VERSION 5.8 ;
BUSBITCHARS "[]" ;
DIVIDERCHAR "/" ;
UNITS
    DATABASE MICRONS 1000 ;
END UNITS

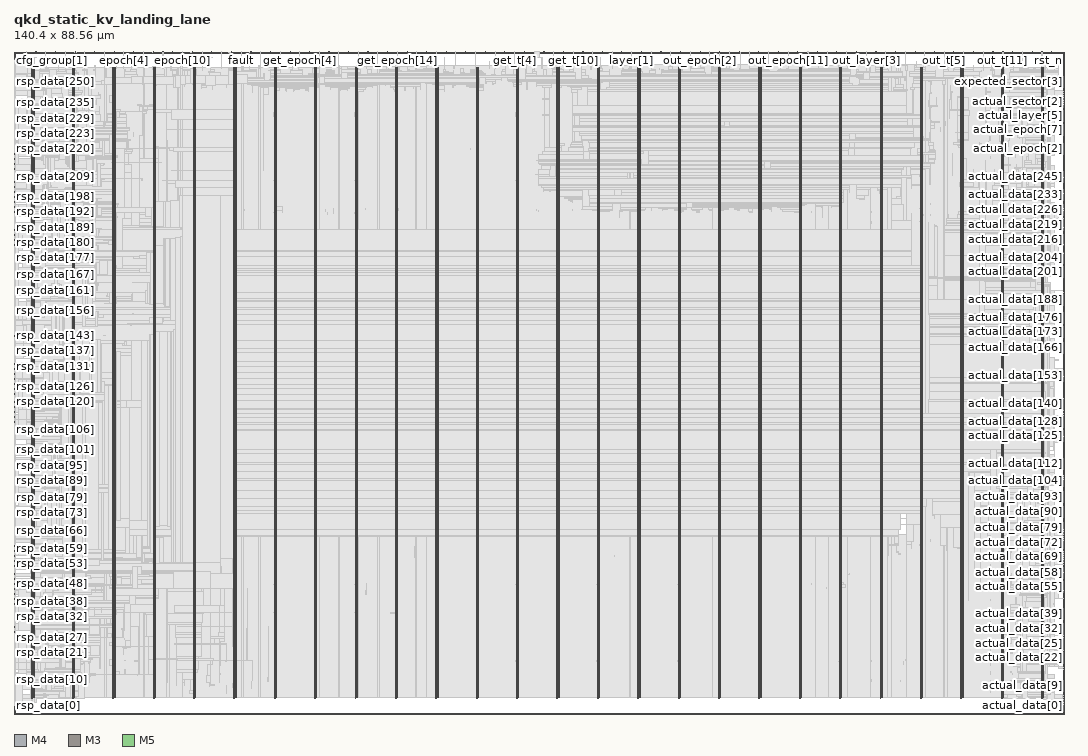
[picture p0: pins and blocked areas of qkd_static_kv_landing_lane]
MACRO qkd_static_kv_landing_lane
  FOREIGN qkd_static_kv_landing_lane 0 0 ;
  CLASS BLOCK ;
  SIZE 140.4 BY 88.56 ;
  PIN actual_data[0]
    DIRECTION INPUT ;
    USE SIGNAL ;
    PORT
      LAYER M4 ;
        RECT  140.316 1.152 140.4 1.176 ;
    END
  END actual_data[0]
  PIN actual_data[100]
    DIRECTION INPUT ;
    USE SIGNAL ;
    PORT
      LAYER M4 ;
        RECT  140.316 30 140.4 30.024 ;
    END
  END actual_data[100]
  PIN actual_data[101]
    DIRECTION INPUT ;
    USE SIGNAL ;
    PORT
      LAYER M4 ;
        RECT  140.316 30.288 140.4 30.312 ;
    END
  END actual_data[101]
  PIN actual_data[102]
    DIRECTION INPUT ;
    USE SIGNAL ;
    PORT
      LAYER M4 ;
        RECT  140.316 30.576 140.4 30.6 ;
    END
  END actual_data[102]
  PIN actual_data[103]
    DIRECTION INPUT ;
    USE SIGNAL ;
    PORT
      LAYER M4 ;
        RECT  140.316 30.864 140.4 30.888 ;
    END
  END actual_data[103]
  PIN actual_data[104]
    DIRECTION INPUT ;
    USE SIGNAL ;
    PORT
      LAYER M4 ;
        RECT  140.316 31.152 140.4 31.176 ;
    END
  END actual_data[104]
  PIN actual_data[105]
    DIRECTION INPUT ;
    USE SIGNAL ;
    PORT
      LAYER M4 ;
        RECT  140.316 31.44 140.4 31.464 ;
    END
  END actual_data[105]
  PIN actual_data[106]
    DIRECTION INPUT ;
    USE SIGNAL ;
    PORT
      LAYER M4 ;
        RECT  140.316 31.728 140.4 31.752 ;
    END
  END actual_data[106]
  PIN actual_data[107]
    DIRECTION INPUT ;
    USE SIGNAL ;
    PORT
      LAYER M4 ;
        RECT  140.316 32.016 140.4 32.04 ;
    END
  END actual_data[107]
  PIN actual_data[108]
    DIRECTION INPUT ;
    USE SIGNAL ;
    PORT
      LAYER M4 ;
        RECT  140.316 32.304 140.4 32.328 ;
    END
  END actual_data[108]
  PIN actual_data[109]
    DIRECTION INPUT ;
    USE SIGNAL ;
    PORT
      LAYER M4 ;
        RECT  140.316 32.592 140.4 32.616 ;
    END
  END actual_data[109]
  PIN actual_data[10]
    DIRECTION INPUT ;
    USE SIGNAL ;
    PORT
      LAYER M4 ;
        RECT  140.316 4.032 140.4 4.056 ;
    END
  END actual_data[10]
  PIN actual_data[110]
    DIRECTION INPUT ;
    USE SIGNAL ;
    PORT
      LAYER M4 ;
        RECT  140.316 32.88 140.4 32.904 ;
    END
  END actual_data[110]
  PIN actual_data[111]
    DIRECTION INPUT ;
    USE SIGNAL ;
    PORT
      LAYER M4 ;
        RECT  140.316 33.168 140.4 33.192 ;
    END
  END actual_data[111]
  PIN actual_data[112]
    DIRECTION INPUT ;
    USE SIGNAL ;
    PORT
      LAYER M4 ;
        RECT  140.316 33.456 140.4 33.48 ;
    END
  END actual_data[112]
  PIN actual_data[113]
    DIRECTION INPUT ;
    USE SIGNAL ;
    PORT
      LAYER M4 ;
        RECT  140.316 33.744 140.4 33.768 ;
    END
  END actual_data[113]
  PIN actual_data[114]
    DIRECTION INPUT ;
    USE SIGNAL ;
    PORT
      LAYER M4 ;
        RECT  140.316 34.032 140.4 34.056 ;
    END
  END actual_data[114]
  PIN actual_data[115]
    DIRECTION INPUT ;
    USE SIGNAL ;
    PORT
      LAYER M4 ;
        RECT  140.316 34.32 140.4 34.344 ;
    END
  END actual_data[115]
  PIN actual_data[116]
    DIRECTION INPUT ;
    USE SIGNAL ;
    PORT
      LAYER M4 ;
        RECT  140.316 34.608 140.4 34.632 ;
    END
  END actual_data[116]
  PIN actual_data[117]
    DIRECTION INPUT ;
    USE SIGNAL ;
    PORT
      LAYER M4 ;
        RECT  140.316 34.896 140.4 34.92 ;
    END
  END actual_data[117]
  PIN actual_data[118]
    DIRECTION INPUT ;
    USE SIGNAL ;
    PORT
      LAYER M4 ;
        RECT  140.316 35.184 140.4 35.208 ;
    END
  END actual_data[118]
  PIN actual_data[119]
    DIRECTION INPUT ;
    USE SIGNAL ;
    PORT
      LAYER M4 ;
        RECT  140.316 35.472 140.4 35.496 ;
    END
  END actual_data[119]
  PIN actual_data[11]
    DIRECTION INPUT ;
    USE SIGNAL ;
    PORT
      LAYER M4 ;
        RECT  140.316 4.32 140.4 4.344 ;
    END
  END actual_data[11]
  PIN actual_data[120]
    DIRECTION INPUT ;
    USE SIGNAL ;
    PORT
      LAYER M4 ;
        RECT  140.316 35.76 140.4 35.784 ;
    END
  END actual_data[120]
  PIN actual_data[121]
    DIRECTION INPUT ;
    USE SIGNAL ;
    PORT
      LAYER M4 ;
        RECT  140.316 36.048 140.4 36.072 ;
    END
  END actual_data[121]
  PIN actual_data[122]
    DIRECTION INPUT ;
    USE SIGNAL ;
    PORT
      LAYER M4 ;
        RECT  140.316 36.336 140.4 36.36 ;
    END
  END actual_data[122]
  PIN actual_data[123]
    DIRECTION INPUT ;
    USE SIGNAL ;
    PORT
      LAYER M4 ;
        RECT  140.316 36.624 140.4 36.648 ;
    END
  END actual_data[123]
  PIN actual_data[124]
    DIRECTION INPUT ;
    USE SIGNAL ;
    PORT
      LAYER M4 ;
        RECT  140.316 36.912 140.4 36.936 ;
    END
  END actual_data[124]
  PIN actual_data[125]
    DIRECTION INPUT ;
    USE SIGNAL ;
    PORT
      LAYER M4 ;
        RECT  140.316 37.2 140.4 37.224 ;
    END
  END actual_data[125]
  PIN actual_data[126]
    DIRECTION INPUT ;
    USE SIGNAL ;
    PORT
      LAYER M4 ;
        RECT  140.316 37.488 140.4 37.512 ;
    END
  END actual_data[126]
  PIN actual_data[127]
    DIRECTION INPUT ;
    USE SIGNAL ;
    PORT
      LAYER M4 ;
        RECT  140.316 37.776 140.4 37.8 ;
    END
  END actual_data[127]
  PIN actual_data[128]
    DIRECTION INPUT ;
    USE SIGNAL ;
    PORT
      LAYER M4 ;
        RECT  140.316 38.064 140.4 38.088 ;
    END
  END actual_data[128]
  PIN actual_data[129]
    DIRECTION INPUT ;
    USE SIGNAL ;
    PORT
      LAYER M4 ;
        RECT  140.316 38.352 140.4 38.376 ;
    END
  END actual_data[129]
  PIN actual_data[12]
    DIRECTION INPUT ;
    USE SIGNAL ;
    PORT
      LAYER M4 ;
        RECT  140.316 4.608 140.4 4.632 ;
    END
  END actual_data[12]
  PIN actual_data[130]
    DIRECTION INPUT ;
    USE SIGNAL ;
    PORT
      LAYER M4 ;
        RECT  140.316 38.64 140.4 38.664 ;
    END
  END actual_data[130]
  PIN actual_data[131]
    DIRECTION INPUT ;
    USE SIGNAL ;
    PORT
      LAYER M4 ;
        RECT  140.316 38.928 140.4 38.952 ;
    END
  END actual_data[131]
  PIN actual_data[132]
    DIRECTION INPUT ;
    USE SIGNAL ;
    PORT
      LAYER M4 ;
        RECT  140.316 39.216 140.4 39.24 ;
    END
  END actual_data[132]
  PIN actual_data[133]
    DIRECTION INPUT ;
    USE SIGNAL ;
    PORT
      LAYER M4 ;
        RECT  140.316 39.504 140.4 39.528 ;
    END
  END actual_data[133]
  PIN actual_data[134]
    DIRECTION INPUT ;
    USE SIGNAL ;
    PORT
      LAYER M4 ;
        RECT  140.316 39.792 140.4 39.816 ;
    END
  END actual_data[134]
  PIN actual_data[135]
    DIRECTION INPUT ;
    USE SIGNAL ;
    PORT
      LAYER M4 ;
        RECT  140.316 40.08 140.4 40.104 ;
    END
  END actual_data[135]
  PIN actual_data[136]
    DIRECTION INPUT ;
    USE SIGNAL ;
    PORT
      LAYER M4 ;
        RECT  140.316 40.368 140.4 40.392 ;
    END
  END actual_data[136]
  PIN actual_data[137]
    DIRECTION INPUT ;
    USE SIGNAL ;
    PORT
      LAYER M4 ;
        RECT  140.316 40.656 140.4 40.68 ;
    END
  END actual_data[137]
  PIN actual_data[138]
    DIRECTION INPUT ;
    USE SIGNAL ;
    PORT
      LAYER M4 ;
        RECT  140.316 40.944 140.4 40.968 ;
    END
  END actual_data[138]
  PIN actual_data[139]
    DIRECTION INPUT ;
    USE SIGNAL ;
    PORT
      LAYER M4 ;
        RECT  140.316 41.232 140.4 41.256 ;
    END
  END actual_data[139]
  PIN actual_data[13]
    DIRECTION INPUT ;
    USE SIGNAL ;
    PORT
      LAYER M4 ;
        RECT  140.316 4.896 140.4 4.92 ;
    END
  END actual_data[13]
  PIN actual_data[140]
    DIRECTION INPUT ;
    USE SIGNAL ;
    PORT
      LAYER M4 ;
        RECT  140.316 41.52 140.4 41.544 ;
    END
  END actual_data[140]
  PIN actual_data[141]
    DIRECTION INPUT ;
    USE SIGNAL ;
    PORT
      LAYER M4 ;
        RECT  140.316 41.808 140.4 41.832 ;
    END
  END actual_data[141]
  PIN actual_data[142]
    DIRECTION INPUT ;
    USE SIGNAL ;
    PORT
      LAYER M4 ;
        RECT  140.316 42.096 140.4 42.12 ;
    END
  END actual_data[142]
  PIN actual_data[143]
    DIRECTION INPUT ;
    USE SIGNAL ;
    PORT
      LAYER M4 ;
        RECT  140.316 42.384 140.4 42.408 ;
    END
  END actual_data[143]
  PIN actual_data[144]
    DIRECTION INPUT ;
    USE SIGNAL ;
    PORT
      LAYER M4 ;
        RECT  140.316 42.672 140.4 42.696 ;
    END
  END actual_data[144]
  PIN actual_data[145]
    DIRECTION INPUT ;
    USE SIGNAL ;
    PORT
      LAYER M4 ;
        RECT  140.316 42.96 140.4 42.984 ;
    END
  END actual_data[145]
  PIN actual_data[146]
    DIRECTION INPUT ;
    USE SIGNAL ;
    PORT
      LAYER M4 ;
        RECT  140.316 43.248 140.4 43.272 ;
    END
  END actual_data[146]
  PIN actual_data[147]
    DIRECTION INPUT ;
    USE SIGNAL ;
    PORT
      LAYER M4 ;
        RECT  140.316 43.536 140.4 43.56 ;
    END
  END actual_data[147]
  PIN actual_data[148]
    DIRECTION INPUT ;
    USE SIGNAL ;
    PORT
      LAYER M4 ;
        RECT  140.316 43.824 140.4 43.848 ;
    END
  END actual_data[148]
  PIN actual_data[149]
    DIRECTION INPUT ;
    USE SIGNAL ;
    PORT
      LAYER M4 ;
        RECT  140.316 44.112 140.4 44.136 ;
    END
  END actual_data[149]
  PIN actual_data[14]
    DIRECTION INPUT ;
    USE SIGNAL ;
    PORT
      LAYER M4 ;
        RECT  140.316 5.184 140.4 5.208 ;
    END
  END actual_data[14]
  PIN actual_data[150]
    DIRECTION INPUT ;
    USE SIGNAL ;
    PORT
      LAYER M4 ;
        RECT  140.316 44.4 140.4 44.424 ;
    END
  END actual_data[150]
  PIN actual_data[151]
    DIRECTION INPUT ;
    USE SIGNAL ;
    PORT
      LAYER M4 ;
        RECT  140.316 44.688 140.4 44.712 ;
    END
  END actual_data[151]
  PIN actual_data[152]
    DIRECTION INPUT ;
    USE SIGNAL ;
    PORT
      LAYER M4 ;
        RECT  140.316 44.976 140.4 45 ;
    END
  END actual_data[152]
  PIN actual_data[153]
    DIRECTION INPUT ;
    USE SIGNAL ;
    PORT
      LAYER M4 ;
        RECT  140.316 45.264 140.4 45.288 ;
    END
  END actual_data[153]
  PIN actual_data[154]
    DIRECTION INPUT ;
    USE SIGNAL ;
    PORT
      LAYER M4 ;
        RECT  140.316 45.552 140.4 45.576 ;
    END
  END actual_data[154]
  PIN actual_data[155]
    DIRECTION INPUT ;
    USE SIGNAL ;
    PORT
      LAYER M4 ;
        RECT  140.316 45.84 140.4 45.864 ;
    END
  END actual_data[155]
  PIN actual_data[156]
    DIRECTION INPUT ;
    USE SIGNAL ;
    PORT
      LAYER M4 ;
        RECT  140.316 46.128 140.4 46.152 ;
    END
  END actual_data[156]
  PIN actual_data[157]
    DIRECTION INPUT ;
    USE SIGNAL ;
    PORT
      LAYER M4 ;
        RECT  140.316 46.416 140.4 46.44 ;
    END
  END actual_data[157]
  PIN actual_data[158]
    DIRECTION INPUT ;
    USE SIGNAL ;
    PORT
      LAYER M4 ;
        RECT  140.316 46.704 140.4 46.728 ;
    END
  END actual_data[158]
  PIN actual_data[159]
    DIRECTION INPUT ;
    USE SIGNAL ;
    PORT
      LAYER M4 ;
        RECT  140.316 46.992 140.4 47.016 ;
    END
  END actual_data[159]
  PIN actual_data[15]
    DIRECTION INPUT ;
    USE SIGNAL ;
    PORT
      LAYER M4 ;
        RECT  140.316 5.472 140.4 5.496 ;
    END
  END actual_data[15]
  PIN actual_data[160]
    DIRECTION INPUT ;
    USE SIGNAL ;
    PORT
      LAYER M4 ;
        RECT  140.316 47.28 140.4 47.304 ;
    END
  END actual_data[160]
  PIN actual_data[161]
    DIRECTION INPUT ;
    USE SIGNAL ;
    PORT
      LAYER M4 ;
        RECT  140.316 47.568 140.4 47.592 ;
    END
  END actual_data[161]
  PIN actual_data[162]
    DIRECTION INPUT ;
    USE SIGNAL ;
    PORT
      LAYER M4 ;
        RECT  140.316 47.856 140.4 47.88 ;
    END
  END actual_data[162]
  PIN actual_data[163]
    DIRECTION INPUT ;
    USE SIGNAL ;
    PORT
      LAYER M4 ;
        RECT  140.316 48.144 140.4 48.168 ;
    END
  END actual_data[163]
  PIN actual_data[164]
    DIRECTION INPUT ;
    USE SIGNAL ;
    PORT
      LAYER M4 ;
        RECT  140.316 48.432 140.4 48.456 ;
    END
  END actual_data[164]
  PIN actual_data[165]
    DIRECTION INPUT ;
    USE SIGNAL ;
    PORT
      LAYER M4 ;
        RECT  140.316 48.72 140.4 48.744 ;
    END
  END actual_data[165]
  PIN actual_data[166]
    DIRECTION INPUT ;
    USE SIGNAL ;
    PORT
      LAYER M4 ;
        RECT  140.316 49.008 140.4 49.032 ;
    END
  END actual_data[166]
  PIN actual_data[167]
    DIRECTION INPUT ;
    USE SIGNAL ;
    PORT
      LAYER M4 ;
        RECT  140.316 49.296 140.4 49.32 ;
    END
  END actual_data[167]
  PIN actual_data[168]
    DIRECTION INPUT ;
    USE SIGNAL ;
    PORT
      LAYER M4 ;
        RECT  140.316 49.584 140.4 49.608 ;
    END
  END actual_data[168]
  PIN actual_data[169]
    DIRECTION INPUT ;
    USE SIGNAL ;
    PORT
      LAYER M4 ;
        RECT  140.316 49.872 140.4 49.896 ;
    END
  END actual_data[169]
  PIN actual_data[16]
    DIRECTION INPUT ;
    USE SIGNAL ;
    PORT
      LAYER M4 ;
        RECT  140.316 5.76 140.4 5.784 ;
    END
  END actual_data[16]
  PIN actual_data[170]
    DIRECTION INPUT ;
    USE SIGNAL ;
    PORT
      LAYER M4 ;
        RECT  140.316 50.16 140.4 50.184 ;
    END
  END actual_data[170]
  PIN actual_data[171]
    DIRECTION INPUT ;
    USE SIGNAL ;
    PORT
      LAYER M4 ;
        RECT  140.316 50.448 140.4 50.472 ;
    END
  END actual_data[171]
  PIN actual_data[172]
    DIRECTION INPUT ;
    USE SIGNAL ;
    PORT
      LAYER M4 ;
        RECT  140.316 50.784 140.4 50.808 ;
    END
  END actual_data[172]
  PIN actual_data[173]
    DIRECTION INPUT ;
    USE SIGNAL ;
    PORT
      LAYER M4 ;
        RECT  140.316 51.072 140.4 51.096 ;
    END
  END actual_data[173]
  PIN actual_data[174]
    DIRECTION INPUT ;
    USE SIGNAL ;
    PORT
      LAYER M4 ;
        RECT  140.316 51.36 140.4 51.384 ;
    END
  END actual_data[174]
  PIN actual_data[175]
    DIRECTION INPUT ;
    USE SIGNAL ;
    PORT
      LAYER M4 ;
        RECT  140.316 51.648 140.4 51.672 ;
    END
  END actual_data[175]
  PIN actual_data[176]
    DIRECTION INPUT ;
    USE SIGNAL ;
    PORT
      LAYER M4 ;
        RECT  140.316 51.936 140.4 51.96 ;
    END
  END actual_data[176]
  PIN actual_data[177]
    DIRECTION INPUT ;
    USE SIGNAL ;
    PORT
      LAYER M4 ;
        RECT  140.316 52.224 140.4 52.248 ;
    END
  END actual_data[177]
  PIN actual_data[178]
    DIRECTION INPUT ;
    USE SIGNAL ;
    PORT
      LAYER M4 ;
        RECT  140.316 52.512 140.4 52.536 ;
    END
  END actual_data[178]
  PIN actual_data[179]
    DIRECTION INPUT ;
    USE SIGNAL ;
    PORT
      LAYER M4 ;
        RECT  140.316 52.8 140.4 52.824 ;
    END
  END actual_data[179]
  PIN actual_data[17]
    DIRECTION INPUT ;
    USE SIGNAL ;
    PORT
      LAYER M4 ;
        RECT  140.316 6.048 140.4 6.072 ;
    END
  END actual_data[17]
  PIN actual_data[180]
    DIRECTION INPUT ;
    USE SIGNAL ;
    PORT
      LAYER M4 ;
        RECT  140.316 53.088 140.4 53.112 ;
    END
  END actual_data[180]
  PIN actual_data[181]
    DIRECTION INPUT ;
    USE SIGNAL ;
    PORT
      LAYER M4 ;
        RECT  140.316 53.376 140.4 53.4 ;
    END
  END actual_data[181]
  PIN actual_data[182]
    DIRECTION INPUT ;
    USE SIGNAL ;
    PORT
      LAYER M4 ;
        RECT  140.316 53.664 140.4 53.688 ;
    END
  END actual_data[182]
  PIN actual_data[183]
    DIRECTION INPUT ;
    USE SIGNAL ;
    PORT
      LAYER M4 ;
        RECT  140.316 53.952 140.4 53.976 ;
    END
  END actual_data[183]
  PIN actual_data[184]
    DIRECTION INPUT ;
    USE SIGNAL ;
    PORT
      LAYER M4 ;
        RECT  140.316 54.24 140.4 54.264 ;
    END
  END actual_data[184]
  PIN actual_data[185]
    DIRECTION INPUT ;
    USE SIGNAL ;
    PORT
      LAYER M4 ;
        RECT  140.316 54.528 140.4 54.552 ;
    END
  END actual_data[185]
  PIN actual_data[186]
    DIRECTION INPUT ;
    USE SIGNAL ;
    PORT
      LAYER M4 ;
        RECT  140.316 54.816 140.4 54.84 ;
    END
  END actual_data[186]
  PIN actual_data[187]
    DIRECTION INPUT ;
    USE SIGNAL ;
    PORT
      LAYER M4 ;
        RECT  140.316 55.104 140.4 55.128 ;
    END
  END actual_data[187]
  PIN actual_data[188]
    DIRECTION INPUT ;
    USE SIGNAL ;
    PORT
      LAYER M4 ;
        RECT  140.316 55.392 140.4 55.416 ;
    END
  END actual_data[188]
  PIN actual_data[189]
    DIRECTION INPUT ;
    USE SIGNAL ;
    PORT
      LAYER M4 ;
        RECT  140.316 55.68 140.4 55.704 ;
    END
  END actual_data[189]
  PIN actual_data[18]
    DIRECTION INPUT ;
    USE SIGNAL ;
    PORT
      LAYER M4 ;
        RECT  140.316 6.336 140.4 6.36 ;
    END
  END actual_data[18]
  PIN actual_data[190]
    DIRECTION INPUT ;
    USE SIGNAL ;
    PORT
      LAYER M4 ;
        RECT  140.316 55.968 140.4 55.992 ;
    END
  END actual_data[190]
  PIN actual_data[191]
    DIRECTION INPUT ;
    USE SIGNAL ;
    PORT
      LAYER M4 ;
        RECT  140.316 56.256 140.4 56.28 ;
    END
  END actual_data[191]
  PIN actual_data[192]
    DIRECTION INPUT ;
    USE SIGNAL ;
    PORT
      LAYER M4 ;
        RECT  140.316 56.544 140.4 56.568 ;
    END
  END actual_data[192]
  PIN actual_data[193]
    DIRECTION INPUT ;
    USE SIGNAL ;
    PORT
      LAYER M4 ;
        RECT  140.316 56.832 140.4 56.856 ;
    END
  END actual_data[193]
  PIN actual_data[194]
    DIRECTION INPUT ;
    USE SIGNAL ;
    PORT
      LAYER M4 ;
        RECT  140.316 57.12 140.4 57.144 ;
    END
  END actual_data[194]
  PIN actual_data[195]
    DIRECTION INPUT ;
    USE SIGNAL ;
    PORT
      LAYER M4 ;
        RECT  140.316 57.408 140.4 57.432 ;
    END
  END actual_data[195]
  PIN actual_data[196]
    DIRECTION INPUT ;
    USE SIGNAL ;
    PORT
      LAYER M4 ;
        RECT  140.316 57.696 140.4 57.72 ;
    END
  END actual_data[196]
  PIN actual_data[197]
    DIRECTION INPUT ;
    USE SIGNAL ;
    PORT
      LAYER M4 ;
        RECT  140.316 57.984 140.4 58.008 ;
    END
  END actual_data[197]
  PIN actual_data[198]
    DIRECTION INPUT ;
    USE SIGNAL ;
    PORT
      LAYER M4 ;
        RECT  140.316 58.272 140.4 58.296 ;
    END
  END actual_data[198]
  PIN actual_data[199]
    DIRECTION INPUT ;
    USE SIGNAL ;
    PORT
      LAYER M4 ;
        RECT  140.316 58.56 140.4 58.584 ;
    END
  END actual_data[199]
  PIN actual_data[19]
    DIRECTION INPUT ;
    USE SIGNAL ;
    PORT
      LAYER M4 ;
        RECT  140.316 6.624 140.4 6.648 ;
    END
  END actual_data[19]
  PIN actual_data[1]
    DIRECTION INPUT ;
    USE SIGNAL ;
    PORT
      LAYER M4 ;
        RECT  140.316 1.44 140.4 1.464 ;
    END
  END actual_data[1]
  PIN actual_data[200]
    DIRECTION INPUT ;
    USE SIGNAL ;
    PORT
      LAYER M4 ;
        RECT  140.316 58.848 140.4 58.872 ;
    END
  END actual_data[200]
  PIN actual_data[201]
    DIRECTION INPUT ;
    USE SIGNAL ;
    PORT
      LAYER M4 ;
        RECT  140.316 59.136 140.4 59.16 ;
    END
  END actual_data[201]
  PIN actual_data[202]
    DIRECTION INPUT ;
    USE SIGNAL ;
    PORT
      LAYER M4 ;
        RECT  140.316 59.424 140.4 59.448 ;
    END
  END actual_data[202]
  PIN actual_data[203]
    DIRECTION INPUT ;
    USE SIGNAL ;
    PORT
      LAYER M4 ;
        RECT  140.316 59.712 140.4 59.736 ;
    END
  END actual_data[203]
  PIN actual_data[204]
    DIRECTION INPUT ;
    USE SIGNAL ;
    PORT
      LAYER M4 ;
        RECT  140.316 60 140.4 60.024 ;
    END
  END actual_data[204]
  PIN actual_data[205]
    DIRECTION INPUT ;
    USE SIGNAL ;
    PORT
      LAYER M4 ;
        RECT  140.316 60.288 140.4 60.312 ;
    END
  END actual_data[205]
  PIN actual_data[206]
    DIRECTION INPUT ;
    USE SIGNAL ;
    PORT
      LAYER M4 ;
        RECT  140.316 60.576 140.4 60.6 ;
    END
  END actual_data[206]
  PIN actual_data[207]
    DIRECTION INPUT ;
    USE SIGNAL ;
    PORT
      LAYER M4 ;
        RECT  140.316 60.864 140.4 60.888 ;
    END
  END actual_data[207]
  PIN actual_data[208]
    DIRECTION INPUT ;
    USE SIGNAL ;
    PORT
      LAYER M4 ;
        RECT  140.316 61.152 140.4 61.176 ;
    END
  END actual_data[208]
  PIN actual_data[209]
    DIRECTION INPUT ;
    USE SIGNAL ;
    PORT
      LAYER M4 ;
        RECT  140.316 61.44 140.4 61.464 ;
    END
  END actual_data[209]
  PIN actual_data[20]
    DIRECTION INPUT ;
    USE SIGNAL ;
    PORT
      LAYER M4 ;
        RECT  140.316 6.912 140.4 6.936 ;
    END
  END actual_data[20]
  PIN actual_data[210]
    DIRECTION INPUT ;
    USE SIGNAL ;
    PORT
      LAYER M4 ;
        RECT  140.316 61.728 140.4 61.752 ;
    END
  END actual_data[210]
  PIN actual_data[211]
    DIRECTION INPUT ;
    USE SIGNAL ;
    PORT
      LAYER M4 ;
        RECT  140.316 62.016 140.4 62.04 ;
    END
  END actual_data[211]
  PIN actual_data[212]
    DIRECTION INPUT ;
    USE SIGNAL ;
    PORT
      LAYER M4 ;
        RECT  140.316 62.304 140.4 62.328 ;
    END
  END actual_data[212]
  PIN actual_data[213]
    DIRECTION INPUT ;
    USE SIGNAL ;
    PORT
      LAYER M4 ;
        RECT  140.316 62.592 140.4 62.616 ;
    END
  END actual_data[213]
  PIN actual_data[214]
    DIRECTION INPUT ;
    USE SIGNAL ;
    PORT
      LAYER M4 ;
        RECT  140.316 62.88 140.4 62.904 ;
    END
  END actual_data[214]
  PIN actual_data[215]
    DIRECTION INPUT ;
    USE SIGNAL ;
    PORT
      LAYER M4 ;
        RECT  140.316 63.168 140.4 63.192 ;
    END
  END actual_data[215]
  PIN actual_data[216]
    DIRECTION INPUT ;
    USE SIGNAL ;
    PORT
      LAYER M4 ;
        RECT  140.316 63.456 140.4 63.48 ;
    END
  END actual_data[216]
  PIN actual_data[217]
    DIRECTION INPUT ;
    USE SIGNAL ;
    PORT
      LAYER M4 ;
        RECT  140.316 63.744 140.4 63.768 ;
    END
  END actual_data[217]
  PIN actual_data[218]
    DIRECTION INPUT ;
    USE SIGNAL ;
    PORT
      LAYER M4 ;
        RECT  140.316 64.032 140.4 64.056 ;
    END
  END actual_data[218]
  PIN actual_data[219]
    DIRECTION INPUT ;
    USE SIGNAL ;
    PORT
      LAYER M4 ;
        RECT  140.316 64.32 140.4 64.344 ;
    END
  END actual_data[219]
  PIN actual_data[21]
    DIRECTION INPUT ;
    USE SIGNAL ;
    PORT
      LAYER M4 ;
        RECT  140.316 7.2 140.4 7.224 ;
    END
  END actual_data[21]
  PIN actual_data[220]
    DIRECTION INPUT ;
    USE SIGNAL ;
    PORT
      LAYER M4 ;
        RECT  140.316 64.608 140.4 64.632 ;
    END
  END actual_data[220]
  PIN actual_data[221]
    DIRECTION INPUT ;
    USE SIGNAL ;
    PORT
      LAYER M4 ;
        RECT  140.316 64.896 140.4 64.92 ;
    END
  END actual_data[221]
  PIN actual_data[222]
    DIRECTION INPUT ;
    USE SIGNAL ;
    PORT
      LAYER M4 ;
        RECT  140.316 65.184 140.4 65.208 ;
    END
  END actual_data[222]
  PIN actual_data[223]
    DIRECTION INPUT ;
    USE SIGNAL ;
    PORT
      LAYER M4 ;
        RECT  140.316 65.472 140.4 65.496 ;
    END
  END actual_data[223]
  PIN actual_data[224]
    DIRECTION INPUT ;
    USE SIGNAL ;
    PORT
      LAYER M4 ;
        RECT  140.316 65.76 140.4 65.784 ;
    END
  END actual_data[224]
  PIN actual_data[225]
    DIRECTION INPUT ;
    USE SIGNAL ;
    PORT
      LAYER M4 ;
        RECT  140.316 66.048 140.4 66.072 ;
    END
  END actual_data[225]
  PIN actual_data[226]
    DIRECTION INPUT ;
    USE SIGNAL ;
    PORT
      LAYER M4 ;
        RECT  140.316 66.336 140.4 66.36 ;
    END
  END actual_data[226]
  PIN actual_data[227]
    DIRECTION INPUT ;
    USE SIGNAL ;
    PORT
      LAYER M4 ;
        RECT  140.316 66.624 140.4 66.648 ;
    END
  END actual_data[227]
  PIN actual_data[228]
    DIRECTION INPUT ;
    USE SIGNAL ;
    PORT
      LAYER M4 ;
        RECT  140.316 66.912 140.4 66.936 ;
    END
  END actual_data[228]
  PIN actual_data[229]
    DIRECTION INPUT ;
    USE SIGNAL ;
    PORT
      LAYER M4 ;
        RECT  140.316 67.2 140.4 67.224 ;
    END
  END actual_data[229]
  PIN actual_data[22]
    DIRECTION INPUT ;
    USE SIGNAL ;
    PORT
      LAYER M4 ;
        RECT  140.316 7.488 140.4 7.512 ;
    END
  END actual_data[22]
  PIN actual_data[230]
    DIRECTION INPUT ;
    USE SIGNAL ;
    PORT
      LAYER M4 ;
        RECT  140.316 67.488 140.4 67.512 ;
    END
  END actual_data[230]
  PIN actual_data[231]
    DIRECTION INPUT ;
    USE SIGNAL ;
    PORT
      LAYER M4 ;
        RECT  140.316 67.776 140.4 67.8 ;
    END
  END actual_data[231]
  PIN actual_data[232]
    DIRECTION INPUT ;
    USE SIGNAL ;
    PORT
      LAYER M4 ;
        RECT  140.316 68.064 140.4 68.088 ;
    END
  END actual_data[232]
  PIN actual_data[233]
    DIRECTION INPUT ;
    USE SIGNAL ;
    PORT
      LAYER M4 ;
        RECT  140.316 68.352 140.4 68.376 ;
    END
  END actual_data[233]
  PIN actual_data[234]
    DIRECTION INPUT ;
    USE SIGNAL ;
    PORT
      LAYER M4 ;
        RECT  140.316 68.64 140.4 68.664 ;
    END
  END actual_data[234]
  PIN actual_data[235]
    DIRECTION INPUT ;
    USE SIGNAL ;
    PORT
      LAYER M4 ;
        RECT  140.316 68.928 140.4 68.952 ;
    END
  END actual_data[235]
  PIN actual_data[236]
    DIRECTION INPUT ;
    USE SIGNAL ;
    PORT
      LAYER M4 ;
        RECT  140.316 69.216 140.4 69.24 ;
    END
  END actual_data[236]
  PIN actual_data[237]
    DIRECTION INPUT ;
    USE SIGNAL ;
    PORT
      LAYER M4 ;
        RECT  140.316 69.504 140.4 69.528 ;
    END
  END actual_data[237]
  PIN actual_data[238]
    DIRECTION INPUT ;
    USE SIGNAL ;
    PORT
      LAYER M4 ;
        RECT  140.316 69.792 140.4 69.816 ;
    END
  END actual_data[238]
  PIN actual_data[239]
    DIRECTION INPUT ;
    USE SIGNAL ;
    PORT
      LAYER M4 ;
        RECT  140.316 70.08 140.4 70.104 ;
    END
  END actual_data[239]
  PIN actual_data[23]
    DIRECTION INPUT ;
    USE SIGNAL ;
    PORT
      LAYER M4 ;
        RECT  140.316 7.776 140.4 7.8 ;
    END
  END actual_data[23]
  PIN actual_data[240]
    DIRECTION INPUT ;
    USE SIGNAL ;
    PORT
      LAYER M4 ;
        RECT  140.316 70.368 140.4 70.392 ;
    END
  END actual_data[240]
  PIN actual_data[241]
    DIRECTION INPUT ;
    USE SIGNAL ;
    PORT
      LAYER M4 ;
        RECT  140.316 70.656 140.4 70.68 ;
    END
  END actual_data[241]
  PIN actual_data[242]
    DIRECTION INPUT ;
    USE SIGNAL ;
    PORT
      LAYER M4 ;
        RECT  140.316 70.944 140.4 70.968 ;
    END
  END actual_data[242]
  PIN actual_data[243]
    DIRECTION INPUT ;
    USE SIGNAL ;
    PORT
      LAYER M4 ;
        RECT  140.316 71.232 140.4 71.256 ;
    END
  END actual_data[243]
  PIN actual_data[244]
    DIRECTION INPUT ;
    USE SIGNAL ;
    PORT
      LAYER M4 ;
        RECT  140.316 71.52 140.4 71.544 ;
    END
  END actual_data[244]
  PIN actual_data[245]
    DIRECTION INPUT ;
    USE SIGNAL ;
    PORT
      LAYER M4 ;
        RECT  140.316 71.808 140.4 71.832 ;
    END
  END actual_data[245]
  PIN actual_data[246]
    DIRECTION INPUT ;
    USE SIGNAL ;
    PORT
      LAYER M4 ;
        RECT  140.316 72.096 140.4 72.12 ;
    END
  END actual_data[246]
  PIN actual_data[247]
    DIRECTION INPUT ;
    USE SIGNAL ;
    PORT
      LAYER M4 ;
        RECT  140.316 72.384 140.4 72.408 ;
    END
  END actual_data[247]
  PIN actual_data[248]
    DIRECTION INPUT ;
    USE SIGNAL ;
    PORT
      LAYER M4 ;
        RECT  140.316 72.672 140.4 72.696 ;
    END
  END actual_data[248]
  PIN actual_data[249]
    DIRECTION INPUT ;
    USE SIGNAL ;
    PORT
      LAYER M4 ;
        RECT  140.316 72.96 140.4 72.984 ;
    END
  END actual_data[249]
  PIN actual_data[24]
    DIRECTION INPUT ;
    USE SIGNAL ;
    PORT
      LAYER M4 ;
        RECT  140.316 8.064 140.4 8.088 ;
    END
  END actual_data[24]
  PIN actual_data[250]
    DIRECTION INPUT ;
    USE SIGNAL ;
    PORT
      LAYER M4 ;
        RECT  140.316 73.248 140.4 73.272 ;
    END
  END actual_data[250]
  PIN actual_data[251]
    DIRECTION INPUT ;
    USE SIGNAL ;
    PORT
      LAYER M4 ;
        RECT  140.316 73.536 140.4 73.56 ;
    END
  END actual_data[251]
  PIN actual_data[252]
    DIRECTION INPUT ;
    USE SIGNAL ;
    PORT
      LAYER M4 ;
        RECT  140.316 73.824 140.4 73.848 ;
    END
  END actual_data[252]
  PIN actual_data[253]
    DIRECTION INPUT ;
    USE SIGNAL ;
    PORT
      LAYER M4 ;
        RECT  140.316 74.112 140.4 74.136 ;
    END
  END actual_data[253]
  PIN actual_data[254]
    DIRECTION INPUT ;
    USE SIGNAL ;
    PORT
      LAYER M4 ;
        RECT  140.316 74.4 140.4 74.424 ;
    END
  END actual_data[254]
  PIN actual_data[255]
    DIRECTION INPUT ;
    USE SIGNAL ;
    PORT
      LAYER M4 ;
        RECT  140.316 74.688 140.4 74.712 ;
    END
  END actual_data[255]
  PIN actual_data[25]
    DIRECTION INPUT ;
    USE SIGNAL ;
    PORT
      LAYER M4 ;
        RECT  140.316 8.352 140.4 8.376 ;
    END
  END actual_data[25]
  PIN actual_data[26]
    DIRECTION INPUT ;
    USE SIGNAL ;
    PORT
      LAYER M4 ;
        RECT  140.316 8.64 140.4 8.664 ;
    END
  END actual_data[26]
  PIN actual_data[27]
    DIRECTION INPUT ;
    USE SIGNAL ;
    PORT
      LAYER M4 ;
        RECT  140.316 8.928 140.4 8.952 ;
    END
  END actual_data[27]
  PIN actual_data[28]
    DIRECTION INPUT ;
    USE SIGNAL ;
    PORT
      LAYER M4 ;
        RECT  140.316 9.216 140.4 9.24 ;
    END
  END actual_data[28]
  PIN actual_data[29]
    DIRECTION INPUT ;
    USE SIGNAL ;
    PORT
      LAYER M4 ;
        RECT  140.316 9.504 140.4 9.528 ;
    END
  END actual_data[29]
  PIN actual_data[2]
    DIRECTION INPUT ;
    USE SIGNAL ;
    PORT
      LAYER M4 ;
        RECT  140.316 1.728 140.4 1.752 ;
    END
  END actual_data[2]
  PIN actual_data[30]
    DIRECTION INPUT ;
    USE SIGNAL ;
    PORT
      LAYER M4 ;
        RECT  140.316 9.792 140.4 9.816 ;
    END
  END actual_data[30]
  PIN actual_data[31]
    DIRECTION INPUT ;
    USE SIGNAL ;
    PORT
      LAYER M4 ;
        RECT  140.316 10.08 140.4 10.104 ;
    END
  END actual_data[31]
  PIN actual_data[32]
    DIRECTION INPUT ;
    USE SIGNAL ;
    PORT
      LAYER M4 ;
        RECT  140.316 10.368 140.4 10.392 ;
    END
  END actual_data[32]
  PIN actual_data[33]
    DIRECTION INPUT ;
    USE SIGNAL ;
    PORT
      LAYER M4 ;
        RECT  140.316 10.656 140.4 10.68 ;
    END
  END actual_data[33]
  PIN actual_data[34]
    DIRECTION INPUT ;
    USE SIGNAL ;
    PORT
      LAYER M4 ;
        RECT  140.316 10.944 140.4 10.968 ;
    END
  END actual_data[34]
  PIN actual_data[35]
    DIRECTION INPUT ;
    USE SIGNAL ;
    PORT
      LAYER M4 ;
        RECT  140.316 11.232 140.4 11.256 ;
    END
  END actual_data[35]
  PIN actual_data[36]
    DIRECTION INPUT ;
    USE SIGNAL ;
    PORT
      LAYER M4 ;
        RECT  140.316 11.52 140.4 11.544 ;
    END
  END actual_data[36]
  PIN actual_data[37]
    DIRECTION INPUT ;
    USE SIGNAL ;
    PORT
      LAYER M4 ;
        RECT  140.316 11.808 140.4 11.832 ;
    END
  END actual_data[37]
  PIN actual_data[38]
    DIRECTION INPUT ;
    USE SIGNAL ;
    PORT
      LAYER M4 ;
        RECT  140.316 12.096 140.4 12.12 ;
    END
  END actual_data[38]
  PIN actual_data[39]
    DIRECTION INPUT ;
    USE SIGNAL ;
    PORT
      LAYER M4 ;
        RECT  140.316 12.384 140.4 12.408 ;
    END
  END actual_data[39]
  PIN actual_data[3]
    DIRECTION INPUT ;
    USE SIGNAL ;
    PORT
      LAYER M4 ;
        RECT  140.316 2.016 140.4 2.04 ;
    END
  END actual_data[3]
  PIN actual_data[40]
    DIRECTION INPUT ;
    USE SIGNAL ;
    PORT
      LAYER M4 ;
        RECT  140.316 12.672 140.4 12.696 ;
    END
  END actual_data[40]
  PIN actual_data[41]
    DIRECTION INPUT ;
    USE SIGNAL ;
    PORT
      LAYER M4 ;
        RECT  140.316 12.96 140.4 12.984 ;
    END
  END actual_data[41]
  PIN actual_data[42]
    DIRECTION INPUT ;
    USE SIGNAL ;
    PORT
      LAYER M4 ;
        RECT  140.316 13.248 140.4 13.272 ;
    END
  END actual_data[42]
  PIN actual_data[43]
    DIRECTION INPUT ;
    USE SIGNAL ;
    PORT
      LAYER M4 ;
        RECT  140.316 13.536 140.4 13.56 ;
    END
  END actual_data[43]
  PIN actual_data[44]
    DIRECTION INPUT ;
    USE SIGNAL ;
    PORT
      LAYER M4 ;
        RECT  140.316 13.824 140.4 13.848 ;
    END
  END actual_data[44]
  PIN actual_data[45]
    DIRECTION INPUT ;
    USE SIGNAL ;
    PORT
      LAYER M4 ;
        RECT  140.316 14.112 140.4 14.136 ;
    END
  END actual_data[45]
  PIN actual_data[46]
    DIRECTION INPUT ;
    USE SIGNAL ;
    PORT
      LAYER M4 ;
        RECT  140.316 14.4 140.4 14.424 ;
    END
  END actual_data[46]
  PIN actual_data[47]
    DIRECTION INPUT ;
    USE SIGNAL ;
    PORT
      LAYER M4 ;
        RECT  140.316 14.688 140.4 14.712 ;
    END
  END actual_data[47]
  PIN actual_data[48]
    DIRECTION INPUT ;
    USE SIGNAL ;
    PORT
      LAYER M4 ;
        RECT  140.316 14.976 140.4 15 ;
    END
  END actual_data[48]
  PIN actual_data[49]
    DIRECTION INPUT ;
    USE SIGNAL ;
    PORT
      LAYER M4 ;
        RECT  140.316 15.264 140.4 15.288 ;
    END
  END actual_data[49]
  PIN actual_data[4]
    DIRECTION INPUT ;
    USE SIGNAL ;
    PORT
      LAYER M4 ;
        RECT  140.316 2.304 140.4 2.328 ;
    END
  END actual_data[4]
  PIN actual_data[50]
    DIRECTION INPUT ;
    USE SIGNAL ;
    PORT
      LAYER M4 ;
        RECT  140.316 15.552 140.4 15.576 ;
    END
  END actual_data[50]
  PIN actual_data[51]
    DIRECTION INPUT ;
    USE SIGNAL ;
    PORT
      LAYER M4 ;
        RECT  140.316 15.84 140.4 15.864 ;
    END
  END actual_data[51]
  PIN actual_data[52]
    DIRECTION INPUT ;
    USE SIGNAL ;
    PORT
      LAYER M4 ;
        RECT  140.316 16.128 140.4 16.152 ;
    END
  END actual_data[52]
  PIN actual_data[53]
    DIRECTION INPUT ;
    USE SIGNAL ;
    PORT
      LAYER M4 ;
        RECT  140.316 16.416 140.4 16.44 ;
    END
  END actual_data[53]
  PIN actual_data[54]
    DIRECTION INPUT ;
    USE SIGNAL ;
    PORT
      LAYER M4 ;
        RECT  140.316 16.704 140.4 16.728 ;
    END
  END actual_data[54]
  PIN actual_data[55]
    DIRECTION INPUT ;
    USE SIGNAL ;
    PORT
      LAYER M4 ;
        RECT  140.316 16.992 140.4 17.016 ;
    END
  END actual_data[55]
  PIN actual_data[56]
    DIRECTION INPUT ;
    USE SIGNAL ;
    PORT
      LAYER M4 ;
        RECT  140.316 17.28 140.4 17.304 ;
    END
  END actual_data[56]
  PIN actual_data[57]
    DIRECTION INPUT ;
    USE SIGNAL ;
    PORT
      LAYER M4 ;
        RECT  140.316 17.568 140.4 17.592 ;
    END
  END actual_data[57]
  PIN actual_data[58]
    DIRECTION INPUT ;
    USE SIGNAL ;
    PORT
      LAYER M4 ;
        RECT  140.316 17.856 140.4 17.88 ;
    END
  END actual_data[58]
  PIN actual_data[59]
    DIRECTION INPUT ;
    USE SIGNAL ;
    PORT
      LAYER M4 ;
        RECT  140.316 18.144 140.4 18.168 ;
    END
  END actual_data[59]
  PIN actual_data[5]
    DIRECTION INPUT ;
    USE SIGNAL ;
    PORT
      LAYER M4 ;
        RECT  140.316 2.592 140.4 2.616 ;
    END
  END actual_data[5]
  PIN actual_data[60]
    DIRECTION INPUT ;
    USE SIGNAL ;
    PORT
      LAYER M4 ;
        RECT  140.316 18.432 140.4 18.456 ;
    END
  END actual_data[60]
  PIN actual_data[61]
    DIRECTION INPUT ;
    USE SIGNAL ;
    PORT
      LAYER M4 ;
        RECT  140.316 18.72 140.4 18.744 ;
    END
  END actual_data[61]
  PIN actual_data[62]
    DIRECTION INPUT ;
    USE SIGNAL ;
    PORT
      LAYER M4 ;
        RECT  140.316 19.008 140.4 19.032 ;
    END
  END actual_data[62]
  PIN actual_data[63]
    DIRECTION INPUT ;
    USE SIGNAL ;
    PORT
      LAYER M4 ;
        RECT  140.316 19.296 140.4 19.32 ;
    END
  END actual_data[63]
  PIN actual_data[64]
    DIRECTION INPUT ;
    USE SIGNAL ;
    PORT
      LAYER M4 ;
        RECT  140.316 19.584 140.4 19.608 ;
    END
  END actual_data[64]
  PIN actual_data[65]
    DIRECTION INPUT ;
    USE SIGNAL ;
    PORT
      LAYER M4 ;
        RECT  140.316 19.872 140.4 19.896 ;
    END
  END actual_data[65]
  PIN actual_data[66]
    DIRECTION INPUT ;
    USE SIGNAL ;
    PORT
      LAYER M4 ;
        RECT  140.316 20.16 140.4 20.184 ;
    END
  END actual_data[66]
  PIN actual_data[67]
    DIRECTION INPUT ;
    USE SIGNAL ;
    PORT
      LAYER M4 ;
        RECT  140.316 20.448 140.4 20.472 ;
    END
  END actual_data[67]
  PIN actual_data[68]
    DIRECTION INPUT ;
    USE SIGNAL ;
    PORT
      LAYER M4 ;
        RECT  140.316 20.736 140.4 20.76 ;
    END
  END actual_data[68]
  PIN actual_data[69]
    DIRECTION INPUT ;
    USE SIGNAL ;
    PORT
      LAYER M4 ;
        RECT  140.316 21.024 140.4 21.048 ;
    END
  END actual_data[69]
  PIN actual_data[6]
    DIRECTION INPUT ;
    USE SIGNAL ;
    PORT
      LAYER M4 ;
        RECT  140.316 2.88 140.4 2.904 ;
    END
  END actual_data[6]
  PIN actual_data[70]
    DIRECTION INPUT ;
    USE SIGNAL ;
    PORT
      LAYER M4 ;
        RECT  140.316 21.312 140.4 21.336 ;
    END
  END actual_data[70]
  PIN actual_data[71]
    DIRECTION INPUT ;
    USE SIGNAL ;
    PORT
      LAYER M4 ;
        RECT  140.316 21.6 140.4 21.624 ;
    END
  END actual_data[71]
  PIN actual_data[72]
    DIRECTION INPUT ;
    USE SIGNAL ;
    PORT
      LAYER M4 ;
        RECT  140.316 21.888 140.4 21.912 ;
    END
  END actual_data[72]
  PIN actual_data[73]
    DIRECTION INPUT ;
    USE SIGNAL ;
    PORT
      LAYER M4 ;
        RECT  140.316 22.176 140.4 22.2 ;
    END
  END actual_data[73]
  PIN actual_data[74]
    DIRECTION INPUT ;
    USE SIGNAL ;
    PORT
      LAYER M4 ;
        RECT  140.316 22.464 140.4 22.488 ;
    END
  END actual_data[74]
  PIN actual_data[75]
    DIRECTION INPUT ;
    USE SIGNAL ;
    PORT
      LAYER M4 ;
        RECT  140.316 22.752 140.4 22.776 ;
    END
  END actual_data[75]
  PIN actual_data[76]
    DIRECTION INPUT ;
    USE SIGNAL ;
    PORT
      LAYER M4 ;
        RECT  140.316 23.04 140.4 23.064 ;
    END
  END actual_data[76]
  PIN actual_data[77]
    DIRECTION INPUT ;
    USE SIGNAL ;
    PORT
      LAYER M4 ;
        RECT  140.316 23.328 140.4 23.352 ;
    END
  END actual_data[77]
  PIN actual_data[78]
    DIRECTION INPUT ;
    USE SIGNAL ;
    PORT
      LAYER M4 ;
        RECT  140.316 23.616 140.4 23.64 ;
    END
  END actual_data[78]
  PIN actual_data[79]
    DIRECTION INPUT ;
    USE SIGNAL ;
    PORT
      LAYER M4 ;
        RECT  140.316 23.904 140.4 23.928 ;
    END
  END actual_data[79]
  PIN actual_data[7]
    DIRECTION INPUT ;
    USE SIGNAL ;
    PORT
      LAYER M4 ;
        RECT  140.316 3.168 140.4 3.192 ;
    END
  END actual_data[7]
  PIN actual_data[80]
    DIRECTION INPUT ;
    USE SIGNAL ;
    PORT
      LAYER M4 ;
        RECT  140.316 24.192 140.4 24.216 ;
    END
  END actual_data[80]
  PIN actual_data[81]
    DIRECTION INPUT ;
    USE SIGNAL ;
    PORT
      LAYER M4 ;
        RECT  140.316 24.48 140.4 24.504 ;
    END
  END actual_data[81]
  PIN actual_data[82]
    DIRECTION INPUT ;
    USE SIGNAL ;
    PORT
      LAYER M4 ;
        RECT  140.316 24.816 140.4 24.84 ;
    END
  END actual_data[82]
  PIN actual_data[83]
    DIRECTION INPUT ;
    USE SIGNAL ;
    PORT
      LAYER M4 ;
        RECT  140.316 25.104 140.4 25.128 ;
    END
  END actual_data[83]
  PIN actual_data[84]
    DIRECTION INPUT ;
    USE SIGNAL ;
    PORT
      LAYER M4 ;
        RECT  140.316 25.392 140.4 25.416 ;
    END
  END actual_data[84]
  PIN actual_data[85]
    DIRECTION INPUT ;
    USE SIGNAL ;
    PORT
      LAYER M4 ;
        RECT  140.316 25.68 140.4 25.704 ;
    END
  END actual_data[85]
  PIN actual_data[86]
    DIRECTION INPUT ;
    USE SIGNAL ;
    PORT
      LAYER M4 ;
        RECT  140.316 25.968 140.4 25.992 ;
    END
  END actual_data[86]
  PIN actual_data[87]
    DIRECTION INPUT ;
    USE SIGNAL ;
    PORT
      LAYER M4 ;
        RECT  140.316 26.256 140.4 26.28 ;
    END
  END actual_data[87]
  PIN actual_data[88]
    DIRECTION INPUT ;
    USE SIGNAL ;
    PORT
      LAYER M4 ;
        RECT  140.316 26.544 140.4 26.568 ;
    END
  END actual_data[88]
  PIN actual_data[89]
    DIRECTION INPUT ;
    USE SIGNAL ;
    PORT
      LAYER M4 ;
        RECT  140.316 26.832 140.4 26.856 ;
    END
  END actual_data[89]
  PIN actual_data[8]
    DIRECTION INPUT ;
    USE SIGNAL ;
    PORT
      LAYER M4 ;
        RECT  140.316 3.456 140.4 3.48 ;
    END
  END actual_data[8]
  PIN actual_data[90]
    DIRECTION INPUT ;
    USE SIGNAL ;
    PORT
      LAYER M4 ;
        RECT  140.316 27.12 140.4 27.144 ;
    END
  END actual_data[90]
  PIN actual_data[91]
    DIRECTION INPUT ;
    USE SIGNAL ;
    PORT
      LAYER M4 ;
        RECT  140.316 27.408 140.4 27.432 ;
    END
  END actual_data[91]
  PIN actual_data[92]
    DIRECTION INPUT ;
    USE SIGNAL ;
    PORT
      LAYER M4 ;
        RECT  140.316 27.696 140.4 27.72 ;
    END
  END actual_data[92]
  PIN actual_data[93]
    DIRECTION INPUT ;
    USE SIGNAL ;
    PORT
      LAYER M4 ;
        RECT  140.316 27.984 140.4 28.008 ;
    END
  END actual_data[93]
  PIN actual_data[94]
    DIRECTION INPUT ;
    USE SIGNAL ;
    PORT
      LAYER M4 ;
        RECT  140.316 28.272 140.4 28.296 ;
    END
  END actual_data[94]
  PIN actual_data[95]
    DIRECTION INPUT ;
    USE SIGNAL ;
    PORT
      LAYER M4 ;
        RECT  140.316 28.56 140.4 28.584 ;
    END
  END actual_data[95]
  PIN actual_data[96]
    DIRECTION INPUT ;
    USE SIGNAL ;
    PORT
      LAYER M4 ;
        RECT  140.316 28.848 140.4 28.872 ;
    END
  END actual_data[96]
  PIN actual_data[97]
    DIRECTION INPUT ;
    USE SIGNAL ;
    PORT
      LAYER M4 ;
        RECT  140.316 29.136 140.4 29.16 ;
    END
  END actual_data[97]
  PIN actual_data[98]
    DIRECTION INPUT ;
    USE SIGNAL ;
    PORT
      LAYER M4 ;
        RECT  140.316 29.424 140.4 29.448 ;
    END
  END actual_data[98]
  PIN actual_data[99]
    DIRECTION INPUT ;
    USE SIGNAL ;
    PORT
      LAYER M4 ;
        RECT  140.316 29.712 140.4 29.736 ;
    END
  END actual_data[99]
  PIN actual_data[9]
    DIRECTION INPUT ;
    USE SIGNAL ;
    PORT
      LAYER M4 ;
        RECT  140.316 3.744 140.4 3.768 ;
    END
  END actual_data[9]
  PIN actual_epoch[0]
    DIRECTION INPUT ;
    USE SIGNAL ;
    PORT
      LAYER M4 ;
        RECT  140.316 74.976 140.4 75 ;
    END
  END actual_epoch[0]
  PIN actual_epoch[10]
    DIRECTION INPUT ;
    USE SIGNAL ;
    PORT
      LAYER M4 ;
        RECT  140.316 77.904 140.4 77.928 ;
    END
  END actual_epoch[10]
  PIN actual_epoch[11]
    DIRECTION INPUT ;
    USE SIGNAL ;
    PORT
      LAYER M4 ;
        RECT  140.316 78.192 140.4 78.216 ;
    END
  END actual_epoch[11]
  PIN actual_epoch[12]
    DIRECTION INPUT ;
    USE SIGNAL ;
    PORT
      LAYER M4 ;
        RECT  140.316 78.48 140.4 78.504 ;
    END
  END actual_epoch[12]
  PIN actual_epoch[13]
    DIRECTION INPUT ;
    USE SIGNAL ;
    PORT
      LAYER M4 ;
        RECT  140.316 78.768 140.4 78.792 ;
    END
  END actual_epoch[13]
  PIN actual_epoch[14]
    DIRECTION INPUT ;
    USE SIGNAL ;
    PORT
      LAYER M4 ;
        RECT  140.316 79.056 140.4 79.08 ;
    END
  END actual_epoch[14]
  PIN actual_epoch[15]
    DIRECTION INPUT ;
    USE SIGNAL ;
    PORT
      LAYER M4 ;
        RECT  140.316 79.344 140.4 79.368 ;
    END
  END actual_epoch[15]
  PIN actual_epoch[1]
    DIRECTION INPUT ;
    USE SIGNAL ;
    PORT
      LAYER M4 ;
        RECT  140.316 75.264 140.4 75.288 ;
    END
  END actual_epoch[1]
  PIN actual_epoch[2]
    DIRECTION INPUT ;
    USE SIGNAL ;
    PORT
      LAYER M4 ;
        RECT  140.316 75.552 140.4 75.576 ;
    END
  END actual_epoch[2]
  PIN actual_epoch[3]
    DIRECTION INPUT ;
    USE SIGNAL ;
    PORT
      LAYER M4 ;
        RECT  140.316 75.84 140.4 75.864 ;
    END
  END actual_epoch[3]
  PIN actual_epoch[4]
    DIRECTION INPUT ;
    USE SIGNAL ;
    PORT
      LAYER M4 ;
        RECT  140.316 76.128 140.4 76.152 ;
    END
  END actual_epoch[4]
  PIN actual_epoch[5]
    DIRECTION INPUT ;
    USE SIGNAL ;
    PORT
      LAYER M4 ;
        RECT  140.316 76.416 140.4 76.44 ;
    END
  END actual_epoch[5]
  PIN actual_epoch[6]
    DIRECTION INPUT ;
    USE SIGNAL ;
    PORT
      LAYER M4 ;
        RECT  140.316 76.752 140.4 76.776 ;
    END
  END actual_epoch[6]
  PIN actual_epoch[7]
    DIRECTION INPUT ;
    USE SIGNAL ;
    PORT
      LAYER M4 ;
        RECT  140.316 77.04 140.4 77.064 ;
    END
  END actual_epoch[7]
  PIN actual_epoch[8]
    DIRECTION INPUT ;
    USE SIGNAL ;
    PORT
      LAYER M4 ;
        RECT  140.316 77.328 140.4 77.352 ;
    END
  END actual_epoch[8]
  PIN actual_epoch[9]
    DIRECTION INPUT ;
    USE SIGNAL ;
    PORT
      LAYER M4 ;
        RECT  140.316 77.616 140.4 77.64 ;
    END
  END actual_epoch[9]
  PIN actual_layer[0]
    DIRECTION INPUT ;
    USE SIGNAL ;
    PORT
      LAYER M4 ;
        RECT  140.316 79.632 140.4 79.656 ;
    END
  END actual_layer[0]
  PIN actual_layer[1]
    DIRECTION INPUT ;
    USE SIGNAL ;
    PORT
      LAYER M4 ;
        RECT  140.316 79.92 140.4 79.944 ;
    END
  END actual_layer[1]
  PIN actual_layer[2]
    DIRECTION INPUT ;
    USE SIGNAL ;
    PORT
      LAYER M4 ;
        RECT  140.316 80.208 140.4 80.232 ;
    END
  END actual_layer[2]
  PIN actual_layer[3]
    DIRECTION INPUT ;
    USE SIGNAL ;
    PORT
      LAYER M4 ;
        RECT  140.316 80.496 140.4 80.52 ;
    END
  END actual_layer[3]
  PIN actual_layer[4]
    DIRECTION INPUT ;
    USE SIGNAL ;
    PORT
      LAYER M4 ;
        RECT  140.316 80.784 140.4 80.808 ;
    END
  END actual_layer[4]
  PIN actual_layer[5]
    DIRECTION INPUT ;
    USE SIGNAL ;
    PORT
      LAYER M4 ;
        RECT  140.316 81.072 140.4 81.096 ;
    END
  END actual_layer[5]
  PIN actual_sector[0]
    DIRECTION INPUT ;
    USE SIGNAL ;
    PORT
      LAYER M4 ;
        RECT  140.316 81.36 140.4 81.384 ;
    END
  END actual_sector[0]
  PIN actual_sector[1]
    DIRECTION INPUT ;
    USE SIGNAL ;
    PORT
      LAYER M4 ;
        RECT  140.316 81.648 140.4 81.672 ;
    END
  END actual_sector[1]
  PIN actual_sector[2]
    DIRECTION INPUT ;
    USE SIGNAL ;
    PORT
      LAYER M4 ;
        RECT  140.316 81.936 140.4 81.96 ;
    END
  END actual_sector[2]
  PIN actual_sector[3]
    DIRECTION INPUT ;
    USE SIGNAL ;
    PORT
      LAYER M4 ;
        RECT  140.316 82.224 140.4 82.248 ;
    END
  END actual_sector[3]
  PIN actual_sector[4]
    DIRECTION INPUT ;
    USE SIGNAL ;
    PORT
      LAYER M4 ;
        RECT  140.316 82.512 140.4 82.536 ;
    END
  END actual_sector[4]
  PIN actual_sector[5]
    DIRECTION INPUT ;
    USE SIGNAL ;
    PORT
      LAYER M4 ;
        RECT  140.316 82.8 140.4 82.824 ;
    END
  END actual_sector[5]
  PIN actual_sector[6]
    DIRECTION INPUT ;
    USE SIGNAL ;
    PORT
      LAYER M4 ;
        RECT  140.316 83.088 140.4 83.112 ;
    END
  END actual_sector[6]
  PIN actual_sector[7]
    DIRECTION INPUT ;
    USE SIGNAL ;
    PORT
      LAYER M4 ;
        RECT  140.316 83.376 140.4 83.4 ;
    END
  END actual_sector[7]
  PIN actual_sector[8]
    DIRECTION INPUT ;
    USE SIGNAL ;
    PORT
      LAYER M4 ;
        RECT  140.316 83.664 140.4 83.688 ;
    END
  END actual_sector[8]
  PIN actual_sector[9]
    DIRECTION INPUT ;
    USE SIGNAL ;
    PORT
      LAYER M4 ;
        RECT  140.316 83.952 140.4 83.976 ;
    END
  END actual_sector[9]
  PIN actual_valid
    DIRECTION INPUT ;
    USE SIGNAL ;
    PORT
      LAYER M4 ;
        RECT  140.316 84.24 140.4 84.264 ;
    END
  END actual_valid
  PIN arm
    DIRECTION INPUT ;
    USE SIGNAL ;
    PORT
      LAYER M3 ;
        RECT  1.656 88.522 1.674 88.56 ;
    END
  END arm
  PIN cfg_group[0]
    DIRECTION INPUT ;
    USE SIGNAL ;
    PORT
      LAYER M5 ;
        RECT  2.928 88.476 2.952 88.56 ;
    END
  END cfg_group[0]
  PIN cfg_group[1]
    DIRECTION INPUT ;
    USE SIGNAL ;
    PORT
      LAYER M3 ;
        RECT  4.248 88.522 4.266 88.56 ;
    END
  END cfg_group[1]
  PIN cfg_group[2]
    DIRECTION INPUT ;
    USE SIGNAL ;
    PORT
      LAYER M5 ;
        RECT  5.568 88.476 5.592 88.56 ;
    END
  END cfg_group[2]
  PIN cfg_stack[0]
    DIRECTION INPUT ;
    USE SIGNAL ;
    PORT
      LAYER M3 ;
        RECT  6.876 88.522 6.894 88.56 ;
    END
  END cfg_stack[0]
  PIN cfg_stack[1]
    DIRECTION INPUT ;
    USE SIGNAL ;
    PORT
      LAYER M5 ;
        RECT  8.16 88.476 8.184 88.56 ;
    END
  END cfg_stack[1]
  PIN ck
    DIRECTION INPUT ;
    USE SIGNAL ;
    PORT
      LAYER M3 ;
        RECT  70.2 88.522 70.218 88.56 ;
    END
  END ck
  PIN epoch[0]
    DIRECTION INPUT ;
    USE SIGNAL ;
    PORT
      LAYER M3 ;
        RECT  9.468 88.522 9.486 88.56 ;
    END
  END epoch[0]
  PIN epoch[10]
    DIRECTION INPUT ;
    USE SIGNAL ;
    PORT
      LAYER M3 ;
        RECT  22.536 88.522 22.554 88.56 ;
    END
  END epoch[10]
  PIN epoch[11]
    DIRECTION INPUT ;
    USE SIGNAL ;
    PORT
      LAYER M5 ;
        RECT  23.856 88.476 23.88 88.56 ;
    END
  END epoch[11]
  PIN epoch[12]
    DIRECTION INPUT ;
    USE SIGNAL ;
    PORT
      LAYER M3 ;
        RECT  25.164 88.522 25.182 88.56 ;
    END
  END epoch[12]
  PIN epoch[13]
    DIRECTION INPUT ;
    USE SIGNAL ;
    PORT
      LAYER M5 ;
        RECT  26.448 88.476 26.472 88.56 ;
    END
  END epoch[13]
  PIN epoch[14]
    DIRECTION INPUT ;
    USE SIGNAL ;
    PORT
      LAYER M3 ;
        RECT  27.756 88.522 27.774 88.56 ;
    END
  END epoch[14]
  PIN epoch[15]
    DIRECTION INPUT ;
    USE SIGNAL ;
    PORT
      LAYER M5 ;
        RECT  29.04 88.476 29.064 88.56 ;
    END
  END epoch[15]
  PIN epoch[1]
    DIRECTION INPUT ;
    USE SIGNAL ;
    PORT
      LAYER M5 ;
        RECT  10.8 88.476 10.824 88.56 ;
    END
  END epoch[1]
  PIN epoch[2]
    DIRECTION INPUT ;
    USE SIGNAL ;
    PORT
      LAYER M3 ;
        RECT  12.096 88.522 12.114 88.56 ;
    END
  END epoch[2]
  PIN epoch[3]
    DIRECTION INPUT ;
    USE SIGNAL ;
    PORT
      LAYER M5 ;
        RECT  13.392 88.476 13.416 88.56 ;
    END
  END epoch[3]
  PIN epoch[4]
    DIRECTION INPUT ;
    USE SIGNAL ;
    PORT
      LAYER M3 ;
        RECT  14.688 88.522 14.706 88.56 ;
    END
  END epoch[4]
  PIN epoch[5]
    DIRECTION INPUT ;
    USE SIGNAL ;
    PORT
      LAYER M5 ;
        RECT  15.984 88.476 16.008 88.56 ;
    END
  END epoch[5]
  PIN epoch[6]
    DIRECTION INPUT ;
    USE SIGNAL ;
    PORT
      LAYER M3 ;
        RECT  17.316 88.522 17.334 88.56 ;
    END
  END epoch[6]
  PIN epoch[7]
    DIRECTION INPUT ;
    USE SIGNAL ;
    PORT
      LAYER M5 ;
        RECT  18.624 88.476 18.648 88.56 ;
    END
  END epoch[7]
  PIN epoch[8]
    DIRECTION INPUT ;
    USE SIGNAL ;
    PORT
      LAYER M3 ;
        RECT  19.908 88.522 19.926 88.56 ;
    END
  END epoch[8]
  PIN epoch[9]
    DIRECTION INPUT ;
    USE SIGNAL ;
    PORT
      LAYER M5 ;
        RECT  21.216 88.476 21.24 88.56 ;
    END
  END epoch[9]
  PIN expected_put
    DIRECTION INPUT ;
    USE SIGNAL ;
    PORT
      LAYER M4 ;
        RECT  140.316 84.528 140.4 84.552 ;
    END
  END expected_put
  PIN expected_sector[0]
    DIRECTION INPUT ;
    USE SIGNAL ;
    PORT
      LAYER M4 ;
        RECT  140.316 84.816 140.4 84.84 ;
    END
  END expected_sector[0]
  PIN expected_sector[1]
    DIRECTION INPUT ;
    USE SIGNAL ;
    PORT
      LAYER M4 ;
        RECT  140.316 85.104 140.4 85.128 ;
    END
  END expected_sector[1]
  PIN expected_sector[2]
    DIRECTION INPUT ;
    USE SIGNAL ;
    PORT
      LAYER M4 ;
        RECT  140.316 85.392 140.4 85.416 ;
    END
  END expected_sector[2]
  PIN expected_sector[3]
    DIRECTION INPUT ;
    USE SIGNAL ;
    PORT
      LAYER M4 ;
        RECT  140.316 85.68 140.4 85.704 ;
    END
  END expected_sector[3]
  PIN expected_sector[4]
    DIRECTION INPUT ;
    USE SIGNAL ;
    PORT
      LAYER M4 ;
        RECT  140.316 85.968 140.4 85.992 ;
    END
  END expected_sector[4]
  PIN expected_sector[5]
    DIRECTION INPUT ;
    USE SIGNAL ;
    PORT
      LAYER M4 ;
        RECT  140.316 86.256 140.4 86.28 ;
    END
  END expected_sector[5]
  PIN expected_sector[6]
    DIRECTION INPUT ;
    USE SIGNAL ;
    PORT
      LAYER M4 ;
        RECT  140.316 86.544 140.4 86.568 ;
    END
  END expected_sector[6]
  PIN expected_sector[7]
    DIRECTION INPUT ;
    USE SIGNAL ;
    PORT
      LAYER M4 ;
        RECT  140.316 86.832 140.4 86.856 ;
    END
  END expected_sector[7]
  PIN expected_sector[8]
    DIRECTION INPUT ;
    USE SIGNAL ;
    PORT
      LAYER M4 ;
        RECT  140.316 87.12 140.4 87.144 ;
    END
  END expected_sector[8]
  PIN expected_sector[9]
    DIRECTION INPUT ;
    USE SIGNAL ;
    PORT
      LAYER M4 ;
        RECT  140.316 87.408 140.4 87.432 ;
    END
  END expected_sector[9]
  PIN fault
    DIRECTION OUTPUT ;
    USE SIGNAL ;
    PORT
      LAYER M3 ;
        RECT  30.384 88.522 30.402 88.56 ;
    END
  END fault
  PIN get
    DIRECTION INPUT ;
    USE SIGNAL ;
    PORT
      LAYER M5 ;
        RECT  31.68 88.476 31.704 88.56 ;
    END
  END get
  PIN get_epoch[0]
    DIRECTION INPUT ;
    USE SIGNAL ;
    PORT
      LAYER M3 ;
        RECT  32.976 88.522 32.994 88.56 ;
    END
  END get_epoch[0]
  PIN get_epoch[10]
    DIRECTION INPUT ;
    USE SIGNAL ;
    PORT
      LAYER M3 ;
        RECT  46.044 88.522 46.062 88.56 ;
    END
  END get_epoch[10]
  PIN get_epoch[11]
    DIRECTION INPUT ;
    USE SIGNAL ;
    PORT
      LAYER M5 ;
        RECT  47.328 88.476 47.352 88.56 ;
    END
  END get_epoch[11]
  PIN get_epoch[12]
    DIRECTION INPUT ;
    USE SIGNAL ;
    PORT
      LAYER M3 ;
        RECT  48.636 88.522 48.654 88.56 ;
    END
  END get_epoch[12]
  PIN get_epoch[13]
    DIRECTION INPUT ;
    USE SIGNAL ;
    PORT
      LAYER M5 ;
        RECT  49.968 88.476 49.992 88.56 ;
    END
  END get_epoch[13]
  PIN get_epoch[14]
    DIRECTION INPUT ;
    USE SIGNAL ;
    PORT
      LAYER M3 ;
        RECT  51.264 88.522 51.282 88.56 ;
    END
  END get_epoch[14]
  PIN get_epoch[15]
    DIRECTION INPUT ;
    USE SIGNAL ;
    PORT
      LAYER M5 ;
        RECT  52.56 88.476 52.584 88.56 ;
    END
  END get_epoch[15]
  PIN get_epoch[1]
    DIRECTION INPUT ;
    USE SIGNAL ;
    PORT
      LAYER M5 ;
        RECT  34.272 88.476 34.296 88.56 ;
    END
  END get_epoch[1]
  PIN get_epoch[2]
    DIRECTION INPUT ;
    USE SIGNAL ;
    PORT
      LAYER M3 ;
        RECT  35.604 88.522 35.622 88.56 ;
    END
  END get_epoch[2]
  PIN get_epoch[3]
    DIRECTION INPUT ;
    USE SIGNAL ;
    PORT
      LAYER M5 ;
        RECT  36.912 88.476 36.936 88.56 ;
    END
  END get_epoch[3]
  PIN get_epoch[4]
    DIRECTION INPUT ;
    USE SIGNAL ;
    PORT
      LAYER M3 ;
        RECT  38.196 88.522 38.214 88.56 ;
    END
  END get_epoch[4]
  PIN get_epoch[5]
    DIRECTION INPUT ;
    USE SIGNAL ;
    PORT
      LAYER M5 ;
        RECT  39.504 88.476 39.528 88.56 ;
    END
  END get_epoch[5]
  PIN get_epoch[6]
    DIRECTION INPUT ;
    USE SIGNAL ;
    PORT
      LAYER M3 ;
        RECT  40.824 88.522 40.842 88.56 ;
    END
  END get_epoch[6]
  PIN get_epoch[7]
    DIRECTION INPUT ;
    USE SIGNAL ;
    PORT
      LAYER M5 ;
        RECT  42.096 88.476 42.12 88.56 ;
    END
  END get_epoch[7]
  PIN get_epoch[8]
    DIRECTION INPUT ;
    USE SIGNAL ;
    PORT
      LAYER M3 ;
        RECT  43.416 88.522 43.434 88.56 ;
    END
  END get_epoch[8]
  PIN get_epoch[9]
    DIRECTION INPUT ;
    USE SIGNAL ;
    PORT
      LAYER M5 ;
        RECT  44.736 88.476 44.76 88.56 ;
    END
  END get_epoch[9]
  PIN get_layer[0]
    DIRECTION INPUT ;
    USE SIGNAL ;
    PORT
      LAYER M3 ;
        RECT  53.856 88.522 53.874 88.56 ;
    END
  END get_layer[0]
  PIN get_layer[1]
    DIRECTION INPUT ;
    USE SIGNAL ;
    PORT
      LAYER M5 ;
        RECT  55.152 88.476 55.176 88.56 ;
    END
  END get_layer[1]
  PIN get_layer[2]
    DIRECTION INPUT ;
    USE SIGNAL ;
    PORT
      LAYER M3 ;
        RECT  56.484 88.522 56.502 88.56 ;
    END
  END get_layer[2]
  PIN get_layer[3]
    DIRECTION INPUT ;
    USE SIGNAL ;
    PORT
      LAYER M5 ;
        RECT  57.792 88.476 57.816 88.56 ;
    END
  END get_layer[3]
  PIN get_layer[4]
    DIRECTION INPUT ;
    USE SIGNAL ;
    PORT
      LAYER M3 ;
        RECT  59.076 88.522 59.094 88.56 ;
    END
  END get_layer[4]
  PIN get_layer[5]
    DIRECTION INPUT ;
    USE SIGNAL ;
    PORT
      LAYER M5 ;
        RECT  60.384 88.476 60.408 88.56 ;
    END
  END get_layer[5]
  PIN get_t[0]
    DIRECTION INPUT ;
    USE SIGNAL ;
    PORT
      LAYER M3 ;
        RECT  61.704 88.522 61.722 88.56 ;
    END
  END get_t[0]
  PIN get_t[10]
    DIRECTION INPUT ;
    USE SIGNAL ;
    PORT
      LAYER M3 ;
        RECT  74.772 88.522 74.79 88.56 ;
    END
  END get_t[10]
  PIN get_t[11]
    DIRECTION INPUT ;
    USE SIGNAL ;
    PORT
      LAYER M5 ;
        RECT  76.08 88.476 76.104 88.56 ;
    END
  END get_t[11]
  PIN get_t[12]
    DIRECTION INPUT ;
    USE SIGNAL ;
    PORT
      LAYER M3 ;
        RECT  77.364 88.522 77.382 88.56 ;
    END
  END get_t[12]
  PIN get_t[13]
    DIRECTION INPUT ;
    USE SIGNAL ;
    PORT
      LAYER M5 ;
        RECT  78.672 88.476 78.696 88.56 ;
    END
  END get_t[13]
  PIN get_t[1]
    DIRECTION INPUT ;
    USE SIGNAL ;
    PORT
      LAYER M5 ;
        RECT  63.024 88.476 63.048 88.56 ;
    END
  END get_t[1]
  PIN get_t[2]
    DIRECTION INPUT ;
    USE SIGNAL ;
    PORT
      LAYER M3 ;
        RECT  64.332 88.522 64.35 88.56 ;
    END
  END get_t[2]
  PIN get_t[3]
    DIRECTION INPUT ;
    USE SIGNAL ;
    PORT
      LAYER M5 ;
        RECT  65.616 88.476 65.64 88.56 ;
    END
  END get_t[3]
  PIN get_t[4]
    DIRECTION INPUT ;
    USE SIGNAL ;
    PORT
      LAYER M3 ;
        RECT  66.924 88.522 66.942 88.56 ;
    END
  END get_t[4]
  PIN get_t[5]
    DIRECTION INPUT ;
    USE SIGNAL ;
    PORT
      LAYER M5 ;
        RECT  68.208 88.476 68.232 88.56 ;
    END
  END get_t[5]
  PIN get_t[6]
    DIRECTION INPUT ;
    USE SIGNAL ;
    PORT
      LAYER M3 ;
        RECT  69.552 88.522 69.57 88.56 ;
    END
  END get_t[6]
  PIN get_t[7]
    DIRECTION INPUT ;
    USE SIGNAL ;
    PORT
      LAYER M5 ;
        RECT  70.848 88.476 70.872 88.56 ;
    END
  END get_t[7]
  PIN get_t[8]
    DIRECTION INPUT ;
    USE SIGNAL ;
    PORT
      LAYER M3 ;
        RECT  72.144 88.522 72.162 88.56 ;
    END
  END get_t[8]
  PIN get_t[9]
    DIRECTION INPUT ;
    USE SIGNAL ;
    PORT
      LAYER M5 ;
        RECT  73.44 88.476 73.464 88.56 ;
    END
  END get_t[9]
  PIN get_v
    DIRECTION INPUT ;
    USE SIGNAL ;
    PORT
      LAYER M3 ;
        RECT  79.992 88.522 80.01 88.56 ;
    END
  END get_v
  PIN layer[0]
    DIRECTION INPUT ;
    USE SIGNAL ;
    PORT
      LAYER M5 ;
        RECT  81.264 88.476 81.288 88.56 ;
    END
  END layer[0]
  PIN layer[1]
    DIRECTION INPUT ;
    USE SIGNAL ;
    PORT
      LAYER M3 ;
        RECT  82.584 88.522 82.602 88.56 ;
    END
  END layer[1]
  PIN layer[2]
    DIRECTION INPUT ;
    USE SIGNAL ;
    PORT
      LAYER M5 ;
        RECT  83.904 88.476 83.928 88.56 ;
    END
  END layer[2]
  PIN layer[3]
    DIRECTION INPUT ;
    USE SIGNAL ;
    PORT
      LAYER M3 ;
        RECT  85.212 88.522 85.23 88.56 ;
    END
  END layer[3]
  PIN layer[4]
    DIRECTION INPUT ;
    USE SIGNAL ;
    PORT
      LAYER M5 ;
        RECT  86.496 88.476 86.52 88.56 ;
    END
  END layer[4]
  PIN layer[5]
    DIRECTION INPUT ;
    USE SIGNAL ;
    PORT
      LAYER M3 ;
        RECT  87.804 88.522 87.822 88.56 ;
    END
  END layer[5]
  PIN out_epoch[0]
    DIRECTION OUTPUT ;
    USE SIGNAL ;
    PORT
      LAYER M5 ;
        RECT  89.136 88.476 89.16 88.56 ;
    END
  END out_epoch[0]
  PIN out_epoch[10]
    DIRECTION OUTPUT ;
    USE SIGNAL ;
    PORT
      LAYER M5 ;
        RECT  102.192 88.476 102.216 88.56 ;
    END
  END out_epoch[10]
  PIN out_epoch[11]
    DIRECTION OUTPUT ;
    USE SIGNAL ;
    PORT
      LAYER M3 ;
        RECT  103.5 88.522 103.518 88.56 ;
    END
  END out_epoch[11]
  PIN out_epoch[12]
    DIRECTION OUTPUT ;
    USE SIGNAL ;
    PORT
      LAYER M5 ;
        RECT  104.784 88.476 104.808 88.56 ;
    END
  END out_epoch[12]
  PIN out_epoch[13]
    DIRECTION OUTPUT ;
    USE SIGNAL ;
    PORT
      LAYER M3 ;
        RECT  106.092 88.522 106.11 88.56 ;
    END
  END out_epoch[13]
  PIN out_epoch[14]
    DIRECTION OUTPUT ;
    USE SIGNAL ;
    PORT
      LAYER M5 ;
        RECT  107.376 88.476 107.4 88.56 ;
    END
  END out_epoch[14]
  PIN out_epoch[15]
    DIRECTION OUTPUT ;
    USE SIGNAL ;
    PORT
      LAYER M3 ;
        RECT  108.72 88.522 108.738 88.56 ;
    END
  END out_epoch[15]
  PIN out_epoch[1]
    DIRECTION OUTPUT ;
    USE SIGNAL ;
    PORT
      LAYER M3 ;
        RECT  90.432 88.522 90.45 88.56 ;
    END
  END out_epoch[1]
  PIN out_epoch[2]
    DIRECTION OUTPUT ;
    USE SIGNAL ;
    PORT
      LAYER M5 ;
        RECT  91.728 88.476 91.752 88.56 ;
    END
  END out_epoch[2]
  PIN out_epoch[3]
    DIRECTION OUTPUT ;
    USE SIGNAL ;
    PORT
      LAYER M3 ;
        RECT  93.024 88.522 93.042 88.56 ;
    END
  END out_epoch[3]
  PIN out_epoch[4]
    DIRECTION OUTPUT ;
    USE SIGNAL ;
    PORT
      LAYER M5 ;
        RECT  94.32 88.476 94.344 88.56 ;
    END
  END out_epoch[4]
  PIN out_epoch[5]
    DIRECTION OUTPUT ;
    USE SIGNAL ;
    PORT
      LAYER M3 ;
        RECT  95.652 88.522 95.67 88.56 ;
    END
  END out_epoch[5]
  PIN out_epoch[6]
    DIRECTION OUTPUT ;
    USE SIGNAL ;
    PORT
      LAYER M5 ;
        RECT  96.96 88.476 96.984 88.56 ;
    END
  END out_epoch[6]
  PIN out_epoch[7]
    DIRECTION OUTPUT ;
    USE SIGNAL ;
    PORT
      LAYER M3 ;
        RECT  98.28 88.522 98.298 88.56 ;
    END
  END out_epoch[7]
  PIN out_epoch[8]
    DIRECTION OUTPUT ;
    USE SIGNAL ;
    PORT
      LAYER M5 ;
        RECT  99.552 88.476 99.576 88.56 ;
    END
  END out_epoch[8]
  PIN out_epoch[9]
    DIRECTION OUTPUT ;
    USE SIGNAL ;
    PORT
      LAYER M3 ;
        RECT  100.872 88.522 100.89 88.56 ;
    END
  END out_epoch[9]
  PIN out_layer[0]
    DIRECTION OUTPUT ;
    USE SIGNAL ;
    PORT
      LAYER M5 ;
        RECT  110.016 88.476 110.04 88.56 ;
    END
  END out_layer[0]
  PIN out_layer[1]
    DIRECTION OUTPUT ;
    USE SIGNAL ;
    PORT
      LAYER M3 ;
        RECT  111.312 88.522 111.33 88.56 ;
    END
  END out_layer[1]
  PIN out_layer[2]
    DIRECTION OUTPUT ;
    USE SIGNAL ;
    PORT
      LAYER M5 ;
        RECT  112.608 88.476 112.632 88.56 ;
    END
  END out_layer[2]
  PIN out_layer[3]
    DIRECTION OUTPUT ;
    USE SIGNAL ;
    PORT
      LAYER M3 ;
        RECT  113.94 88.522 113.958 88.56 ;
    END
  END out_layer[3]
  PIN out_layer[4]
    DIRECTION OUTPUT ;
    USE SIGNAL ;
    PORT
      LAYER M5 ;
        RECT  115.248 88.476 115.272 88.56 ;
    END
  END out_layer[4]
  PIN out_layer[5]
    DIRECTION OUTPUT ;
    USE SIGNAL ;
    PORT
      LAYER M3 ;
        RECT  116.532 88.522 116.55 88.56 ;
    END
  END out_layer[5]
  PIN out_t[0]
    DIRECTION OUTPUT ;
    USE SIGNAL ;
    PORT
      LAYER M5 ;
        RECT  117.84 88.476 117.864 88.56 ;
    END
  END out_t[0]
  PIN out_t[10]
    DIRECTION OUTPUT ;
    USE SIGNAL ;
    PORT
      LAYER M5 ;
        RECT  130.896 88.476 130.92 88.56 ;
    END
  END out_t[10]
  PIN out_t[11]
    DIRECTION OUTPUT ;
    USE SIGNAL ;
    PORT
      LAYER M3 ;
        RECT  132.228 88.522 132.246 88.56 ;
    END
  END out_t[11]
  PIN out_t[12]
    DIRECTION OUTPUT ;
    USE SIGNAL ;
    PORT
      LAYER M5 ;
        RECT  133.536 88.476 133.56 88.56 ;
    END
  END out_t[12]
  PIN out_t[13]
    DIRECTION OUTPUT ;
    USE SIGNAL ;
    PORT
      LAYER M3 ;
        RECT  134.82 88.522 134.838 88.56 ;
    END
  END out_t[13]
  PIN out_t[1]
    DIRECTION OUTPUT ;
    USE SIGNAL ;
    PORT
      LAYER M3 ;
        RECT  119.16 88.522 119.178 88.56 ;
    END
  END out_t[1]
  PIN out_t[2]
    DIRECTION OUTPUT ;
    USE SIGNAL ;
    PORT
      LAYER M5 ;
        RECT  120.48 88.476 120.504 88.56 ;
    END
  END out_t[2]
  PIN out_t[3]
    DIRECTION OUTPUT ;
    USE SIGNAL ;
    PORT
      LAYER M3 ;
        RECT  121.752 88.522 121.77 88.56 ;
    END
  END out_t[3]
  PIN out_t[4]
    DIRECTION OUTPUT ;
    USE SIGNAL ;
    PORT
      LAYER M5 ;
        RECT  123.072 88.476 123.096 88.56 ;
    END
  END out_t[4]
  PIN out_t[5]
    DIRECTION OUTPUT ;
    USE SIGNAL ;
    PORT
      LAYER M3 ;
        RECT  124.38 88.522 124.398 88.56 ;
    END
  END out_t[5]
  PIN out_t[6]
    DIRECTION OUTPUT ;
    USE SIGNAL ;
    PORT
      LAYER M5 ;
        RECT  125.664 88.476 125.688 88.56 ;
    END
  END out_t[6]
  PIN out_t[7]
    DIRECTION OUTPUT ;
    USE SIGNAL ;
    PORT
      LAYER M3 ;
        RECT  126.972 88.522 126.99 88.56 ;
    END
  END out_t[7]
  PIN out_t[8]
    DIRECTION OUTPUT ;
    USE SIGNAL ;
    PORT
      LAYER M5 ;
        RECT  128.304 88.476 128.328 88.56 ;
    END
  END out_t[8]
  PIN out_t[9]
    DIRECTION OUTPUT ;
    USE SIGNAL ;
    PORT
      LAYER M3 ;
        RECT  129.6 88.522 129.618 88.56 ;
    END
  END out_t[9]
  PIN out_v
    DIRECTION OUTPUT ;
    USE SIGNAL ;
    PORT
      LAYER M5 ;
        RECT  136.128 88.476 136.152 88.56 ;
    END
  END out_v
  PIN out_valid
    DIRECTION OUTPUT ;
    USE SIGNAL ;
    PORT
      LAYER M3 ;
        RECT  137.448 88.522 137.466 88.56 ;
    END
  END out_valid
  PIN rsp_data[0]
    DIRECTION OUTPUT ;
    USE SIGNAL ;
    PORT
      LAYER M4 ;
        RECT  0 1.152 0.084 1.176 ;
    END
  END rsp_data[0]
  PIN rsp_data[100]
    DIRECTION OUTPUT ;
    USE SIGNAL ;
    PORT
      LAYER M4 ;
        RECT  0 34.992 0.084 35.016 ;
    END
  END rsp_data[100]
  PIN rsp_data[101]
    DIRECTION OUTPUT ;
    USE SIGNAL ;
    PORT
      LAYER M4 ;
        RECT  0 35.328 0.084 35.352 ;
    END
  END rsp_data[101]
  PIN rsp_data[102]
    DIRECTION OUTPUT ;
    USE SIGNAL ;
    PORT
      LAYER M4 ;
        RECT  0 35.664 0.084 35.688 ;
    END
  END rsp_data[102]
  PIN rsp_data[103]
    DIRECTION OUTPUT ;
    USE SIGNAL ;
    PORT
      LAYER M4 ;
        RECT  0 36 0.084 36.024 ;
    END
  END rsp_data[103]
  PIN rsp_data[104]
    DIRECTION OUTPUT ;
    USE SIGNAL ;
    PORT
      LAYER M4 ;
        RECT  0 36.336 0.084 36.36 ;
    END
  END rsp_data[104]
  PIN rsp_data[105]
    DIRECTION OUTPUT ;
    USE SIGNAL ;
    PORT
      LAYER M4 ;
        RECT  0 36.672 0.084 36.696 ;
    END
  END rsp_data[105]
  PIN rsp_data[106]
    DIRECTION OUTPUT ;
    USE SIGNAL ;
    PORT
      LAYER M4 ;
        RECT  0 37.008 0.084 37.032 ;
    END
  END rsp_data[106]
  PIN rsp_data[107]
    DIRECTION OUTPUT ;
    USE SIGNAL ;
    PORT
      LAYER M4 ;
        RECT  0 37.344 0.084 37.368 ;
    END
  END rsp_data[107]
  PIN rsp_data[108]
    DIRECTION OUTPUT ;
    USE SIGNAL ;
    PORT
      LAYER M4 ;
        RECT  0 37.68 0.084 37.704 ;
    END
  END rsp_data[108]
  PIN rsp_data[109]
    DIRECTION OUTPUT ;
    USE SIGNAL ;
    PORT
      LAYER M4 ;
        RECT  0 38.016 0.084 38.04 ;
    END
  END rsp_data[109]
  PIN rsp_data[10]
    DIRECTION OUTPUT ;
    USE SIGNAL ;
    PORT
      LAYER M4 ;
        RECT  0 4.56 0.084 4.584 ;
    END
  END rsp_data[10]
  PIN rsp_data[110]
    DIRECTION OUTPUT ;
    USE SIGNAL ;
    PORT
      LAYER M4 ;
        RECT  0 38.352 0.084 38.376 ;
    END
  END rsp_data[110]
  PIN rsp_data[111]
    DIRECTION OUTPUT ;
    USE SIGNAL ;
    PORT
      LAYER M4 ;
        RECT  0 38.688 0.084 38.712 ;
    END
  END rsp_data[111]
  PIN rsp_data[112]
    DIRECTION OUTPUT ;
    USE SIGNAL ;
    PORT
      LAYER M4 ;
        RECT  0 39.024 0.084 39.048 ;
    END
  END rsp_data[112]
  PIN rsp_data[113]
    DIRECTION OUTPUT ;
    USE SIGNAL ;
    PORT
      LAYER M4 ;
        RECT  0 39.36 0.084 39.384 ;
    END
  END rsp_data[113]
  PIN rsp_data[114]
    DIRECTION OUTPUT ;
    USE SIGNAL ;
    PORT
      LAYER M4 ;
        RECT  0 39.696 0.084 39.72 ;
    END
  END rsp_data[114]
  PIN rsp_data[115]
    DIRECTION OUTPUT ;
    USE SIGNAL ;
    PORT
      LAYER M4 ;
        RECT  0 40.032 0.084 40.056 ;
    END
  END rsp_data[115]
  PIN rsp_data[116]
    DIRECTION OUTPUT ;
    USE SIGNAL ;
    PORT
      LAYER M4 ;
        RECT  0 40.368 0.084 40.392 ;
    END
  END rsp_data[116]
  PIN rsp_data[117]
    DIRECTION OUTPUT ;
    USE SIGNAL ;
    PORT
      LAYER M4 ;
        RECT  0 40.704 0.084 40.728 ;
    END
  END rsp_data[117]
  PIN rsp_data[118]
    DIRECTION OUTPUT ;
    USE SIGNAL ;
    PORT
      LAYER M4 ;
        RECT  0 41.04 0.084 41.064 ;
    END
  END rsp_data[118]
  PIN rsp_data[119]
    DIRECTION OUTPUT ;
    USE SIGNAL ;
    PORT
      LAYER M4 ;
        RECT  0 41.376 0.084 41.4 ;
    END
  END rsp_data[119]
  PIN rsp_data[11]
    DIRECTION OUTPUT ;
    USE SIGNAL ;
    PORT
      LAYER M4 ;
        RECT  0 4.896 0.084 4.92 ;
    END
  END rsp_data[11]
  PIN rsp_data[120]
    DIRECTION OUTPUT ;
    USE SIGNAL ;
    PORT
      LAYER M4 ;
        RECT  0 41.712 0.084 41.736 ;
    END
  END rsp_data[120]
  PIN rsp_data[121]
    DIRECTION OUTPUT ;
    USE SIGNAL ;
    PORT
      LAYER M4 ;
        RECT  0 42.048 0.084 42.072 ;
    END
  END rsp_data[121]
  PIN rsp_data[122]
    DIRECTION OUTPUT ;
    USE SIGNAL ;
    PORT
      LAYER M4 ;
        RECT  0 42.432 0.084 42.456 ;
    END
  END rsp_data[122]
  PIN rsp_data[123]
    DIRECTION OUTPUT ;
    USE SIGNAL ;
    PORT
      LAYER M4 ;
        RECT  0 42.768 0.084 42.792 ;
    END
  END rsp_data[123]
  PIN rsp_data[124]
    DIRECTION OUTPUT ;
    USE SIGNAL ;
    PORT
      LAYER M4 ;
        RECT  0 43.104 0.084 43.128 ;
    END
  END rsp_data[124]
  PIN rsp_data[125]
    DIRECTION OUTPUT ;
    USE SIGNAL ;
    PORT
      LAYER M4 ;
        RECT  0 43.44 0.084 43.464 ;
    END
  END rsp_data[125]
  PIN rsp_data[126]
    DIRECTION OUTPUT ;
    USE SIGNAL ;
    PORT
      LAYER M4 ;
        RECT  0 43.776 0.084 43.8 ;
    END
  END rsp_data[126]
  PIN rsp_data[127]
    DIRECTION OUTPUT ;
    USE SIGNAL ;
    PORT
      LAYER M4 ;
        RECT  0 44.112 0.084 44.136 ;
    END
  END rsp_data[127]
  PIN rsp_data[128]
    DIRECTION OUTPUT ;
    USE SIGNAL ;
    PORT
      LAYER M4 ;
        RECT  0 44.448 0.084 44.472 ;
    END
  END rsp_data[128]
  PIN rsp_data[129]
    DIRECTION OUTPUT ;
    USE SIGNAL ;
    PORT
      LAYER M4 ;
        RECT  0 44.784 0.084 44.808 ;
    END
  END rsp_data[129]
  PIN rsp_data[12]
    DIRECTION OUTPUT ;
    USE SIGNAL ;
    PORT
      LAYER M4 ;
        RECT  0 5.232 0.084 5.256 ;
    END
  END rsp_data[12]
  PIN rsp_data[130]
    DIRECTION OUTPUT ;
    USE SIGNAL ;
    PORT
      LAYER M4 ;
        RECT  0 45.12 0.084 45.144 ;
    END
  END rsp_data[130]
  PIN rsp_data[131]
    DIRECTION OUTPUT ;
    USE SIGNAL ;
    PORT
      LAYER M4 ;
        RECT  0 45.456 0.084 45.48 ;
    END
  END rsp_data[131]
  PIN rsp_data[132]
    DIRECTION OUTPUT ;
    USE SIGNAL ;
    PORT
      LAYER M4 ;
        RECT  0 45.792 0.084 45.816 ;
    END
  END rsp_data[132]
  PIN rsp_data[133]
    DIRECTION OUTPUT ;
    USE SIGNAL ;
    PORT
      LAYER M4 ;
        RECT  0 46.128 0.084 46.152 ;
    END
  END rsp_data[133]
  PIN rsp_data[134]
    DIRECTION OUTPUT ;
    USE SIGNAL ;
    PORT
      LAYER M4 ;
        RECT  0 46.464 0.084 46.488 ;
    END
  END rsp_data[134]
  PIN rsp_data[135]
    DIRECTION OUTPUT ;
    USE SIGNAL ;
    PORT
      LAYER M4 ;
        RECT  0 46.8 0.084 46.824 ;
    END
  END rsp_data[135]
  PIN rsp_data[136]
    DIRECTION OUTPUT ;
    USE SIGNAL ;
    PORT
      LAYER M4 ;
        RECT  0 47.136 0.084 47.16 ;
    END
  END rsp_data[136]
  PIN rsp_data[137]
    DIRECTION OUTPUT ;
    USE SIGNAL ;
    PORT
      LAYER M4 ;
        RECT  0 47.472 0.084 47.496 ;
    END
  END rsp_data[137]
  PIN rsp_data[138]
    DIRECTION OUTPUT ;
    USE SIGNAL ;
    PORT
      LAYER M4 ;
        RECT  0 47.808 0.084 47.832 ;
    END
  END rsp_data[138]
  PIN rsp_data[139]
    DIRECTION OUTPUT ;
    USE SIGNAL ;
    PORT
      LAYER M4 ;
        RECT  0 48.144 0.084 48.168 ;
    END
  END rsp_data[139]
  PIN rsp_data[13]
    DIRECTION OUTPUT ;
    USE SIGNAL ;
    PORT
      LAYER M4 ;
        RECT  0 5.568 0.084 5.592 ;
    END
  END rsp_data[13]
  PIN rsp_data[140]
    DIRECTION OUTPUT ;
    USE SIGNAL ;
    PORT
      LAYER M4 ;
        RECT  0 48.48 0.084 48.504 ;
    END
  END rsp_data[140]
  PIN rsp_data[141]
    DIRECTION OUTPUT ;
    USE SIGNAL ;
    PORT
      LAYER M4 ;
        RECT  0 48.816 0.084 48.84 ;
    END
  END rsp_data[141]
  PIN rsp_data[142]
    DIRECTION OUTPUT ;
    USE SIGNAL ;
    PORT
      LAYER M4 ;
        RECT  0 49.152 0.084 49.176 ;
    END
  END rsp_data[142]
  PIN rsp_data[143]
    DIRECTION OUTPUT ;
    USE SIGNAL ;
    PORT
      LAYER M4 ;
        RECT  0 49.488 0.084 49.512 ;
    END
  END rsp_data[143]
  PIN rsp_data[144]
    DIRECTION OUTPUT ;
    USE SIGNAL ;
    PORT
      LAYER M4 ;
        RECT  0 49.824 0.084 49.848 ;
    END
  END rsp_data[144]
  PIN rsp_data[145]
    DIRECTION OUTPUT ;
    USE SIGNAL ;
    PORT
      LAYER M4 ;
        RECT  0 50.208 0.084 50.232 ;
    END
  END rsp_data[145]
  PIN rsp_data[146]
    DIRECTION OUTPUT ;
    USE SIGNAL ;
    PORT
      LAYER M4 ;
        RECT  0 50.544 0.084 50.568 ;
    END
  END rsp_data[146]
  PIN rsp_data[147]
    DIRECTION OUTPUT ;
    USE SIGNAL ;
    PORT
      LAYER M4 ;
        RECT  0 50.88 0.084 50.904 ;
    END
  END rsp_data[147]
  PIN rsp_data[148]
    DIRECTION OUTPUT ;
    USE SIGNAL ;
    PORT
      LAYER M4 ;
        RECT  0 51.216 0.084 51.24 ;
    END
  END rsp_data[148]
  PIN rsp_data[149]
    DIRECTION OUTPUT ;
    USE SIGNAL ;
    PORT
      LAYER M4 ;
        RECT  0 51.552 0.084 51.576 ;
    END
  END rsp_data[149]
  PIN rsp_data[14]
    DIRECTION OUTPUT ;
    USE SIGNAL ;
    PORT
      LAYER M4 ;
        RECT  0 5.904 0.084 5.928 ;
    END
  END rsp_data[14]
  PIN rsp_data[150]
    DIRECTION OUTPUT ;
    USE SIGNAL ;
    PORT
      LAYER M4 ;
        RECT  0 51.888 0.084 51.912 ;
    END
  END rsp_data[150]
  PIN rsp_data[151]
    DIRECTION OUTPUT ;
    USE SIGNAL ;
    PORT
      LAYER M4 ;
        RECT  0 52.224 0.084 52.248 ;
    END
  END rsp_data[151]
  PIN rsp_data[152]
    DIRECTION OUTPUT ;
    USE SIGNAL ;
    PORT
      LAYER M4 ;
        RECT  0 52.56 0.084 52.584 ;
    END
  END rsp_data[152]
  PIN rsp_data[153]
    DIRECTION OUTPUT ;
    USE SIGNAL ;
    PORT
      LAYER M4 ;
        RECT  0 52.896 0.084 52.92 ;
    END
  END rsp_data[153]
  PIN rsp_data[154]
    DIRECTION OUTPUT ;
    USE SIGNAL ;
    PORT
      LAYER M4 ;
        RECT  0 53.232 0.084 53.256 ;
    END
  END rsp_data[154]
  PIN rsp_data[155]
    DIRECTION OUTPUT ;
    USE SIGNAL ;
    PORT
      LAYER M4 ;
        RECT  0 53.568 0.084 53.592 ;
    END
  END rsp_data[155]
  PIN rsp_data[156]
    DIRECTION OUTPUT ;
    USE SIGNAL ;
    PORT
      LAYER M4 ;
        RECT  0 53.904 0.084 53.928 ;
    END
  END rsp_data[156]
  PIN rsp_data[157]
    DIRECTION OUTPUT ;
    USE SIGNAL ;
    PORT
      LAYER M4 ;
        RECT  0 54.24 0.084 54.264 ;
    END
  END rsp_data[157]
  PIN rsp_data[158]
    DIRECTION OUTPUT ;
    USE SIGNAL ;
    PORT
      LAYER M4 ;
        RECT  0 54.576 0.084 54.6 ;
    END
  END rsp_data[158]
  PIN rsp_data[159]
    DIRECTION OUTPUT ;
    USE SIGNAL ;
    PORT
      LAYER M4 ;
        RECT  0 54.912 0.084 54.936 ;
    END
  END rsp_data[159]
  PIN rsp_data[15]
    DIRECTION OUTPUT ;
    USE SIGNAL ;
    PORT
      LAYER M4 ;
        RECT  0 6.24 0.084 6.264 ;
    END
  END rsp_data[15]
  PIN rsp_data[160]
    DIRECTION OUTPUT ;
    USE SIGNAL ;
    PORT
      LAYER M4 ;
        RECT  0 55.248 0.084 55.272 ;
    END
  END rsp_data[160]
  PIN rsp_data[161]
    DIRECTION OUTPUT ;
    USE SIGNAL ;
    PORT
      LAYER M4 ;
        RECT  0 55.584 0.084 55.608 ;
    END
  END rsp_data[161]
  PIN rsp_data[162]
    DIRECTION OUTPUT ;
    USE SIGNAL ;
    PORT
      LAYER M4 ;
        RECT  0 55.92 0.084 55.944 ;
    END
  END rsp_data[162]
  PIN rsp_data[163]
    DIRECTION OUTPUT ;
    USE SIGNAL ;
    PORT
      LAYER M4 ;
        RECT  0 56.256 0.084 56.28 ;
    END
  END rsp_data[163]
  PIN rsp_data[164]
    DIRECTION OUTPUT ;
    USE SIGNAL ;
    PORT
      LAYER M4 ;
        RECT  0 56.592 0.084 56.616 ;
    END
  END rsp_data[164]
  PIN rsp_data[165]
    DIRECTION OUTPUT ;
    USE SIGNAL ;
    PORT
      LAYER M4 ;
        RECT  0 56.928 0.084 56.952 ;
    END
  END rsp_data[165]
  PIN rsp_data[166]
    DIRECTION OUTPUT ;
    USE SIGNAL ;
    PORT
      LAYER M4 ;
        RECT  0 57.264 0.084 57.288 ;
    END
  END rsp_data[166]
  PIN rsp_data[167]
    DIRECTION OUTPUT ;
    USE SIGNAL ;
    PORT
      LAYER M4 ;
        RECT  0 57.648 0.084 57.672 ;
    END
  END rsp_data[167]
  PIN rsp_data[168]
    DIRECTION OUTPUT ;
    USE SIGNAL ;
    PORT
      LAYER M4 ;
        RECT  0 57.984 0.084 58.008 ;
    END
  END rsp_data[168]
  PIN rsp_data[169]
    DIRECTION OUTPUT ;
    USE SIGNAL ;
    PORT
      LAYER M4 ;
        RECT  0 58.32 0.084 58.344 ;
    END
  END rsp_data[169]
  PIN rsp_data[16]
    DIRECTION OUTPUT ;
    USE SIGNAL ;
    PORT
      LAYER M4 ;
        RECT  0 6.576 0.084 6.6 ;
    END
  END rsp_data[16]
  PIN rsp_data[170]
    DIRECTION OUTPUT ;
    USE SIGNAL ;
    PORT
      LAYER M4 ;
        RECT  0 58.656 0.084 58.68 ;
    END
  END rsp_data[170]
  PIN rsp_data[171]
    DIRECTION OUTPUT ;
    USE SIGNAL ;
    PORT
      LAYER M4 ;
        RECT  0 58.992 0.084 59.016 ;
    END
  END rsp_data[171]
  PIN rsp_data[172]
    DIRECTION OUTPUT ;
    USE SIGNAL ;
    PORT
      LAYER M4 ;
        RECT  0 59.328 0.084 59.352 ;
    END
  END rsp_data[172]
  PIN rsp_data[173]
    DIRECTION OUTPUT ;
    USE SIGNAL ;
    PORT
      LAYER M4 ;
        RECT  0 59.664 0.084 59.688 ;
    END
  END rsp_data[173]
  PIN rsp_data[174]
    DIRECTION OUTPUT ;
    USE SIGNAL ;
    PORT
      LAYER M4 ;
        RECT  0 60 0.084 60.024 ;
    END
  END rsp_data[174]
  PIN rsp_data[175]
    DIRECTION OUTPUT ;
    USE SIGNAL ;
    PORT
      LAYER M4 ;
        RECT  0 60.336 0.084 60.36 ;
    END
  END rsp_data[175]
  PIN rsp_data[176]
    DIRECTION OUTPUT ;
    USE SIGNAL ;
    PORT
      LAYER M4 ;
        RECT  0 60.672 0.084 60.696 ;
    END
  END rsp_data[176]
  PIN rsp_data[177]
    DIRECTION OUTPUT ;
    USE SIGNAL ;
    PORT
      LAYER M4 ;
        RECT  0 61.008 0.084 61.032 ;
    END
  END rsp_data[177]
  PIN rsp_data[178]
    DIRECTION OUTPUT ;
    USE SIGNAL ;
    PORT
      LAYER M4 ;
        RECT  0 61.344 0.084 61.368 ;
    END
  END rsp_data[178]
  PIN rsp_data[179]
    DIRECTION OUTPUT ;
    USE SIGNAL ;
    PORT
      LAYER M4 ;
        RECT  0 61.68 0.084 61.704 ;
    END
  END rsp_data[179]
  PIN rsp_data[17]
    DIRECTION OUTPUT ;
    USE SIGNAL ;
    PORT
      LAYER M4 ;
        RECT  0 6.912 0.084 6.936 ;
    END
  END rsp_data[17]
  PIN rsp_data[180]
    DIRECTION OUTPUT ;
    USE SIGNAL ;
    PORT
      LAYER M4 ;
        RECT  0 62.016 0.084 62.04 ;
    END
  END rsp_data[180]
  PIN rsp_data[181]
    DIRECTION OUTPUT ;
    USE SIGNAL ;
    PORT
      LAYER M4 ;
        RECT  0 62.352 0.084 62.376 ;
    END
  END rsp_data[181]
  PIN rsp_data[182]
    DIRECTION OUTPUT ;
    USE SIGNAL ;
    PORT
      LAYER M4 ;
        RECT  0 62.688 0.084 62.712 ;
    END
  END rsp_data[182]
  PIN rsp_data[183]
    DIRECTION OUTPUT ;
    USE SIGNAL ;
    PORT
      LAYER M4 ;
        RECT  0 63.024 0.084 63.048 ;
    END
  END rsp_data[183]
  PIN rsp_data[184]
    DIRECTION OUTPUT ;
    USE SIGNAL ;
    PORT
      LAYER M4 ;
        RECT  0 63.36 0.084 63.384 ;
    END
  END rsp_data[184]
  PIN rsp_data[185]
    DIRECTION OUTPUT ;
    USE SIGNAL ;
    PORT
      LAYER M4 ;
        RECT  0 63.696 0.084 63.72 ;
    END
  END rsp_data[185]
  PIN rsp_data[186]
    DIRECTION OUTPUT ;
    USE SIGNAL ;
    PORT
      LAYER M4 ;
        RECT  0 64.032 0.084 64.056 ;
    END
  END rsp_data[186]
  PIN rsp_data[187]
    DIRECTION OUTPUT ;
    USE SIGNAL ;
    PORT
      LAYER M4 ;
        RECT  0 64.368 0.084 64.392 ;
    END
  END rsp_data[187]
  PIN rsp_data[188]
    DIRECTION OUTPUT ;
    USE SIGNAL ;
    PORT
      LAYER M4 ;
        RECT  0 64.704 0.084 64.728 ;
    END
  END rsp_data[188]
  PIN rsp_data[189]
    DIRECTION OUTPUT ;
    USE SIGNAL ;
    PORT
      LAYER M4 ;
        RECT  0 65.04 0.084 65.064 ;
    END
  END rsp_data[189]
  PIN rsp_data[18]
    DIRECTION OUTPUT ;
    USE SIGNAL ;
    PORT
      LAYER M4 ;
        RECT  0 7.248 0.084 7.272 ;
    END
  END rsp_data[18]
  PIN rsp_data[190]
    DIRECTION OUTPUT ;
    USE SIGNAL ;
    PORT
      LAYER M4 ;
        RECT  0 65.424 0.084 65.448 ;
    END
  END rsp_data[190]
  PIN rsp_data[191]
    DIRECTION OUTPUT ;
    USE SIGNAL ;
    PORT
      LAYER M4 ;
        RECT  0 65.76 0.084 65.784 ;
    END
  END rsp_data[191]
  PIN rsp_data[192]
    DIRECTION OUTPUT ;
    USE SIGNAL ;
    PORT
      LAYER M4 ;
        RECT  0 66.096 0.084 66.12 ;
    END
  END rsp_data[192]
  PIN rsp_data[193]
    DIRECTION OUTPUT ;
    USE SIGNAL ;
    PORT
      LAYER M4 ;
        RECT  0 66.432 0.084 66.456 ;
    END
  END rsp_data[193]
  PIN rsp_data[194]
    DIRECTION OUTPUT ;
    USE SIGNAL ;
    PORT
      LAYER M4 ;
        RECT  0 66.768 0.084 66.792 ;
    END
  END rsp_data[194]
  PIN rsp_data[195]
    DIRECTION OUTPUT ;
    USE SIGNAL ;
    PORT
      LAYER M4 ;
        RECT  0 67.104 0.084 67.128 ;
    END
  END rsp_data[195]
  PIN rsp_data[196]
    DIRECTION OUTPUT ;
    USE SIGNAL ;
    PORT
      LAYER M4 ;
        RECT  0 67.44 0.084 67.464 ;
    END
  END rsp_data[196]
  PIN rsp_data[197]
    DIRECTION OUTPUT ;
    USE SIGNAL ;
    PORT
      LAYER M4 ;
        RECT  0 67.776 0.084 67.8 ;
    END
  END rsp_data[197]
  PIN rsp_data[198]
    DIRECTION OUTPUT ;
    USE SIGNAL ;
    PORT
      LAYER M4 ;
        RECT  0 68.112 0.084 68.136 ;
    END
  END rsp_data[198]
  PIN rsp_data[199]
    DIRECTION OUTPUT ;
    USE SIGNAL ;
    PORT
      LAYER M4 ;
        RECT  0 68.448 0.084 68.472 ;
    END
  END rsp_data[199]
  PIN rsp_data[19]
    DIRECTION OUTPUT ;
    USE SIGNAL ;
    PORT
      LAYER M4 ;
        RECT  0 7.584 0.084 7.608 ;
    END
  END rsp_data[19]
  PIN rsp_data[1]
    DIRECTION OUTPUT ;
    USE SIGNAL ;
    PORT
      LAYER M4 ;
        RECT  0 1.488 0.084 1.512 ;
    END
  END rsp_data[1]
  PIN rsp_data[200]
    DIRECTION OUTPUT ;
    USE SIGNAL ;
    PORT
      LAYER M4 ;
        RECT  0 68.784 0.084 68.808 ;
    END
  END rsp_data[200]
  PIN rsp_data[201]
    DIRECTION OUTPUT ;
    USE SIGNAL ;
    PORT
      LAYER M4 ;
        RECT  0 69.12 0.084 69.144 ;
    END
  END rsp_data[201]
  PIN rsp_data[202]
    DIRECTION OUTPUT ;
    USE SIGNAL ;
    PORT
      LAYER M4 ;
        RECT  0 69.456 0.084 69.48 ;
    END
  END rsp_data[202]
  PIN rsp_data[203]
    DIRECTION OUTPUT ;
    USE SIGNAL ;
    PORT
      LAYER M4 ;
        RECT  0 69.792 0.084 69.816 ;
    END
  END rsp_data[203]
  PIN rsp_data[204]
    DIRECTION OUTPUT ;
    USE SIGNAL ;
    PORT
      LAYER M4 ;
        RECT  0 70.128 0.084 70.152 ;
    END
  END rsp_data[204]
  PIN rsp_data[205]
    DIRECTION OUTPUT ;
    USE SIGNAL ;
    PORT
      LAYER M4 ;
        RECT  0 70.464 0.084 70.488 ;
    END
  END rsp_data[205]
  PIN rsp_data[206]
    DIRECTION OUTPUT ;
    USE SIGNAL ;
    PORT
      LAYER M4 ;
        RECT  0 70.8 0.084 70.824 ;
    END
  END rsp_data[206]
  PIN rsp_data[207]
    DIRECTION OUTPUT ;
    USE SIGNAL ;
    PORT
      LAYER M4 ;
        RECT  0 71.136 0.084 71.16 ;
    END
  END rsp_data[207]
  PIN rsp_data[208]
    DIRECTION OUTPUT ;
    USE SIGNAL ;
    PORT
      LAYER M4 ;
        RECT  0 71.472 0.084 71.496 ;
    END
  END rsp_data[208]
  PIN rsp_data[209]
    DIRECTION OUTPUT ;
    USE SIGNAL ;
    PORT
      LAYER M4 ;
        RECT  0 71.808 0.084 71.832 ;
    END
  END rsp_data[209]
  PIN rsp_data[20]
    DIRECTION OUTPUT ;
    USE SIGNAL ;
    PORT
      LAYER M4 ;
        RECT  0 7.92 0.084 7.944 ;
    END
  END rsp_data[20]
  PIN rsp_data[210]
    DIRECTION OUTPUT ;
    USE SIGNAL ;
    PORT
      LAYER M4 ;
        RECT  0 72.144 0.084 72.168 ;
    END
  END rsp_data[210]
  PIN rsp_data[211]
    DIRECTION OUTPUT ;
    USE SIGNAL ;
    PORT
      LAYER M4 ;
        RECT  0 72.48 0.084 72.504 ;
    END
  END rsp_data[211]
  PIN rsp_data[212]
    DIRECTION OUTPUT ;
    USE SIGNAL ;
    PORT
      LAYER M4 ;
        RECT  0 72.864 0.084 72.888 ;
    END
  END rsp_data[212]
  PIN rsp_data[213]
    DIRECTION OUTPUT ;
    USE SIGNAL ;
    PORT
      LAYER M4 ;
        RECT  0 73.2 0.084 73.224 ;
    END
  END rsp_data[213]
  PIN rsp_data[214]
    DIRECTION OUTPUT ;
    USE SIGNAL ;
    PORT
      LAYER M4 ;
        RECT  0 73.536 0.084 73.56 ;
    END
  END rsp_data[214]
  PIN rsp_data[215]
    DIRECTION OUTPUT ;
    USE SIGNAL ;
    PORT
      LAYER M4 ;
        RECT  0 73.872 0.084 73.896 ;
    END
  END rsp_data[215]
  PIN rsp_data[216]
    DIRECTION OUTPUT ;
    USE SIGNAL ;
    PORT
      LAYER M4 ;
        RECT  0 74.208 0.084 74.232 ;
    END
  END rsp_data[216]
  PIN rsp_data[217]
    DIRECTION OUTPUT ;
    USE SIGNAL ;
    PORT
      LAYER M4 ;
        RECT  0 74.544 0.084 74.568 ;
    END
  END rsp_data[217]
  PIN rsp_data[218]
    DIRECTION OUTPUT ;
    USE SIGNAL ;
    PORT
      LAYER M4 ;
        RECT  0 74.88 0.084 74.904 ;
    END
  END rsp_data[218]
  PIN rsp_data[219]
    DIRECTION OUTPUT ;
    USE SIGNAL ;
    PORT
      LAYER M4 ;
        RECT  0 75.216 0.084 75.24 ;
    END
  END rsp_data[219]
  PIN rsp_data[21]
    DIRECTION OUTPUT ;
    USE SIGNAL ;
    PORT
      LAYER M4 ;
        RECT  0 8.256 0.084 8.28 ;
    END
  END rsp_data[21]
  PIN rsp_data[220]
    DIRECTION OUTPUT ;
    USE SIGNAL ;
    PORT
      LAYER M4 ;
        RECT  0 75.552 0.084 75.576 ;
    END
  END rsp_data[220]
  PIN rsp_data[221]
    DIRECTION OUTPUT ;
    USE SIGNAL ;
    PORT
      LAYER M4 ;
        RECT  0 75.888 0.084 75.912 ;
    END
  END rsp_data[221]
  PIN rsp_data[222]
    DIRECTION OUTPUT ;
    USE SIGNAL ;
    PORT
      LAYER M4 ;
        RECT  0 76.224 0.084 76.248 ;
    END
  END rsp_data[222]
  PIN rsp_data[223]
    DIRECTION OUTPUT ;
    USE SIGNAL ;
    PORT
      LAYER M4 ;
        RECT  0 76.56 0.084 76.584 ;
    END
  END rsp_data[223]
  PIN rsp_data[224]
    DIRECTION OUTPUT ;
    USE SIGNAL ;
    PORT
      LAYER M4 ;
        RECT  0 76.896 0.084 76.92 ;
    END
  END rsp_data[224]
  PIN rsp_data[225]
    DIRECTION OUTPUT ;
    USE SIGNAL ;
    PORT
      LAYER M4 ;
        RECT  0 77.232 0.084 77.256 ;
    END
  END rsp_data[225]
  PIN rsp_data[226]
    DIRECTION OUTPUT ;
    USE SIGNAL ;
    PORT
      LAYER M4 ;
        RECT  0 77.568 0.084 77.592 ;
    END
  END rsp_data[226]
  PIN rsp_data[227]
    DIRECTION OUTPUT ;
    USE SIGNAL ;
    PORT
      LAYER M4 ;
        RECT  0 77.904 0.084 77.928 ;
    END
  END rsp_data[227]
  PIN rsp_data[228]
    DIRECTION OUTPUT ;
    USE SIGNAL ;
    PORT
      LAYER M4 ;
        RECT  0 78.24 0.084 78.264 ;
    END
  END rsp_data[228]
  PIN rsp_data[229]
    DIRECTION OUTPUT ;
    USE SIGNAL ;
    PORT
      LAYER M4 ;
        RECT  0 78.576 0.084 78.6 ;
    END
  END rsp_data[229]
  PIN rsp_data[22]
    DIRECTION OUTPUT ;
    USE SIGNAL ;
    PORT
      LAYER M4 ;
        RECT  0 8.592 0.084 8.616 ;
    END
  END rsp_data[22]
  PIN rsp_data[230]
    DIRECTION OUTPUT ;
    USE SIGNAL ;
    PORT
      LAYER M4 ;
        RECT  0 78.912 0.084 78.936 ;
    END
  END rsp_data[230]
  PIN rsp_data[231]
    DIRECTION OUTPUT ;
    USE SIGNAL ;
    PORT
      LAYER M4 ;
        RECT  0 79.248 0.084 79.272 ;
    END
  END rsp_data[231]
  PIN rsp_data[232]
    DIRECTION OUTPUT ;
    USE SIGNAL ;
    PORT
      LAYER M4 ;
        RECT  0 79.584 0.084 79.608 ;
    END
  END rsp_data[232]
  PIN rsp_data[233]
    DIRECTION OUTPUT ;
    USE SIGNAL ;
    PORT
      LAYER M4 ;
        RECT  0 79.92 0.084 79.944 ;
    END
  END rsp_data[233]
  PIN rsp_data[234]
    DIRECTION OUTPUT ;
    USE SIGNAL ;
    PORT
      LAYER M4 ;
        RECT  0 80.256 0.084 80.28 ;
    END
  END rsp_data[234]
  PIN rsp_data[235]
    DIRECTION OUTPUT ;
    USE SIGNAL ;
    PORT
      LAYER M4 ;
        RECT  0 80.64 0.084 80.664 ;
    END
  END rsp_data[235]
  PIN rsp_data[236]
    DIRECTION OUTPUT ;
    USE SIGNAL ;
    PORT
      LAYER M4 ;
        RECT  0 80.976 0.084 81 ;
    END
  END rsp_data[236]
  PIN rsp_data[237]
    DIRECTION OUTPUT ;
    USE SIGNAL ;
    PORT
      LAYER M4 ;
        RECT  0 81.312 0.084 81.336 ;
    END
  END rsp_data[237]
  PIN rsp_data[238]
    DIRECTION OUTPUT ;
    USE SIGNAL ;
    PORT
      LAYER M4 ;
        RECT  0 81.648 0.084 81.672 ;
    END
  END rsp_data[238]
  PIN rsp_data[239]
    DIRECTION OUTPUT ;
    USE SIGNAL ;
    PORT
      LAYER M4 ;
        RECT  0 81.984 0.084 82.008 ;
    END
  END rsp_data[239]
  PIN rsp_data[23]
    DIRECTION OUTPUT ;
    USE SIGNAL ;
    PORT
      LAYER M4 ;
        RECT  0 8.928 0.084 8.952 ;
    END
  END rsp_data[23]
  PIN rsp_data[240]
    DIRECTION OUTPUT ;
    USE SIGNAL ;
    PORT
      LAYER M4 ;
        RECT  0 82.32 0.084 82.344 ;
    END
  END rsp_data[240]
  PIN rsp_data[241]
    DIRECTION OUTPUT ;
    USE SIGNAL ;
    PORT
      LAYER M4 ;
        RECT  0 82.656 0.084 82.68 ;
    END
  END rsp_data[241]
  PIN rsp_data[242]
    DIRECTION OUTPUT ;
    USE SIGNAL ;
    PORT
      LAYER M4 ;
        RECT  0 82.992 0.084 83.016 ;
    END
  END rsp_data[242]
  PIN rsp_data[243]
    DIRECTION OUTPUT ;
    USE SIGNAL ;
    PORT
      LAYER M4 ;
        RECT  0 83.328 0.084 83.352 ;
    END
  END rsp_data[243]
  PIN rsp_data[244]
    DIRECTION OUTPUT ;
    USE SIGNAL ;
    PORT
      LAYER M4 ;
        RECT  0 83.664 0.084 83.688 ;
    END
  END rsp_data[244]
  PIN rsp_data[245]
    DIRECTION OUTPUT ;
    USE SIGNAL ;
    PORT
      LAYER M4 ;
        RECT  0 84 0.084 84.024 ;
    END
  END rsp_data[245]
  PIN rsp_data[246]
    DIRECTION OUTPUT ;
    USE SIGNAL ;
    PORT
      LAYER M4 ;
        RECT  0 84.336 0.084 84.36 ;
    END
  END rsp_data[246]
  PIN rsp_data[247]
    DIRECTION OUTPUT ;
    USE SIGNAL ;
    PORT
      LAYER M4 ;
        RECT  0 84.672 0.084 84.696 ;
    END
  END rsp_data[247]
  PIN rsp_data[248]
    DIRECTION OUTPUT ;
    USE SIGNAL ;
    PORT
      LAYER M4 ;
        RECT  0 85.008 0.084 85.032 ;
    END
  END rsp_data[248]
  PIN rsp_data[249]
    DIRECTION OUTPUT ;
    USE SIGNAL ;
    PORT
      LAYER M4 ;
        RECT  0 85.344 0.084 85.368 ;
    END
  END rsp_data[249]
  PIN rsp_data[24]
    DIRECTION OUTPUT ;
    USE SIGNAL ;
    PORT
      LAYER M4 ;
        RECT  0 9.264 0.084 9.288 ;
    END
  END rsp_data[24]
  PIN rsp_data[250]
    DIRECTION OUTPUT ;
    USE SIGNAL ;
    PORT
      LAYER M4 ;
        RECT  0 85.68 0.084 85.704 ;
    END
  END rsp_data[250]
  PIN rsp_data[251]
    DIRECTION OUTPUT ;
    USE SIGNAL ;
    PORT
      LAYER M4 ;
        RECT  0 86.016 0.084 86.04 ;
    END
  END rsp_data[251]
  PIN rsp_data[252]
    DIRECTION OUTPUT ;
    USE SIGNAL ;
    PORT
      LAYER M4 ;
        RECT  0 86.352 0.084 86.376 ;
    END
  END rsp_data[252]
  PIN rsp_data[253]
    DIRECTION OUTPUT ;
    USE SIGNAL ;
    PORT
      LAYER M4 ;
        RECT  0 86.688 0.084 86.712 ;
    END
  END rsp_data[253]
  PIN rsp_data[254]
    DIRECTION OUTPUT ;
    USE SIGNAL ;
    PORT
      LAYER M4 ;
        RECT  0 87.024 0.084 87.048 ;
    END
  END rsp_data[254]
  PIN rsp_data[255]
    DIRECTION OUTPUT ;
    USE SIGNAL ;
    PORT
      LAYER M4 ;
        RECT  0 87.36 0.084 87.384 ;
    END
  END rsp_data[255]
  PIN rsp_data[25]
    DIRECTION OUTPUT ;
    USE SIGNAL ;
    PORT
      LAYER M4 ;
        RECT  0 9.6 0.084 9.624 ;
    END
  END rsp_data[25]
  PIN rsp_data[26]
    DIRECTION OUTPUT ;
    USE SIGNAL ;
    PORT
      LAYER M4 ;
        RECT  0 9.936 0.084 9.96 ;
    END
  END rsp_data[26]
  PIN rsp_data[27]
    DIRECTION OUTPUT ;
    USE SIGNAL ;
    PORT
      LAYER M4 ;
        RECT  0 10.272 0.084 10.296 ;
    END
  END rsp_data[27]
  PIN rsp_data[28]
    DIRECTION OUTPUT ;
    USE SIGNAL ;
    PORT
      LAYER M4 ;
        RECT  0 10.608 0.084 10.632 ;
    END
  END rsp_data[28]
  PIN rsp_data[29]
    DIRECTION OUTPUT ;
    USE SIGNAL ;
    PORT
      LAYER M4 ;
        RECT  0 10.944 0.084 10.968 ;
    END
  END rsp_data[29]
  PIN rsp_data[2]
    DIRECTION OUTPUT ;
    USE SIGNAL ;
    PORT
      LAYER M4 ;
        RECT  0 1.824 0.084 1.848 ;
    END
  END rsp_data[2]
  PIN rsp_data[30]
    DIRECTION OUTPUT ;
    USE SIGNAL ;
    PORT
      LAYER M4 ;
        RECT  0 11.28 0.084 11.304 ;
    END
  END rsp_data[30]
  PIN rsp_data[31]
    DIRECTION OUTPUT ;
    USE SIGNAL ;
    PORT
      LAYER M4 ;
        RECT  0 11.616 0.084 11.64 ;
    END
  END rsp_data[31]
  PIN rsp_data[32]
    DIRECTION OUTPUT ;
    USE SIGNAL ;
    PORT
      LAYER M4 ;
        RECT  0 12 0.084 12.024 ;
    END
  END rsp_data[32]
  PIN rsp_data[33]
    DIRECTION OUTPUT ;
    USE SIGNAL ;
    PORT
      LAYER M4 ;
        RECT  0 12.336 0.084 12.36 ;
    END
  END rsp_data[33]
  PIN rsp_data[34]
    DIRECTION OUTPUT ;
    USE SIGNAL ;
    PORT
      LAYER M4 ;
        RECT  0 12.672 0.084 12.696 ;
    END
  END rsp_data[34]
  PIN rsp_data[35]
    DIRECTION OUTPUT ;
    USE SIGNAL ;
    PORT
      LAYER M4 ;
        RECT  0 13.008 0.084 13.032 ;
    END
  END rsp_data[35]
  PIN rsp_data[36]
    DIRECTION OUTPUT ;
    USE SIGNAL ;
    PORT
      LAYER M4 ;
        RECT  0 13.344 0.084 13.368 ;
    END
  END rsp_data[36]
  PIN rsp_data[37]
    DIRECTION OUTPUT ;
    USE SIGNAL ;
    PORT
      LAYER M4 ;
        RECT  0 13.68 0.084 13.704 ;
    END
  END rsp_data[37]
  PIN rsp_data[38]
    DIRECTION OUTPUT ;
    USE SIGNAL ;
    PORT
      LAYER M4 ;
        RECT  0 14.016 0.084 14.04 ;
    END
  END rsp_data[38]
  PIN rsp_data[39]
    DIRECTION OUTPUT ;
    USE SIGNAL ;
    PORT
      LAYER M4 ;
        RECT  0 14.352 0.084 14.376 ;
    END
  END rsp_data[39]
  PIN rsp_data[3]
    DIRECTION OUTPUT ;
    USE SIGNAL ;
    PORT
      LAYER M4 ;
        RECT  0 2.16 0.084 2.184 ;
    END
  END rsp_data[3]
  PIN rsp_data[40]
    DIRECTION OUTPUT ;
    USE SIGNAL ;
    PORT
      LAYER M4 ;
        RECT  0 14.688 0.084 14.712 ;
    END
  END rsp_data[40]
  PIN rsp_data[41]
    DIRECTION OUTPUT ;
    USE SIGNAL ;
    PORT
      LAYER M4 ;
        RECT  0 15.024 0.084 15.048 ;
    END
  END rsp_data[41]
  PIN rsp_data[42]
    DIRECTION OUTPUT ;
    USE SIGNAL ;
    PORT
      LAYER M4 ;
        RECT  0 15.36 0.084 15.384 ;
    END
  END rsp_data[42]
  PIN rsp_data[43]
    DIRECTION OUTPUT ;
    USE SIGNAL ;
    PORT
      LAYER M4 ;
        RECT  0 15.696 0.084 15.72 ;
    END
  END rsp_data[43]
  PIN rsp_data[44]
    DIRECTION OUTPUT ;
    USE SIGNAL ;
    PORT
      LAYER M4 ;
        RECT  0 16.032 0.084 16.056 ;
    END
  END rsp_data[44]
  PIN rsp_data[45]
    DIRECTION OUTPUT ;
    USE SIGNAL ;
    PORT
      LAYER M4 ;
        RECT  0 16.368 0.084 16.392 ;
    END
  END rsp_data[45]
  PIN rsp_data[46]
    DIRECTION OUTPUT ;
    USE SIGNAL ;
    PORT
      LAYER M4 ;
        RECT  0 16.704 0.084 16.728 ;
    END
  END rsp_data[46]
  PIN rsp_data[47]
    DIRECTION OUTPUT ;
    USE SIGNAL ;
    PORT
      LAYER M4 ;
        RECT  0 17.04 0.084 17.064 ;
    END
  END rsp_data[47]
  PIN rsp_data[48]
    DIRECTION OUTPUT ;
    USE SIGNAL ;
    PORT
      LAYER M4 ;
        RECT  0 17.376 0.084 17.4 ;
    END
  END rsp_data[48]
  PIN rsp_data[49]
    DIRECTION OUTPUT ;
    USE SIGNAL ;
    PORT
      LAYER M4 ;
        RECT  0 17.712 0.084 17.736 ;
    END
  END rsp_data[49]
  PIN rsp_data[4]
    DIRECTION OUTPUT ;
    USE SIGNAL ;
    PORT
      LAYER M4 ;
        RECT  0 2.496 0.084 2.52 ;
    END
  END rsp_data[4]
  PIN rsp_data[50]
    DIRECTION OUTPUT ;
    USE SIGNAL ;
    PORT
      LAYER M4 ;
        RECT  0 18.048 0.084 18.072 ;
    END
  END rsp_data[50]
  PIN rsp_data[51]
    DIRECTION OUTPUT ;
    USE SIGNAL ;
    PORT
      LAYER M4 ;
        RECT  0 18.384 0.084 18.408 ;
    END
  END rsp_data[51]
  PIN rsp_data[52]
    DIRECTION OUTPUT ;
    USE SIGNAL ;
    PORT
      LAYER M4 ;
        RECT  0 18.72 0.084 18.744 ;
    END
  END rsp_data[52]
  PIN rsp_data[53]
    DIRECTION OUTPUT ;
    USE SIGNAL ;
    PORT
      LAYER M4 ;
        RECT  0 19.056 0.084 19.08 ;
    END
  END rsp_data[53]
  PIN rsp_data[54]
    DIRECTION OUTPUT ;
    USE SIGNAL ;
    PORT
      LAYER M4 ;
        RECT  0 19.44 0.084 19.464 ;
    END
  END rsp_data[54]
  PIN rsp_data[55]
    DIRECTION OUTPUT ;
    USE SIGNAL ;
    PORT
      LAYER M4 ;
        RECT  0 19.776 0.084 19.8 ;
    END
  END rsp_data[55]
  PIN rsp_data[56]
    DIRECTION OUTPUT ;
    USE SIGNAL ;
    PORT
      LAYER M4 ;
        RECT  0 20.112 0.084 20.136 ;
    END
  END rsp_data[56]
  PIN rsp_data[57]
    DIRECTION OUTPUT ;
    USE SIGNAL ;
    PORT
      LAYER M4 ;
        RECT  0 20.448 0.084 20.472 ;
    END
  END rsp_data[57]
  PIN rsp_data[58]
    DIRECTION OUTPUT ;
    USE SIGNAL ;
    PORT
      LAYER M4 ;
        RECT  0 20.784 0.084 20.808 ;
    END
  END rsp_data[58]
  PIN rsp_data[59]
    DIRECTION OUTPUT ;
    USE SIGNAL ;
    PORT
      LAYER M4 ;
        RECT  0 21.12 0.084 21.144 ;
    END
  END rsp_data[59]
  PIN rsp_data[5]
    DIRECTION OUTPUT ;
    USE SIGNAL ;
    PORT
      LAYER M4 ;
        RECT  0 2.832 0.084 2.856 ;
    END
  END rsp_data[5]
  PIN rsp_data[60]
    DIRECTION OUTPUT ;
    USE SIGNAL ;
    PORT
      LAYER M4 ;
        RECT  0 21.456 0.084 21.48 ;
    END
  END rsp_data[60]
  PIN rsp_data[61]
    DIRECTION OUTPUT ;
    USE SIGNAL ;
    PORT
      LAYER M4 ;
        RECT  0 21.792 0.084 21.816 ;
    END
  END rsp_data[61]
  PIN rsp_data[62]
    DIRECTION OUTPUT ;
    USE SIGNAL ;
    PORT
      LAYER M4 ;
        RECT  0 22.128 0.084 22.152 ;
    END
  END rsp_data[62]
  PIN rsp_data[63]
    DIRECTION OUTPUT ;
    USE SIGNAL ;
    PORT
      LAYER M4 ;
        RECT  0 22.464 0.084 22.488 ;
    END
  END rsp_data[63]
  PIN rsp_data[64]
    DIRECTION OUTPUT ;
    USE SIGNAL ;
    PORT
      LAYER M4 ;
        RECT  0 22.8 0.084 22.824 ;
    END
  END rsp_data[64]
  PIN rsp_data[65]
    DIRECTION OUTPUT ;
    USE SIGNAL ;
    PORT
      LAYER M4 ;
        RECT  0 23.136 0.084 23.16 ;
    END
  END rsp_data[65]
  PIN rsp_data[66]
    DIRECTION OUTPUT ;
    USE SIGNAL ;
    PORT
      LAYER M4 ;
        RECT  0 23.472 0.084 23.496 ;
    END
  END rsp_data[66]
  PIN rsp_data[67]
    DIRECTION OUTPUT ;
    USE SIGNAL ;
    PORT
      LAYER M4 ;
        RECT  0 23.808 0.084 23.832 ;
    END
  END rsp_data[67]
  PIN rsp_data[68]
    DIRECTION OUTPUT ;
    USE SIGNAL ;
    PORT
      LAYER M4 ;
        RECT  0 24.144 0.084 24.168 ;
    END
  END rsp_data[68]
  PIN rsp_data[69]
    DIRECTION OUTPUT ;
    USE SIGNAL ;
    PORT
      LAYER M4 ;
        RECT  0 24.48 0.084 24.504 ;
    END
  END rsp_data[69]
  PIN rsp_data[6]
    DIRECTION OUTPUT ;
    USE SIGNAL ;
    PORT
      LAYER M4 ;
        RECT  0 3.168 0.084 3.192 ;
    END
  END rsp_data[6]
  PIN rsp_data[70]
    DIRECTION OUTPUT ;
    USE SIGNAL ;
    PORT
      LAYER M4 ;
        RECT  0 24.816 0.084 24.84 ;
    END
  END rsp_data[70]
  PIN rsp_data[71]
    DIRECTION OUTPUT ;
    USE SIGNAL ;
    PORT
      LAYER M4 ;
        RECT  0 25.152 0.084 25.176 ;
    END
  END rsp_data[71]
  PIN rsp_data[72]
    DIRECTION OUTPUT ;
    USE SIGNAL ;
    PORT
      LAYER M4 ;
        RECT  0 25.488 0.084 25.512 ;
    END
  END rsp_data[72]
  PIN rsp_data[73]
    DIRECTION OUTPUT ;
    USE SIGNAL ;
    PORT
      LAYER M4 ;
        RECT  0 25.824 0.084 25.848 ;
    END
  END rsp_data[73]
  PIN rsp_data[74]
    DIRECTION OUTPUT ;
    USE SIGNAL ;
    PORT
      LAYER M4 ;
        RECT  0 26.16 0.084 26.184 ;
    END
  END rsp_data[74]
  PIN rsp_data[75]
    DIRECTION OUTPUT ;
    USE SIGNAL ;
    PORT
      LAYER M4 ;
        RECT  0 26.496 0.084 26.52 ;
    END
  END rsp_data[75]
  PIN rsp_data[76]
    DIRECTION OUTPUT ;
    USE SIGNAL ;
    PORT
      LAYER M4 ;
        RECT  0 26.832 0.084 26.856 ;
    END
  END rsp_data[76]
  PIN rsp_data[77]
    DIRECTION OUTPUT ;
    USE SIGNAL ;
    PORT
      LAYER M4 ;
        RECT  0 27.216 0.084 27.24 ;
    END
  END rsp_data[77]
  PIN rsp_data[78]
    DIRECTION OUTPUT ;
    USE SIGNAL ;
    PORT
      LAYER M4 ;
        RECT  0 27.552 0.084 27.576 ;
    END
  END rsp_data[78]
  PIN rsp_data[79]
    DIRECTION OUTPUT ;
    USE SIGNAL ;
    PORT
      LAYER M4 ;
        RECT  0 27.888 0.084 27.912 ;
    END
  END rsp_data[79]
  PIN rsp_data[7]
    DIRECTION OUTPUT ;
    USE SIGNAL ;
    PORT
      LAYER M4 ;
        RECT  0 3.504 0.084 3.528 ;
    END
  END rsp_data[7]
  PIN rsp_data[80]
    DIRECTION OUTPUT ;
    USE SIGNAL ;
    PORT
      LAYER M4 ;
        RECT  0 28.224 0.084 28.248 ;
    END
  END rsp_data[80]
  PIN rsp_data[81]
    DIRECTION OUTPUT ;
    USE SIGNAL ;
    PORT
      LAYER M4 ;
        RECT  0 28.56 0.084 28.584 ;
    END
  END rsp_data[81]
  PIN rsp_data[82]
    DIRECTION OUTPUT ;
    USE SIGNAL ;
    PORT
      LAYER M4 ;
        RECT  0 28.896 0.084 28.92 ;
    END
  END rsp_data[82]
  PIN rsp_data[83]
    DIRECTION OUTPUT ;
    USE SIGNAL ;
    PORT
      LAYER M4 ;
        RECT  0 29.232 0.084 29.256 ;
    END
  END rsp_data[83]
  PIN rsp_data[84]
    DIRECTION OUTPUT ;
    USE SIGNAL ;
    PORT
      LAYER M4 ;
        RECT  0 29.568 0.084 29.592 ;
    END
  END rsp_data[84]
  PIN rsp_data[85]
    DIRECTION OUTPUT ;
    USE SIGNAL ;
    PORT
      LAYER M4 ;
        RECT  0 29.904 0.084 29.928 ;
    END
  END rsp_data[85]
  PIN rsp_data[86]
    DIRECTION OUTPUT ;
    USE SIGNAL ;
    PORT
      LAYER M4 ;
        RECT  0 30.24 0.084 30.264 ;
    END
  END rsp_data[86]
  PIN rsp_data[87]
    DIRECTION OUTPUT ;
    USE SIGNAL ;
    PORT
      LAYER M4 ;
        RECT  0 30.576 0.084 30.6 ;
    END
  END rsp_data[87]
  PIN rsp_data[88]
    DIRECTION OUTPUT ;
    USE SIGNAL ;
    PORT
      LAYER M4 ;
        RECT  0 30.912 0.084 30.936 ;
    END
  END rsp_data[88]
  PIN rsp_data[89]
    DIRECTION OUTPUT ;
    USE SIGNAL ;
    PORT
      LAYER M4 ;
        RECT  0 31.248 0.084 31.272 ;
    END
  END rsp_data[89]
  PIN rsp_data[8]
    DIRECTION OUTPUT ;
    USE SIGNAL ;
    PORT
      LAYER M4 ;
        RECT  0 3.84 0.084 3.864 ;
    END
  END rsp_data[8]
  PIN rsp_data[90]
    DIRECTION OUTPUT ;
    USE SIGNAL ;
    PORT
      LAYER M4 ;
        RECT  0 31.584 0.084 31.608 ;
    END
  END rsp_data[90]
  PIN rsp_data[91]
    DIRECTION OUTPUT ;
    USE SIGNAL ;
    PORT
      LAYER M4 ;
        RECT  0 31.92 0.084 31.944 ;
    END
  END rsp_data[91]
  PIN rsp_data[92]
    DIRECTION OUTPUT ;
    USE SIGNAL ;
    PORT
      LAYER M4 ;
        RECT  0 32.256 0.084 32.28 ;
    END
  END rsp_data[92]
  PIN rsp_data[93]
    DIRECTION OUTPUT ;
    USE SIGNAL ;
    PORT
      LAYER M4 ;
        RECT  0 32.592 0.084 32.616 ;
    END
  END rsp_data[93]
  PIN rsp_data[94]
    DIRECTION OUTPUT ;
    USE SIGNAL ;
    PORT
      LAYER M4 ;
        RECT  0 32.928 0.084 32.952 ;
    END
  END rsp_data[94]
  PIN rsp_data[95]
    DIRECTION OUTPUT ;
    USE SIGNAL ;
    PORT
      LAYER M4 ;
        RECT  0 33.264 0.084 33.288 ;
    END
  END rsp_data[95]
  PIN rsp_data[96]
    DIRECTION OUTPUT ;
    USE SIGNAL ;
    PORT
      LAYER M4 ;
        RECT  0 33.6 0.084 33.624 ;
    END
  END rsp_data[96]
  PIN rsp_data[97]
    DIRECTION OUTPUT ;
    USE SIGNAL ;
    PORT
      LAYER M4 ;
        RECT  0 33.936 0.084 33.96 ;
    END
  END rsp_data[97]
  PIN rsp_data[98]
    DIRECTION OUTPUT ;
    USE SIGNAL ;
    PORT
      LAYER M4 ;
        RECT  0 34.272 0.084 34.296 ;
    END
  END rsp_data[98]
  PIN rsp_data[99]
    DIRECTION OUTPUT ;
    USE SIGNAL ;
    PORT
      LAYER M4 ;
        RECT  0 34.608 0.084 34.632 ;
    END
  END rsp_data[99]
  PIN rsp_data[9]
    DIRECTION OUTPUT ;
    USE SIGNAL ;
    PORT
      LAYER M4 ;
        RECT  0 4.224 0.084 4.248 ;
    END
  END rsp_data[9]
  PIN rst_n
    DIRECTION INPUT ;
    USE SIGNAL ;
    PORT
      LAYER M5 ;
        RECT  138.72 88.476 138.744 88.56 ;
    END
  END rst_n
  PIN VDD
    DIRECTION INOUT ;
    USE POWER ;
    PORT
      LAYER M5 ;
        RECT  137.592 2.151 137.712 86.409 ;
        RECT  132.192 2.151 132.312 86.409 ;
        RECT  126.792 2.151 126.912 86.409 ;
        RECT  121.392 2.151 121.512 86.409 ;
        RECT  115.992 2.151 116.112 86.409 ;
        RECT  110.592 2.151 110.712 86.409 ;
        RECT  105.192 2.151 105.312 86.409 ;
        RECT  99.792 2.151 99.912 86.409 ;
        RECT  94.392 2.151 94.512 86.409 ;
        RECT  88.992 2.151 89.112 86.409 ;
        RECT  83.592 2.151 83.712 86.409 ;
        RECT  78.192 2.151 78.312 86.409 ;
        RECT  72.792 2.151 72.912 86.409 ;
        RECT  67.392 2.151 67.512 86.409 ;
        RECT  61.992 2.151 62.112 86.409 ;
        RECT  56.592 2.151 56.712 86.409 ;
        RECT  51.192 2.151 51.312 86.409 ;
        RECT  45.792 2.151 45.912 86.409 ;
        RECT  40.392 2.151 40.512 86.409 ;
        RECT  34.992 2.151 35.112 86.409 ;
        RECT  29.592 2.151 29.712 86.409 ;
        RECT  24.192 2.151 24.312 86.409 ;
        RECT  18.792 2.151 18.912 86.409 ;
        RECT  13.392 2.151 13.512 86.409 ;
        RECT  7.992 2.151 8.112 86.409 ;
        RECT  2.592 2.151 2.712 86.409 ;
    END
  END VDD
  PIN VSS
    DIRECTION INOUT ;
    USE GROUND ;
    PORT
      LAYER M5 ;
        RECT  137.4 2.137 137.52 86.423 ;
        RECT  132 2.137 132.12 86.423 ;
        RECT  126.6 2.137 126.72 86.423 ;
        RECT  121.2 2.137 121.32 86.423 ;
        RECT  115.8 2.137 115.92 86.423 ;
        RECT  110.4 2.137 110.52 86.423 ;
        RECT  105 2.137 105.12 86.423 ;
        RECT  99.6 2.137 99.72 86.423 ;
        RECT  94.2 2.137 94.32 86.423 ;
        RECT  88.8 2.137 88.92 86.423 ;
        RECT  83.4 2.137 83.52 86.423 ;
        RECT  78 2.137 78.12 86.423 ;
        RECT  72.6 2.137 72.72 86.423 ;
        RECT  67.2 2.137 67.32 86.423 ;
        RECT  61.8 2.137 61.92 86.423 ;
        RECT  56.4 2.137 56.52 86.423 ;
        RECT  51 2.137 51.12 86.423 ;
        RECT  45.6 2.137 45.72 86.423 ;
        RECT  40.2 2.137 40.32 86.423 ;
        RECT  34.8 2.137 34.92 86.423 ;
        RECT  29.4 2.137 29.52 86.423 ;
        RECT  24 2.137 24.12 86.423 ;
        RECT  18.6 2.137 18.72 86.423 ;
        RECT  13.2 2.137 13.32 86.423 ;
        RECT  7.8 2.137 7.92 86.423 ;
        RECT  2.4 2.137 2.52 86.423 ;
    END
  END VSS
  OBS
    LAYER RVTN ;
     RECT  2.16 2.16 138.24 2.295 ;
     RECT  2.16 2.565 138.24 2.835 ;
     RECT  2.16 3.105 138.24 3.375 ;
     RECT  2.16 3.645 138.24 3.915 ;
     RECT  2.16 4.185 138.24 4.455 ;
     RECT  2.16 4.725 138.24 4.995 ;
     RECT  2.16 5.265 138.24 5.535 ;
     RECT  2.16 5.805 138.24 6.075 ;
     RECT  2.16 6.345 138.24 6.615 ;
     RECT  2.16 6.885 138.24 7.155 ;
     RECT  2.16 7.425 138.24 7.695 ;
     RECT  2.16 7.965 138.24 8.235 ;
     RECT  2.16 8.505 138.24 8.775 ;
     RECT  2.16 9.045 138.24 9.315 ;
     RECT  2.16 9.585 138.24 9.855 ;
     RECT  2.16 10.125 138.24 10.395 ;
     RECT  2.16 10.665 138.24 10.935 ;
     RECT  2.16 11.205 138.24 11.475 ;
     RECT  2.16 11.745 138.24 12.015 ;
     RECT  2.16 12.285 138.24 12.555 ;
     RECT  2.16 12.825 138.24 13.095 ;
     RECT  2.16 13.365 138.24 13.635 ;
     RECT  2.16 13.905 138.24 14.175 ;
     RECT  2.16 14.445 138.24 14.715 ;
     RECT  2.16 14.985 138.24 15.255 ;
     RECT  2.16 15.525 138.24 15.795 ;
     RECT  2.16 16.065 138.24 16.335 ;
     RECT  2.16 16.605 138.24 16.875 ;
     RECT  2.16 17.145 138.24 17.415 ;
     RECT  2.16 17.685 138.24 17.955 ;
     RECT  2.16 18.225 138.24 18.495 ;
     RECT  2.16 18.765 138.24 19.035 ;
     RECT  2.16 19.305 138.24 19.575 ;
     RECT  2.16 19.845 138.24 20.115 ;
     RECT  2.16 20.385 138.24 20.655 ;
     RECT  2.16 20.925 138.24 21.195 ;
     RECT  2.16 21.465 138.24 21.6 ;
     RECT  2.16 21.6 20.412 21.735 ;
     RECT  119.34 21.6 138.24 21.735 ;
     RECT  2.16 22.005 20.412 22.275 ;
     RECT  119.34 22.005 138.24 22.275 ;
     RECT  2.16 22.545 20.412 22.815 ;
     RECT  119.34 22.545 138.24 22.815 ;
     RECT  2.16 23.085 20.412 23.355 ;
     RECT  119.34 23.085 138.24 23.355 ;
     RECT  2.16 23.625 20.412 23.895 ;
     RECT  119.34 23.625 138.24 23.895 ;
     RECT  2.16 24.165 20.412 24.435 ;
     RECT  119.34 24.165 138.24 24.435 ;
     RECT  2.16 24.705 20.412 24.975 ;
     RECT  119.34 24.705 138.24 24.975 ;
     RECT  2.16 25.245 20.412 25.515 ;
     RECT  119.34 25.245 138.24 25.515 ;
     RECT  2.16 25.785 20.412 26.055 ;
     RECT  119.34 25.785 138.24 26.055 ;
     RECT  2.16 26.325 20.412 26.595 ;
     RECT  119.34 26.325 138.24 26.595 ;
     RECT  2.16 26.865 20.412 27.135 ;
     RECT  119.34 26.865 138.24 27.135 ;
     RECT  2.16 27.405 20.412 27.675 ;
     RECT  119.34 27.405 138.24 27.675 ;
     RECT  2.16 27.945 20.412 28.215 ;
     RECT  119.34 27.945 138.24 28.215 ;
     RECT  2.16 28.485 20.412 28.755 ;
     RECT  119.34 28.485 138.24 28.755 ;
     RECT  2.16 29.025 20.412 29.295 ;
     RECT  119.34 29.025 138.24 29.295 ;
     RECT  2.16 29.565 20.412 29.835 ;
     RECT  119.34 29.565 138.24 29.835 ;
     RECT  2.16 30.105 20.412 30.375 ;
     RECT  119.34 30.105 138.24 30.375 ;
     RECT  2.16 30.645 20.412 30.915 ;
     RECT  119.34 30.645 138.24 30.915 ;
     RECT  2.16 31.185 20.412 31.455 ;
     RECT  119.34 31.185 138.24 31.455 ;
     RECT  2.16 31.725 20.412 31.995 ;
     RECT  119.34 31.725 138.24 31.995 ;
     RECT  2.16 32.265 20.412 32.535 ;
     RECT  119.34 32.265 138.24 32.535 ;
     RECT  2.16 32.805 20.412 33.075 ;
     RECT  119.34 32.805 138.24 33.075 ;
     RECT  2.16 33.345 20.412 33.615 ;
     RECT  119.34 33.345 138.24 33.615 ;
     RECT  2.16 33.885 20.412 34.155 ;
     RECT  119.34 33.885 138.24 34.155 ;
     RECT  2.16 34.425 20.412 34.695 ;
     RECT  119.34 34.425 138.24 34.695 ;
     RECT  2.16 34.965 20.412 35.235 ;
     RECT  119.34 34.965 138.24 35.235 ;
     RECT  2.16 35.505 20.412 35.775 ;
     RECT  119.34 35.505 138.24 35.775 ;
     RECT  2.16 36.045 20.412 36.315 ;
     RECT  119.34 36.045 138.24 36.315 ;
     RECT  2.16 36.585 20.412 36.855 ;
     RECT  119.34 36.585 138.24 36.855 ;
     RECT  2.16 37.125 20.412 37.395 ;
     RECT  119.34 37.125 138.24 37.395 ;
     RECT  2.16 37.665 20.412 37.935 ;
     RECT  119.34 37.665 138.24 37.935 ;
     RECT  2.16 38.205 20.412 38.475 ;
     RECT  119.34 38.205 138.24 38.475 ;
     RECT  2.16 38.745 20.412 39.015 ;
     RECT  119.34 38.745 138.24 39.015 ;
     RECT  2.16 39.285 20.412 39.555 ;
     RECT  119.34 39.285 138.24 39.555 ;
     RECT  2.16 39.825 20.412 40.095 ;
     RECT  119.34 39.825 138.24 40.095 ;
     RECT  2.16 40.365 20.412 40.635 ;
     RECT  119.34 40.365 138.24 40.635 ;
     RECT  2.16 40.905 20.412 41.175 ;
     RECT  119.34 40.905 138.24 41.175 ;
     RECT  2.16 41.445 20.412 41.715 ;
     RECT  119.34 41.445 138.24 41.715 ;
     RECT  2.16 41.985 20.412 42.255 ;
     RECT  119.34 41.985 138.24 42.255 ;
     RECT  2.16 42.525 20.412 42.795 ;
     RECT  119.34 42.525 138.24 42.795 ;
     RECT  2.16 43.065 20.412 43.335 ;
     RECT  119.34 43.065 138.24 43.335 ;
     RECT  2.16 43.605 20.412 43.875 ;
     RECT  119.34 43.605 138.24 43.875 ;
     RECT  2.16 44.145 20.412 44.415 ;
     RECT  119.34 44.145 138.24 44.415 ;
     RECT  2.16 44.685 20.412 44.955 ;
     RECT  119.34 44.685 138.24 44.955 ;
     RECT  2.16 45.225 20.412 45.495 ;
     RECT  119.34 45.225 138.24 45.495 ;
     RECT  2.16 45.765 20.412 46.035 ;
     RECT  119.34 45.765 138.24 46.035 ;
     RECT  2.16 46.305 20.412 46.575 ;
     RECT  119.34 46.305 138.24 46.575 ;
     RECT  2.16 46.845 20.412 47.115 ;
     RECT  119.34 46.845 138.24 47.115 ;
     RECT  2.16 47.385 20.412 47.655 ;
     RECT  119.34 47.385 138.24 47.655 ;
     RECT  2.16 47.925 20.412 48.195 ;
     RECT  119.34 47.925 138.24 48.195 ;
     RECT  2.16 48.465 20.412 48.735 ;
     RECT  119.34 48.465 138.24 48.735 ;
     RECT  2.16 49.005 20.412 49.275 ;
     RECT  119.34 49.005 138.24 49.275 ;
     RECT  2.16 49.545 20.412 49.815 ;
     RECT  119.34 49.545 138.24 49.815 ;
     RECT  2.16 50.085 20.412 50.355 ;
     RECT  119.34 50.085 138.24 50.355 ;
     RECT  2.16 50.625 20.412 50.895 ;
     RECT  119.34 50.625 138.24 50.895 ;
     RECT  2.16 51.165 20.412 51.435 ;
     RECT  119.34 51.165 138.24 51.435 ;
     RECT  2.16 51.705 20.412 51.975 ;
     RECT  119.34 51.705 138.24 51.975 ;
     RECT  2.16 52.245 20.412 52.515 ;
     RECT  119.34 52.245 138.24 52.515 ;
     RECT  2.16 52.785 20.412 53.055 ;
     RECT  119.34 52.785 138.24 53.055 ;
     RECT  2.16 53.325 20.412 53.595 ;
     RECT  119.34 53.325 138.24 53.595 ;
     RECT  2.16 53.865 20.412 54.135 ;
     RECT  119.34 53.865 138.24 54.135 ;
     RECT  2.16 54.405 20.412 54.675 ;
     RECT  119.34 54.405 138.24 54.675 ;
     RECT  2.16 54.945 20.412 55.215 ;
     RECT  119.34 54.945 138.24 55.215 ;
     RECT  2.16 55.485 20.412 55.755 ;
     RECT  119.34 55.485 138.24 55.755 ;
     RECT  2.16 56.025 20.412 56.295 ;
     RECT  119.34 56.025 138.24 56.295 ;
     RECT  2.16 56.565 20.412 56.835 ;
     RECT  119.34 56.565 138.24 56.835 ;
     RECT  2.16 57.105 20.412 57.375 ;
     RECT  119.34 57.105 138.24 57.375 ;
     RECT  2.16 57.645 20.412 57.915 ;
     RECT  119.34 57.645 138.24 57.915 ;
     RECT  2.16 58.185 20.412 58.455 ;
     RECT  119.34 58.185 138.24 58.455 ;
     RECT  2.16 58.725 20.412 58.995 ;
     RECT  119.34 58.725 138.24 58.995 ;
     RECT  2.16 59.265 20.412 59.535 ;
     RECT  119.34 59.265 138.24 59.535 ;
     RECT  2.16 59.805 20.412 60.075 ;
     RECT  119.34 59.805 138.24 60.075 ;
     RECT  2.16 60.345 20.412 60.615 ;
     RECT  119.34 60.345 138.24 60.615 ;
     RECT  2.16 60.885 20.412 61.155 ;
     RECT  119.34 60.885 138.24 61.155 ;
     RECT  2.16 61.425 20.412 61.695 ;
     RECT  119.34 61.425 138.24 61.695 ;
     RECT  2.16 61.965 20.412 62.235 ;
     RECT  119.34 61.965 138.24 62.235 ;
     RECT  2.16 62.505 20.412 62.775 ;
     RECT  119.34 62.505 138.24 62.775 ;
     RECT  2.16 63.045 20.412 63.315 ;
     RECT  119.34 63.045 138.24 63.315 ;
     RECT  2.16 63.585 20.412 63.855 ;
     RECT  119.34 63.585 138.24 63.855 ;
     RECT  2.16 64.125 20.412 64.395 ;
     RECT  119.34 64.125 138.24 64.395 ;
     RECT  2.16 64.665 20.412 64.935 ;
     RECT  119.34 64.665 138.24 64.935 ;
     RECT  2.16 65.205 20.412 65.475 ;
     RECT  119.34 65.205 138.24 65.475 ;
     RECT  2.16 65.745 20.412 66.015 ;
     RECT  119.34 65.745 138.24 66.015 ;
     RECT  2.16 66.285 20.412 66.555 ;
     RECT  119.34 66.285 138.24 66.555 ;
     RECT  2.16 66.825 20.412 66.96 ;
     RECT  119.34 66.825 138.24 66.96 ;
     RECT  2.16 66.96 138.24 67.095 ;
     RECT  2.16 67.365 138.24 67.635 ;
     RECT  2.16 67.905 138.24 68.175 ;
     RECT  2.16 68.445 138.24 68.715 ;
     RECT  2.16 68.985 138.24 69.255 ;
     RECT  2.16 69.525 138.24 69.795 ;
     RECT  2.16 70.065 138.24 70.335 ;
     RECT  2.16 70.605 138.24 70.875 ;
     RECT  2.16 71.145 138.24 71.415 ;
     RECT  2.16 71.685 138.24 71.955 ;
     RECT  2.16 72.225 138.24 72.495 ;
     RECT  2.16 72.765 138.24 73.035 ;
     RECT  2.16 73.305 138.24 73.575 ;
     RECT  2.16 73.845 138.24 74.115 ;
     RECT  2.16 74.385 138.24 74.655 ;
     RECT  2.16 74.925 138.24 75.195 ;
     RECT  2.16 75.465 138.24 75.735 ;
     RECT  2.16 76.005 138.24 76.275 ;
     RECT  2.16 76.545 138.24 76.815 ;
     RECT  2.16 77.085 138.24 77.355 ;
     RECT  2.16 77.625 138.24 77.895 ;
     RECT  2.16 78.165 138.24 78.435 ;
     RECT  2.16 78.705 138.24 78.975 ;
     RECT  2.16 79.245 138.24 79.515 ;
     RECT  2.16 79.785 138.24 80.055 ;
     RECT  2.16 80.325 138.24 80.595 ;
     RECT  2.16 80.865 138.24 81.135 ;
     RECT  2.16 81.405 138.24 81.675 ;
     RECT  2.16 81.945 138.24 82.215 ;
     RECT  2.16 82.485 138.24 82.755 ;
     RECT  2.16 83.025 138.24 83.295 ;
     RECT  2.16 83.565 138.24 83.835 ;
     RECT  2.16 84.105 138.24 84.375 ;
     RECT  2.16 84.645 138.24 84.915 ;
     RECT  2.16 85.185 138.24 85.455 ;
     RECT  2.16 85.725 138.24 85.995 ;
     RECT  2.16 86.265 138.24 86.4 ;
    LAYER RVTP ;
     RECT  2.16 2.295 138.24 2.565 ;
     RECT  2.16 2.835 138.24 3.105 ;
     RECT  2.16 3.375 138.24 3.645 ;
     RECT  2.16 3.915 138.24 4.185 ;
     RECT  2.16 4.455 138.24 4.725 ;
     RECT  2.16 4.995 138.24 5.265 ;
     RECT  2.16 5.535 138.24 5.805 ;
     RECT  2.16 6.075 138.24 6.345 ;
     RECT  2.16 6.615 138.24 6.885 ;
     RECT  2.16 7.155 138.24 7.425 ;
     RECT  2.16 7.695 138.24 7.965 ;
     RECT  2.16 8.235 138.24 8.505 ;
     RECT  2.16 8.775 138.24 9.045 ;
     RECT  2.16 9.315 138.24 9.585 ;
     RECT  2.16 9.855 138.24 10.125 ;
     RECT  2.16 10.395 138.24 10.665 ;
     RECT  2.16 10.935 138.24 11.205 ;
     RECT  2.16 11.475 138.24 11.745 ;
     RECT  2.16 12.015 138.24 12.285 ;
     RECT  2.16 12.555 138.24 12.825 ;
     RECT  2.16 13.095 138.24 13.365 ;
     RECT  2.16 13.635 138.24 13.905 ;
     RECT  2.16 14.175 138.24 14.445 ;
     RECT  2.16 14.715 138.24 14.985 ;
     RECT  2.16 15.255 138.24 15.525 ;
     RECT  2.16 15.795 138.24 16.065 ;
     RECT  2.16 16.335 138.24 16.605 ;
     RECT  2.16 16.875 138.24 17.145 ;
     RECT  2.16 17.415 138.24 17.685 ;
     RECT  2.16 17.955 138.24 18.225 ;
     RECT  2.16 18.495 138.24 18.765 ;
     RECT  2.16 19.035 138.24 19.305 ;
     RECT  2.16 19.575 138.24 19.845 ;
     RECT  2.16 20.115 138.24 20.385 ;
     RECT  2.16 20.655 138.24 20.925 ;
     RECT  2.16 21.195 138.24 21.465 ;
     RECT  2.16 21.735 20.412 22.005 ;
     RECT  119.34 21.735 138.24 22.005 ;
     RECT  2.16 22.275 20.412 22.545 ;
     RECT  119.34 22.275 138.24 22.545 ;
     RECT  2.16 22.815 20.412 23.085 ;
     RECT  119.34 22.815 138.24 23.085 ;
     RECT  2.16 23.355 20.412 23.625 ;
     RECT  119.34 23.355 138.24 23.625 ;
     RECT  2.16 23.895 20.412 24.165 ;
     RECT  119.34 23.895 138.24 24.165 ;
     RECT  2.16 24.435 20.412 24.705 ;
     RECT  119.34 24.435 138.24 24.705 ;
     RECT  2.16 24.975 20.412 25.245 ;
     RECT  119.34 24.975 138.24 25.245 ;
     RECT  2.16 25.515 20.412 25.785 ;
     RECT  119.34 25.515 138.24 25.785 ;
     RECT  2.16 26.055 20.412 26.325 ;
     RECT  119.34 26.055 138.24 26.325 ;
     RECT  2.16 26.595 20.412 26.865 ;
     RECT  119.34 26.595 138.24 26.865 ;
     RECT  2.16 27.135 20.412 27.405 ;
     RECT  119.34 27.135 138.24 27.405 ;
     RECT  2.16 27.675 20.412 27.945 ;
     RECT  119.34 27.675 138.24 27.945 ;
     RECT  2.16 28.215 20.412 28.485 ;
     RECT  119.34 28.215 138.24 28.485 ;
     RECT  2.16 28.755 20.412 29.025 ;
     RECT  119.34 28.755 138.24 29.025 ;
     RECT  2.16 29.295 20.412 29.565 ;
     RECT  119.34 29.295 138.24 29.565 ;
     RECT  2.16 29.835 20.412 30.105 ;
     RECT  119.34 29.835 138.24 30.105 ;
     RECT  2.16 30.375 20.412 30.645 ;
     RECT  119.34 30.375 138.24 30.645 ;
     RECT  2.16 30.915 20.412 31.185 ;
     RECT  119.34 30.915 138.24 31.185 ;
     RECT  2.16 31.455 20.412 31.725 ;
     RECT  119.34 31.455 138.24 31.725 ;
     RECT  2.16 31.995 20.412 32.265 ;
     RECT  119.34 31.995 138.24 32.265 ;
     RECT  2.16 32.535 20.412 32.805 ;
     RECT  119.34 32.535 138.24 32.805 ;
     RECT  2.16 33.075 20.412 33.345 ;
     RECT  119.34 33.075 138.24 33.345 ;
     RECT  2.16 33.615 20.412 33.885 ;
     RECT  119.34 33.615 138.24 33.885 ;
     RECT  2.16 34.155 20.412 34.425 ;
     RECT  119.34 34.155 138.24 34.425 ;
     RECT  2.16 34.695 20.412 34.965 ;
     RECT  119.34 34.695 138.24 34.965 ;
     RECT  2.16 35.235 20.412 35.505 ;
     RECT  119.34 35.235 138.24 35.505 ;
     RECT  2.16 35.775 20.412 36.045 ;
     RECT  119.34 35.775 138.24 36.045 ;
     RECT  2.16 36.315 20.412 36.585 ;
     RECT  119.34 36.315 138.24 36.585 ;
     RECT  2.16 36.855 20.412 37.125 ;
     RECT  119.34 36.855 138.24 37.125 ;
     RECT  2.16 37.395 20.412 37.665 ;
     RECT  119.34 37.395 138.24 37.665 ;
     RECT  2.16 37.935 20.412 38.205 ;
     RECT  119.34 37.935 138.24 38.205 ;
     RECT  2.16 38.475 20.412 38.745 ;
     RECT  119.34 38.475 138.24 38.745 ;
     RECT  2.16 39.015 20.412 39.285 ;
     RECT  119.34 39.015 138.24 39.285 ;
     RECT  2.16 39.555 20.412 39.825 ;
     RECT  119.34 39.555 138.24 39.825 ;
     RECT  2.16 40.095 20.412 40.365 ;
     RECT  119.34 40.095 138.24 40.365 ;
     RECT  2.16 40.635 20.412 40.905 ;
     RECT  119.34 40.635 138.24 40.905 ;
     RECT  2.16 41.175 20.412 41.445 ;
     RECT  119.34 41.175 138.24 41.445 ;
     RECT  2.16 41.715 20.412 41.985 ;
     RECT  119.34 41.715 138.24 41.985 ;
     RECT  2.16 42.255 20.412 42.525 ;
     RECT  119.34 42.255 138.24 42.525 ;
     RECT  2.16 42.795 20.412 43.065 ;
     RECT  119.34 42.795 138.24 43.065 ;
     RECT  2.16 43.335 20.412 43.605 ;
     RECT  119.34 43.335 138.24 43.605 ;
     RECT  2.16 43.875 20.412 44.145 ;
     RECT  119.34 43.875 138.24 44.145 ;
     RECT  2.16 44.415 20.412 44.685 ;
     RECT  119.34 44.415 138.24 44.685 ;
     RECT  2.16 44.955 20.412 45.225 ;
     RECT  119.34 44.955 138.24 45.225 ;
     RECT  2.16 45.495 20.412 45.765 ;
     RECT  119.34 45.495 138.24 45.765 ;
     RECT  2.16 46.035 20.412 46.305 ;
     RECT  119.34 46.035 138.24 46.305 ;
     RECT  2.16 46.575 20.412 46.845 ;
     RECT  119.34 46.575 138.24 46.845 ;
     RECT  2.16 47.115 20.412 47.385 ;
     RECT  119.34 47.115 138.24 47.385 ;
     RECT  2.16 47.655 20.412 47.925 ;
     RECT  119.34 47.655 138.24 47.925 ;
     RECT  2.16 48.195 20.412 48.465 ;
     RECT  119.34 48.195 138.24 48.465 ;
     RECT  2.16 48.735 20.412 49.005 ;
     RECT  119.34 48.735 138.24 49.005 ;
     RECT  2.16 49.275 20.412 49.545 ;
     RECT  119.34 49.275 138.24 49.545 ;
     RECT  2.16 49.815 20.412 50.085 ;
     RECT  119.34 49.815 138.24 50.085 ;
     RECT  2.16 50.355 20.412 50.625 ;
     RECT  119.34 50.355 138.24 50.625 ;
     RECT  2.16 50.895 20.412 51.165 ;
     RECT  119.34 50.895 138.24 51.165 ;
     RECT  2.16 51.435 20.412 51.705 ;
     RECT  119.34 51.435 138.24 51.705 ;
     RECT  2.16 51.975 20.412 52.245 ;
     RECT  119.34 51.975 138.24 52.245 ;
     RECT  2.16 52.515 20.412 52.785 ;
     RECT  119.34 52.515 138.24 52.785 ;
     RECT  2.16 53.055 20.412 53.325 ;
     RECT  119.34 53.055 138.24 53.325 ;
     RECT  2.16 53.595 20.412 53.865 ;
     RECT  119.34 53.595 138.24 53.865 ;
     RECT  2.16 54.135 20.412 54.405 ;
     RECT  119.34 54.135 138.24 54.405 ;
     RECT  2.16 54.675 20.412 54.945 ;
     RECT  119.34 54.675 138.24 54.945 ;
     RECT  2.16 55.215 20.412 55.485 ;
     RECT  119.34 55.215 138.24 55.485 ;
     RECT  2.16 55.755 20.412 56.025 ;
     RECT  119.34 55.755 138.24 56.025 ;
     RECT  2.16 56.295 20.412 56.565 ;
     RECT  119.34 56.295 138.24 56.565 ;
     RECT  2.16 56.835 20.412 57.105 ;
     RECT  119.34 56.835 138.24 57.105 ;
     RECT  2.16 57.375 20.412 57.645 ;
     RECT  119.34 57.375 138.24 57.645 ;
     RECT  2.16 57.915 20.412 58.185 ;
     RECT  119.34 57.915 138.24 58.185 ;
     RECT  2.16 58.455 20.412 58.725 ;
     RECT  119.34 58.455 138.24 58.725 ;
     RECT  2.16 58.995 20.412 59.265 ;
     RECT  119.34 58.995 138.24 59.265 ;
     RECT  2.16 59.535 20.412 59.805 ;
     RECT  119.34 59.535 138.24 59.805 ;
     RECT  2.16 60.075 20.412 60.345 ;
     RECT  119.34 60.075 138.24 60.345 ;
     RECT  2.16 60.615 20.412 60.885 ;
     RECT  119.34 60.615 138.24 60.885 ;
     RECT  2.16 61.155 20.412 61.425 ;
     RECT  119.34 61.155 138.24 61.425 ;
     RECT  2.16 61.695 20.412 61.965 ;
     RECT  119.34 61.695 138.24 61.965 ;
     RECT  2.16 62.235 20.412 62.505 ;
     RECT  119.34 62.235 138.24 62.505 ;
     RECT  2.16 62.775 20.412 63.045 ;
     RECT  119.34 62.775 138.24 63.045 ;
     RECT  2.16 63.315 20.412 63.585 ;
     RECT  119.34 63.315 138.24 63.585 ;
     RECT  2.16 63.855 20.412 64.125 ;
     RECT  119.34 63.855 138.24 64.125 ;
     RECT  2.16 64.395 20.412 64.665 ;
     RECT  119.34 64.395 138.24 64.665 ;
     RECT  2.16 64.935 20.412 65.205 ;
     RECT  119.34 64.935 138.24 65.205 ;
     RECT  2.16 65.475 20.412 65.745 ;
     RECT  119.34 65.475 138.24 65.745 ;
     RECT  2.16 66.015 20.412 66.285 ;
     RECT  119.34 66.015 138.24 66.285 ;
     RECT  2.16 66.555 20.412 66.825 ;
     RECT  119.34 66.555 138.24 66.825 ;
     RECT  2.16 67.095 138.24 67.365 ;
     RECT  2.16 67.635 138.24 67.905 ;
     RECT  2.16 68.175 138.24 68.445 ;
     RECT  2.16 68.715 138.24 68.985 ;
     RECT  2.16 69.255 138.24 69.525 ;
     RECT  2.16 69.795 138.24 70.065 ;
     RECT  2.16 70.335 138.24 70.605 ;
     RECT  2.16 70.875 138.24 71.145 ;
     RECT  2.16 71.415 138.24 71.685 ;
     RECT  2.16 71.955 138.24 72.225 ;
     RECT  2.16 72.495 138.24 72.765 ;
     RECT  2.16 73.035 138.24 73.305 ;
     RECT  2.16 73.575 138.24 73.845 ;
     RECT  2.16 74.115 138.24 74.385 ;
     RECT  2.16 74.655 138.24 74.925 ;
     RECT  2.16 75.195 138.24 75.465 ;
     RECT  2.16 75.735 138.24 76.005 ;
     RECT  2.16 76.275 138.24 76.545 ;
     RECT  2.16 76.815 138.24 77.085 ;
     RECT  2.16 77.355 138.24 77.625 ;
     RECT  2.16 77.895 138.24 78.165 ;
     RECT  2.16 78.435 138.24 78.705 ;
     RECT  2.16 78.975 138.24 79.245 ;
     RECT  2.16 79.515 138.24 79.785 ;
     RECT  2.16 80.055 138.24 80.325 ;
     RECT  2.16 80.595 138.24 80.865 ;
     RECT  2.16 81.135 138.24 81.405 ;
     RECT  2.16 81.675 138.24 81.945 ;
     RECT  2.16 82.215 138.24 82.485 ;
     RECT  2.16 82.755 138.24 83.025 ;
     RECT  2.16 83.295 138.24 83.565 ;
     RECT  2.16 83.835 138.24 84.105 ;
     RECT  2.16 84.375 138.24 84.645 ;
     RECT  2.16 84.915 138.24 85.185 ;
     RECT  2.16 85.455 138.24 85.725 ;
     RECT  2.16 85.995 138.24 86.265 ;
    LAYER M1 ;
     RECT  2.16 2.151 138.24 21.609 ;
     RECT  22.464 23.76 117.288 64.824 ;
     RECT  2.16 21.609 20.412 66.951 ;
     RECT  119.34 21.609 138.24 66.951 ;
     RECT  2.16 66.951 138.24 86.409 ;
    LAYER M2 ;
     RECT  0.031 83.772 0.103 83.79 ;
     RECT  0.103 5.508 0.139 5.526 ;
     RECT  0.103 21.366 0.139 21.924 ;
     RECT  0.103 27.684 0.139 27.702 ;
     RECT  0.103 35.676 0.139 36.036 ;
     RECT  0.103 42.606 0.139 42.624 ;
     RECT  0.103 43.776 0.139 47.034 ;
     RECT  0.103 74.556 0.139 74.574 ;
     RECT  0.103 75.636 0.139 76.464 ;
     RECT  0.103 85.086 0.139 85.284 ;
     RECT  0.103 2.034 0.535 2.052 ;
     RECT  0.139 5.436 0.535 5.526 ;
     RECT  0.103 6.786 0.535 10.314 ;
     RECT  0.103 11.106 0.535 12.114 ;
     RECT  0.103 13.536 0.535 14.904 ;
     RECT  0.103 15.966 0.535 16.524 ;
     RECT  0.103 17.586 0.535 18.144 ;
     RECT  0.139 21.168 0.535 21.924 ;
     RECT  0.139 27.684 0.535 27.936 ;
     RECT  0.103 28.926 0.535 30.564 ;
     RECT  0.103 31.626 0.535 31.644 ;
     RECT  0.103 32.976 0.535 32.994 ;
     RECT  0.103 38.376 0.535 40.014 ;
     RECT  0.103 41.076 0.535 41.094 ;
     RECT  0.103 52.686 0.535 53.784 ;
     RECT  0.103 54.846 0.535 54.864 ;
     RECT  0.103 60.246 0.535 60.264 ;
     RECT  0.103 61.326 0.535 61.344 ;
     RECT  0.103 62.586 0.535 62.604 ;
     RECT  0.103 63.486 0.535 65.664 ;
     RECT  0.103 66.564 0.535 66.744 ;
     RECT  0.103 67.536 0.535 68.094 ;
     RECT  0.139 74.556 0.535 76.464 ;
     RECT  0.103 77.256 0.535 77.814 ;
     RECT  0.103 79.956 0.535 81.054 ;
     RECT  0.139 42.606 1.147 47.034 ;
     RECT  0.535 60.246 1.147 60.336 ;
     RECT  0.103 49.446 1.291 51.894 ;
     RECT  1.147 3.816 1.723 3.834 ;
     RECT  0.535 5.436 1.723 10.314 ;
     RECT  0.139 35.136 1.723 36.036 ;
     RECT  0.103 37.296 1.723 37.314 ;
     RECT  0.535 38.376 1.723 41.094 ;
     RECT  0.103 47.826 1.723 47.844 ;
     RECT  1.291 49.356 1.723 51.894 ;
     RECT  0.535 52.686 1.723 55.134 ;
     RECT  0.103 57.276 1.723 57.834 ;
     RECT  0.535 66.564 1.723 68.094 ;
     RECT  0.103 69.156 1.723 69.174 ;
     RECT  0.103 70.236 1.723 71.064 ;
     RECT  0.103 78.876 1.723 78.894 ;
     RECT  0.535 79.758 1.723 81.054 ;
     RECT  0.139 85.086 1.723 85.446 ;
     RECT  1.651 86.31 1.723 86.328 ;
     RECT  1.723 78.876 1.759 81.396 ;
     RECT  1.723 85.086 1.759 86.328 ;
     RECT  0.103 82.656 1.831 83.79 ;
     RECT  1.759 85.086 1.859 86.634 ;
     RECT  0.535 74.556 1.975 77.814 ;
     RECT  0.535 2.034 2.16 2.556 ;
     RECT  1.723 3.816 2.16 10.314 ;
     RECT  0.535 11.106 2.16 18.144 ;
     RECT  0.103 19.314 2.16 20.034 ;
     RECT  0.535 21.168 2.16 21.996 ;
     RECT  0.103 22.986 2.16 23.274 ;
     RECT  0.103 26.406 2.16 26.424 ;
     RECT  0.535 27.684 2.16 31.986 ;
     RECT  0.535 32.976 2.16 33.066 ;
     RECT  0.103 34.056 2.16 34.344 ;
     RECT  1.723 35.136 2.16 36.234 ;
     RECT  1.723 37.296 2.16 37.584 ;
     RECT  1.723 38.376 2.16 41.364 ;
     RECT  1.147 42.426 2.16 47.034 ;
     RECT  1.723 47.826 2.16 48.384 ;
     RECT  1.723 49.356 2.16 55.17 ;
     RECT  0.103 55.926 2.16 56.484 ;
     RECT  1.723 57.276 2.16 58.644 ;
     RECT  1.147 59.544 2.16 60.336 ;
     RECT  0.535 61.236 2.16 61.614 ;
     RECT  0.535 62.586 2.16 65.664 ;
     RECT  1.723 66.564 2.16 68.364 ;
     RECT  1.723 69.156 2.16 71.064 ;
     RECT  0.103 71.856 2.16 71.874 ;
     RECT  0.103 72.666 2.16 73.764 ;
     RECT  1.975 74.556 2.16 77.886 ;
     RECT  1.759 78.876 2.16 81.594 ;
     RECT  1.831 82.656 2.16 84.294 ;
     RECT  1.859 85.086 2.16 86.409 ;
     RECT  2.16 2.034 2.723 86.409 ;
     RECT  2.723 2.07 3.479 86.409 ;
     RECT  3.479 2.106 4.243 86.409 ;
     RECT  4.243 2.106 4.307 86.679 ;
     RECT  4.307 2.106 5.971 86.409 ;
     RECT  5.971 2.034 7.979 86.409 ;
     RECT  7.979 2.106 9.383 86.409 ;
     RECT  9.383 2.151 12.091 86.409 ;
     RECT  12.091 2.151 12.371 86.679 ;
     RECT  12.371 2.151 17.311 86.409 ;
     RECT  17.311 2.151 17.483 86.679 ;
     RECT  17.483 2.151 20.412 86.409 ;
     RECT  20.412 33.696 20.435 37.494 ;
     RECT  20.412 43.236 20.435 45.756 ;
     RECT  20.412 46.818 20.471 47.754 ;
     RECT  20.412 24.786 20.543 25.344 ;
     RECT  20.412 56.376 20.543 56.484 ;
     RECT  20.412 57.348 20.543 62.604 ;
     RECT  20.412 52.452 20.579 55.17 ;
     RECT  20.543 25.056 20.615 25.344 ;
     RECT  20.412 27.216 20.615 27.774 ;
     RECT  20.615 25.326 20.651 25.344 ;
     RECT  20.412 49.518 20.651 50.814 ;
     RECT  20.412 51.606 20.687 51.624 ;
     RECT  20.543 57.348 20.687 61.614 ;
     RECT  20.435 43.236 20.723 45.684 ;
     RECT  20.651 50.796 20.723 50.814 ;
     RECT  20.435 33.696 20.759 36.684 ;
     RECT  20.687 58.428 20.759 61.614 ;
     RECT  20.412 2.151 20.795 23.922 ;
     RECT  20.579 52.452 21.011 54.234 ;
     RECT  20.759 33.696 21.083 36.612 ;
     RECT  21.011 52.452 21.083 54.162 ;
     RECT  20.412 31.5 21.119 31.644 ;
     RECT  21.083 52.452 21.119 53.316 ;
     RECT  20.543 56.466 21.119 56.484 ;
     RECT  20.687 57.348 21.119 57.474 ;
     RECT  20.759 58.626 21.119 61.614 ;
     RECT  20.579 55.152 21.155 55.17 ;
     RECT  21.119 60.696 21.155 61.614 ;
     RECT  21.119 58.626 21.191 59.364 ;
     RECT  21.155 60.696 21.191 60.714 ;
     RECT  21.119 53.226 21.227 53.316 ;
     RECT  21.119 52.452 21.263 52.47 ;
     RECT  21.227 53.226 21.335 53.244 ;
     RECT  21.191 58.626 21.371 58.644 ;
     RECT  21.083 54.144 21.407 54.162 ;
     RECT  20.412 63.756 21.623 64.224 ;
     RECT  21.119 57.456 21.695 57.474 ;
     RECT  20.412 65.214 21.883 86.409 ;
     RECT  21.883 65.178 21.991 86.409 ;
     RECT  20.723 43.236 22.063 45.414 ;
     RECT  20.471 47.196 22.207 47.754 ;
     RECT  20.412 38.484 22.279 39.744 ;
     RECT  20.412 40.716 22.279 41.202 ;
     RECT  21.991 64.98 22.315 86.409 ;
     RECT  20.795 2.151 22.464 23.886 ;
     RECT  20.412 26.136 22.464 26.154 ;
     RECT  20.615 27.486 22.464 27.774 ;
     RECT  20.412 28.836 22.464 30.474 ;
     RECT  21.119 31.5 22.464 31.554 ;
     RECT  22.279 32.778 22.464 32.796 ;
     RECT  21.083 33.696 22.464 36 ;
     RECT  20.435 37.476 22.464 37.494 ;
     RECT  22.279 38.484 22.464 41.202 ;
     RECT  20.412 42.066 22.464 42.084 ;
     RECT  22.063 43.236 22.464 46.062 ;
     RECT  22.207 47.016 22.464 47.754 ;
     RECT  20.651 49.518 22.464 49.536 ;
     RECT  21.155 61.596 22.464 61.614 ;
     RECT  20.543 62.586 22.464 62.604 ;
     RECT  21.623 63.756 22.464 63.774 ;
     RECT  22.315 64.98 22.464 86.679 ;
     RECT  22.464 2.151 22.559 86.679 ;
     RECT  22.559 2.151 30.379 86.409 ;
     RECT  30.379 2.151 30.659 86.679 ;
     RECT  30.659 2.151 32.755 86.409 ;
     RECT  32.755 2.151 32.999 86.679 ;
     RECT  32.999 2.151 40.819 86.409 ;
     RECT  40.819 2.151 40.883 86.679 ;
     RECT  40.883 2.151 43.411 86.409 ;
     RECT  43.411 2.151 43.583 86.679 ;
     RECT  43.583 2.151 45.823 86.526 ;
     RECT  45.823 2.151 46.067 86.679 ;
     RECT  46.067 2.151 48.631 86.526 ;
     RECT  48.631 2.151 48.875 86.679 ;
     RECT  48.875 2.151 50.971 86.526 ;
     RECT  50.971 2.151 51.287 86.679 ;
     RECT  51.287 2.151 53.635 86.526 ;
     RECT  53.635 2.151 53.879 86.679 ;
     RECT  53.879 2.151 55.147 86.526 ;
     RECT  55.147 2.151 82.363 86.76 ;
     RECT  82.363 2.151 82.399 86.796 ;
     RECT  82.399 2.151 88.915 86.832 ;
     RECT  88.915 2.151 93.371 86.868 ;
     RECT  106.087 88.506 106.223 88.524 ;
     RECT  93.371 2.151 107.231 86.832 ;
     RECT  107.231 2.151 108.887 86.76 ;
     RECT  108.887 2.151 110.587 86.724 ;
     RECT  110.587 2.151 111.479 86.76 ;
     RECT  111.479 2.151 114.583 86.724 ;
     RECT  114.583 2.151 116.843 86.76 ;
     RECT  116.843 2.151 117.288 86.724 ;
     RECT  117.288 30.546 118.291 31.014 ;
     RECT  118.291 30.276 118.327 31.014 ;
     RECT  117.288 49.896 118.471 49.914 ;
     RECT  117.288 50.751 118.471 51.804 ;
     RECT  117.288 53.226 118.471 57.474 ;
     RECT  117.288 58.392 118.471 63.774 ;
     RECT  117.288 27.684 118.579 29.124 ;
     RECT  117.288 64.98 118.579 86.724 ;
     RECT  117.288 35.406 118.795 48.834 ;
     RECT  118.471 49.896 118.795 51.804 ;
     RECT  118.795 35.406 118.903 51.804 ;
     RECT  118.903 35.406 119.119 52.002 ;
     RECT  118.471 53.226 119.119 63.774 ;
     RECT  117.288 2.151 119.34 23.958 ;
     RECT  117.288 25.326 119.34 25.344 ;
     RECT  117.288 26.136 119.34 26.154 ;
     RECT  118.579 27.072 119.34 29.124 ;
     RECT  118.327 29.916 119.34 31.014 ;
     RECT  117.288 33.624 119.34 33.714 ;
     RECT  119.119 35.406 119.34 64.08 ;
     RECT  118.579 64.98 119.34 86.796 ;
     RECT  119.34 2.151 121.847 86.796 ;
     RECT  121.847 2.151 124.267 86.679 ;
     RECT  124.267 2.151 124.367 86.724 ;
     RECT  124.367 2.151 124.799 86.679 ;
     RECT  124.799 2.151 132.367 86.409 ;
     RECT  132.367 2.106 134.815 86.409 ;
     RECT  134.815 2.106 134.915 86.679 ;
     RECT  134.915 2.106 136.535 86.409 ;
     RECT  136.535 2.151 137.443 86.409 ;
     RECT  137.443 2.151 137.623 86.679 ;
     RECT  137.623 1.998 137.795 86.679 ;
     RECT  137.795 1.998 138.24 86.409 ;
     RECT  138.24 25.56 138.371 44.442 ;
     RECT  138.24 58.5 138.371 77.418 ;
     RECT  138.24 6.354 138.479 24.66 ;
     RECT  138.371 30.618 138.479 44.442 ;
     RECT  138.371 58.5 138.479 58.986 ;
     RECT  138.371 59.778 138.479 77.418 ;
     RECT  138.479 33.588 138.515 44.442 ;
     RECT  138.24 45.27 138.515 50.418 ;
     RECT  138.24 51.21 138.515 57.708 ;
     RECT  138.479 59.778 138.515 68.4 ;
     RECT  138.479 9.36 138.551 24.66 ;
     RECT  138.515 48.708 138.551 50.148 ;
     RECT  138.515 55.458 138.551 57.708 ;
     RECT  138.479 58.5 138.551 58.518 ;
     RECT  138.515 59.778 138.551 65.502 ;
     RECT  138.479 69.498 138.551 77.418 ;
     RECT  138.515 35.748 139.055 44.442 ;
     RECT  138.24 1.998 139.091 3.708 ;
     RECT  138.24 4.77 139.091 5.328 ;
     RECT  138.479 6.354 139.091 8.568 ;
     RECT  138.551 9.36 139.091 22.806 ;
     RECT  138.551 23.67 139.091 24.66 ;
     RECT  138.371 25.56 139.091 29.826 ;
     RECT  138.479 30.618 139.091 32.796 ;
     RECT  138.515 33.588 139.091 34.758 ;
     RECT  139.055 35.748 139.091 44.406 ;
     RECT  138.515 45.27 139.091 47.646 ;
     RECT  138.515 51.21 139.091 51.498 ;
     RECT  138.515 52.29 139.091 52.542 ;
     RECT  138.515 53.298 139.091 54.666 ;
     RECT  138.551 55.458 139.091 56.628 ;
     RECT  138.551 59.778 139.091 60.408 ;
     RECT  138.551 61.164 139.091 62.802 ;
     RECT  138.551 63.63 139.091 65.502 ;
     RECT  138.515 66.294 139.091 68.4 ;
     RECT  138.551 69.498 139.091 69.822 ;
     RECT  138.551 70.578 139.091 73.368 ;
     RECT  138.551 74.628 139.091 77.418 ;
     RECT  138.24 78.48 139.091 80.856 ;
     RECT  138.24 81.756 139.091 86.292 ;
     RECT  139.091 45.27 139.127 47.376 ;
     RECT  138.551 49.554 139.127 50.148 ;
     RECT  139.091 53.406 139.127 53.424 ;
     RECT  139.091 63.828 139.127 64.224 ;
     RECT  139.091 70.92 139.127 71.478 ;
     RECT  139.091 6.39 139.631 6.714 ;
     RECT  139.091 15.462 139.631 16.668 ;
     RECT  139.091 36.63 139.631 37.188 ;
     RECT  139.091 41.688 139.631 42.21 ;
     RECT  139.127 45.27 139.631 46.26 ;
     RECT  139.127 47.358 139.631 47.376 ;
     RECT  138.551 48.708 139.631 48.726 ;
     RECT  139.091 61.632 139.631 62.802 ;
     RECT  139.091 66.294 139.631 67.896 ;
     RECT  139.127 71.46 139.631 71.478 ;
     RECT  139.091 84.618 139.667 84.636 ;
     RECT  139.091 85.77 139.703 85.788 ;
     RECT  139.091 2.07 140.279 2.664 ;
     RECT  140.279 2.07 140.315 2.088 ;
     RECT  139.631 6.39 140.315 6.408 ;
     RECT  139.091 8.55 140.315 8.568 ;
     RECT  139.091 10.44 140.315 10.458 ;
     RECT  139.631 15.462 140.315 15.48 ;
     RECT  139.631 16.65 140.315 16.668 ;
     RECT  139.091 18.846 140.315 18.864 ;
     RECT  139.091 20.052 140.315 21.762 ;
     RECT  139.091 23.904 140.315 24.66 ;
     RECT  139.091 31.428 140.315 31.95 ;
     RECT  139.631 37.17 140.315 37.188 ;
     RECT  139.091 39.906 140.315 39.924 ;
     RECT  139.091 40.68 140.315 40.698 ;
     RECT  139.631 42.192 140.315 42.21 ;
     RECT  139.631 45.27 140.315 45.288 ;
     RECT  139.631 46.242 140.315 46.26 ;
     RECT  139.091 56.61 140.315 56.628 ;
     RECT  139.631 61.632 140.315 61.65 ;
     RECT  139.631 62.784 140.315 62.802 ;
     RECT  139.091 65.016 140.315 65.034 ;
     RECT  139.631 66.294 140.315 66.312 ;
     RECT  139.631 67.374 140.315 67.896 ;
     RECT  139.091 69.606 140.315 69.624 ;
     RECT  139.091 81.756 140.315 83.358 ;
    LAYER M3 ;
     RECT  2.376 1.147 2.394 1.483 ;
     RECT  138.024 1.435 138.042 1.993 ;
     RECT  140.292 1.147 140.31 2.011 ;
     RECT  139.068 1.723 139.086 2.021 ;
     RECT  0.108 1.819 0.126 2.056 ;
     RECT  0.108 2.056 0.162 2.057 ;
     RECT  2.376 1.483 2.97 2.065 ;
     RECT  140.256 2.011 140.31 2.093 ;
     RECT  2.376 2.065 3.474 2.101 ;
     RECT  5.976 2.029 5.994 2.101 ;
     RECT  7.956 2.029 7.974 2.143 ;
     RECT  132.372 2.101 132.39 2.143 ;
     RECT  137.628 1.993 138.042 2.143 ;
     RECT  0.144 2.057 0.162 2.189 ;
     RECT  2.304 2.101 3.87 2.191 ;
     RECT  5.976 2.101 6.786 2.191 ;
     RECT  7.815 2.143 7.974 2.191 ;
     RECT  132.015 2.143 132.39 2.191 ;
     RECT  136.512 2.101 136.53 2.191 ;
     RECT  136.44 2.191 136.53 2.203 ;
     RECT  5.976 2.191 7.974 2.219 ;
     RECT  9.36 2.101 9.378 2.219 ;
     RECT  134.352 2.101 134.838 2.219 ;
     RECT  135.72 2.203 136.53 2.227 ;
     RECT  137.415 2.143 138.042 2.227 ;
     RECT  6.984 2.219 7.974 2.251 ;
     RECT  6.984 2.251 8.406 2.371 ;
     RECT  134.352 2.219 134.694 2.371 ;
     RECT  135.684 2.227 138.042 2.371 ;
     RECT  13.215 2.143 13.305 2.413 ;
     RECT  18.615 2.143 18.705 2.413 ;
     RECT  24.015 2.143 24.105 2.413 ;
     RECT  29.415 2.143 29.505 2.413 ;
     RECT  34.815 2.143 34.905 2.413 ;
     RECT  40.215 2.143 40.305 2.413 ;
     RECT  45.615 2.143 45.705 2.413 ;
     RECT  51.015 2.143 51.105 2.413 ;
     RECT  56.415 2.143 56.505 2.413 ;
     RECT  61.815 2.143 61.905 2.413 ;
     RECT  67.215 2.143 67.305 2.413 ;
     RECT  72.615 2.143 72.705 2.413 ;
     RECT  78.015 2.143 78.105 2.413 ;
     RECT  83.415 2.143 83.505 2.413 ;
     RECT  88.815 2.143 88.905 2.413 ;
     RECT  94.215 2.143 94.305 2.413 ;
     RECT  99.615 2.143 99.705 2.413 ;
     RECT  105.015 2.143 105.105 2.413 ;
     RECT  110.415 2.143 110.505 2.413 ;
     RECT  115.815 2.143 115.905 2.413 ;
     RECT  121.215 2.143 121.305 2.413 ;
     RECT  126.615 2.143 126.705 2.413 ;
     RECT  2.304 2.191 4.05 2.461 ;
     RECT  0.54 2.491 0.558 2.561 ;
     RECT  5.976 2.219 6.03 2.569 ;
     RECT  135.468 2.371 138.042 2.569 ;
     RECT  2.304 2.461 4.662 2.605 ;
     RECT  5.58 2.569 6.03 2.605 ;
     RECT  132.015 2.191 132.786 2.605 ;
     RECT  133.992 2.371 134.694 2.605 ;
     RECT  140.256 2.093 140.274 2.669 ;
     RECT  24.015 2.413 24.297 2.803 ;
     RECT  135.468 2.569 138.546 2.875 ;
     RECT  2.304 2.605 6.03 2.971 ;
     RECT  6.984 2.371 8.586 2.971 ;
     RECT  2.304 2.971 8.586 3.137 ;
     RECT  23.508 2.803 24.297 3.173 ;
     RECT  2.304 3.137 4.194 3.299 ;
     RECT  135.468 2.875 139.086 3.299 ;
     RECT  132.015 2.605 134.694 3.335 ;
     RECT  0.108 3.163 0.126 3.341 ;
     RECT  138.492 3.299 139.086 3.371 ;
     RECT  134.64 3.335 134.694 3.403 ;
     RECT  135.468 3.299 137.697 3.403 ;
     RECT  2.304 3.299 3.798 3.407 ;
     RECT  132.015 3.335 133.47 3.437 ;
     RECT  29.415 2.413 29.697 3.541 ;
     RECT  139.068 3.371 139.086 3.713 ;
     RECT  1.152 2.827 1.17 3.839 ;
     RECT  28.44 2.731 28.458 3.839 ;
     RECT  26.1 3.721 26.118 3.847 ;
     RECT  4.968 3.137 8.586 3.883 ;
     RECT  26.1 3.847 26.802 3.947 ;
     RECT  4.932 3.883 8.586 3.955 ;
     RECT  130.536 2.911 130.554 3.991 ;
     RECT  134.64 3.403 137.697 4.027 ;
     RECT  29.196 3.541 29.697 4.109 ;
     RECT  130.536 3.991 130.626 4.153 ;
     RECT  26.1 3.947 26.226 4.189 ;
     RECT  132.015 3.437 133.038 4.225 ;
     RECT  130.536 4.153 130.698 4.253 ;
     RECT  2.304 3.407 3.654 4.261 ;
     RECT  4.752 3.955 8.586 4.261 ;
     RECT  22.824 3.847 22.842 4.261 ;
     RECT  132.015 4.225 133.326 4.261 ;
     RECT  134.64 4.027 137.97 4.261 ;
     RECT  31.716 3.343 31.734 4.379 ;
     RECT  132.015 4.261 137.97 4.379 ;
     RECT  130.536 4.253 130.554 4.415 ;
     RECT  10.044 4.261 10.062 4.423 ;
     RECT  118.584 4.351 118.602 4.451 ;
     RECT  2.304 4.261 8.586 4.495 ;
     RECT  133.308 4.379 137.97 4.523 ;
     RECT  2.304 4.495 9.09 4.531 ;
     RECT  133.308 4.523 137.697 4.541 ;
     RECT  114.588 4.387 114.606 4.559 ;
     RECT  22.5 4.261 22.842 4.621 ;
     RECT  23.58 3.173 24.297 4.621 ;
     RECT  1.728 4.531 9.09 4.649 ;
     RECT  22.5 4.621 24.297 4.649 ;
     RECT  133.992 4.541 137.697 4.793 ;
     RECT  13.215 2.413 13.497 4.801 ;
     RECT  33.948 4.387 33.966 4.919 ;
     RECT  10.044 4.423 10.134 5.071 ;
     RECT  27.504 4.225 27.522 5.161 ;
     RECT  13.104 4.801 13.497 5.189 ;
     RECT  25.776 4.189 26.226 5.189 ;
     RECT  10.044 5.071 10.17 5.197 ;
     RECT  16.56 5.197 16.578 5.261 ;
     RECT  139.068 4.603 139.086 5.333 ;
     RECT  13.215 5.189 13.497 5.341 ;
     RECT  27.468 5.161 27.522 5.341 ;
     RECT  130.536 5.233 130.554 5.341 ;
     RECT  10.044 5.197 10.854 5.369 ;
     RECT  130.536 5.341 130.626 5.369 ;
     RECT  0.108 5.227 0.126 5.431 ;
     RECT  27.468 5.341 27.594 5.459 ;
     RECT  133.524 5.341 133.542 5.459 ;
     RECT  134.316 4.793 137.697 5.467 ;
     RECT  21.744 3.847 21.762 5.503 ;
     RECT  22.572 4.649 24.297 5.503 ;
     RECT  0.108 5.431 0.162 5.531 ;
     RECT  0.144 5.531 0.162 5.597 ;
     RECT  1.728 4.649 9.054 5.603 ;
     RECT  134.316 5.467 137.97 5.603 ;
     RECT  21.744 5.503 24.297 5.611 ;
     RECT  134.316 5.603 137.934 5.611 ;
     RECT  130.608 5.369 130.626 5.639 ;
     RECT  133.308 5.575 133.326 5.645 ;
     RECT  18.615 2.413 18.897 5.707 ;
     RECT  1.728 5.603 8.874 5.729 ;
     RECT  13.215 5.341 14.094 5.729 ;
     RECT  134.244 5.611 137.934 5.729 ;
     RECT  18 5.707 18.897 5.845 ;
     RECT  14.832 5.269 14.85 5.909 ;
     RECT  1.728 5.729 3.258 5.933 ;
     RECT  21.744 5.611 24.57 5.971 ;
     RECT  2.415 5.933 3.258 5.999 ;
     RECT  4.14 5.729 8.874 5.999 ;
     RECT  140.292 5.755 140.31 6.043 ;
     RECT  4.14 5.999 8.097 6.071 ;
     RECT  134.244 5.729 134.586 6.179 ;
     RECT  0.54 6.043 0.558 6.269 ;
     RECT  27.468 5.459 27.522 6.269 ;
     RECT  139.608 6.043 140.31 6.331 ;
     RECT  134.244 6.179 134.55 6.385 ;
     RECT  139.068 6.331 140.31 6.413 ;
     RECT  27.504 6.269 27.522 6.421 ;
     RECT  13.215 5.729 13.497 6.511 ;
     RECT  25.884 5.189 26.226 6.575 ;
     RECT  8.856 5.999 8.874 6.583 ;
     RECT  26.208 6.575 26.226 6.583 ;
     RECT  135.324 5.729 137.934 6.619 ;
     RECT  139.068 6.413 139.626 6.619 ;
     RECT  133.632 6.385 134.55 6.655 ;
     RECT  133.452 6.655 134.55 6.667 ;
     RECT  10.044 5.369 10.134 6.691 ;
     RECT  135.324 6.619 139.626 6.719 ;
     RECT  8.856 6.583 9.162 6.781 ;
     RECT  133.164 6.667 134.55 6.845 ;
     RECT  10.008 6.691 10.134 6.853 ;
     RECT  2.415 5.999 3.186 6.907 ;
     RECT  4.248 6.071 8.097 6.907 ;
     RECT  8.856 6.781 9.234 6.961 ;
     RECT  10.008 6.853 10.206 6.961 ;
     RECT  16.704 5.305 16.722 6.961 ;
     RECT  17.928 5.845 18.897 6.961 ;
     RECT  130.536 6.421 130.554 6.961 ;
     RECT  110.415 2.413 110.697 7.045 ;
     RECT  56.415 2.413 56.697 7.051 ;
     RECT  67.215 2.413 67.497 7.051 ;
     RECT  78.015 2.413 78.297 7.051 ;
     RECT  88.815 2.413 89.097 7.051 ;
     RECT  99.615 2.413 99.897 7.051 ;
     RECT  17.928 6.961 18.918 7.079 ;
     RECT  28.332 6.961 28.35 7.079 ;
     RECT  118.98 6.667 118.998 7.079 ;
     RECT  130.536 6.961 130.626 7.079 ;
     RECT  110.304 7.045 110.697 7.085 ;
     RECT  56.304 7.051 56.697 7.088 ;
     RECT  67.104 7.051 67.497 7.088 ;
     RECT  77.904 7.051 78.297 7.088 ;
     RECT  88.704 7.051 89.097 7.088 ;
     RECT  99.504 7.051 99.897 7.088 ;
     RECT  16.164 6.961 16.722 7.115 ;
     RECT  31.824 4.531 31.842 7.123 ;
     RECT  31.14 7.123 31.842 7.133 ;
     RECT  130.608 7.079 130.626 7.151 ;
     RECT  114.588 7.051 114.606 7.181 ;
     RECT  14.832 7.087 14.85 7.187 ;
     RECT  133.884 6.845 134.55 7.187 ;
     RECT  8.856 6.961 10.206 7.231 ;
     RECT  12.744 6.511 13.497 7.259 ;
     RECT  119.16 7.147 119.178 7.259 ;
     RECT  26.208 6.583 26.55 7.339 ;
     RECT  26.208 7.339 26.658 7.385 ;
     RECT  2.415 6.907 8.097 7.421 ;
     RECT  135.324 6.719 139.086 7.421 ;
     RECT  4.32 7.421 8.097 7.465 ;
     RECT  8.856 7.231 10.458 7.465 ;
     RECT  4.32 7.465 10.458 7.501 ;
     RECT  11.484 6.043 11.502 7.501 ;
     RECT  2.415 7.421 3.474 7.619 ;
     RECT  21.744 5.971 24.714 7.663 ;
     RECT  134.46 7.187 134.55 7.663 ;
     RECT  135.324 7.421 137.934 7.663 ;
     RECT  132.015 4.379 132.297 7.771 ;
     RECT  4.32 7.501 11.502 7.889 ;
     RECT  134.46 7.663 137.934 7.889 ;
     RECT  134.46 7.889 137.754 7.925 ;
     RECT  134.532 7.925 137.754 7.961 ;
     RECT  139.032 7.421 139.086 7.961 ;
     RECT  132.015 7.771 132.858 8.039 ;
     RECT  4.32 7.889 10.206 8.159 ;
     RECT  132.015 8.039 133.542 8.195 ;
     RECT  2.415 7.619 3.186 8.275 ;
     RECT  139.068 7.961 139.086 8.303 ;
     RECT  132.015 8.195 132.93 8.339 ;
     RECT  140.292 8.347 140.31 8.573 ;
     RECT  135.036 7.961 137.754 8.635 ;
     RECT  2.304 8.275 3.186 8.671 ;
     RECT  135.036 8.635 137.97 8.807 ;
     RECT  2.304 8.671 3.258 8.815 ;
     RECT  14.652 7.897 14.67 8.815 ;
     RECT  130.536 8.203 130.554 8.851 ;
     RECT  2.304 8.815 3.438 8.879 ;
     RECT  130.536 8.851 130.626 8.879 ;
     RECT  14.652 8.815 15.066 8.941 ;
     RECT  135.036 8.807 137.697 8.941 ;
     RECT  14.472 8.941 15.642 9.005 ;
     RECT  138.456 8.923 138.474 9.041 ;
     RECT  4.644 8.159 10.206 9.049 ;
     RECT  29.415 4.109 29.697 9.049 ;
     RECT  130.608 8.879 130.626 9.077 ;
     RECT  134.532 8.941 137.697 9.085 ;
     RECT  4.644 9.049 10.242 9.121 ;
     RECT  11.484 7.889 11.502 9.121 ;
     RECT  13.215 7.259 13.497 9.121 ;
     RECT  28.404 7.231 28.422 9.389 ;
     RECT  2.34 8.879 3.438 9.419 ;
     RECT  133.272 9.391 133.362 9.437 ;
     RECT  26.208 7.385 26.226 9.481 ;
     RECT  3.42 9.419 3.438 9.499 ;
     RECT  4.644 9.121 11.502 9.499 ;
     RECT  12.744 9.121 13.497 9.509 ;
     RECT  2.34 9.419 2.697 9.625 ;
     RECT  134.46 9.085 137.697 9.661 ;
     RECT  27.504 6.421 27.558 9.751 ;
     RECT  3.42 9.499 11.502 9.779 ;
     RECT  14.904 9.005 15.642 9.779 ;
     RECT  139.068 9.211 139.086 9.851 ;
     RECT  134.46 9.661 137.934 9.923 ;
     RECT  134.46 9.923 134.622 9.925 ;
     RECT  133.344 9.437 133.362 9.931 ;
     RECT  134.28 9.925 134.622 9.931 ;
     RECT  14.76 9.895 14.778 10.049 ;
     RECT  26.208 9.481 26.766 10.129 ;
     RECT  27.504 9.751 28.17 10.129 ;
     RECT  130.536 9.823 130.554 10.157 ;
     RECT  13.215 9.509 13.497 10.165 ;
     RECT  13.215 10.165 14.022 10.201 ;
     RECT  21.744 7.663 25.038 10.201 ;
     RECT  132.015 8.339 132.297 10.201 ;
     RECT  133.344 9.931 134.622 10.201 ;
     RECT  13.215 10.201 14.67 10.205 ;
     RECT  2.304 9.625 2.697 10.291 ;
     RECT  17.928 7.079 18.897 10.315 ;
     RECT  17.532 10.315 18.897 10.355 ;
     RECT  135.432 9.923 137.934 10.357 ;
     RECT  2.304 10.291 3.294 10.391 ;
     RECT  26.208 10.129 28.17 10.391 ;
     RECT  135.432 10.357 138.546 10.391 ;
     RECT  140.292 10.075 140.31 10.463 ;
     RECT  4.068 9.779 11.502 10.555 ;
     RECT  21.636 10.201 25.038 10.597 ;
     RECT  132.015 10.201 134.622 10.625 ;
     RECT  138.492 10.391 138.546 10.651 ;
     RECT  3.6 10.555 11.502 10.697 ;
     RECT  13.215 10.205 13.497 10.795 ;
     RECT  27.36 10.391 28.17 10.859 ;
     RECT  133.344 10.625 134.622 10.895 ;
     RECT  133.956 10.895 134.622 10.903 ;
     RECT  135.432 10.391 137.697 10.903 ;
     RECT  21.6 10.597 25.038 10.939 ;
     RECT  14.508 10.205 14.67 11.101 ;
     RECT  2.304 10.391 2.862 11.245 ;
     RECT  3.6 10.697 10.134 11.245 ;
     RECT  138.492 10.651 139.086 11.261 ;
     RECT  14.508 11.101 14.778 11.281 ;
     RECT  133.956 10.903 137.697 11.309 ;
     RECT  2.304 11.245 10.134 11.399 ;
     RECT  31.14 7.133 31.158 11.399 ;
     RECT  132.015 10.625 132.354 11.399 ;
     RECT  133.956 11.309 134.802 11.399 ;
     RECT  14.4 11.281 14.778 11.435 ;
     RECT  11.484 10.697 11.502 11.515 ;
     RECT  12.564 10.795 13.497 11.515 ;
     RECT  14.652 11.435 14.778 11.551 ;
     RECT  135.648 11.309 137.697 11.579 ;
     RECT  15.624 9.779 15.642 11.641 ;
     RECT  16.704 7.115 16.722 11.641 ;
     RECT  34.02 5.071 34.038 11.693 ;
     RECT  2.415 11.399 10.134 11.821 ;
     RECT  11.484 11.515 13.497 11.821 ;
     RECT  14.652 11.551 14.814 11.849 ;
     RECT  2.415 11.821 13.497 11.939 ;
     RECT  20.556 4.153 20.574 11.947 ;
     RECT  21.564 10.939 25.038 11.947 ;
     RECT  11.484 11.939 11.754 11.975 ;
     RECT  12.564 11.939 13.497 12.047 ;
     RECT  139.068 11.261 139.086 12.091 ;
     RECT  0.108 6.571 0.126 12.119 ;
     RECT  20.556 11.947 25.038 12.181 ;
     RECT  138.456 12.091 139.086 12.281 ;
     RECT  133.956 11.399 134.55 12.325 ;
     RECT  135.792 11.579 137.697 12.361 ;
     RECT  133.956 12.325 134.838 12.365 ;
     RECT  130.536 12.289 130.554 12.389 ;
     RECT  2.415 11.939 10.134 12.451 ;
     RECT  133.956 12.365 134.622 12.479 ;
     RECT  133.128 11.371 133.146 12.503 ;
     RECT  133.956 12.479 134.55 12.503 ;
     RECT  1.728 12.451 10.134 12.701 ;
     RECT  2.304 12.701 10.134 12.793 ;
     RECT  11.484 11.975 11.502 12.793 ;
     RECT  2.304 12.793 11.502 12.829 ;
     RECT  12.924 12.047 13.497 12.829 ;
     RECT  132.015 11.399 132.297 12.901 ;
     RECT  133.128 12.503 134.55 12.901 ;
     RECT  2.304 12.829 13.497 13.019 ;
     RECT  132.015 12.901 134.55 13.019 ;
     RECT  0.54 12.793 0.558 13.037 ;
     RECT  2.304 13.019 9.99 13.055 ;
     RECT  135.684 12.361 137.697 13.243 ;
     RECT  135.684 13.243 137.97 13.261 ;
     RECT  17.676 10.355 18.897 13.333 ;
     RECT  10.764 13.019 13.497 13.369 ;
     RECT  51.015 2.413 51.297 13.405 ;
     RECT  130.536 13.333 130.554 13.433 ;
     RECT  135.18 13.261 137.97 13.433 ;
     RECT  20.556 12.181 25.254 13.441 ;
     RECT  132.015 13.019 134.442 13.441 ;
     RECT  34.815 2.413 35.097 13.525 ;
     RECT  45.615 2.413 45.897 13.531 ;
     RECT  50.292 13.405 51.297 13.559 ;
     RECT  34.704 13.525 35.097 13.565 ;
     RECT  15.624 11.641 16.722 13.567 ;
     RECT  17.64 13.333 18.897 13.567 ;
     RECT  45.504 13.531 45.897 13.568 ;
     RECT  50.4 13.559 51.297 13.568 ;
     RECT  131.796 13.441 134.442 13.631 ;
     RECT  131.796 13.631 132.297 13.739 ;
     RECT  0.108 13.339 0.126 13.801 ;
     RECT  2.412 13.055 9.99 13.873 ;
     RECT  133.308 13.631 134.442 13.873 ;
     RECT  135.18 13.433 137.697 13.873 ;
     RECT  2.376 13.873 9.99 13.915 ;
     RECT  2.376 13.915 10.026 13.981 ;
     RECT  10.764 13.369 13.734 13.981 ;
     RECT  14.652 11.849 14.778 13.981 ;
     RECT  2.304 13.981 10.026 14.009 ;
     RECT  0.108 13.801 0.162 14.045 ;
     RECT  2.304 14.009 3.042 14.135 ;
     RECT  133.308 13.873 137.697 14.207 ;
     RECT  3.78 14.009 10.026 14.251 ;
     RECT  10.764 13.981 14.778 14.251 ;
     RECT  27.432 10.859 28.17 14.525 ;
     RECT  15.624 13.567 18.897 14.639 ;
     RECT  133.308 14.207 134.442 14.675 ;
     RECT  139.068 12.281 139.086 14.683 ;
     RECT  2.415 14.135 3.042 14.755 ;
     RECT  3.78 14.251 14.778 14.755 ;
     RECT  139.032 14.683 139.086 14.783 ;
     RECT  2.415 14.755 15.498 14.909 ;
     RECT  135.216 14.207 137.697 14.989 ;
     RECT  2.415 14.909 3.366 15.025 ;
     RECT  0.108 14.045 0.126 15.053 ;
     RECT  135.072 14.989 137.697 15.061 ;
     RECT  135.072 15.061 137.826 15.089 ;
     RECT  4.176 14.909 15.498 15.179 ;
     RECT  130.536 15.151 130.554 15.223 ;
     RECT  130.536 15.223 130.626 15.287 ;
     RECT  130.608 15.287 130.626 15.323 ;
     RECT  16.236 14.639 18.897 15.457 ;
     RECT  140.292 15.259 140.31 15.485 ;
     RECT  16.236 15.457 19.278 15.493 ;
     RECT  16.236 15.493 19.35 15.593 ;
     RECT  133.884 14.675 134.01 15.593 ;
     RECT  135.36 15.089 137.826 15.601 ;
     RECT  2.304 15.025 3.366 15.691 ;
     RECT  4.176 15.179 11.97 15.691 ;
     RECT  2.304 15.691 11.97 15.719 ;
     RECT  0.54 15.421 0.558 15.725 ;
     RECT  139.068 14.783 139.086 15.791 ;
     RECT  13.104 15.179 15.498 15.835 ;
     RECT  16.236 15.593 19.278 15.835 ;
     RECT  134.388 15.835 134.406 15.871 ;
     RECT  135.36 15.601 138.006 15.871 ;
     RECT  134.388 15.871 138.006 15.965 ;
     RECT  139.608 15.835 139.626 16.061 ;
     RECT  134.568 15.965 138.006 16.123 ;
     RECT  134.568 16.123 138.51 16.169 ;
     RECT  2.304 15.719 2.862 16.231 ;
     RECT  3.96 15.719 11.97 16.259 ;
     RECT  138.492 16.169 138.51 16.331 ;
     RECT  20.556 13.441 25.362 16.367 ;
     RECT  132.015 13.739 132.297 16.375 ;
     RECT  133.236 16.141 133.254 16.375 ;
     RECT  132.015 16.375 133.254 16.411 ;
     RECT  47.052 15.979 47.07 16.501 ;
     RECT  0.108 15.961 0.126 16.529 ;
     RECT  47.052 16.501 47.178 16.529 ;
     RECT  132.015 16.411 133.614 16.589 ;
     RECT  140.292 16.411 140.31 16.673 ;
     RECT  1.728 16.231 2.862 16.733 ;
     RECT  108.936 16.771 108.954 16.829 ;
     RECT  31.212 11.551 31.23 16.835 ;
     RECT  13.104 15.835 19.278 16.843 ;
     RECT  133.092 16.589 133.614 16.877 ;
     RECT  2.304 16.733 2.862 16.879 ;
     RECT  108.612 16.843 108.63 16.88 ;
     RECT  110.415 7.085 110.697 16.939 ;
     RECT  12.78 16.843 19.782 16.943 ;
     RECT  134.568 16.169 137.697 16.951 ;
     RECT  138.528 16.699 139.086 17.021 ;
     RECT  4.176 16.259 10.926 17.041 ;
     RECT  11.664 16.259 11.97 17.041 ;
     RECT  0.54 16.879 0.558 17.069 ;
     RECT  25.02 16.367 25.362 17.069 ;
     RECT  134.568 16.951 137.754 17.105 ;
     RECT  4.176 17.041 12.042 17.221 ;
     RECT  12.78 16.943 16.29 17.221 ;
     RECT  27.612 14.525 28.17 17.221 ;
     RECT  133.236 16.877 133.614 17.221 ;
     RECT  134.568 17.105 137.697 17.221 ;
     RECT  4.176 17.221 16.29 17.311 ;
     RECT  34.815 13.565 35.097 17.311 ;
     RECT  45.615 13.568 45.897 17.311 ;
     RECT  56.415 7.088 56.697 17.311 ;
     RECT  67.215 7.088 67.497 17.311 ;
     RECT  78.015 7.088 78.297 17.311 ;
     RECT  88.815 7.088 89.097 17.311 ;
     RECT  99.615 7.088 99.897 17.311 ;
     RECT  2.304 16.879 3.294 17.339 ;
     RECT  110.415 16.939 111.15 17.339 ;
     RECT  34.704 17.311 35.097 17.357 ;
     RECT  45.504 17.311 45.897 17.357 ;
     RECT  56.304 17.311 56.697 17.357 ;
     RECT  67.104 17.311 67.497 17.357 ;
     RECT  77.904 17.311 78.297 17.357 ;
     RECT  88.704 17.311 89.097 17.357 ;
     RECT  99.504 17.311 99.897 17.357 ;
     RECT  4.104 17.311 16.29 17.375 ;
     RECT  133.236 17.221 137.697 17.375 ;
     RECT  17.064 16.943 19.782 17.383 ;
     RECT  20.556 16.367 24.297 17.383 ;
     RECT  47.16 16.529 47.178 17.405 ;
     RECT  25.272 17.069 25.362 17.453 ;
     RECT  106.596 17.323 106.614 17.453 ;
     RECT  2.415 17.339 3.294 17.455 ;
     RECT  4.104 17.375 12.042 17.455 ;
     RECT  110.415 17.339 110.934 17.519 ;
     RECT  130.536 16.411 130.554 17.519 ;
     RECT  134.064 17.375 137.697 17.933 ;
     RECT  134.064 17.933 134.766 17.951 ;
     RECT  27.612 17.221 28.278 17.987 ;
     RECT  12.924 17.375 16.29 17.995 ;
     RECT  17.064 17.383 24.297 17.995 ;
     RECT  135.684 17.933 137.697 18.059 ;
     RECT  135.72 18.059 137.697 18.139 ;
     RECT  139.068 17.021 139.086 18.139 ;
     RECT  0.108 17.371 0.126 18.149 ;
     RECT  2.415 17.455 12.042 18.221 ;
     RECT  135.72 18.139 139.086 18.221 ;
     RECT  2.415 18.221 2.754 18.379 ;
     RECT  12.924 17.995 24.297 18.391 ;
     RECT  132.015 16.589 132.297 18.427 ;
     RECT  133.236 17.375 133.326 18.427 ;
     RECT  134.496 17.951 134.766 18.491 ;
     RECT  133.236 18.427 133.434 18.509 ;
     RECT  132.012 18.427 132.297 18.535 ;
     RECT  25.344 17.453 25.362 18.557 ;
     RECT  132.012 18.535 132.354 18.599 ;
     RECT  134.496 18.491 134.694 18.689 ;
     RECT  111.42 18.661 111.762 18.701 ;
     RECT  111.744 18.701 111.762 18.749 ;
     RECT  3.528 18.221 12.042 18.763 ;
     RECT  12.78 18.391 24.297 18.763 ;
     RECT  133.416 18.509 133.434 18.797 ;
     RECT  140.292 18.715 140.31 18.869 ;
     RECT  135.72 18.221 137.697 18.955 ;
     RECT  134.496 18.689 134.658 18.959 ;
     RECT  2.304 18.379 2.754 18.967 ;
     RECT  3.528 18.763 24.297 18.967 ;
     RECT  2.304 18.967 24.297 18.995 ;
     RECT  134.496 18.959 134.622 19.003 ;
     RECT  26.208 10.391 26.226 19.085 ;
     RECT  135.576 18.955 137.697 19.111 ;
     RECT  134.316 19.003 134.622 19.139 ;
     RECT  2.34 18.995 24.297 19.229 ;
     RECT  134.316 19.139 134.334 19.229 ;
     RECT  135.432 19.111 137.697 19.301 ;
     RECT  132.015 18.599 132.354 19.387 ;
     RECT  132.015 19.387 132.534 19.499 ;
     RECT  0.108 19.051 0.126 19.741 ;
     RECT  27.612 17.987 27.738 19.769 ;
     RECT  0.108 19.741 0.558 19.805 ;
     RECT  133.128 19.651 133.146 19.805 ;
     RECT  135.72 19.301 137.697 19.877 ;
     RECT  139.068 18.221 139.086 19.913 ;
     RECT  130.536 19.201 130.554 19.949 ;
     RECT  0.108 19.805 0.126 20.141 ;
     RECT  2.415 19.229 24.297 20.155 ;
     RECT  136.548 19.877 137.697 20.155 ;
     RECT  27.612 19.769 27.63 20.333 ;
     RECT  136.548 20.155 138.366 20.381 ;
     RECT  134.532 20.191 134.55 20.425 ;
     RECT  135.72 19.877 135.738 20.461 ;
     RECT  134.424 20.425 134.55 20.551 ;
     RECT  2.304 20.155 24.297 20.579 ;
     RECT  4.068 20.579 24.297 20.651 ;
     RECT  134.208 20.551 134.55 20.695 ;
     RECT  132.015 19.499 132.297 20.731 ;
     RECT  134.1 20.695 134.55 20.731 ;
     RECT  135.684 20.461 135.738 20.731 ;
     RECT  134.1 20.731 135.81 20.779 ;
     RECT  136.548 20.381 138.042 20.779 ;
     RECT  4.068 20.651 23.094 20.849 ;
     RECT  132.015 20.731 133.11 20.857 ;
     RECT  132.015 20.857 133.182 20.885 ;
     RECT  132.015 20.885 132.426 20.909 ;
     RECT  134.1 20.779 138.042 20.923 ;
     RECT  130.536 20.827 130.554 20.929 ;
     RECT  130.536 20.929 130.59 20.957 ;
     RECT  133.164 20.885 133.182 20.957 ;
     RECT  2.304 20.579 3.294 21.029 ;
     RECT  130.572 20.957 130.59 21.029 ;
     RECT  133.956 20.923 138.042 21.029 ;
     RECT  29.232 9.049 29.697 21.119 ;
     RECT  0.108 21.115 0.126 21.163 ;
     RECT  82.656 21.127 82.674 21.227 ;
     RECT  80.28 21.091 80.298 21.245 ;
     RECT  23.94 20.651 24.297 21.347 ;
     RECT  29.415 21.119 29.697 21.347 ;
     RECT  34.815 17.357 35.097 21.347 ;
     RECT  40.215 2.413 40.497 21.347 ;
     RECT  45.615 17.357 45.897 21.347 ;
     RECT  51.015 13.568 51.297 21.347 ;
     RECT  56.415 17.357 56.697 21.347 ;
     RECT  61.815 2.413 62.097 21.347 ;
     RECT  67.215 17.357 67.497 21.347 ;
     RECT  72.615 2.413 72.897 21.347 ;
     RECT  78.015 17.357 78.297 21.347 ;
     RECT  83.415 2.413 83.697 21.347 ;
     RECT  88.815 17.357 89.097 21.347 ;
     RECT  94.215 2.413 94.497 21.347 ;
     RECT  99.615 17.357 99.897 21.347 ;
     RECT  105.015 2.413 105.297 21.347 ;
     RECT  110.415 17.519 110.697 21.347 ;
     RECT  115.815 2.413 116.097 21.347 ;
     RECT  134.496 21.029 138.042 21.389 ;
     RECT  118.296 21.361 118.602 21.485 ;
     RECT  23.94 21.347 24.105 21.497 ;
     RECT  2.34 21.029 3.294 21.505 ;
     RECT  4.068 20.849 23.058 21.505 ;
     RECT  118.296 21.485 118.314 21.541 ;
     RECT  24.015 21.497 24.105 21.617 ;
     RECT  29.415 21.347 29.505 21.617 ;
     RECT  34.815 21.347 34.905 21.617 ;
     RECT  40.215 21.347 40.305 21.617 ;
     RECT  45.615 21.347 45.705 21.617 ;
     RECT  51.015 21.347 51.105 21.617 ;
     RECT  56.415 21.347 56.505 21.617 ;
     RECT  61.815 21.347 61.905 21.617 ;
     RECT  67.215 21.347 67.305 21.617 ;
     RECT  72.615 21.347 72.705 21.617 ;
     RECT  78.015 21.347 78.105 21.617 ;
     RECT  83.415 21.347 83.505 21.617 ;
     RECT  88.815 21.347 88.905 21.617 ;
     RECT  94.215 21.347 94.305 21.617 ;
     RECT  99.615 21.347 99.705 21.617 ;
     RECT  105.015 21.347 105.105 21.617 ;
     RECT  110.415 21.347 110.505 21.617 ;
     RECT  115.815 21.347 115.905 21.617 ;
     RECT  133.2 21.001 133.218 21.631 ;
     RECT  132.015 20.909 132.297 21.643 ;
     RECT  2.34 21.505 23.058 21.659 ;
     RECT  117.972 21.541 118.314 21.677 ;
     RECT  131.58 21.643 132.297 21.695 ;
     RECT  134.496 21.389 137.898 21.695 ;
     RECT  140.292 19.867 140.31 21.767 ;
     RECT  132.015 21.695 132.297 21.811 ;
     RECT  134.496 21.695 134.586 21.811 ;
     RECT  0.108 21.163 0.162 21.929 ;
     RECT  132.015 21.811 132.426 21.965 ;
     RECT  133.2 21.631 133.398 22.037 ;
     RECT  2.34 21.659 22.806 22.081 ;
     RECT  0.54 21.973 0.558 22.157 ;
     RECT  126.615 2.413 126.897 22.171 ;
     RECT  2.304 22.081 22.806 22.199 ;
     RECT  135.648 21.695 137.898 22.199 ;
     RECT  126.216 22.171 126.897 22.315 ;
     RECT  53.532 20.965 53.55 22.379 ;
     RECT  134.208 21.811 134.586 22.441 ;
     RECT  135.648 22.199 137.697 22.469 ;
     RECT  116.856 21.163 116.874 22.477 ;
     RECT  117.972 21.677 117.99 22.477 ;
     RECT  116.856 22.477 117.99 22.549 ;
     RECT  124.632 21.811 124.65 22.549 ;
     RECT  119.988 22.081 120.006 22.585 ;
     RECT  121.215 2.413 121.497 22.585 ;
     RECT  130.212 22.351 130.23 22.603 ;
     RECT  121.104 22.585 121.497 22.637 ;
     RECT  116.856 22.549 118.278 22.694 ;
     RECT  119.952 22.585 120.006 22.711 ;
     RECT  133.848 22.441 134.586 22.711 ;
     RECT  2.376 22.199 22.806 22.739 ;
     RECT  130.212 22.603 130.59 22.781 ;
     RECT  130.212 22.781 130.554 22.811 ;
     RECT  139.068 20.731 139.086 22.811 ;
     RECT  117.684 22.694 118.278 22.855 ;
     RECT  135.72 22.469 137.697 22.981 ;
     RECT  119.376 22.711 120.006 23.125 ;
     RECT  132.015 21.965 132.297 23.125 ;
     RECT  132.015 23.125 132.894 23.161 ;
     RECT  133.848 22.711 134.802 23.161 ;
     RECT  122.544 23.125 122.562 23.179 ;
     RECT  132.015 23.161 134.802 23.251 ;
     RECT  135.72 22.981 137.754 23.251 ;
     RECT  0.108 22.795 0.126 23.279 ;
     RECT  122.544 23.179 122.598 23.279 ;
     RECT  122.58 23.279 122.598 23.309 ;
     RECT  138.528 23.317 138.546 23.357 ;
     RECT  2.415 22.739 22.806 23.467 ;
     RECT  130.212 22.811 130.23 23.701 ;
     RECT  2.34 23.467 22.806 23.76 ;
     RECT  116.856 22.694 116.874 23.76 ;
     RECT  117.684 22.855 118.314 23.76 ;
     RECT  2.34 23.76 118.314 23.803 ;
     RECT  130.212 23.701 130.554 23.819 ;
     RECT  132.015 23.251 137.754 23.819 ;
     RECT  140.292 23.035 140.31 23.899 ;
     RECT  140.256 23.899 140.31 24.233 ;
     RECT  139.068 23.611 139.086 24.503 ;
     RECT  132.015 23.819 137.697 24.629 ;
     RECT  140.292 24.233 140.31 24.665 ;
     RECT  129.204 17.383 129.222 24.667 ;
     RECT  130.212 23.819 130.23 24.667 ;
     RECT  129.204 24.667 130.23 24.709 ;
     RECT  2.304 23.803 118.314 24.715 ;
     RECT  136.044 24.629 137.697 24.811 ;
     RECT  123.912 22.549 124.65 25.003 ;
     RECT  125.676 22.315 126.897 25.003 ;
     RECT  136.044 24.811 137.97 25.313 ;
     RECT  119.376 23.125 120.258 25.387 ;
     RECT  121.215 22.637 121.497 25.387 ;
     RECT  135.288 24.629 135.306 25.447 ;
     RECT  136.044 25.313 137.79 25.447 ;
     RECT  135.288 25.447 137.79 25.483 ;
     RECT  132.015 24.629 134.226 25.519 ;
     RECT  135.108 25.483 137.79 25.519 ;
     RECT  129.204 24.709 130.554 25.619 ;
     RECT  132.015 25.519 137.79 25.619 ;
     RECT  135.108 25.619 137.79 25.817 ;
     RECT  135.504 25.817 137.79 26.251 ;
     RECT  135.504 26.251 137.97 26.393 ;
     RECT  132.015 25.619 134.226 26.401 ;
     RECT  0.108 26.401 0.126 26.525 ;
     RECT  123.12 26.107 123.138 26.539 ;
     RECT  122.796 26.539 123.138 26.635 ;
     RECT  123.912 25.003 126.897 26.635 ;
     RECT  2.304 24.715 118.602 26.827 ;
     RECT  119.376 25.387 121.497 26.827 ;
     RECT  135.504 26.393 137.826 26.897 ;
     RECT  132.015 26.401 134.586 27.031 ;
     RECT  135.504 26.897 136.566 27.031 ;
     RECT  132.015 27.031 136.566 27.095 ;
     RECT  132.015 27.095 134.334 27.101 ;
     RECT  139.068 25.387 139.086 27.115 ;
     RECT  137.415 26.897 137.826 27.131 ;
     RECT  2.304 26.827 121.497 27.197 ;
     RECT  135.072 27.095 136.566 27.365 ;
     RECT  2.304 27.197 16.434 27.509 ;
     RECT  17.352 27.197 121.497 27.691 ;
     RECT  0.108 27.547 0.126 27.707 ;
     RECT  129.204 25.619 130.266 27.751 ;
     RECT  137.415 27.131 137.697 27.877 ;
     RECT  2.304 27.509 2.898 27.905 ;
     RECT  129.204 27.751 130.626 27.941 ;
     RECT  139.032 27.115 139.086 27.941 ;
     RECT  137.415 27.877 137.934 28.111 ;
     RECT  136.872 28.111 137.934 28.139 ;
     RECT  0.144 27.883 0.162 28.219 ;
     RECT  136.872 28.139 137.697 28.291 ;
     RECT  135.072 27.365 135.882 28.381 ;
     RECT  136.8 28.291 137.697 28.381 ;
     RECT  2.415 27.905 2.898 28.417 ;
     RECT  3.636 27.509 16.434 28.417 ;
     RECT  122.796 26.635 126.897 28.453 ;
     RECT  0.144 28.219 0.558 28.555 ;
     RECT  132.015 27.101 134.118 28.795 ;
     RECT  135.072 28.381 137.697 28.795 ;
     RECT  17.352 27.691 122.022 28.831 ;
     RECT  122.76 28.453 126.897 28.831 ;
     RECT  132.015 28.795 137.697 28.921 ;
     RECT  0.108 28.555 0.558 28.925 ;
     RECT  131.544 28.921 137.697 28.973 ;
     RECT  2.415 28.417 16.434 29.101 ;
     RECT  131.832 28.973 137.697 29.371 ;
     RECT  128.448 19.003 128.466 29.569 ;
     RECT  129.204 27.941 130.266 29.569 ;
     RECT  131.832 29.371 137.79 29.633 ;
     RECT  139.068 27.941 139.086 29.831 ;
     RECT  17.352 28.831 126.897 29.837 ;
     RECT  128.448 29.569 130.266 29.899 ;
     RECT  136.26 29.633 137.79 29.995 ;
     RECT  2.415 29.101 16.614 30.145 ;
     RECT  131.832 29.633 135.522 30.145 ;
     RECT  2.304 30.145 16.614 30.181 ;
     RECT  1.728 30.181 16.614 30.269 ;
     RECT  136.26 29.995 137.97 30.283 ;
     RECT  2.304 30.269 16.614 30.299 ;
     RECT  136.26 30.283 138.366 30.371 ;
     RECT  131.364 30.145 135.522 30.451 ;
     RECT  136.26 30.371 137.754 30.451 ;
     RECT  0.108 28.925 0.126 30.605 ;
     RECT  131.364 30.451 137.754 30.713 ;
     RECT  128.448 29.899 130.59 30.955 ;
     RECT  0.54 30.907 0.558 31.019 ;
     RECT  128.448 30.955 130.626 31.109 ;
     RECT  2.415 30.299 16.614 31.147 ;
     RECT  2.304 31.147 16.614 31.189 ;
     RECT  17.388 29.837 126.897 31.189 ;
     RECT  127.62 15.223 127.638 31.243 ;
     RECT  134.892 30.713 137.754 31.379 ;
     RECT  2.304 31.189 126.897 31.469 ;
     RECT  139.068 30.571 139.086 31.523 ;
     RECT  0.108 31.579 0.126 31.649 ;
     RECT  131.364 30.713 134.082 31.729 ;
     RECT  134.892 31.379 137.697 31.729 ;
     RECT  2.304 31.469 16.65 31.891 ;
     RECT  1.728 31.891 16.65 31.949 ;
     RECT  2.304 31.949 16.65 31.955 ;
     RECT  140.292 31.147 140.31 31.955 ;
     RECT  138.492 31.927 138.51 32.011 ;
     RECT  127.62 31.243 127.71 32.251 ;
     RECT  128.448 31.109 130.59 32.251 ;
     RECT  138.456 32.011 138.51 32.299 ;
     RECT  17.424 31.469 126.897 32.467 ;
     RECT  127.62 32.251 130.59 32.467 ;
     RECT  0.54 31.963 0.558 32.587 ;
     RECT  0.108 32.587 0.558 32.999 ;
     RECT  0.54 32.999 0.558 33.071 ;
     RECT  138.456 32.299 139.086 33.071 ;
     RECT  131.364 31.729 137.697 33.163 ;
     RECT  2.304 31.955 16.614 33.269 ;
     RECT  2.304 33.269 16.542 33.293 ;
     RECT  131.364 33.163 137.97 33.413 ;
     RECT  17.424 32.467 130.59 33.421 ;
     RECT  17.424 33.421 130.626 33.611 ;
     RECT  2.304 33.293 16.326 33.845 ;
     RECT  0.108 33.931 0.126 34.349 ;
     RECT  2.34 33.845 16.326 34.603 ;
     RECT  17.424 33.611 130.59 34.771 ;
     RECT  131.364 33.413 137.697 34.891 ;
     RECT  131.364 34.891 137.97 35.033 ;
     RECT  2.304 34.603 16.326 35.131 ;
     RECT  139.068 33.071 139.086 35.179 ;
     RECT  138.492 35.179 139.086 35.231 ;
     RECT  2.304 35.131 16.578 35.309 ;
     RECT  2.304 35.309 16.326 35.311 ;
     RECT  1.728 35.311 16.326 35.357 ;
     RECT  17.424 34.771 130.626 35.419 ;
     RECT  131.364 35.033 137.697 35.419 ;
     RECT  0.144 35.131 0.162 35.659 ;
     RECT  139.032 35.231 139.086 35.843 ;
     RECT  0.108 35.659 0.162 36.041 ;
     RECT  2.304 35.357 16.326 36.211 ;
     RECT  139.068 35.843 139.086 36.331 ;
     RECT  0.144 36.041 0.162 36.365 ;
     RECT  139.068 36.331 139.626 36.653 ;
     RECT  1.728 36.211 16.326 36.701 ;
     RECT  2.304 36.701 16.326 37.121 ;
     RECT  140.292 36.907 140.31 37.193 ;
     RECT  0.108 37.291 0.126 37.373 ;
     RECT  139.068 36.653 139.086 37.483 ;
     RECT  2.304 37.121 3.042 37.561 ;
     RECT  138.492 37.483 139.086 37.625 ;
     RECT  3.924 37.121 16.326 37.867 ;
     RECT  3.924 37.867 16.47 37.963 ;
     RECT  17.424 35.419 137.697 37.963 ;
     RECT  1.728 37.561 3.042 38.011 ;
     RECT  3.924 37.963 137.697 38.011 ;
     RECT  1.728 38.011 137.697 38.045 ;
     RECT  139.068 37.625 139.086 38.635 ;
     RECT  138.492 38.635 139.086 38.705 ;
     RECT  2.415 38.045 137.697 38.741 ;
     RECT  2.415 38.741 13.59 38.785 ;
     RECT  2.376 38.785 13.59 38.911 ;
     RECT  14.508 38.741 137.697 38.923 ;
     RECT  1.728 38.911 13.59 39.083 ;
     RECT  139.068 38.705 139.086 39.281 ;
     RECT  1.728 39.083 4.41 39.389 ;
     RECT  14.508 38.923 137.97 39.623 ;
     RECT  5.148 39.083 13.59 39.631 ;
     RECT  2.34 39.389 4.41 39.829 ;
     RECT  5.148 39.631 13.698 39.829 ;
     RECT  0.108 38.347 0.126 40.061 ;
     RECT  2.34 39.829 13.698 40.135 ;
     RECT  14.508 39.623 137.697 40.163 ;
     RECT  0.54 40.363 0.558 40.469 ;
     RECT  2.304 40.135 13.698 40.555 ;
     RECT  2.268 40.555 13.698 40.651 ;
     RECT  14.508 40.163 121.497 40.651 ;
     RECT  140.292 39.787 140.31 40.703 ;
     RECT  2.268 40.651 121.497 40.877 ;
     RECT  139.068 40.075 139.086 40.936 ;
     RECT  138.492 40.936 139.086 40.973 ;
     RECT  0.108 41.035 0.126 41.099 ;
     RECT  2.268 40.877 14.238 41.341 ;
     RECT  1.728 41.341 14.238 41.371 ;
     RECT  139.068 40.973 139.086 41.513 ;
     RECT  139.608 41.515 139.626 41.711 ;
     RECT  1.152 41.371 14.238 41.741 ;
     RECT  122.256 40.163 137.697 41.803 ;
     RECT  2.376 41.741 14.238 41.899 ;
     RECT  15.012 40.877 121.497 41.899 ;
     RECT  122.256 41.803 137.97 42.053 ;
     RECT  140.292 42.091 140.31 42.215 ;
     RECT  1.152 41.741 1.17 42.449 ;
     RECT  0.108 41.899 0.126 42.629 ;
     RECT  2.376 41.899 121.497 42.691 ;
     RECT  1.728 42.691 121.497 42.719 ;
     RECT  1.728 42.719 3.222 42.797 ;
     RECT  122.436 42.053 137.97 43.133 ;
     RECT  0.144 43.099 0.162 43.169 ;
     RECT  2.268 42.797 3.222 43.537 ;
     RECT  3.96 42.719 121.497 43.537 ;
     RECT  139.068 42.667 139.086 43.573 ;
     RECT  138.528 43.573 139.086 43.853 ;
     RECT  2.268 43.537 121.497 44.041 ;
     RECT  0.108 43.771 0.126 44.107 ;
     RECT  0.108 44.107 0.558 44.147 ;
     RECT  122.436 43.133 137.697 44.221 ;
     RECT  122.436 44.221 138.042 44.339 ;
     RECT  139.032 43.853 139.086 44.411 ;
     RECT  139.032 44.411 139.05 44.447 ;
     RECT  1.728 44.041 121.497 44.813 ;
     RECT  2.34 44.813 121.497 44.879 ;
     RECT  122.436 44.339 137.97 45.023 ;
     RECT  140.292 44.971 140.31 45.293 ;
     RECT  139.068 45.259 139.086 45.491 ;
     RECT  0.108 44.147 0.126 45.661 ;
     RECT  2.415 44.879 121.497 45.689 ;
     RECT  139.608 45.547 139.626 45.797 ;
     RECT  2.415 45.689 2.697 45.805 ;
     RECT  138.528 45.805 138.546 45.869 ;
     RECT  0.108 45.661 0.162 46.157 ;
     RECT  2.304 45.805 2.697 46.229 ;
     RECT  140.292 46.123 140.31 46.265 ;
     RECT  2.376 46.229 2.697 46.471 ;
     RECT  3.42 45.689 121.497 46.471 ;
     RECT  139.068 46.411 139.086 46.699 ;
     RECT  2.376 46.471 121.497 47.083 ;
     RECT  139.068 46.699 139.122 47.275 ;
     RECT  139.068 47.275 139.626 47.381 ;
     RECT  139.068 47.381 139.086 47.651 ;
     RECT  0.108 46.157 0.126 47.849 ;
     RECT  138.492 47.848 138.51 48.191 ;
     RECT  1.296 48.139 1.314 48.361 ;
     RECT  2.268 47.083 121.497 48.361 ;
     RECT  139.608 48.427 139.626 48.731 ;
     RECT  1.296 48.361 121.497 48.845 ;
     RECT  138.528 48.973 138.546 49.291 ;
     RECT  122.436 45.023 137.697 49.343 ;
     RECT  138.492 49.291 138.546 49.343 ;
     RECT  1.296 48.845 1.314 49.379 ;
     RECT  122.436 49.343 135.954 49.469 ;
     RECT  136.8 49.343 137.697 49.855 ;
     RECT  136.8 49.855 137.97 49.901 ;
     RECT  2.304 48.845 121.497 50.009 ;
     RECT  139.104 49.549 139.122 50.189 ;
     RECT  138.492 50.395 138.51 50.477 ;
     RECT  122.436 49.469 135.846 50.521 ;
     RECT  136.8 49.901 137.697 50.521 ;
     RECT  122.436 50.521 137.697 50.779 ;
     RECT  122.436 50.779 137.97 50.891 ;
     RECT  136.8 50.891 137.97 50.963 ;
     RECT  139.068 51.067 139.086 51.403 ;
     RECT  122.436 50.891 135.846 51.739 ;
     RECT  136.8 50.963 137.754 51.739 ;
     RECT  122.436 51.739 137.754 51.745 ;
     RECT  138.528 51.403 139.086 51.745 ;
     RECT  122.436 51.745 139.086 51.779 ;
     RECT  122.436 51.779 135.846 52.079 ;
     RECT  1.152 51.883 1.17 52.141 ;
     RECT  2.415 50.009 121.497 52.141 ;
     RECT  136.692 51.779 139.086 52.169 ;
     RECT  1.152 52.141 121.497 52.589 ;
     RECT  136.692 52.169 137.697 52.789 ;
     RECT  122.436 52.079 129.078 52.861 ;
     RECT  129.816 52.079 135.846 52.861 ;
     RECT  136.62 52.789 137.697 52.861 ;
     RECT  138.492 52.169 139.086 52.889 ;
     RECT  122.436 52.861 137.697 53.159 ;
     RECT  1.152 52.589 1.17 53.249 ;
     RECT  2.376 52.589 121.497 53.365 ;
     RECT  122.436 53.159 135.846 53.401 ;
     RECT  139.068 52.889 139.086 53.401 ;
     RECT  122.328 53.401 135.846 53.519 ;
     RECT  136.764 53.159 137.697 53.519 ;
     RECT  139.068 53.401 139.122 53.693 ;
     RECT  0.108 49.147 0.126 53.833 ;
     RECT  2.304 53.365 121.497 54.059 ;
     RECT  129.816 53.519 135.846 54.067 ;
     RECT  2.415 54.059 121.497 54.365 ;
     RECT  137.16 53.519 137.697 54.679 ;
     RECT  129.816 54.067 136.314 54.841 ;
     RECT  137.16 54.679 137.97 54.841 ;
     RECT  129.816 54.841 137.97 54.845 ;
     RECT  0.108 53.833 0.558 54.941 ;
     RECT  2.415 54.365 3.51 54.985 ;
     RECT  139.068 53.693 139.086 55.099 ;
     RECT  4.32 54.365 121.497 55.111 ;
     RECT  2.376 54.985 3.51 55.147 ;
     RECT  138.492 55.099 139.086 55.211 ;
     RECT  0.54 54.941 0.558 55.277 ;
     RECT  1.728 55.147 3.51 55.291 ;
     RECT  4.248 55.111 121.497 55.291 ;
     RECT  122.328 53.519 129.078 55.409 ;
     RECT  1.728 55.291 121.497 55.613 ;
     RECT  139.068 55.211 139.086 56.093 ;
     RECT  129.816 54.845 137.697 56.219 ;
     RECT  2.415 55.613 121.497 56.371 ;
     RECT  138.528 56.533 138.546 56.573 ;
     RECT  129.852 56.219 137.697 56.633 ;
     RECT  140.292 56.251 140.31 56.633 ;
     RECT  129.852 56.633 136.53 57.065 ;
     RECT  137.415 56.633 137.697 57.115 ;
     RECT  138.492 56.827 138.51 57.115 ;
     RECT  122.328 55.409 123.462 57.299 ;
     RECT  137.415 57.115 138.51 57.343 ;
     RECT  137.415 57.343 138.546 57.379 ;
     RECT  136.8 57.379 138.546 57.725 ;
     RECT  136.8 57.725 137.97 57.749 ;
     RECT  129.852 57.065 135.918 57.811 ;
     RECT  129.852 57.811 136.566 57.883 ;
     RECT  124.38 55.409 129.078 57.991 ;
     RECT  129.816 57.883 136.566 57.991 ;
     RECT  0.108 55.912 0.126 58.013 ;
     RECT  124.38 57.991 136.566 58.109 ;
     RECT  122.328 57.299 123.426 58.261 ;
     RECT  124.38 58.109 136.17 58.261 ;
     RECT  122.328 58.261 136.17 58.379 ;
     RECT  124.38 58.379 136.17 58.487 ;
     RECT  137.415 57.749 137.97 58.495 ;
     RECT  137.415 58.495 138.546 58.531 ;
     RECT  122.328 58.379 123.426 58.559 ;
     RECT  137.124 58.531 138.546 58.589 ;
     RECT  1.728 56.371 121.497 58.651 ;
     RECT  137.124 58.589 138.474 58.891 ;
     RECT  129.852 58.487 136.17 58.963 ;
     RECT  1.152 58.651 121.497 59.021 ;
     RECT  129.852 58.963 136.242 59.071 ;
     RECT  137.088 58.891 138.474 59.261 ;
     RECT  2.268 59.021 121.497 59.357 ;
     RECT  129.852 59.071 136.35 59.467 ;
     RECT  137.088 59.261 137.97 59.467 ;
     RECT  2.304 59.357 121.497 59.531 ;
     RECT  1.152 59.021 1.17 59.567 ;
     RECT  129.852 59.467 137.97 59.603 ;
     RECT  2.304 59.531 13.734 59.729 ;
     RECT  14.508 59.531 121.497 59.909 ;
     RECT  4.248 59.729 13.734 60.035 ;
     RECT  0.108 59.995 0.126 60.269 ;
     RECT  129.852 59.603 137.697 60.269 ;
     RECT  4.248 60.035 13.626 60.377 ;
     RECT  139.068 59.707 139.086 60.413 ;
     RECT  137.304 60.269 137.697 60.571 ;
     RECT  2.304 59.729 3.474 60.781 ;
     RECT  4.248 60.377 13.554 60.781 ;
     RECT  137.304 60.571 137.97 60.853 ;
     RECT  137.304 60.853 138.546 60.893 ;
     RECT  137.304 60.893 137.97 60.917 ;
     RECT  2.304 60.781 13.554 61.079 ;
     RECT  129.852 60.269 136.242 61.087 ;
     RECT  2.304 61.079 3.618 61.115 ;
     RECT  4.356 61.079 13.554 61.231 ;
     RECT  14.508 59.909 120.042 61.231 ;
     RECT  124.38 58.487 129.078 61.259 ;
     RECT  0.54 60.313 0.558 61.321 ;
     RECT  0.108 61.321 0.558 61.373 ;
     RECT  129.852 61.087 136.458 61.501 ;
     RECT  137.304 60.917 137.697 61.501 ;
     RECT  140.292 61.435 140.31 61.655 ;
     RECT  0.54 61.373 0.558 61.709 ;
     RECT  4.356 61.231 120.042 61.889 ;
     RECT  4.392 61.889 120.042 61.925 ;
     RECT  139.068 61.147 139.086 61.961 ;
     RECT  2.376 61.115 3.618 62.069 ;
     RECT  139.608 62.011 139.626 62.267 ;
     RECT  2.415 62.069 3.618 62.311 ;
     RECT  138.528 62.275 138.546 62.333 ;
     RECT  129.852 61.501 137.697 62.579 ;
     RECT  140.292 62.587 140.31 62.807 ;
     RECT  0.108 62.347 0.126 62.851 ;
     RECT  1.152 62.779 1.17 62.851 ;
     RECT  2.415 62.311 3.654 62.851 ;
     RECT  4.392 61.925 13.734 62.851 ;
     RECT  0.108 62.851 1.17 62.941 ;
     RECT  2.415 62.851 13.734 62.941 ;
     RECT  0.108 62.941 13.734 63.053 ;
     RECT  138.456 62.875 138.474 63.121 ;
     RECT  138.456 63.121 138.546 63.197 ;
     RECT  136.62 62.579 137.697 63.239 ;
     RECT  1.152 63.053 13.734 63.389 ;
     RECT  129.852 62.579 135.882 63.517 ;
     RECT  136.62 63.239 136.638 63.517 ;
     RECT  137.415 63.239 137.697 63.739 ;
     RECT  2.268 63.389 13.734 63.779 ;
     RECT  139.068 63.451 139.086 63.823 ;
     RECT  2.304 63.779 13.734 63.851 ;
     RECT  1.152 63.389 1.17 63.959 ;
     RECT  129.852 63.517 136.638 64.291 ;
     RECT  137.415 63.739 137.826 64.291 ;
     RECT  129.852 64.291 137.826 64.319 ;
     RECT  124.38 61.259 129.042 64.357 ;
     RECT  129.852 64.319 137.79 64.357 ;
     RECT  139.068 63.823 139.122 64.391 ;
     RECT  124.38 64.357 137.79 64.397 ;
     RECT  124.38 64.397 136.566 64.589 ;
     RECT  139.104 64.391 139.122 64.637 ;
     RECT  2.376 63.851 13.734 64.741 ;
     RECT  124.38 64.589 136.458 64.781 ;
     RECT  14.508 61.925 120.042 64.824 ;
     RECT  137.376 64.397 137.79 64.973 ;
     RECT  14.508 64.824 22.23 65.039 ;
     RECT  140.292 64.891 140.31 65.039 ;
     RECT  137.412 64.973 137.79 65.165 ;
     RECT  123.12 58.559 123.426 65.237 ;
     RECT  123.12 65.237 123.318 65.273 ;
     RECT  124.38 64.781 129.042 65.273 ;
     RECT  14.508 65.039 22.194 65.309 ;
     RECT  123.12 65.273 123.138 65.399 ;
     RECT  139.068 65.179 139.086 65.507 ;
     RECT  124.704 65.273 129.042 65.563 ;
     RECT  129.852 64.781 136.458 65.563 ;
     RECT  16.776 65.309 22.194 65.669 ;
     RECT  16.776 65.669 22.05 65.741 ;
     RECT  122.328 58.559 122.346 65.741 ;
     RECT  124.704 65.563 136.458 65.785 ;
     RECT  137.412 65.165 137.697 65.785 ;
     RECT  121.215 59.909 121.497 65.803 ;
     RECT  114.588 65.596 114.606 65.813 ;
     RECT  121.104 65.803 121.497 65.849 ;
     RECT  2.304 64.741 13.734 65.939 ;
     RECT  117.324 64.824 120.042 65.939 ;
     RECT  124.704 65.785 137.697 65.939 ;
     RECT  2.34 65.939 13.734 66.011 ;
     RECT  138.492 65.755 138.51 66.011 ;
     RECT  133.668 65.939 137.697 66.245 ;
     RECT  16.776 65.741 21.978 66.281 ;
     RECT  124.704 65.939 129.042 66.281 ;
     RECT  14.508 65.309 15.714 66.317 ;
     RECT  119.952 65.939 120.042 66.317 ;
     RECT  124.884 66.281 129.042 66.317 ;
     RECT  140.292 66.043 140.31 66.317 ;
     RECT  137.415 66.245 137.697 66.331 ;
     RECT  2.376 66.011 13.734 66.361 ;
     RECT  2.376 66.361 13.806 66.479 ;
     RECT  137.415 66.331 137.97 66.623 ;
     RECT  108.144 66.361 108.162 66.676 ;
     RECT  108.072 66.676 108.162 66.704 ;
     RECT  121.215 65.849 121.497 66.715 ;
     RECT  16.776 66.281 20.502 66.749 ;
     RECT  0.108 63.053 0.126 66.793 ;
     RECT  0.108 66.793 0.558 66.797 ;
     RECT  124.884 66.317 124.902 66.821 ;
     RECT  139.608 66.619 139.626 66.821 ;
     RECT  121.215 66.715 121.59 66.845 ;
     RECT  122.544 66.715 122.562 66.845 ;
     RECT  126.216 66.317 129.042 66.857 ;
     RECT  2.376 66.479 13.662 66.865 ;
     RECT  129.852 65.939 132.93 66.865 ;
     RECT  133.668 66.245 136.386 66.865 ;
     RECT  119.952 66.317 119.97 66.929 ;
     RECT  45.576 66.901 45.594 66.943 ;
     RECT  24.015 66.943 24.105 66.991 ;
     RECT  34.815 66.943 34.905 66.991 ;
     RECT  110.415 66.943 110.505 66.991 ;
     RECT  41.904 66.811 41.922 67.019 ;
     RECT  45.576 66.943 45.705 67.019 ;
     RECT  105.015 66.943 105.105 67.027 ;
     RECT  23.904 66.991 24.21 67.037 ;
     RECT  34.704 66.991 34.905 67.037 ;
     RECT  99.615 66.943 99.705 67.051 ;
     RECT  104.436 67.027 105.105 67.051 ;
     RECT  35.892 66.991 35.91 67.063 ;
     RECT  88.815 66.943 88.905 67.063 ;
     RECT  104.436 67.051 105.138 67.063 ;
     RECT  129.852 66.865 136.386 67.085 ;
     RECT  71.568 67.051 71.586 67.091 ;
     RECT  129.852 67.085 132.93 67.091 ;
     RECT  91.62 67.027 91.638 67.099 ;
     RECT  98.748 67.027 98.766 67.099 ;
     RECT  133.668 67.085 136.386 67.099 ;
     RECT  137.415 66.623 137.697 67.099 ;
     RECT  0.54 66.797 0.558 67.133 ;
     RECT  114.588 67.003 114.606 67.133 ;
     RECT  88.815 67.063 89.262 67.135 ;
     RECT  106.668 67.099 106.686 67.136 ;
     RECT  2.304 66.865 13.662 67.171 ;
     RECT  82.548 67.135 82.566 67.171 ;
     RECT  83.415 66.943 83.505 67.171 ;
     RECT  91.296 67.099 91.638 67.171 ;
     RECT  98.388 67.099 98.766 67.171 ;
     RECT  102.744 67.135 102.762 67.171 ;
     RECT  104.364 67.063 105.138 67.171 ;
     RECT  126.252 66.857 129.042 67.181 ;
     RECT  24.015 67.037 24.21 67.213 ;
     RECT  29.415 66.943 29.505 67.213 ;
     RECT  34.815 67.037 34.905 67.213 ;
     RECT  40.215 66.943 40.305 67.213 ;
     RECT  45.615 67.019 45.705 67.213 ;
     RECT  51.015 66.943 51.105 67.213 ;
     RECT  56.415 66.943 56.505 67.213 ;
     RECT  61.815 66.943 61.905 67.213 ;
     RECT  67.215 66.943 67.305 67.213 ;
     RECT  72.615 66.943 72.705 67.213 ;
     RECT  78.015 66.943 78.105 67.213 ;
     RECT  82.548 67.171 83.505 67.213 ;
     RECT  94.215 66.943 94.305 67.213 ;
     RECT  99.615 67.051 99.738 67.213 ;
     RECT  102.744 67.171 105.138 67.213 ;
     RECT  110.415 66.991 110.61 67.213 ;
     RECT  115.815 66.943 115.905 67.213 ;
     RECT  78.015 67.213 78.297 67.243 ;
     RECT  80.964 66.451 80.982 67.243 ;
     RECT  80.964 67.243 81.378 67.261 ;
     RECT  82.548 67.213 83.697 67.261 ;
     RECT  88.815 67.135 89.478 67.261 ;
     RECT  91.26 67.171 91.638 67.261 ;
     RECT  94.215 67.213 94.497 67.261 ;
     RECT  70.092 67.135 70.11 67.289 ;
     RECT  80.964 67.261 84.366 67.289 ;
     RECT  20.484 66.749 20.502 67.291 ;
     RECT  21.528 66.281 21.978 67.291 ;
     RECT  20.484 67.291 21.978 67.331 ;
     RECT  93.132 67.261 93.15 67.333 ;
     RECT  96.948 67.297 96.966 67.333 ;
     RECT  78.015 67.243 79.578 67.369 ;
     RECT  93.132 67.333 93.366 67.369 ;
     RECT  34.815 67.213 35.097 67.387 ;
     RECT  35.892 67.063 35.946 67.387 ;
     RECT  51.015 67.213 51.297 67.387 ;
     RECT  78.015 67.369 80.046 67.387 ;
     RECT  88.632 67.261 89.478 67.387 ;
     RECT  90.756 67.261 91.638 67.405 ;
     RECT  93.06 67.369 93.366 67.405 ;
     RECT  94.215 67.261 94.914 67.405 ;
     RECT  96.804 67.333 96.966 67.405 ;
     RECT  102.744 67.213 105.297 67.405 ;
     RECT  30.78 67.291 30.798 67.421 ;
     RECT  41.616 67.171 41.634 67.421 ;
     RECT  69.84 67.369 69.858 67.421 ;
     RECT  21.456 67.331 21.978 67.433 ;
     RECT  77.364 67.387 80.046 67.441 ;
     RECT  81.072 67.289 84.366 67.441 ;
     RECT  86.652 67.369 86.67 67.441 ;
     RECT  88.308 67.387 89.478 67.441 ;
     RECT  92.988 67.405 93.366 67.441 ;
     RECT  94.215 67.405 95.202 67.441 ;
     RECT  96.804 67.405 97.002 67.441 ;
     RECT  99.615 67.213 99.897 67.441 ;
     RECT  101.268 67.171 101.286 67.441 ;
     RECT  1.728 67.171 13.662 67.469 ;
     RECT  74.664 67.261 74.682 67.469 ;
     RECT  75.924 67.441 80.046 67.517 ;
     RECT  86.652 67.441 87.426 67.531 ;
     RECT  99.615 67.441 100.278 67.531 ;
     RECT  101.052 67.441 101.286 67.531 ;
     RECT  121.215 66.845 121.497 67.531 ;
     RECT  46.944 67.441 46.962 67.559 ;
     RECT  51.015 67.387 51.426 67.559 ;
     RECT  94.215 67.441 95.562 67.567 ;
     RECT  121.104 67.531 121.497 67.568 ;
     RECT  96.336 67.441 97.002 67.603 ;
     RECT  98.208 67.171 98.766 67.603 ;
     RECT  99.615 67.531 101.286 67.603 ;
     RECT  42.768 66.865 42.786 67.631 ;
     RECT  86.4 67.531 87.498 67.639 ;
     RECT  88.308 67.441 89.91 67.639 ;
     RECT  86.112 67.639 89.91 67.669 ;
     RECT  90.648 67.405 92.07 67.669 ;
     RECT  92.808 67.441 93.366 67.669 ;
     RECT  94.176 67.567 95.562 67.669 ;
     RECT  85.212 67.333 85.23 67.675 ;
     RECT  86.112 67.669 92.07 67.675 ;
     RECT  92.808 67.669 95.562 67.675 ;
     RECT  96.336 67.603 101.286 67.675 ;
     RECT  102.528 67.405 105.297 67.675 ;
     RECT  85.212 67.675 101.286 67.709 ;
     RECT  2.304 67.469 13.662 67.711 ;
     RECT  81.072 67.441 84.402 67.711 ;
     RECT  85.212 67.709 89.91 67.711 ;
     RECT  108.072 66.704 108.09 67.771 ;
     RECT  108.036 67.771 108.09 67.801 ;
     RECT  109.296 67.771 109.314 67.801 ;
     RECT  110.415 67.213 110.697 67.801 ;
     RECT  21.456 67.433 21.474 67.805 ;
     RECT  34.815 67.387 35.946 67.829 ;
     RECT  75.96 67.517 80.046 67.829 ;
     RECT  76.752 67.829 80.046 67.901 ;
     RECT  140.292 67.195 140.31 67.901 ;
     RECT  90.684 67.709 101.286 67.909 ;
     RECT  102.06 67.675 105.297 67.909 ;
     RECT  90.684 67.909 105.297 67.945 ;
     RECT  139.068 66.907 139.086 67.945 ;
     RECT  107.172 67.801 108.09 67.981 ;
     RECT  109.296 67.801 110.697 67.981 ;
     RECT  117.324 65.939 118.998 68.099 ;
     RECT  90.684 67.945 105.75 68.107 ;
     RECT  0.108 67.531 0.126 68.141 ;
     RECT  2.304 67.711 13.878 68.179 ;
     RECT  90.684 68.107 105.894 68.179 ;
     RECT  90.684 68.179 105.966 68.203 ;
     RECT  107.172 67.981 110.697 68.203 ;
     RECT  122.508 68.107 122.526 68.207 ;
     RECT  77.004 67.901 80.046 68.251 ;
     RECT  81.072 67.711 89.91 68.251 ;
     RECT  2.304 68.179 13.986 68.279 ;
     RECT  2.304 68.279 13.497 68.341 ;
     RECT  138.528 67.945 139.086 68.405 ;
     RECT  77.004 68.251 89.91 68.44 ;
     RECT  90.684 68.203 110.697 68.44 ;
     RECT  77.004 68.44 110.697 68.449 ;
     RECT  1.728 68.341 13.497 68.477 ;
     RECT  74.664 68.395 74.682 68.521 ;
     RECT  74.412 68.521 74.682 68.647 ;
     RECT  130.788 67.091 132.93 68.719 ;
     RECT  133.668 67.099 137.697 68.719 ;
     RECT  74.124 68.647 74.682 68.755 ;
     RECT  75.96 67.829 75.978 68.755 ;
     RECT  113.004 68.755 113.022 68.791 ;
     RECT  113.004 68.791 113.778 68.881 ;
     RECT  117.324 68.099 118.71 68.909 ;
     RECT  77.004 68.449 110.862 68.917 ;
     RECT  138.528 68.405 138.546 68.923 ;
     RECT  112.824 68.881 113.778 68.971 ;
     RECT  76.968 68.917 110.862 68.978 ;
     RECT  138.456 68.923 138.546 68.981 ;
     RECT  74.124 68.755 75.978 68.989 ;
     RECT  73.656 68.989 75.978 69.061 ;
     RECT  0.108 69.115 0.126 69.179 ;
     RECT  117.936 68.909 118.71 69.179 ;
     RECT  72.615 67.213 72.897 69.187 ;
     RECT  73.656 69.061 76.014 69.187 ;
     RECT  129.852 67.091 130.05 69.187 ;
     RECT  130.788 68.719 137.697 69.187 ;
     RECT  129.852 69.187 137.697 69.259 ;
     RECT  76.968 68.978 110.898 69.295 ;
     RECT  76.932 69.295 110.898 69.331 ;
     RECT  112.644 68.971 113.778 69.331 ;
     RECT  76.86 69.331 110.898 69.341 ;
     RECT  118.584 69.179 118.71 69.359 ;
     RECT  129.852 69.259 137.826 69.359 ;
     RECT  2.268 68.477 13.497 69.493 ;
     RECT  115.815 67.213 116.097 69.565 ;
     RECT  140.292 69.499 140.31 69.629 ;
     RECT  130.788 69.359 137.826 69.719 ;
     RECT  81.18 69.341 110.898 69.727 ;
     RECT  1.728 69.493 13.497 69.821 ;
     RECT  70.776 69.835 70.794 69.961 ;
     RECT  71.568 69.871 71.73 69.961 ;
     RECT  72.615 69.187 76.014 69.961 ;
     RECT  115.668 69.565 116.097 69.997 ;
     RECT  81.18 69.727 110.934 70.069 ;
     RECT  111.708 69.691 111.726 70.069 ;
     RECT  112.644 69.331 114.318 70.069 ;
     RECT  139.068 69.211 139.086 70.069 ;
     RECT  70.776 69.961 76.014 70.105 ;
     RECT  76.86 69.341 80.262 70.105 ;
     RECT  81.18 70.069 111.726 70.105 ;
     RECT  115.488 69.997 116.097 70.105 ;
     RECT  138.528 70.069 139.086 70.109 ;
     RECT  115.488 70.105 116.37 70.141 ;
     RECT  118.692 69.359 118.71 70.141 ;
     RECT  1.764 69.821 13.497 70.157 ;
     RECT  130.788 69.719 137.697 70.157 ;
     RECT  115.488 70.141 116.838 70.339 ;
     RECT  133.992 70.157 137.697 70.367 ;
     RECT  115.488 70.339 117.09 70.375 ;
     RECT  126.615 67.181 129.042 70.403 ;
     RECT  115.416 70.375 117.09 70.405 ;
     RECT  70.776 70.105 111.726 70.411 ;
     RECT  112.608 70.069 114.534 70.411 ;
     RECT  115.416 70.405 117.63 70.411 ;
     RECT  118.548 70.141 118.71 70.411 ;
     RECT  126.615 70.403 128.286 70.501 ;
     RECT  135.432 70.367 137.697 70.529 ;
     RECT  70.56 70.411 111.726 70.609 ;
     RECT  70.164 70.609 111.726 70.645 ;
     RECT  139.068 70.109 139.086 70.651 ;
     RECT  119.952 70.267 119.97 70.681 ;
     RECT  121.215 67.568 121.497 70.681 ;
     RECT  130.788 70.157 132.93 70.709 ;
     RECT  70.164 70.645 111.762 70.771 ;
     RECT  112.608 70.411 118.71 70.771 ;
     RECT  119.952 70.681 121.497 70.799 ;
     RECT  135.432 70.529 135.666 70.799 ;
     RECT  139.068 70.651 139.122 70.939 ;
     RECT  131.148 70.709 132.93 70.951 ;
     RECT  133.992 70.367 134.658 70.951 ;
     RECT  126.396 70.501 128.286 71.021 ;
     RECT  138.456 70.939 139.122 71.141 ;
     RECT  131.148 70.951 134.658 71.177 ;
     RECT  2.415 70.157 13.497 71.185 ;
     RECT  133.668 71.177 134.658 71.185 ;
     RECT  135.432 70.799 135.594 71.185 ;
     RECT  139.068 71.141 139.122 71.227 ;
     RECT  24.015 67.213 24.297 71.311 ;
     RECT  34.815 67.829 35.097 71.311 ;
     RECT  45.615 67.213 45.897 71.311 ;
     RECT  56.415 67.213 56.697 71.311 ;
     RECT  67.215 67.213 67.497 71.311 ;
     RECT  23.904 71.311 24.297 71.357 ;
     RECT  34.704 71.311 35.097 71.357 ;
     RECT  45.504 71.311 45.897 71.357 ;
     RECT  56.304 71.311 56.697 71.357 ;
     RECT  67.104 71.311 67.497 71.357 ;
     RECT  126.615 71.021 128.286 71.483 ;
     RECT  139.068 71.227 139.626 71.483 ;
     RECT  129.024 70.403 129.042 71.519 ;
     RECT  119.952 70.799 119.97 71.563 ;
     RECT  133.668 71.185 135.594 71.563 ;
     RECT  136.404 70.529 137.697 71.563 ;
     RECT  119.592 71.563 119.97 71.581 ;
     RECT  133.668 71.563 137.697 71.609 ;
     RECT  70.164 70.771 118.71 71.651 ;
     RECT  82.8 71.651 118.71 71.689 ;
     RECT  119.484 71.581 119.97 71.689 ;
     RECT  121.215 70.799 121.497 71.851 ;
     RECT  133.668 71.609 134.658 71.879 ;
     RECT  135.684 71.609 137.697 71.899 ;
     RECT  70.164 71.651 82.026 71.915 ;
     RECT  133.668 71.879 134.37 71.915 ;
     RECT  135.684 71.899 137.97 71.923 ;
     RECT  139.068 71.483 139.086 71.923 ;
     RECT  140.292 71.803 140.31 71.933 ;
     RECT  82.8 71.689 119.97 72.023 ;
     RECT  135.684 71.923 139.086 72.023 ;
     RECT  70.164 71.915 71.55 72.091 ;
     RECT  138.528 72.023 139.086 72.125 ;
     RECT  69.768 72.091 71.55 72.149 ;
     RECT  135.684 72.023 137.754 72.149 ;
     RECT  2.304 71.185 13.497 72.185 ;
     RECT  136.152 72.149 137.754 72.185 ;
     RECT  119.844 72.023 119.97 72.193 ;
     RECT  121.104 71.851 121.497 72.193 ;
     RECT  72.396 71.915 82.026 72.379 ;
     RECT  82.8 72.023 118.71 72.379 ;
     RECT  14.76 66.317 15.714 72.455 ;
     RECT  72.396 72.379 118.71 72.455 ;
     RECT  131.148 71.177 132.93 72.461 ;
     RECT  129.852 69.359 130.05 72.599 ;
     RECT  70.128 72.149 71.55 72.761 ;
     RECT  72.468 72.455 118.71 72.769 ;
     RECT  119.844 72.193 121.497 72.805 ;
     RECT  133.992 71.915 134.37 72.805 ;
     RECT  131.148 72.461 131.166 72.833 ;
     RECT  70.488 72.761 71.55 72.841 ;
     RECT  72.468 72.769 118.818 72.841 ;
     RECT  128.268 71.483 128.286 72.869 ;
     RECT  72.468 72.841 118.89 72.931 ;
     RECT  119.844 72.805 121.698 72.931 ;
     RECT  122.472 70.771 122.49 72.931 ;
     RECT  133.812 72.805 134.37 72.931 ;
     RECT  135.36 72.379 135.378 72.931 ;
     RECT  136.188 72.185 137.754 72.931 ;
     RECT  72.468 72.931 118.962 72.959 ;
     RECT  2.34 72.185 13.497 72.967 ;
     RECT  133.812 72.931 134.55 73.111 ;
     RECT  135.36 72.931 137.754 73.111 ;
     RECT  133.812 73.111 137.934 73.139 ;
     RECT  101.16 72.959 118.962 73.201 ;
     RECT  119.844 72.931 122.49 73.201 ;
     RECT  70.488 72.841 71.694 73.345 ;
     RECT  72.468 72.959 100.386 73.345 ;
     RECT  132.015 72.461 132.93 73.345 ;
     RECT  139.068 72.125 139.086 73.373 ;
     RECT  129.852 72.599 129.942 73.409 ;
     RECT  132.015 73.345 133.218 73.499 ;
     RECT  133.992 73.139 134.01 73.499 ;
     RECT  135.072 73.139 137.934 73.499 ;
     RECT  70.488 73.345 100.386 73.507 ;
     RECT  136.8 73.499 137.934 73.531 ;
     RECT  14.76 72.455 15.678 73.535 ;
     RECT  70.308 73.507 100.386 73.535 ;
     RECT  132.015 73.499 133.038 73.535 ;
     RECT  101.16 73.201 122.49 73.573 ;
     RECT  70.308 73.535 83.898 73.615 ;
     RECT  101.16 73.573 122.886 73.651 ;
     RECT  135.072 73.499 136.062 73.769 ;
     RECT  101.16 73.651 123.102 73.805 ;
     RECT  136.8 73.531 137.97 73.813 ;
     RECT  84.78 73.535 100.386 73.819 ;
     RECT  101.16 73.805 121.554 73.819 ;
     RECT  70.164 73.615 83.898 73.853 ;
     RECT  136.8 73.813 138.546 73.913 ;
     RECT  129.852 73.409 129.87 73.949 ;
     RECT  70.164 73.853 83.862 74.011 ;
     RECT  84.78 73.819 121.554 74.039 ;
     RECT  135.108 73.769 136.062 74.039 ;
     RECT  135.108 74.039 135.702 74.045 ;
     RECT  69.804 74.011 83.862 74.075 ;
     RECT  2.304 72.967 13.497 74.083 ;
     RECT  122.292 73.805 123.102 74.119 ;
     RECT  70.128 74.075 83.862 74.147 ;
     RECT  70.128 74.147 83.754 74.183 ;
     RECT  16.776 66.749 19.386 74.219 ;
     RECT  2.268 74.083 13.497 74.237 ;
     RECT  122.292 74.119 123.282 74.309 ;
     RECT  126.615 71.483 127.422 74.309 ;
     RECT  136.8 73.913 137.697 74.317 ;
     RECT  138.528 73.913 138.546 74.429 ;
     RECT  2.304 74.237 13.497 74.461 ;
     RECT  2.304 74.461 13.806 74.489 ;
     RECT  130.536 74.281 130.554 74.489 ;
     RECT  0.108 70.231 0.126 74.579 ;
     RECT  132.015 73.535 132.93 74.579 ;
     RECT  135.36 74.045 135.702 74.579 ;
     RECT  2.415 74.489 13.806 74.615 ;
     RECT  84.888 74.039 121.554 74.615 ;
     RECT  132.015 74.579 132.786 74.651 ;
     RECT  132.015 74.651 132.534 74.669 ;
     RECT  84.888 74.615 119.862 74.723 ;
     RECT  136.62 74.317 137.697 74.759 ;
     RECT  120.852 74.615 121.554 74.821 ;
     RECT  122.292 74.309 123.174 74.821 ;
     RECT  70.128 74.183 76.122 74.849 ;
     RECT  76.968 74.183 83.754 74.893 ;
     RECT  0.144 74.821 0.558 74.909 ;
     RECT  132.015 74.669 132.297 74.929 ;
     RECT  125.424 71.947 125.442 74.957 ;
     RECT  14.76 73.535 15.282 75.001 ;
     RECT  133.956 74.425 133.974 75.029 ;
     RECT  135.648 74.579 135.702 75.091 ;
     RECT  120.852 74.821 123.174 75.119 ;
     RECT  2.415 74.615 13.554 75.155 ;
     RECT  70.668 74.849 76.122 75.155 ;
     RECT  74.16 75.155 76.122 75.163 ;
     RECT  76.968 74.893 84.15 75.163 ;
     RECT  70.92 75.155 73.35 75.191 ;
     RECT  122.292 75.119 123.174 75.197 ;
     RECT  74.16 75.163 84.15 75.2 ;
     RECT  2.415 75.155 13.497 75.271 ;
     RECT  14.76 75.001 15.714 75.271 ;
     RECT  135.648 75.091 136.242 75.293 ;
     RECT  2.34 75.271 13.497 75.389 ;
     RECT  21.564 75.259 21.582 75.389 ;
     RECT  122.364 75.197 123.174 75.389 ;
     RECT  76.86 75.2 84.15 75.397 ;
     RECT  84.888 74.723 111.582 75.397 ;
     RECT  14.76 75.271 15.822 75.425 ;
     RECT  122.364 75.389 123.102 75.425 ;
     RECT  134.82 75.259 134.838 75.541 ;
     RECT  0.144 74.909 0.162 75.547 ;
     RECT  137.016 74.759 137.697 75.547 ;
     RECT  139.068 74.623 139.086 75.547 ;
     RECT  76.86 75.397 111.582 75.569 ;
     RECT  76.932 75.569 111.582 75.631 ;
     RECT  112.32 74.723 119.862 75.631 ;
     RECT  131.112 75.631 131.13 75.643 ;
     RECT  60.984 75.451 61.002 75.659 ;
     RECT  120.852 75.119 121.497 75.659 ;
     RECT  76.932 75.631 119.862 75.667 ;
     RECT  70.92 75.191 73.242 75.695 ;
     RECT  74.16 75.2 76.122 75.695 ;
     RECT  76.932 75.667 119.97 75.695 ;
     RECT  60.66 75.691 60.678 75.731 ;
     RECT  137.016 75.547 139.086 75.731 ;
     RECT  72.432 75.695 73.242 75.767 ;
     RECT  130.536 75.643 131.13 75.773 ;
     RECT  74.34 75.695 76.122 75.803 ;
     RECT  112.392 75.695 119.97 75.811 ;
     RECT  126.615 74.309 126.897 75.811 ;
     RECT  129.132 75.499 129.15 75.811 ;
     RECT  136.008 75.293 136.242 75.811 ;
     RECT  137.016 75.731 137.697 75.811 ;
     RECT  18.615 74.219 19.386 75.821 ;
     RECT  74.412 75.803 76.122 75.821 ;
     RECT  131.112 75.773 131.13 75.839 ;
     RECT  131.904 74.929 132.297 75.883 ;
     RECT  131.904 75.883 132.534 75.901 ;
     RECT  2.415 75.389 13.497 75.937 ;
     RECT  129.132 75.811 129.546 76.001 ;
     RECT  72.615 75.767 73.242 76.045 ;
     RECT  122.364 75.425 122.922 76.045 ;
     RECT  126.324 75.811 126.897 76.045 ;
     RECT  131.904 75.901 133.002 76.045 ;
     RECT  134.82 75.541 135.126 76.045 ;
     RECT  134.64 76.045 135.126 76.075 ;
     RECT  136.008 75.811 137.697 76.075 ;
     RECT  2.415 75.937 13.95 76.081 ;
     RECT  14.76 75.425 15.282 76.081 ;
     RECT  134.64 76.075 137.697 76.109 ;
     RECT  126.108 76.045 126.897 76.171 ;
     RECT  74.412 75.821 76.05 76.199 ;
     RECT  133.776 76.045 133.794 76.199 ;
     RECT  72.615 76.045 73.602 76.235 ;
     RECT  129.132 76.001 129.33 76.235 ;
     RECT  135.18 76.109 137.697 76.235 ;
     RECT  76.932 75.695 111.654 76.363 ;
     RECT  125.676 76.171 126.897 76.363 ;
     RECT  122.328 76.045 122.922 76.379 ;
     RECT  125.676 76.363 126.99 76.397 ;
     RECT  129.132 76.235 129.15 76.397 ;
     RECT  76.824 76.363 111.654 76.441 ;
     RECT  112.392 75.811 120.474 76.441 ;
     RECT  121.215 75.659 121.497 76.441 ;
     RECT  74.484 76.199 76.05 76.469 ;
     RECT  122.328 76.379 122.634 76.469 ;
     RECT  2.415 76.081 15.282 76.505 ;
     RECT  74.628 76.469 76.05 76.505 ;
     RECT  126.108 76.397 126.99 76.505 ;
     RECT  0.108 75.547 0.162 76.555 ;
     RECT  130.248 76.441 130.266 76.577 ;
     RECT  131.904 76.045 133.038 76.577 ;
     RECT  131.904 76.577 132.297 76.585 ;
     RECT  2.415 76.505 6.354 76.613 ;
     RECT  7.092 76.505 15.282 76.621 ;
     RECT  126.216 76.505 126.99 76.621 ;
     RECT  133.02 76.577 133.038 76.621 ;
     RECT  133.02 76.621 133.074 76.622 ;
     RECT  0.108 76.555 0.558 76.649 ;
     RECT  20.484 67.331 20.502 76.649 ;
     RECT  76.824 76.441 121.497 76.711 ;
     RECT  122.328 76.469 122.598 76.711 ;
     RECT  75.852 76.505 76.05 76.747 ;
     RECT  76.824 76.711 122.598 76.747 ;
     RECT  135.252 76.235 137.697 76.747 ;
     RECT  7.092 76.621 15.642 76.775 ;
     RECT  75.852 76.747 122.598 76.811 ;
     RECT  126.216 76.621 127.638 76.811 ;
     RECT  135.252 76.747 137.97 76.883 ;
     RECT  7.092 76.775 15.21 77.009 ;
     RECT  112.5 76.811 122.598 77.009 ;
     RECT  112.5 77.009 121.626 77.045 ;
     RECT  134.496 77.017 134.514 77.053 ;
     RECT  134.172 77.053 134.514 77.125 ;
     RECT  135.252 76.883 137.697 77.125 ;
     RECT  130.5 76.747 130.554 77.189 ;
     RECT  121.215 77.045 121.626 77.213 ;
     RECT  16.776 74.219 17.262 77.351 ;
     RECT  75.852 76.811 111.726 77.395 ;
     RECT  139.068 75.731 139.086 77.423 ;
     RECT  2.415 76.613 6.066 77.431 ;
     RECT  7.092 77.009 15.174 77.431 ;
     RECT  131.724 76.585 132.297 77.431 ;
     RECT  133.056 76.622 133.074 77.431 ;
     RECT  75.672 77.395 111.726 77.557 ;
     RECT  112.5 77.045 120.222 77.557 ;
     RECT  2.415 77.431 15.174 77.563 ;
     RECT  134.172 77.125 137.697 77.611 ;
     RECT  15.984 77.161 16.002 77.693 ;
     RECT  134.172 77.611 137.97 77.693 ;
     RECT  126.216 76.811 127.566 77.701 ;
     RECT  126.072 77.701 127.566 77.755 ;
     RECT  122.364 77.009 122.598 77.819 ;
     RECT  125.928 77.755 127.566 77.819 ;
     RECT  2.34 77.563 15.174 77.863 ;
     RECT  74.628 76.505 74.934 77.863 ;
     RECT  75.672 77.557 120.222 77.863 ;
     RECT  131.112 77.431 133.074 77.947 ;
     RECT  134.172 77.693 137.934 77.947 ;
     RECT  131.112 77.947 137.934 77.963 ;
     RECT  1.98 77.863 15.174 77.971 ;
     RECT  123.876 77.935 123.894 78.169 ;
     RECT  122.508 77.819 122.598 78.241 ;
     RECT  1.98 77.971 15.462 78.269 ;
     RECT  130.176 78.205 130.194 78.359 ;
     RECT  74.628 77.863 120.222 78.367 ;
     RECT  121.215 77.213 121.497 78.367 ;
     RECT  2.304 78.269 15.462 78.395 ;
     RECT  123.876 78.169 123.93 78.431 ;
     RECT  139.068 78.187 139.086 78.475 ;
     RECT  74.628 78.367 121.497 78.509 ;
     RECT  74.628 78.509 94.95 78.629 ;
     RECT  122.508 78.241 123.102 78.629 ;
     RECT  122.544 78.629 123.102 78.637 ;
     RECT  131.112 77.963 137.754 78.665 ;
     RECT  139.032 78.475 139.086 78.665 ;
     RECT  95.688 78.509 121.497 78.701 ;
     RECT  131.688 78.665 137.754 78.701 ;
     RECT  135.504 78.701 137.754 78.809 ;
     RECT  0.108 76.649 0.126 78.941 ;
     RECT  2.304 78.395 15.066 78.971 ;
     RECT  11.412 78.971 15.066 79.007 ;
     RECT  2.304 78.971 10.602 79.043 ;
     RECT  122.544 78.637 123.138 79.051 ;
     RECT  2.304 79.043 10.35 79.141 ;
     RECT  122.544 79.051 123.714 79.169 ;
     RECT  124.488 78.745 124.506 79.169 ;
     RECT  11.52 79.007 15.066 79.181 ;
     RECT  1.728 79.141 10.35 79.205 ;
     RECT  12.492 79.181 15.066 79.205 ;
     RECT  122.544 79.169 123.534 79.229 ;
     RECT  1.728 79.205 10.278 79.241 ;
     RECT  1.728 79.241 10.026 79.277 ;
     RECT  75.672 78.629 94.95 79.285 ;
     RECT  95.688 78.701 119.43 79.285 ;
     RECT  122.544 79.229 122.634 79.313 ;
     RECT  2.304 79.277 10.026 79.439 ;
     RECT  131.688 78.701 134.73 79.447 ;
     RECT  135.504 78.809 137.697 79.447 ;
     RECT  129.96 78.979 129.978 79.519 ;
     RECT  129.6 79.519 129.978 79.591 ;
     RECT  131.688 79.447 137.697 79.591 ;
     RECT  75.672 79.285 119.43 79.681 ;
     RECT  120.204 78.701 121.497 79.681 ;
     RECT  122.544 79.313 122.598 79.681 ;
     RECT  12.492 79.205 14.994 79.709 ;
     RECT  122.4 79.681 122.598 79.709 ;
     RECT  131.58 79.591 137.934 79.717 ;
     RECT  129.528 79.591 129.978 79.753 ;
     RECT  129.456 79.753 129.978 79.889 ;
     RECT  0.54 79.579 0.558 79.915 ;
     RECT  24.015 71.357 24.297 79.951 ;
     RECT  34.815 71.357 35.097 79.951 ;
     RECT  45.615 71.357 45.897 79.951 ;
     RECT  56.415 71.357 56.697 79.951 ;
     RECT  67.215 71.357 67.497 79.951 ;
     RECT  70.92 75.695 71.55 79.963 ;
     RECT  126.216 77.819 127.566 79.987 ;
     RECT  74.628 78.629 74.934 80.023 ;
     RECT  75.672 79.681 121.497 80.023 ;
     RECT  131.472 79.717 137.934 80.059 ;
     RECT  131.472 80.059 137.97 80.095 ;
     RECT  12.528 79.709 14.994 80.123 ;
     RECT  70.704 79.963 71.55 80.141 ;
     RECT  11.52 79.181 11.538 80.159 ;
     RECT  74.628 80.023 121.497 80.159 ;
     RECT  131.364 80.095 137.97 80.221 ;
     RECT  74.628 80.159 120.222 80.249 ;
     RECT  131.364 80.221 138.042 80.249 ;
     RECT  2.415 79.439 10.026 80.285 ;
     RECT  12.528 80.123 14.85 80.321 ;
     RECT  17.244 77.351 17.262 80.329 ;
     RECT  2.415 80.285 9.198 80.357 ;
     RECT  13.215 80.321 14.85 80.357 ;
     RECT  23.904 79.951 24.297 80.429 ;
     RECT  34.704 79.951 35.097 80.429 ;
     RECT  45.504 79.951 45.897 80.429 ;
     RECT  56.304 79.951 56.697 80.429 ;
     RECT  67.104 79.951 67.497 80.429 ;
     RECT  10.836 80.221 11.466 80.519 ;
     RECT  17.244 80.329 17.73 80.539 ;
     RECT  9.936 80.285 10.026 80.635 ;
     RECT  17.1 80.539 17.73 80.671 ;
     RECT  129.96 79.889 129.978 80.671 ;
     RECT  126.216 79.987 127.71 80.699 ;
     RECT  125.028 79.681 125.046 80.761 ;
     RECT  126.216 80.699 127.566 80.761 ;
     RECT  9.936 80.635 10.53 80.765 ;
     RECT  13.215 80.357 14.238 80.861 ;
     RECT  139.068 78.665 139.086 80.861 ;
     RECT  125.028 80.761 127.566 80.897 ;
     RECT  131.616 80.249 138.042 80.957 ;
     RECT  0.108 79.915 0.558 81.059 ;
     RECT  131.688 80.957 138.042 81.059 ;
     RECT  122.4 79.709 122.562 81.067 ;
     RECT  11.448 80.519 11.466 81.167 ;
     RECT  17.1 80.671 17.802 81.205 ;
     RECT  2.415 80.357 9.162 81.211 ;
     RECT  9.936 80.765 10.026 81.211 ;
     RECT  16.848 81.205 17.802 81.211 ;
     RECT  18.615 75.821 18.897 81.211 ;
     RECT  122.4 81.067 122.634 81.211 ;
     RECT  131.688 81.059 137.97 81.239 ;
     RECT  16.848 81.211 18.897 81.329 ;
     RECT  122.256 81.211 123.426 81.329 ;
     RECT  131.688 81.239 132.297 81.329 ;
     RECT  16.848 81.329 17.154 81.337 ;
     RECT  0.54 81.059 0.558 81.341 ;
     RECT  2.415 81.211 10.026 81.365 ;
     RECT  16.452 81.337 17.154 81.365 ;
     RECT  122.256 81.329 123.354 81.365 ;
     RECT  2.415 81.365 8.73 81.373 ;
     RECT  74.628 80.249 119.394 81.389 ;
     RECT  129.96 80.671 130.554 81.409 ;
     RECT  16.452 81.365 17.01 81.437 ;
     RECT  1.728 81.373 8.73 81.473 ;
     RECT  18.108 81.329 18.897 81.473 ;
     RECT  16.452 81.437 16.47 81.509 ;
     RECT  129.96 81.409 130.626 81.509 ;
     RECT  1.728 81.473 8.586 81.599 ;
     RECT  13.215 80.861 13.626 81.671 ;
     RECT  1.728 81.599 2.79 81.677 ;
     RECT  13.215 81.671 13.497 81.751 ;
     RECT  3.816 81.599 8.586 81.905 ;
     RECT  139.068 81.643 139.086 81.941 ;
     RECT  9.936 81.365 10.026 82.021 ;
     RECT  10.944 81.481 11.07 82.021 ;
     RECT  122.256 81.365 122.418 82.049 ;
     RECT  70.92 80.141 71.55 82.123 ;
     RECT  125.028 80.897 125.406 82.175 ;
     RECT  133.056 81.239 137.97 82.219 ;
     RECT  70.704 82.123 71.55 82.253 ;
     RECT  133.056 82.219 138.51 82.283 ;
     RECT  9.936 82.021 11.07 82.291 ;
     RECT  3.816 81.905 6.966 82.319 ;
     RECT  4.968 82.319 6.966 82.409 ;
     RECT  131.904 81.329 132.297 82.409 ;
     RECT  126.216 80.897 127.566 82.445 ;
     RECT  123.336 81.365 123.354 82.481 ;
     RECT  126.216 82.445 126.897 82.517 ;
     RECT  132.015 82.409 132.297 82.525 ;
     RECT  133.056 82.283 138.006 82.525 ;
     RECT  1.764 81.677 2.79 82.561 ;
     RECT  3.816 82.319 3.942 82.561 ;
     RECT  9.936 82.291 11.574 82.637 ;
     RECT  7.74 81.905 8.586 82.723 ;
     RECT  12.744 81.751 13.497 82.751 ;
     RECT  11.268 82.637 11.574 82.823 ;
     RECT  7.272 82.723 8.586 82.831 ;
     RECT  33.336 72.667 33.354 82.831 ;
     RECT  4.968 82.409 6.462 82.949 ;
     RECT  122.4 82.049 122.418 82.973 ;
     RECT  124.38 82.939 124.398 82.985 ;
     RECT  74.628 81.389 75.402 83.065 ;
     RECT  11.268 82.823 11.286 83.093 ;
     RECT  7.272 82.831 9.09 83.101 ;
     RECT  125.244 82.175 125.406 83.101 ;
     RECT  129.96 81.509 129.978 83.101 ;
     RECT  122.544 83.029 122.634 83.129 ;
     RECT  132.015 82.525 138.006 83.129 ;
     RECT  125.244 83.101 125.442 83.219 ;
     RECT  129.96 83.101 130.626 83.219 ;
     RECT  76.68 81.389 119.394 83.255 ;
     RECT  45.615 80.429 45.897 83.263 ;
     RECT  51.015 67.559 51.297 83.263 ;
     RECT  43.524 83.263 43.542 83.299 ;
     RECT  7.272 83.101 9.126 83.327 ;
     RECT  1.764 82.561 3.942 83.335 ;
     RECT  34.815 80.429 35.097 83.335 ;
     RECT  36.396 83.299 36.414 83.335 ;
     RECT  39.384 83.299 39.402 83.335 ;
     RECT  61.815 67.213 62.097 83.335 ;
     RECT  7.272 83.327 9.09 83.363 ;
     RECT  140.292 81.355 140.31 83.363 ;
     RECT  1.764 83.335 4.05 83.371 ;
     RECT  37.404 83.191 37.422 83.371 ;
     RECT  38.988 83.335 39.402 83.371 ;
     RECT  43.488 83.299 43.542 83.371 ;
     RECT  117.648 83.255 119.394 83.371 ;
     RECT  1.764 83.371 4.158 83.461 ;
     RECT  120.204 80.249 120.222 83.461 ;
     RECT  117.648 83.371 119.466 83.489 ;
     RECT  37.404 83.371 37.494 83.497 ;
     RECT  38.988 83.371 39.438 83.497 ;
     RECT  43.488 83.371 43.722 83.497 ;
     RECT  44.568 83.371 44.586 83.497 ;
     RECT  45.615 83.263 46.782 83.497 ;
     RECT  56.415 80.429 56.697 83.497 ;
     RECT  57.528 83.263 57.546 83.497 ;
     RECT  120.204 83.461 120.438 83.497 ;
     RECT  133.164 83.129 138.006 83.533 ;
     RECT  76.68 83.255 116.874 83.561 ;
     RECT  43.488 83.497 44.586 83.569 ;
     RECT  50.832 83.263 51.297 83.569 ;
     RECT  74.52 83.065 75.402 83.569 ;
     RECT  133.164 83.533 138.114 83.569 ;
     RECT  139.068 82.795 139.086 83.569 ;
     RECT  54.36 83.569 54.378 83.611 ;
     RECT  1.728 83.461 4.158 83.641 ;
     RECT  4.968 82.949 6.354 83.641 ;
     RECT  36.252 83.335 36.414 83.641 ;
     RECT  37.404 83.497 38.178 83.641 ;
     RECT  38.916 83.497 39.438 83.641 ;
     RECT  43.488 83.569 44.622 83.641 ;
     RECT  54.288 83.611 54.378 83.669 ;
     RECT  133.164 83.569 139.086 83.693 ;
     RECT  25.02 83.641 25.038 83.731 ;
     RECT  74.52 83.569 75.906 83.731 ;
     RECT  119.916 83.497 120.438 83.731 ;
     RECT  121.215 80.159 121.497 83.731 ;
     RECT  42.264 83.533 42.282 83.755 ;
     RECT  133.164 83.693 138.114 83.759 ;
     RECT  0.108 82.651 0.126 83.767 ;
     RECT  33.336 82.831 34.038 83.767 ;
     RECT  40.215 67.213 40.497 83.767 ;
     RECT  50.796 83.569 51.297 83.767 ;
     RECT  60.948 83.755 60.966 83.767 ;
     RECT  61.815 83.335 62.73 83.767 ;
     RECT  70.92 82.253 71.55 83.767 ;
     RECT  119.916 83.731 121.497 83.789 ;
     RECT  79.2 83.561 116.874 83.795 ;
     RECT  117.648 83.489 118.926 83.795 ;
     RECT  33.012 83.767 34.038 83.803 ;
     RECT  34.815 83.335 35.478 83.803 ;
     RECT  36.252 83.641 39.438 83.803 ;
     RECT  42.264 83.755 42.426 83.803 ;
     RECT  43.452 83.641 44.874 83.803 ;
     RECT  45.615 83.497 46.998 83.803 ;
     RECT  58.644 83.767 58.662 83.803 ;
     RECT  72.615 76.235 72.897 83.803 ;
     RECT  29.415 67.213 29.697 83.839 ;
     RECT  34.815 83.803 39.438 83.839 ;
     RECT  40.215 83.767 40.842 83.839 ;
     RECT  42.264 83.803 44.874 83.839 ;
     RECT  45.615 83.803 47.106 83.839 ;
     RECT  47.88 83.803 47.898 83.839 ;
     RECT  50.4 83.767 51.297 83.839 ;
     RECT  52.272 83.323 52.29 83.839 ;
     RECT  53.424 83.641 53.442 83.839 ;
     RECT  54.288 83.669 54.306 83.839 ;
     RECT  58.644 83.803 58.806 83.839 ;
     RECT  60.948 83.767 62.73 83.839 ;
     RECT  26.532 83.461 26.55 83.875 ;
     RECT  32.94 83.803 34.038 83.875 ;
     RECT  34.815 83.839 40.842 83.875 ;
     RECT  41.688 83.839 47.106 83.875 ;
     RECT  47.88 83.839 47.934 83.875 ;
     RECT  50.4 83.839 52.29 83.875 ;
     RECT  53.424 83.839 54.306 83.875 ;
     RECT  74.448 83.731 75.906 83.875 ;
     RECT  76.68 83.561 78.462 83.875 ;
     RECT  1.728 83.641 6.354 83.911 ;
     RECT  7.272 83.363 8.622 83.911 ;
     RECT  21.996 83.707 22.014 83.911 ;
     RECT  32.94 83.875 40.842 83.911 ;
     RECT  67.215 80.429 67.497 83.911 ;
     RECT  68.58 83.569 68.598 83.911 ;
     RECT  18.615 81.473 18.897 84.001 ;
     RECT  26.532 83.875 26.586 84.001 ;
     RECT  58.572 83.839 58.806 84.001 ;
     RECT  72.615 83.803 73.17 84.001 ;
     RECT  73.944 83.875 78.462 84.001 ;
     RECT  1.728 83.911 8.622 84.029 ;
     RECT  25.02 83.731 25.758 84.029 ;
     RECT  125.244 83.219 125.262 84.029 ;
     RECT  31.932 83.101 31.95 84.037 ;
     RECT  32.724 83.911 40.842 84.037 ;
     RECT  26.532 84.001 26.802 84.043 ;
     RECT  69.84 83.875 69.858 84.043 ;
     RECT  70.668 83.767 71.838 84.043 ;
     RECT  56.415 83.497 57.546 84.073 ;
     RECT  60.516 83.839 62.73 84.073 ;
     RECT  79.596 83.795 116.874 84.073 ;
     RECT  41.688 83.875 47.934 84.091 ;
     RECT  79.596 84.073 116.946 84.101 ;
     RECT  9.936 82.637 10.314 84.139 ;
     RECT  31.788 84.037 40.842 84.139 ;
     RECT  56.34 84.073 57.546 84.139 ;
     RECT  24.015 80.429 24.297 84.145 ;
     RECT  25.092 84.029 25.758 84.145 ;
     RECT  26.532 84.043 26.946 84.145 ;
     RECT  28.368 83.803 28.386 84.145 ;
     RECT  31.284 84.139 40.842 84.145 ;
     RECT  60.516 84.073 62.766 84.145 ;
     RECT  66.744 83.911 67.497 84.145 ;
     RECT  112.932 84.101 116.946 84.173 ;
     RECT  21.996 83.911 22.05 84.181 ;
     RECT  28.044 84.145 28.386 84.181 ;
     RECT  29.415 83.839 29.79 84.181 ;
     RECT  31.284 84.145 40.914 84.181 ;
     RECT  41.688 84.091 48.474 84.181 ;
     RECT  49.644 84.001 49.662 84.181 ;
     RECT  50.4 83.875 54.306 84.181 ;
     RECT  56.016 84.139 57.546 84.181 ;
     RECT  58.572 84.001 59.094 84.181 ;
     RECT  60.372 84.145 62.766 84.181 ;
     RECT  122.544 83.129 122.562 84.181 ;
     RECT  56.016 84.181 62.766 84.209 ;
     RECT  117.828 83.795 118.926 84.209 ;
     RECT  18.615 84.001 18.99 84.235 ;
     RECT  22.788 83.875 22.806 84.235 ;
     RECT  69.84 84.043 71.838 84.271 ;
     RECT  72.615 84.001 78.462 84.271 ;
     RECT  129.96 83.219 129.978 84.271 ;
     RECT  120.168 83.789 121.497 84.299 ;
     RECT  64.044 84.181 64.062 84.307 ;
     RECT  11.664 84.271 11.682 84.317 ;
     RECT  113.076 84.173 116.91 84.317 ;
     RECT  28.044 84.181 29.79 84.331 ;
     RECT  56.016 84.209 62.262 84.331 ;
     RECT  79.596 84.101 112.158 84.335 ;
     RECT  9.936 84.139 10.854 84.343 ;
     RECT  17.28 84.235 17.298 84.343 ;
     RECT  31.284 84.181 54.306 84.343 ;
     RECT  64.044 84.307 64.314 84.343 ;
     RECT  31.14 84.343 54.306 84.365 ;
     RECT  1.764 84.029 8.622 84.379 ;
     RECT  18.615 84.235 19.206 84.379 ;
     RECT  31.14 84.365 40.59 84.379 ;
     RECT  125.568 84.307 125.586 84.379 ;
     RECT  126.615 82.517 126.897 84.379 ;
     RECT  16.308 84.271 16.326 84.415 ;
     RECT  66.744 84.145 67.806 84.415 ;
     RECT  69.84 84.271 78.462 84.415 ;
     RECT  17.064 84.343 17.298 84.451 ;
     RECT  21.6 84.181 22.05 84.451 ;
     RECT  22.788 84.235 22.986 84.451 ;
     RECT  25.092 84.145 26.946 84.451 ;
     RECT  41.508 84.365 54.306 84.451 ;
     RECT  55.044 84.331 62.262 84.451 ;
     RECT  132.015 83.129 132.297 84.451 ;
     RECT  133.164 83.759 138.042 84.451 ;
     RECT  9.936 84.343 10.962 84.541 ;
     RECT  13.215 82.751 13.497 84.541 ;
     RECT  66.708 84.415 67.806 84.541 ;
     RECT  69.84 84.415 78.75 84.541 ;
     RECT  125.568 84.379 126.897 84.541 ;
     RECT  17.064 84.451 17.406 84.569 ;
     RECT  25.092 84.451 27.09 84.569 ;
     RECT  63 84.307 63.126 84.577 ;
     RECT  64.044 84.343 64.422 84.577 ;
     RECT  68.58 83.911 68.634 84.577 ;
     RECT  69.408 84.541 78.75 84.577 ;
     RECT  1.764 84.379 8.658 84.613 ;
     RECT  18.615 84.379 19.638 84.613 ;
     RECT  66.06 84.541 67.806 84.613 ;
     RECT  68.58 84.577 78.75 84.613 ;
     RECT  79.596 84.335 111.726 84.613 ;
     RECT  139.068 83.693 139.086 84.613 ;
     RECT  122.544 84.181 122.634 84.619 ;
     RECT  12.132 84.554 12.15 84.649 ;
     RECT  25.884 84.569 27.09 84.649 ;
     RECT  28.008 84.331 29.79 84.649 ;
     RECT  122.292 84.619 122.634 84.649 ;
     RECT  21.204 84.451 22.986 84.653 ;
     RECT  120.24 84.299 121.497 84.685 ;
     RECT  122.292 84.649 123.102 84.685 ;
     RECT  1.764 84.613 8.838 84.701 ;
     RECT  13.068 84.541 13.497 84.701 ;
     RECT  25.884 84.649 29.79 84.721 ;
     RECT  30.636 84.379 40.59 84.721 ;
     RECT  66.06 84.613 111.726 84.721 ;
     RECT  120.24 84.685 123.102 84.721 ;
     RECT  124.2 84.145 124.614 84.721 ;
     RECT  25.884 84.721 40.59 84.755 ;
     RECT  9.648 84.541 10.962 84.811 ;
     RECT  15.948 84.415 16.326 84.811 ;
     RECT  22.824 84.653 22.986 84.811 ;
     RECT  23.832 84.145 24.297 84.811 ;
     RECT  63 84.577 64.422 84.811 ;
     RECT  65.196 84.685 65.214 84.811 ;
     RECT  128.448 84.307 128.466 84.811 ;
     RECT  129.384 84.271 129.978 84.811 ;
     RECT  1.836 84.701 8.838 84.839 ;
     RECT  17.064 84.569 17.118 84.839 ;
     RECT  66.024 84.721 111.726 84.839 ;
     RECT  113.076 84.317 116.874 84.839 ;
     RECT  132.015 84.451 138.042 84.839 ;
     RECT  66.024 84.839 67.497 84.847 ;
     RECT  34.2 84.755 40.59 84.875 ;
     RECT  68.328 84.839 111.726 84.875 ;
     RECT  15.804 84.811 16.326 84.883 ;
     RECT  128.448 84.811 129.978 84.883 ;
     RECT  130.752 84.451 130.77 84.883 ;
     RECT  21.204 84.653 21.87 84.907 ;
     RECT  125.568 84.541 127.134 84.907 ;
     RECT  75.816 84.875 77.202 84.911 ;
     RECT  113.076 84.839 113.634 84.911 ;
     RECT  15.624 84.883 16.326 84.919 ;
     RECT  113.076 84.911 113.526 84.919 ;
     RECT  117.828 84.209 118.206 84.919 ;
     RECT  119.124 84.649 119.178 84.919 ;
     RECT  25.884 84.755 33.462 84.941 ;
     RECT  41.508 84.451 62.262 84.941 ;
     RECT  128.448 84.883 130.77 84.941 ;
     RECT  14.832 84.907 14.85 84.955 ;
     RECT  125.568 84.907 127.278 84.955 ;
     RECT  128.448 84.941 129.978 84.989 ;
     RECT  14.22 84.955 14.85 84.991 ;
     RECT  15.624 84.919 16.866 84.991 ;
     RECT  22.824 84.811 24.354 84.991 ;
     RECT  25.092 84.569 25.11 84.991 ;
     RECT  120.24 84.721 124.614 84.991 ;
     RECT  125.568 84.955 127.35 84.991 ;
     RECT  128.448 84.989 129.402 84.991 ;
     RECT  9.612 84.811 10.962 85.019 ;
     RECT  44.64 84.941 62.262 85.051 ;
     RECT  63 84.811 65.214 85.051 ;
     RECT  44.64 85.051 65.214 85.081 ;
     RECT  65.952 84.847 67.497 85.081 ;
     RECT  112.932 84.919 113.526 85.081 ;
     RECT  114.372 84.839 116.874 85.081 ;
     RECT  117.72 84.919 118.206 85.081 ;
     RECT  119.124 84.919 119.214 85.081 ;
     RECT  130.824 84.991 130.842 85.081 ;
     RECT  132.015 84.839 132.39 85.081 ;
     RECT  10.548 85.019 10.962 85.109 ;
     RECT  14.22 84.991 16.866 85.109 ;
     RECT  22.824 84.991 25.11 85.109 ;
     RECT  26.172 84.941 33.462 85.109 ;
     RECT  130.824 85.081 130.914 85.109 ;
     RECT  34.308 84.875 40.59 85.117 ;
     RECT  9.612 85.019 9.774 85.133 ;
     RECT  12.132 84.649 12.294 85.133 ;
     RECT  14.832 85.109 16.722 85.145 ;
     RECT  28.692 85.109 33.462 85.145 ;
     RECT  120.24 84.991 127.494 85.145 ;
     RECT  128.268 84.991 129.402 85.145 ;
     RECT  68.328 84.875 75.078 85.181 ;
     RECT  78.015 84.875 111.726 85.189 ;
     RECT  21.06 84.907 21.87 85.195 ;
     RECT  22.824 85.109 25.074 85.217 ;
     RECT  78.015 85.189 111.87 85.225 ;
     RECT  112.644 85.081 113.526 85.225 ;
     RECT  133.164 84.839 138.042 85.225 ;
     RECT  139.068 84.613 139.662 85.225 ;
     RECT  20.88 85.195 21.87 85.253 ;
     RECT  114.372 85.081 119.214 85.253 ;
     RECT  13.215 84.701 13.497 85.261 ;
     RECT  18.615 84.613 19.854 85.261 ;
     RECT  34.308 85.117 40.734 85.261 ;
     RECT  41.508 84.941 43.83 85.261 ;
     RECT  120.24 85.145 123.282 85.261 ;
     RECT  130.896 85.109 130.914 85.261 ;
     RECT  131.904 85.081 132.39 85.261 ;
     RECT  1.836 84.839 8.658 85.289 ;
     RECT  119.7 85.261 123.282 85.289 ;
     RECT  124.344 85.145 127.494 85.351 ;
     RECT  128.268 85.145 129.15 85.351 ;
     RECT  10.836 85.109 10.962 85.379 ;
     RECT  26.172 85.109 27.702 85.379 ;
     RECT  44.64 85.081 67.497 85.379 ;
     RECT  75.816 84.911 76.878 85.379 ;
     RECT  78.015 85.225 113.526 85.379 ;
     RECT  130.896 85.261 132.39 85.379 ;
     RECT  21.132 85.253 21.87 85.387 ;
     RECT  10.836 85.379 10.926 85.415 ;
     RECT  34.308 85.261 43.83 85.415 ;
     RECT  68.436 85.181 75.078 85.415 ;
     RECT  78.015 85.379 79.722 85.415 ;
     RECT  0.036 83.767 0.126 85.423 ;
     RECT  63.864 85.379 64.386 85.451 ;
     RECT  81.288 85.379 111.798 85.451 ;
     RECT  39.348 85.415 43.83 85.469 ;
     RECT  14.832 85.145 16.47 85.487 ;
     RECT  21.132 85.387 21.942 85.487 ;
     RECT  39.348 85.469 42.822 85.487 ;
     RECT  44.64 85.379 63.054 85.487 ;
     RECT  63.864 85.451 64.314 85.487 ;
     RECT  65.232 85.379 67.497 85.487 ;
     RECT  86.58 85.451 111.798 85.487 ;
     RECT  112.572 85.379 113.526 85.487 ;
     RECT  47.16 85.487 58.806 85.517 ;
     RECT  65.232 85.487 65.97 85.517 ;
     RECT  130.896 85.379 131.166 85.517 ;
     RECT  18.615 85.261 20.142 85.523 ;
     RECT  33.336 85.145 33.462 85.531 ;
     RECT  34.308 85.415 38.61 85.649 ;
     RECT  41.616 85.487 42.822 85.649 ;
     RECT  44.64 85.487 46.386 85.649 ;
     RECT  47.304 85.517 58.806 85.649 ;
     RECT  59.688 85.487 63.054 85.649 ;
     RECT  68.436 85.415 69.93 85.649 ;
     RECT  81.288 85.451 85.77 85.649 ;
     RECT  131.904 85.379 132.39 85.649 ;
     RECT  1.836 85.289 8.622 85.685 ;
     RECT  33.336 85.531 33.534 85.685 ;
     RECT  39.384 85.487 40.842 85.685 ;
     RECT  59.688 85.649 62.766 85.685 ;
     RECT  119.7 85.289 123.21 85.685 ;
     RECT  7.815 85.685 8.622 85.721 ;
     RECT  133.164 85.225 139.662 85.729 ;
     RECT  59.688 85.685 60.174 85.757 ;
     RECT  61.092 85.685 62.73 85.757 ;
     RECT  75.816 85.379 76.374 85.757 ;
     RECT  9.756 85.133 9.774 85.765 ;
     RECT  43.74 85.469 43.83 85.765 ;
     RECT  44.64 85.649 46.278 85.765 ;
     RECT  133.128 85.729 139.662 85.765 ;
     RECT  26.172 85.379 27.63 85.793 ;
     RECT  41.652 85.649 42.822 85.793 ;
     RECT  86.58 85.487 92.502 85.793 ;
     RECT  26.172 85.793 26.838 85.801 ;
     RECT  112.608 85.487 113.526 85.801 ;
     RECT  114.372 85.253 118.818 85.801 ;
     RECT  112.608 85.801 118.818 85.805 ;
     RECT  57.42 85.649 58.806 85.829 ;
     RECT  72 85.415 75.078 85.829 ;
     RECT  133.128 85.765 139.698 85.829 ;
     RECT  124.344 85.351 129.15 85.891 ;
     RECT  1.836 85.685 7.038 85.919 ;
     RECT  14.832 85.487 16.362 85.919 ;
     RECT  18.615 85.523 18.954 85.919 ;
     RECT  25.956 85.801 26.838 85.919 ;
     RECT  28.692 85.145 32.49 85.919 ;
     RECT  48.852 85.649 56.697 85.919 ;
     RECT  57.42 85.829 58.05 85.919 ;
     RECT  65.232 85.517 65.718 85.919 ;
     RECT  69.264 85.649 69.822 85.919 ;
     RECT  72 85.829 74.79 85.919 ;
     RECT  78.015 85.415 79.65 85.919 ;
     RECT  81.288 85.649 84.078 85.919 ;
     RECT  93.24 85.487 111.798 85.919 ;
     RECT  112.608 85.805 114.39 85.919 ;
     RECT  115.2 85.805 118.818 85.919 ;
     RECT  119.7 85.685 123.174 85.919 ;
     RECT  124.344 85.891 129.366 85.919 ;
     RECT  131.976 85.649 132.39 85.919 ;
     RECT  41.724 85.793 42.822 85.955 ;
     RECT  61.092 85.757 62.658 85.955 ;
     RECT  86.58 85.793 92.358 85.955 ;
     RECT  133.236 85.829 139.698 85.955 ;
     RECT  7.815 85.721 8.37 85.991 ;
     RECT  30.492 85.919 32.49 85.991 ;
     RECT  48.852 85.919 51.75 85.991 ;
     RECT  58.788 85.829 58.806 85.991 ;
     RECT  61.092 85.955 62.55 85.991 ;
     RECT  93.24 85.919 100.998 85.991 ;
     RECT  129.348 85.919 129.366 85.991 ;
     RECT  134.388 85.955 139.698 85.997 ;
     RECT  34.308 85.649 35.622 85.999 ;
     RECT  78.015 85.919 78.75 86.027 ;
     RECT  84.924 85.649 85.77 86.027 ;
     RECT  1.836 85.919 5.922 86.035 ;
     RECT  9.756 85.765 9.846 86.035 ;
     RECT  10.836 85.415 10.854 86.035 ;
     RECT  21.132 85.487 21.762 86.035 ;
     RECT  130.896 85.517 131.13 86.035 ;
     RECT  1.728 86.035 5.922 86.045 ;
     RECT  28.692 85.919 29.697 86.045 ;
     RECT  33.984 85.999 35.622 86.045 ;
     RECT  36.972 85.649 38.61 86.063 ;
     RECT  41.832 85.955 42.822 86.063 ;
     RECT  81.288 85.919 83.862 86.063 ;
     RECT  86.58 85.955 89.406 86.063 ;
     RECT  93.24 85.991 100.926 86.063 ;
     RECT  123.156 85.919 123.174 86.063 ;
     RECT  22.824 85.217 23.166 86.071 ;
     RECT  24.015 85.217 24.354 86.071 ;
     RECT  132.012 85.919 132.39 86.071 ;
     RECT  52.632 85.919 56.697 86.099 ;
     RECT  102.096 85.919 111.798 86.099 ;
     RECT  1.728 86.045 2.697 86.147 ;
     RECT  18.615 85.919 18.897 86.147 ;
     RECT  28.728 86.045 29.697 86.147 ;
     RECT  53.64 86.099 56.697 86.147 ;
     RECT  66.744 85.487 67.497 86.147 ;
     RECT  12.204 85.133 12.294 86.161 ;
     RECT  18.615 86.147 18.846 86.161 ;
     RECT  3.42 86.045 5.922 86.189 ;
     RECT  6.84 85.919 7.038 86.189 ;
     RECT  9.108 86.035 9.846 86.189 ;
     RECT  10.656 86.035 10.854 86.189 ;
     RECT  14.832 85.919 14.85 86.189 ;
     RECT  15.624 85.919 16.362 86.189 ;
     RECT  20.124 85.523 20.142 86.189 ;
     RECT  20.916 86.035 21.762 86.189 ;
     RECT  22.536 86.071 24.354 86.189 ;
     RECT  26.208 85.919 26.802 86.189 ;
     RECT  31.464 85.991 32.49 86.189 ;
     RECT  34.272 86.045 35.622 86.189 ;
     RECT  36.972 86.063 37.242 86.189 ;
     RECT  37.98 86.063 38.61 86.189 ;
     RECT  41.832 86.063 42.498 86.189 ;
     RECT  43.74 85.765 46.278 86.189 ;
     RECT  47.304 85.649 47.754 86.189 ;
     RECT  52.632 86.099 52.83 86.189 ;
     RECT  57.42 85.919 57.762 86.189 ;
     RECT  61.092 85.991 62.154 86.189 ;
     RECT  64.296 85.487 64.314 86.189 ;
     RECT  65.304 85.919 65.718 86.189 ;
     RECT  66.744 86.147 67.305 86.189 ;
     RECT  68.436 85.649 68.526 86.189 ;
     RECT  69.264 85.919 69.57 86.189 ;
     RECT  70.812 85.415 71.19 86.189 ;
     RECT  72 85.919 73.422 86.189 ;
     RECT  74.232 85.919 74.79 86.189 ;
     RECT  75.852 85.757 76.374 86.189 ;
     RECT  79.56 85.919 79.65 86.189 ;
     RECT  81.36 86.063 83.862 86.189 ;
     RECT  85.212 86.027 85.77 86.189 ;
     RECT  86.58 86.063 86.814 86.189 ;
     RECT  87.552 86.063 89.406 86.189 ;
     RECT  93.24 86.063 96.174 86.189 ;
     RECT  96.984 86.063 100.926 86.189 ;
     RECT  102.168 86.099 111.798 86.189 ;
     RECT  112.608 85.919 112.914 86.189 ;
     RECT  130.536 86.035 131.13 86.189 ;
     RECT  9.468 86.189 9.702 86.225 ;
     RECT  15.732 86.189 16.254 86.225 ;
     RECT  22.536 86.189 24.138 86.225 ;
     RECT  31.464 86.189 31.95 86.225 ;
     RECT  34.74 86.189 35.622 86.225 ;
     RECT  37.98 86.189 38.502 86.225 ;
     RECT  44.532 86.189 46.17 86.225 ;
     RECT  47.304 86.189 47.61 86.225 ;
     RECT  48.852 85.991 51.606 86.225 ;
     RECT  53.64 86.147 56.646 86.225 ;
     RECT  70.812 86.189 71.046 86.225 ;
     RECT  75.852 86.189 76.302 86.225 ;
     RECT  93.24 86.189 95.85 86.225 ;
     RECT  96.984 86.189 99.774 86.225 ;
     RECT  104.58 86.189 105.462 86.225 ;
     RECT  115.2 85.919 116.946 86.225 ;
     RECT  120.384 85.919 121.914 86.225 ;
     RECT  124.344 85.919 124.902 86.225 ;
     RECT  125.676 85.919 128.286 86.225 ;
     RECT  132.012 86.071 132.462 86.225 ;
     RECT  133.236 85.955 133.65 86.225 ;
     RECT  134.388 85.997 137.898 86.225 ;
     RECT  12.06 86.161 12.294 86.261 ;
     RECT  18.54 86.161 18.846 86.261 ;
     RECT  28.728 86.147 29.505 86.261 ;
     RECT  37.98 86.225 37.998 86.261 ;
     RECT  54.72 86.225 56.646 86.261 ;
     RECT  59.688 85.757 60.138 86.261 ;
     RECT  90.432 85.955 92.358 86.261 ;
     RECT  93.24 86.225 95.67 86.261 ;
     RECT  96.984 86.225 97.146 86.261 ;
     RECT  106.2 86.189 111.798 86.261 ;
     RECT  130.752 86.189 131.13 86.261 ;
     RECT  136.368 86.225 136.53 86.261 ;
     RECT  72 86.189 73.206 86.269 ;
     RECT  86.256 86.233 86.274 86.285 ;
     RECT  137.304 86.225 137.898 86.297 ;
     RECT  139.068 85.997 139.698 86.297 ;
     RECT  1.728 86.147 2.682 86.305 ;
     RECT  12.096 86.261 12.294 86.305 ;
     RECT  13.215 85.261 13.554 86.305 ;
     RECT  22.536 86.225 22.554 86.305 ;
     RECT  39.888 85.685 40.842 86.305 ;
     RECT  43.74 86.189 43.758 86.305 ;
     RECT  54.72 86.261 55.17 86.333 ;
     RECT  60.12 86.261 60.138 86.333 ;
     RECT  71.892 86.269 73.206 86.333 ;
     RECT  74.556 86.189 74.79 86.333 ;
     RECT  82.188 86.189 82.602 86.333 ;
     RECT  98.28 86.225 99.774 86.333 ;
     RECT  108.72 86.261 111.798 86.333 ;
     RECT  134.388 86.225 135.63 86.333 ;
     RECT  4.248 86.189 4.662 86.369 ;
     RECT  44.532 86.225 46.062 86.369 ;
     RECT  50.976 86.225 51.57 86.369 ;
     RECT  78.015 86.027 78.678 86.369 ;
     RECT  81.36 86.189 81.45 86.369 ;
     RECT  83.415 86.189 83.754 86.369 ;
     RECT  98.28 86.333 99.705 86.369 ;
     RECT  103.284 86.189 103.518 86.369 ;
     RECT  108.72 86.333 109.458 86.369 ;
     RECT  110.196 86.333 111.798 86.369 ;
     RECT  132.015 86.225 132.354 86.369 ;
     RECT  134.82 86.333 135.63 86.369 ;
     RECT  136.368 86.261 136.386 86.369 ;
     RECT  23.616 86.225 24.105 86.381 ;
     RECT  39.888 86.305 40.878 86.381 ;
     RECT  49.752 86.225 50.094 86.381 ;
     RECT  1.656 86.305 2.682 86.417 ;
     RECT  7.815 85.991 8.262 86.417 ;
     RECT  13.215 86.305 13.698 86.417 ;
     RECT  18.615 86.261 18.846 86.417 ;
     RECT  24.015 86.381 24.105 86.417 ;
     RECT  29.415 86.261 29.505 86.417 ;
     RECT  34.815 86.225 35.622 86.417 ;
     RECT  40.215 86.381 40.878 86.417 ;
     RECT  45.615 86.369 46.062 86.417 ;
     RECT  56.415 86.261 56.646 86.417 ;
     RECT  61.704 86.189 61.905 86.417 ;
     RECT  66.924 86.189 67.305 86.417 ;
     RECT  71.892 86.333 72.954 86.417 ;
     RECT  78.015 86.369 78.498 86.417 ;
     RECT  83.415 86.369 83.682 86.417 ;
     RECT  88.815 86.189 89.37 86.417 ;
     RECT  93.24 86.261 94.59 86.417 ;
     RECT  99.576 86.369 99.705 86.417 ;
     RECT  105.015 86.225 105.462 86.417 ;
     RECT  115.2 86.225 116.838 86.417 ;
     RECT  120.384 86.225 121.842 86.417 ;
     RECT  126.615 86.225 126.99 86.417 ;
     RECT  132.015 86.369 132.246 86.417 ;
     RECT  137.415 86.297 137.898 86.417 ;
     RECT  50.076 86.381 50.094 86.459 ;
     RECT  91.728 86.261 92.358 86.459 ;
     RECT  94.356 86.417 94.59 86.459 ;
     RECT  50.976 86.369 51.534 86.495 ;
     RECT  93.24 86.417 93.582 86.495 ;
     RECT  18.828 86.417 18.846 86.525 ;
     RECT  105.444 86.417 105.462 86.525 ;
     RECT  43.56 86.305 43.758 86.531 ;
     RECT  93.24 86.495 93.51 86.531 ;
     RECT  74.664 86.333 74.79 86.567 ;
     RECT  87.552 86.189 88.038 86.567 ;
     RECT  88.92 86.417 89.37 86.567 ;
     RECT  8.244 86.417 8.262 86.621 ;
     RECT  31.464 86.225 31.482 86.621 ;
     RECT  44.532 86.369 44.55 86.621 ;
     RECT  52.632 86.189 52.65 86.621 ;
     RECT  65.7 86.189 65.718 86.621 ;
     RECT  75.852 86.225 75.87 86.621 ;
     RECT  81.36 86.369 81.378 86.621 ;
     RECT  1.656 86.417 1.854 86.639 ;
     RECT  90.432 86.261 90.558 86.639 ;
     RECT  17.46 86.305 17.478 86.656 ;
     RECT  30.492 85.991 30.654 86.656 ;
     RECT  32.76 86.305 32.778 86.656 ;
     RECT  43.56 86.531 43.578 86.656 ;
     RECT  48.852 86.225 48.87 86.656 ;
     RECT  58.824 86.269 58.842 86.656 ;
     RECT  77.148 86.197 77.166 86.656 ;
     RECT  93.24 86.531 93.366 86.656 ;
     RECT  113.94 85.919 114.39 86.656 ;
     RECT  115.2 86.417 115.218 86.656 ;
     RECT  118.044 85.919 118.314 86.656 ;
     RECT  119.16 86.035 119.502 86.656 ;
     RECT  124.344 86.225 124.794 86.656 ;
     RECT  10.836 86.189 10.854 86.669 ;
     RECT  113.94 86.656 115.218 86.669 ;
     RECT  128.268 86.225 128.286 86.669 ;
     RECT  130.752 86.261 130.77 86.669 ;
     RECT  4.248 86.369 4.302 86.684 ;
     RECT  12.096 86.305 12.366 86.684 ;
     RECT  17.316 86.656 17.478 86.684 ;
     RECT  22.32 86.305 22.554 86.684 ;
     RECT  30.384 86.656 30.654 86.684 ;
     RECT  32.76 86.656 32.994 86.684 ;
     RECT  40.824 86.417 40.878 86.684 ;
     RECT  43.416 86.656 43.578 86.684 ;
     RECT  45.828 86.417 46.062 86.684 ;
     RECT  48.636 86.656 48.87 86.684 ;
     RECT  50.976 86.495 51.282 86.684 ;
     RECT  53.64 86.225 53.874 86.684 ;
     RECT  56.484 86.417 56.646 86.684 ;
     RECT  58.824 86.656 59.094 86.684 ;
     RECT  71.892 86.417 72.162 86.684 ;
     RECT  72.936 86.417 72.954 86.684 ;
     RECT  77.148 86.656 77.454 86.684 ;
     RECT  118.044 86.656 119.502 86.684 ;
     RECT  121.644 86.417 121.842 86.684 ;
     RECT  124.272 86.656 124.794 86.684 ;
     RECT  134.82 86.369 134.91 86.684 ;
     RECT  0.036 85.423 0.162 86.717 ;
     RECT  74.7 86.567 74.79 86.729 ;
     RECT  77.364 86.684 77.454 86.729 ;
     RECT  78.444 86.417 78.498 86.729 ;
     RECT  120.384 86.417 120.726 86.729 ;
     RECT  124.272 86.684 124.398 86.729 ;
     RECT  55.152 86.333 55.17 86.765 ;
     RECT  95.328 86.261 95.67 86.765 ;
     RECT  100.836 86.189 100.926 86.765 ;
     RECT  108.72 86.369 108.882 86.765 ;
     RECT  110.196 86.369 111.474 86.765 ;
     RECT  113.94 86.669 114.606 86.765 ;
     RECT  116.532 86.417 116.838 86.765 ;
     RECT  82.368 86.333 82.602 86.801 ;
     RECT  106.2 86.261 107.586 86.801 ;
     RECT  118.044 86.684 119.178 86.801 ;
     RECT  121.752 86.684 121.842 86.801 ;
     RECT  82.404 86.801 82.602 86.837 ;
     RECT  87.804 86.567 88.038 86.837 ;
     RECT  107.208 86.801 107.586 86.837 ;
     RECT  139.644 86.297 139.698 86.861 ;
     RECT  88.92 86.567 88.974 86.873 ;
     RECT  93.024 86.656 93.366 86.873 ;
     RECT  1.656 86.639 1.782 87.053 ;
     RECT  88.956 86.873 88.974 87.101 ;
     RECT  137.448 86.417 137.898 87.149 ;
     RECT  5.904 86.189 5.922 87.197 ;
     RECT  13.68 86.417 13.698 87.197 ;
     RECT  37.224 86.189 37.242 87.197 ;
     RECT  63.576 86.269 63.594 87.197 ;
     RECT  68.508 86.189 68.526 87.197 ;
     RECT  91.728 86.459 91.746 87.197 ;
     RECT  99.576 86.417 99.594 87.197 ;
     RECT  102.456 86.189 102.474 87.197 ;
     RECT  110.196 86.765 110.214 87.197 ;
     RECT  112.644 86.189 112.662 87.197 ;
     RECT  118.044 86.801 118.062 87.197 ;
     RECT  120.708 86.729 120.726 87.197 ;
     RECT  125.676 86.225 125.694 87.197 ;
     RECT  0.036 86.717 0.126 87.245 ;
     RECT  0.108 87.245 0.126 87.389 ;
     RECT  139.68 86.861 139.698 87.437 ;
     RECT  107.568 86.837 107.586 87.773 ;
     RECT  133.632 86.225 133.65 87.773 ;
     RECT  69.552 86.189 69.57 87.787 ;
     RECT  70.596 86.269 70.614 87.787 ;
     RECT  2.664 86.417 2.682 87.821 ;
     RECT  15.732 86.225 15.75 87.821 ;
     RECT  20.988 86.189 21.006 87.821 ;
     RECT  26.208 86.189 26.226 87.821 ;
     RECT  47.124 86.305 47.142 87.821 ;
     RECT  57.528 86.189 57.546 87.821 ;
     RECT  69.552 87.787 70.614 87.821 ;
     RECT  78.444 86.729 78.462 87.821 ;
     RECT  83.664 86.417 83.682 87.821 ;
     RECT  94.356 86.459 94.374 88.445 ;
     RECT  97.128 86.261 97.146 88.445 ;
     RECT  106.2 86.801 106.218 88.501 ;
     RECT  106.092 88.501 106.218 88.529 ;
     RECT  1.656 87.053 1.674 88.541 ;
     RECT  4.248 86.684 4.266 88.541 ;
     RECT  6.876 86.189 6.894 88.541 ;
     RECT  9.468 86.225 9.486 88.541 ;
     RECT  12.096 86.684 12.114 88.541 ;
     RECT  14.688 86.305 14.706 88.541 ;
     RECT  17.316 86.684 17.334 88.541 ;
     RECT  19.908 86.305 19.926 88.541 ;
     RECT  22.536 86.684 22.554 88.541 ;
     RECT  25.164 86.035 25.182 88.541 ;
     RECT  27.756 86.305 27.774 88.541 ;
     RECT  30.384 86.684 30.402 88.541 ;
     RECT  32.976 86.684 32.994 88.541 ;
     RECT  35.604 86.417 35.622 88.541 ;
     RECT  38.196 87.787 38.214 88.541 ;
     RECT  40.824 86.684 40.842 88.541 ;
     RECT  43.416 86.684 43.434 88.541 ;
     RECT  46.044 86.684 46.062 88.541 ;
     RECT  48.636 86.684 48.654 88.541 ;
     RECT  51.264 86.684 51.282 88.541 ;
     RECT  53.856 86.684 53.874 88.541 ;
     RECT  56.484 86.684 56.502 88.541 ;
     RECT  59.076 86.684 59.094 88.541 ;
     RECT  61.704 86.417 61.722 88.541 ;
     RECT  64.332 86.269 64.35 88.541 ;
     RECT  66.924 86.417 66.942 88.541 ;
     RECT  69.552 87.821 70.218 88.541 ;
     RECT  72.144 86.684 72.162 88.541 ;
     RECT  74.772 86.729 74.79 88.541 ;
     RECT  77.364 86.729 77.382 88.541 ;
     RECT  79.992 86.305 80.01 88.541 ;
     RECT  82.584 86.837 82.602 88.541 ;
     RECT  85.212 86.189 85.23 88.541 ;
     RECT  87.804 86.837 87.822 88.541 ;
     RECT  90.432 86.639 90.45 88.541 ;
     RECT  93.024 86.873 93.042 88.541 ;
     RECT  95.652 86.765 95.67 88.541 ;
     RECT  98.28 86.369 98.298 88.541 ;
     RECT  100.872 86.765 100.89 88.541 ;
     RECT  103.5 86.369 103.518 88.541 ;
     RECT  106.092 88.529 106.11 88.541 ;
     RECT  108.72 86.765 108.738 88.541 ;
     RECT  111.312 86.765 111.33 88.541 ;
     RECT  113.94 86.765 113.958 88.541 ;
     RECT  116.532 86.765 116.55 88.541 ;
     RECT  119.16 86.801 119.178 88.541 ;
     RECT  121.752 86.801 121.77 88.541 ;
     RECT  124.38 86.729 124.398 88.541 ;
     RECT  126.972 86.417 126.99 88.541 ;
     RECT  129.6 86.035 129.618 88.541 ;
     RECT  132.228 86.417 132.246 88.541 ;
     RECT  134.82 86.684 134.838 88.541 ;
     RECT  137.448 87.149 137.466 88.541 ;
    LAYER M4 ;
     RECT  0.025 87.216 0.06 87.24 ;
     RECT  0.06 1.152 0.137 87.384 ;
     RECT  0.137 1.152 0.173 6.936 ;
     RECT  0.137 14.016 0.173 14.04 ;
     RECT  0.137 19.776 0.173 22.488 ;
     RECT  0.137 23.472 0.173 33.624 ;
     RECT  0.137 36.336 0.173 38.04 ;
     RECT  0.137 46.128 0.173 46.152 ;
     RECT  0.137 73.536 0.173 76.584 ;
     RECT  0.173 5.904 0.569 6.936 ;
     RECT  0.137 12.336 0.569 13.032 ;
     RECT  0.137 15.36 0.569 15.72 ;
     RECT  0.137 16.704 0.569 17.064 ;
     RECT  0.173 19.776 0.569 20.808 ;
     RECT  0.173 22.128 0.569 22.488 ;
     RECT  0.173 28.224 0.569 33.624 ;
     RECT  0.137 40.368 0.569 44.808 ;
     RECT  0.137 53.904 0.569 55.608 ;
     RECT  0.137 56.928 0.569 63.384 ;
     RECT  0.137 67.104 0.569 67.464 ;
     RECT  0.173 73.536 0.569 75.24 ;
     RECT  0.173 76.56 0.569 76.584 ;
     RECT  0.137 77.568 0.569 79.608 ;
     RECT  0.137 81.312 0.569 82.344 ;
     RECT  0.173 1.152 1.181 4.92 ;
     RECT  0.569 40.704 1.181 43.464 ;
     RECT  0.137 51.888 1.181 52.584 ;
     RECT  0.569 62.016 1.181 63.384 ;
     RECT  0.137 47.472 1.325 49.512 ;
     RECT  0.137 85.68 1.793 87.048 ;
     RECT  1.181 40.704 2.257 40.728 ;
     RECT  0.569 67.44 2.257 67.464 ;
     RECT  0.137 68.448 2.257 70.152 ;
     RECT  0.569 29.568 2.293 30.264 ;
     RECT  0.569 31.248 2.293 31.944 ;
     RECT  1.181 1.152 2.405 2.088 ;
     RECT  2.405 1.488 2.408 2.088 ;
     RECT  1.181 3.312 2.408 4.92 ;
     RECT  0.569 5.904 2.408 5.928 ;
     RECT  0.569 6.912 2.408 6.936 ;
     RECT  0.137 10.608 2.408 10.632 ;
     RECT  0.569 12.336 2.408 12.696 ;
     RECT  0.569 15.36 2.408 15.384 ;
     RECT  0.569 16.704 2.408 16.728 ;
     RECT  0.137 18.384 2.408 18.744 ;
     RECT  0.569 20.448 2.408 20.808 ;
     RECT  0.569 22.464 2.408 22.488 ;
     RECT  0.173 23.472 2.408 27.24 ;
     RECT  2.293 29.568 2.408 31.944 ;
     RECT  0.569 33.264 2.408 33.624 ;
     RECT  0.137 34.608 2.408 35.352 ;
     RECT  0.173 36.672 2.408 38.04 ;
     RECT  0.137 39.36 2.408 39.384 ;
     RECT  2.257 40.56 2.408 40.728 ;
     RECT  1.181 41.712 2.408 43.464 ;
     RECT  0.569 44.784 2.408 44.808 ;
     RECT  1.325 47.472 2.408 47.496 ;
     RECT  1.325 48.48 2.408 49.512 ;
     RECT  1.181 52.56 2.408 52.584 ;
     RECT  0.569 54.336 2.408 54.36 ;
     RECT  0.569 55.584 2.408 55.608 ;
     RECT  0.569 56.928 2.408 59.688 ;
     RECT  0.569 60.672 2.408 60.696 ;
     RECT  1.181 62.016 2.408 62.04 ;
     RECT  1.181 63.36 2.408 63.384 ;
     RECT  0.137 65.76 2.408 65.784 ;
     RECT  2.257 67.44 2.408 70.152 ;
     RECT  0.137 71.472 2.408 72.168 ;
     RECT  0.569 73.536 2.408 74.232 ;
     RECT  0.569 75.216 2.408 75.24 ;
     RECT  0.569 77.568 2.408 79.272 ;
     RECT  0.569 81.648 2.408 82.344 ;
     RECT  0.137 83.328 2.408 84.696 ;
     RECT  1.793 85.68 2.408 86.412 ;
     RECT  2.408 1.488 2.512 86.412 ;
     RECT  2.512 1.488 2.704 86.142 ;
     RECT  2.704 22.464 2.765 22.728 ;
     RECT  2.704 33.6 2.765 33.624 ;
     RECT  2.704 12.336 2.801 12.36 ;
     RECT  2.704 24.144 2.801 27.24 ;
     RECT  2.704 67.776 2.801 70.104 ;
     RECT  2.704 75.216 2.801 75.24 ;
     RECT  2.704 3.312 2.837 3.336 ;
     RECT  2.801 25.056 2.945 27.24 ;
     RECT  2.653 87.792 2.963 87.816 ;
     RECT  2.704 1.488 2.981 2.232 ;
     RECT  2.704 30.768 3.053 30.84 ;
     RECT  2.704 56.88 3.107 57.864 ;
     RECT  2.704 84.864 3.377 86.04 ;
     RECT  2.704 49.488 3.485 49.512 ;
     RECT  2.704 41.904 3.557 42.168 ;
     RECT  2.704 6.912 3.593 6.936 ;
     RECT  2.704 34.992 3.593 35.016 ;
     RECT  2.704 53.04 3.593 54.36 ;
     RECT  2.704 77.616 3.593 78.504 ;
     RECT  2.704 83.52 3.737 83.784 ;
     RECT  2.765 22.704 3.769 22.728 ;
     RECT  2.801 68.928 3.805 70.104 ;
     RECT  2.704 20.736 3.841 20.76 ;
     RECT  3.788 17.616 3.875 17.64 ;
     RECT  3.733 74.016 3.877 74.04 ;
     RECT  3.737 83.76 3.877 83.784 ;
     RECT  3.377 84.864 3.877 85.656 ;
     RECT  2.704 44.976 3.925 45.672 ;
     RECT  2.981 2.208 3.949 2.232 ;
     RECT  3.877 74.016 3.949 74.712 ;
     RECT  3.107 56.88 3.953 57.048 ;
     RECT  3.877 10.56 3.973 10.584 ;
     RECT  3.769 51.264 3.973 51.288 ;
     RECT  3.805 68.928 3.973 70.68 ;
     RECT  2.704 63.792 3.985 65.784 ;
     RECT  3.593 53.04 4.019 53.544 ;
     RECT  2.704 38.112 4.021 39.096 ;
     RECT  3.949 2.208 4.025 2.76 ;
     RECT  2.704 79.776 4.025 79.8 ;
     RECT  3.973 51.264 4.057 51.384 ;
     RECT  2.801 67.776 4.057 67.8 ;
     RECT  3.973 68.928 4.057 70.824 ;
     RECT  4.021 38.112 4.061 39.336 ;
     RECT  2.704 40.464 4.061 40.488 ;
     RECT  2.945 27.216 4.076 27.24 ;
     RECT  2.704 28.464 4.076 29.784 ;
     RECT  2.704 76.608 4.097 76.632 ;
     RECT  4.076 27.216 4.117 29.784 ;
     RECT  3.053 30.816 4.117 30.84 ;
     RECT  3.877 83.76 4.133 85.656 ;
     RECT  3.841 19.92 4.169 20.76 ;
     RECT  3.949 73.44 4.169 74.712 ;
     RECT  3.953 57.024 4.201 57.048 ;
     RECT  4.025 2.736 4.205 2.76 ;
     RECT  4.117 27.216 4.205 30.84 ;
     RECT  2.704 71.808 4.237 71.832 ;
     RECT  4.169 73.44 4.237 74.424 ;
     RECT  2.704 81.456 4.237 81.48 ;
     RECT  4.205 30.816 4.241 30.84 ;
     RECT  3.877 46.752 4.277 46.776 ;
     RECT  4.057 7.392 4.309 7.416 ;
     RECT  3.769 21.936 4.316 22.728 ;
     RECT  3.769 14.64 4.345 14.664 ;
     RECT  4.057 67.776 4.381 70.824 ;
     RECT  3.973 10.56 4.385 10.872 ;
     RECT  4.316 21.12 4.403 22.728 ;
     RECT  4.205 27.216 4.42 29.64 ;
     RECT  4.381 67.296 4.453 70.824 ;
     RECT  4.237 71.808 4.453 74.424 ;
     RECT  3.913 9.504 4.489 9.528 ;
     RECT  4.403 21.456 4.489 22.728 ;
     RECT  4.309 7.392 4.501 8.136 ;
     RECT  4.489 9.504 4.501 10.344 ;
     RECT  2.945 25.056 4.525 25.848 ;
     RECT  4.42 27.168 4.525 29.64 ;
     RECT  3.777 18.768 4.529 18.792 ;
     RECT  2.704 36.48 4.529 36.504 ;
     RECT  4.489 60.96 4.561 61.56 ;
     RECT  4.501 7.392 4.588 10.344 ;
     RECT  4.561 60.96 4.601 62.232 ;
     RECT  4.453 67.296 4.637 74.424 ;
     RECT  4.588 10.32 4.709 10.344 ;
     RECT  3.557 42.144 4.709 42.168 ;
     RECT  3.769 49.968 4.781 49.992 ;
     RECT  3.925 44.256 4.813 45.672 ;
     RECT  4.133 84.144 4.813 85.656 ;
     RECT  4.637 70.416 4.817 74.424 ;
     RECT  4.489 55.248 4.849 55.272 ;
     RECT  4.637 67.296 4.853 69.432 ;
     RECT  4.601 60.96 4.885 60.984 ;
     RECT  4.849 55.248 4.889 55.896 ;
     RECT  3.913 34.752 4.957 34.776 ;
     RECT  2.704 48.432 4.957 48.456 ;
     RECT  4.588 7.392 4.961 9.096 ;
     RECT  4.853 67.296 4.961 67.8 ;
     RECT  4.817 70.416 4.961 70.728 ;
     RECT  4.057 51.264 4.993 51.96 ;
     RECT  4.019 53.52 4.993 53.544 ;
     RECT  4.201 57.024 4.993 57.336 ;
     RECT  4.525 25.056 5.029 29.64 ;
     RECT  3.985 63.792 5.065 66.12 ;
     RECT  4.961 67.296 5.065 67.32 ;
     RECT  4.345 14.64 5.077 15.624 ;
     RECT  3.913 12.768 5.123 12.792 ;
     RECT  5.065 63.792 5.137 67.32 ;
     RECT  4.813 44.256 5.141 45.912 ;
     RECT  5.077 13.968 5.164 15.624 ;
     RECT  5.164 14.64 5.173 15.624 ;
     RECT  2.704 32.496 5.173 32.52 ;
     RECT  4.961 7.392 5.177 8.472 ;
     RECT  4.885 60.384 5.177 60.984 ;
     RECT  4.201 4.896 5.209 4.92 ;
     RECT  4.957 48.24 5.213 48.456 ;
     RECT  4.169 19.92 5.249 20.088 ;
     RECT  5.173 14.64 5.285 16.536 ;
     RECT  4.957 33.792 5.317 34.776 ;
     RECT  5.209 4.896 5.321 4.968 ;
     RECT  5.101 3.408 5.353 3.432 ;
     RECT  3.769 59.28 5.353 59.304 ;
     RECT  4.993 56.928 5.389 57.624 ;
     RECT  5.353 58.656 5.389 59.304 ;
     RECT  4.817 71.856 5.393 74.424 ;
     RECT  4.061 39.312 5.425 39.336 ;
     RECT  4.889 55.872 5.425 55.896 ;
     RECT  5.389 56.928 5.425 59.304 ;
     RECT  5.393 71.856 5.429 72.792 ;
     RECT  3.593 77.616 5.429 78.36 ;
     RECT  5.173 31.776 5.461 32.52 ;
     RECT  5.317 33.648 5.461 34.776 ;
     RECT  4.489 21.456 5.465 23.352 ;
     RECT  5.465 21.456 5.497 21.48 ;
     RECT  4.993 51.264 5.497 53.544 ;
     RECT  5.461 31.776 5.501 34.776 ;
     RECT  5.501 31.776 5.569 31.848 ;
     RECT  5.177 60.384 5.573 60.408 ;
     RECT  5.569 31.344 5.644 31.848 ;
     RECT  5.644 31.344 5.677 31.8 ;
     RECT  4.061 38.112 5.677 38.136 ;
     RECT  4.453 43.2 5.677 43.224 ;
     RECT  4.237 81.456 5.699 82.104 ;
     RECT  5.029 24.48 5.713 29.64 ;
     RECT  5.653 79.584 5.713 79.608 ;
     RECT  4.813 84.144 5.725 86.184 ;
     RECT  5.101 11.376 5.749 11.4 ;
     RECT  5.497 51.264 5.749 53.592 ;
     RECT  5.425 55.872 5.753 59.304 ;
     RECT  4.961 70.416 5.753 70.44 ;
     RECT  4.525 76.368 5.753 76.392 ;
     RECT  5.725 84.144 5.753 84.888 ;
     RECT  5.699 82.08 5.756 82.104 ;
     RECT  5.749 10.848 5.789 11.4 ;
     RECT  5.677 31.2 5.789 31.8 ;
     RECT  5.501 32.928 5.789 34.776 ;
     RECT  5.425 39.312 5.821 39.432 ;
     RECT  5.285 14.64 5.825 15.528 ;
     RECT  5.753 56.928 5.825 59.304 ;
     RECT  5.137 63.456 5.825 67.32 ;
     RECT  4.853 68.784 5.825 69.432 ;
     RECT  5.756 82.08 5.843 82.248 ;
     RECT  5.285 16.512 5.857 16.536 ;
     RECT  4.957 17.616 5.857 17.64 ;
     RECT  5.789 34.176 5.857 34.776 ;
     RECT  5.857 16.512 5.897 17.64 ;
     RECT  4.601 62.112 5.897 62.232 ;
     RECT  5.557 87.168 5.933 87.192 ;
     RECT  5.897 17.04 5.965 17.64 ;
     RECT  5.821 39.216 5.965 39.432 ;
     RECT  5.141 44.448 5.965 45.912 ;
     RECT  5.713 79.488 5.965 79.608 ;
     RECT  5.249 20.064 5.969 20.088 ;
     RECT  5.393 74.016 5.969 74.424 ;
     RECT  5.725 85.872 5.969 86.184 ;
     RECT  5.825 63.456 6.037 64.392 ;
     RECT  5.825 58.656 6.041 59.304 ;
     RECT  5.857 34.176 6.073 34.824 ;
     RECT  4.741 35.952 6.073 35.976 ;
     RECT  5.965 39.216 6.073 40.2 ;
     RECT  5.969 74.16 6.073 74.424 ;
     RECT  5.677 43.152 6.077 43.224 ;
     RECT  5.533 6.24 6.109 6.264 ;
     RECT  5.177 7.392 6.109 7.416 ;
     RECT  5.713 24.48 6.109 29.976 ;
     RECT  5.789 31.2 6.109 31.368 ;
     RECT  5.677 37.392 6.109 38.136 ;
     RECT  6.073 39.216 6.109 40.92 ;
     RECT  5.825 56.928 6.113 57.624 ;
     RECT  6.073 49.44 6.14 49.464 ;
     RECT  5.749 50.64 6.14 53.592 ;
     RECT  6.073 34.176 6.145 35.976 ;
     RECT  5.843 82.08 6.149 82.104 ;
     RECT  5.965 79.488 6.185 80.04 ;
     RECT  5.965 17.04 6.217 17.832 ;
     RECT  6.145 34.176 6.217 36.264 ;
     RECT  6.109 37.392 6.217 40.92 ;
     RECT  5.825 65.568 6.217 67.32 ;
     RECT  5.825 68.784 6.217 68.808 ;
     RECT  6.077 43.152 6.275 43.176 ;
     RECT  6.109 6.24 6.277 7.416 ;
     RECT  5.177 8.448 6.277 8.472 ;
     RECT  6.109 24.48 6.293 31.368 ;
     RECT  6.277 6.24 6.323 9.24 ;
     RECT  6.113 56.928 6.329 57.384 ;
     RECT  6.217 34.176 6.36 40.92 ;
     RECT  6.037 42.144 6.36 42.168 ;
     RECT  5.321 4.944 6.365 4.968 ;
     RECT  6.293 27.264 6.401 31.368 ;
     RECT  6.14 49.44 6.437 53.592 ;
     RECT  5.465 22.656 6.476 23.352 ;
     RECT  6.293 24.48 6.476 25.176 ;
     RECT  5.497 21.12 6.505 21.48 ;
     RECT  6.476 22.656 6.505 25.176 ;
     RECT  5.213 48.432 6.505 48.456 ;
     RECT  6.437 49.44 6.505 53.016 ;
     RECT  6.217 17.04 6.541 18.168 ;
     RECT  6.505 21.12 6.545 25.176 ;
     RECT  6.041 58.656 6.581 59.16 ;
     RECT  5.353 3.408 6.649 3.72 ;
     RECT  5.281 47.28 6.685 47.352 ;
     RECT  6.505 48.432 6.685 53.016 ;
     RECT  5.965 44.448 6.757 46.104 ;
     RECT  6.685 47.28 6.757 53.016 ;
     RECT  5.429 71.856 6.757 71.88 ;
     RECT  6.037 63.024 6.761 64.392 ;
     RECT  6.581 58.656 6.793 58.68 ;
     RECT  6.541 17.04 6.797 18.84 ;
     RECT  6.793 70.272 6.829 70.296 ;
     RECT  6.185 79.584 6.829 80.04 ;
     RECT  6.323 6.24 6.833 7.944 ;
     RECT  6.649 2.976 6.853 3.864 ;
     RECT  6.217 65.568 6.901 68.808 ;
     RECT  6.649 20.16 6.937 20.184 ;
     RECT  5.789 32.928 6.937 33.144 ;
     RECT  6.073 74.16 6.937 75.24 ;
     RECT  5.429 78.048 6.937 78.36 ;
     RECT  6.937 73.632 6.973 75.24 ;
     RECT  6.829 79.584 7.045 80.088 ;
     RECT  6.757 71.76 7.081 71.88 ;
     RECT  5.789 10.848 7.148 10.872 ;
     RECT  7.148 10.848 7.153 10.968 ;
     RECT  6.973 73.536 7.189 75.24 ;
     RECT  7.189 73.152 7.237 75.24 ;
     RECT  5.929 55.68 7.261 55.704 ;
     RECT  6.761 63.84 7.261 64.392 ;
     RECT  6.901 65.472 7.261 68.808 ;
     RECT  7.045 79.584 7.261 80.136 ;
     RECT  6.401 27.408 7.297 31.368 ;
     RECT  6.36 34.176 7.333 42.168 ;
     RECT  7.081 43.344 7.333 43.368 ;
     RECT  7.237 73.152 7.369 75.816 ;
     RECT  5.753 84.144 7.369 84.744 ;
     RECT  6.86 60.384 7.513 60.408 ;
     RECT  6.937 77.52 7.513 78.36 ;
     RECT  6.853 2.256 7.58 3.864 ;
     RECT  6.937 32.592 7.585 33.144 ;
     RECT  7.333 34.176 7.585 43.368 ;
     RECT  7.189 5.04 7.621 5.064 ;
     RECT  7.585 32.592 7.657 43.368 ;
     RECT  6.757 44.448 7.657 53.016 ;
     RECT  5.825 14.64 7.669 14.664 ;
     RECT  6.545 21.648 7.669 25.176 ;
     RECT  6.293 26.208 7.669 26.232 ;
     RECT  7.657 32.592 7.669 53.016 ;
     RECT  6.901 54.096 7.669 54.12 ;
     RECT  7.261 63.84 7.669 68.808 ;
     RECT  6.829 70.272 7.669 70.392 ;
     RECT  7.297 27.408 7.693 31.416 ;
     RECT  7.669 32.592 7.693 54.12 ;
     RECT  6.937 19.2 7.729 20.184 ;
     RECT  7.669 21.648 7.729 26.232 ;
     RECT  7.369 72.96 7.729 75.816 ;
     RECT  7.58 2.256 7.808 3.96 ;
     RECT  7.621 5.04 7.808 5.256 ;
     RECT  6.833 7.056 7.808 7.944 ;
     RECT  6.323 9.216 7.808 9.24 ;
     RECT  7.153 10.416 7.808 10.968 ;
     RECT  6.937 13.056 7.808 13.08 ;
     RECT  7.669 14.64 7.808 14.808 ;
     RECT  6.797 17.04 7.808 18.216 ;
     RECT  7.729 19.2 7.808 26.232 ;
     RECT  7.693 27.408 7.808 54.12 ;
     RECT  7.261 55.44 7.808 55.704 ;
     RECT  6.329 56.928 7.808 57.048 ;
     RECT  6.793 58.512 7.808 58.68 ;
     RECT  7.513 60.384 7.808 61.128 ;
     RECT  6.973 62.448 7.808 62.472 ;
     RECT  7.669 63.84 7.808 70.392 ;
     RECT  7.081 71.76 7.808 71.928 ;
     RECT  7.729 72.96 7.808 76.344 ;
     RECT  7.513 77.52 7.808 78.408 ;
     RECT  7.261 79.488 7.808 80.136 ;
     RECT  7.369 84.144 7.808 85.128 ;
     RECT  5.969 86.16 7.808 86.184 ;
     RECT  7.808 2.148 7.912 86.412 ;
     RECT  7.912 2.256 8.104 86.412 ;
     RECT  8.104 13.056 8.165 13.08 ;
     RECT  8.104 64.992 8.201 66.264 ;
     RECT  8.104 14.112 8.243 16.008 ;
     RECT  8.104 60.24 8.243 62.808 ;
     RECT  8.243 61.632 8.273 62.808 ;
     RECT  8.104 69.552 8.273 69.576 ;
     RECT  8.149 88.416 8.291 88.44 ;
     RECT  8.233 86.592 8.317 86.616 ;
     RECT  8.104 73.872 8.345 81.528 ;
     RECT  8.104 2.256 8.417 2.28 ;
     RECT  8.104 10.272 8.489 10.44 ;
     RECT  8.345 75.792 8.531 81.528 ;
     RECT  8.201 64.992 8.597 66.168 ;
     RECT  8.104 5.04 8.633 5.256 ;
     RECT  8.345 73.872 8.633 74.664 ;
     RECT  8.531 75.792 8.669 80.76 ;
     RECT  8.104 42.72 8.764 49.08 ;
     RECT  8.243 60.24 8.813 60.264 ;
     RECT  8.597 64.992 8.849 65.976 ;
     RECT  8.764 42.72 8.921 47.304 ;
     RECT  8.273 61.632 9.029 61.656 ;
     RECT  8.104 50.064 9.101 50.184 ;
     RECT  8.104 19.92 9.137 41.736 ;
     RECT  8.104 52.32 9.157 55.848 ;
     RECT  8.104 57.024 9.157 58.776 ;
     RECT  8.273 62.784 9.157 62.808 ;
     RECT  8.104 63.84 9.157 63.864 ;
     RECT  8.764 48.384 9.169 49.08 ;
     RECT  9.101 50.064 9.169 50.088 ;
     RECT  9.157 52.32 9.205 58.776 ;
     RECT  8.849 64.992 9.241 65.832 ;
     RECT  9.157 62.784 9.245 63.864 ;
     RECT  8.489 10.272 9.26 10.296 ;
     RECT  8.104 67.68 9.317 68.424 ;
     RECT  9.26 9.648 9.347 10.296 ;
     RECT  9.205 51.84 9.533 58.776 ;
     RECT  8.633 74.064 9.569 74.664 ;
     RECT  8.104 18.096 9.587 18.888 ;
     RECT  9.533 52.848 9.601 58.776 ;
     RECT  9.137 19.92 9.613 41.64 ;
     RECT  9.587 18.096 9.628 18.792 ;
     RECT  8.669 78.384 9.635 80.76 ;
     RECT  9.317 67.68 9.637 67.848 ;
     RECT  8.104 70.656 9.637 71.304 ;
     RECT  8.104 72.672 9.637 72.696 ;
     RECT  9.569 74.064 9.637 74.088 ;
     RECT  8.669 75.792 9.637 77.352 ;
     RECT  9.635 78.384 9.637 79.272 ;
     RECT  8.104 84.288 9.641 85.128 ;
     RECT  8.104 7.92 9.677 7.944 ;
     RECT  9.637 75.792 9.683 79.272 ;
     RECT  9.245 62.784 9.709 62.808 ;
     RECT  9.709 62.592 9.749 62.808 ;
     RECT  9.637 67.248 9.821 67.848 ;
     RECT  9.601 52.848 9.845 58.968 ;
     RECT  9.845 52.848 9.857 59.304 ;
     RECT  8.243 14.112 9.997 14.136 ;
     RECT  9.857 57.552 9.997 59.304 ;
     RECT  9.997 13.92 10.037 14.136 ;
     RECT  8.921 42.816 10.069 47.304 ;
     RECT  10.069 42.768 10.141 47.304 ;
     RECT  9.169 48.384 10.141 50.088 ;
     RECT  10.141 42.768 10.153 50.088 ;
     RECT  9.683 75.792 10.217 79.176 ;
     RECT  10.217 75.792 10.261 77.592 ;
     RECT  9.628 18.096 10.289 18.552 ;
     RECT  8.243 15.984 10.357 16.008 ;
     RECT  10.289 18.096 10.361 18.12 ;
     RECT  10.357 15.984 10.397 16.584 ;
     RECT  10.153 42.816 10.397 50.088 ;
     RECT  9.637 72.672 10.465 74.088 ;
     RECT  10.261 75.648 10.469 77.592 ;
     RECT  9.241 64.896 10.537 65.832 ;
     RECT  9.821 67.248 10.537 67.56 ;
     RECT  9.857 52.848 10.541 56.472 ;
     RECT  9.635 80.736 10.541 80.76 ;
     RECT  9.637 70.656 10.556 71.544 ;
     RECT  10.465 72.576 10.645 74.088 ;
     RECT  9.641 84.288 10.691 84.792 ;
     RECT  10.609 82.608 10.693 82.632 ;
     RECT  9.997 57.552 10.717 59.352 ;
     RECT  10.717 57.552 10.753 59.4 ;
     RECT  9.749 62.592 10.789 62.616 ;
     RECT  10.469 77.568 10.793 77.592 ;
     RECT  10.691 84.288 10.825 84.6 ;
     RECT  10.541 55.2 10.837 56.472 ;
     RECT  10.753 57.552 10.837 60.36 ;
     RECT  10.837 55.2 10.865 60.36 ;
     RECT  10.781 86.64 10.873 86.664 ;
     RECT  9.533 51.84 10.897 51.864 ;
     RECT  10.541 52.848 10.897 53.88 ;
     RECT  10.537 64.896 10.901 67.56 ;
     RECT  10.789 62.592 10.933 62.712 ;
     RECT  10.901 66.624 10.933 67.56 ;
     RECT  9.245 63.84 10.981 63.864 ;
     RECT  10.901 64.896 10.981 64.92 ;
     RECT  10.933 62.592 11.027 62.856 ;
     RECT  10.933 66.624 11.029 67.704 ;
     RECT  10.501 68.928 11.029 68.952 ;
     RECT  10.865 56.688 11.045 60.36 ;
     RECT  10.645 72.576 11.081 74.328 ;
     RECT  11.029 66.624 11.116 68.952 ;
     RECT  10.556 70.512 11.125 71.544 ;
     RECT  11.081 72.576 11.125 73.56 ;
     RECT  10.397 43.056 11.149 50.088 ;
     RECT  11.027 62.592 11.149 62.664 ;
     RECT  10.897 51.84 11.153 53.88 ;
     RECT  11.045 56.688 11.153 57.672 ;
     RECT  11.153 52.992 11.261 53.88 ;
     RECT  11.153 57.264 11.261 57.672 ;
     RECT  9.613 22.032 11.315 41.64 ;
     RECT  10.981 63.84 11.315 64.92 ;
     RECT  11.261 52.992 11.333 53.448 ;
     RECT  11.149 61.968 11.341 62.664 ;
     RECT  11.315 22.032 11.365 29.64 ;
     RECT  9.613 19.92 11.369 20.664 ;
     RECT  10.469 75.648 11.437 76.392 ;
     RECT  11.315 64.416 11.441 64.92 ;
     RECT  11.045 58.704 11.473 60.36 ;
     RECT  11.125 70.512 11.513 73.56 ;
     RECT  11.513 70.512 11.548 71.976 ;
     RECT  11.149 43.056 11.585 50.136 ;
     RECT  10.825 84.144 11.653 84.6 ;
     RECT  11.441 64.896 11.657 64.92 ;
     RECT  11.116 68.928 11.657 68.952 ;
     RECT  11.548 70.512 11.657 71.64 ;
     RECT  10.037 13.92 11.66 13.944 ;
     RECT  11.66 13.584 11.701 13.944 ;
     RECT  11.369 20.496 11.725 20.664 ;
     RECT  11.365 21.984 11.725 29.64 ;
     RECT  11.657 70.512 11.729 70.536 ;
     RECT  11.701 13.584 11.747 14.232 ;
     RECT  11.116 66.624 11.747 67.704 ;
     RECT  11.585 43.056 11.765 49.56 ;
     RECT  10.865 55.2 11.765 55.224 ;
     RECT  11.437 75.648 11.833 76.632 ;
     RECT  11.315 30.72 11.869 41.64 ;
     RECT  10.397 16.56 11.873 16.584 ;
     RECT  11.333 53.04 11.917 53.448 ;
     RECT  10.217 78.672 11.941 79.176 ;
     RECT  11.513 73.392 11.981 73.56 ;
     RECT  11.725 20.496 11.987 29.64 ;
     RECT  11.981 73.536 12.035 73.56 ;
     RECT  11.765 43.056 12.053 44.472 ;
     RECT  11.917 53.424 12.053 53.448 ;
     RECT  11.657 71.52 12.053 71.64 ;
     RECT  11.833 74.544 12.076 76.632 ;
     RECT  11.941 78.624 12.089 79.176 ;
     RECT  11.653 84.144 12.121 84.648 ;
     RECT  11.869 30.72 12.157 41.976 ;
     RECT  12.053 43.056 12.157 43.896 ;
     RECT  11.987 20.496 12.197 20.52 ;
     RECT  11.905 50.64 12.197 50.664 ;
     RECT  11.341 61.968 12.233 61.992 ;
     RECT  12.089 78.672 12.233 79.176 ;
     RECT  12.337 55.872 12.437 55.896 ;
     RECT  11.473 58.704 12.445 60.696 ;
     RECT  9.347 10.272 12.553 10.296 ;
     RECT  11.987 21.936 12.589 29.64 ;
     RECT  12.157 30.72 12.589 43.896 ;
     RECT  12.013 63.264 12.697 63.288 ;
     RECT  12.049 54.864 12.757 54.888 ;
     RECT  12.437 55.872 12.757 56.424 ;
     RECT  12.076 74.976 12.812 76.632 ;
     RECT  12.553 10.272 13.093 10.824 ;
     RECT  8.633 5.232 13.208 5.256 ;
     RECT  13.093 10.176 13.208 10.824 ;
     RECT  11.747 14.208 13.208 14.232 ;
     RECT  12.085 18.768 13.208 18.792 ;
     RECT  12.589 21.936 13.208 43.896 ;
     RECT  11.765 45.696 13.208 49.56 ;
     RECT  11.153 51.936 13.208 51.96 ;
     RECT  12.757 54.864 13.208 56.424 ;
     RECT  11.261 57.648 13.208 57.672 ;
     RECT  12.445 58.656 13.208 60.696 ;
     RECT  12.697 62.736 13.208 63.288 ;
     RECT  11.747 67.536 13.208 67.704 ;
     RECT  12.053 71.616 13.208 71.64 ;
     RECT  12.985 73.776 13.208 73.8 ;
     RECT  12.812 74.976 13.208 77.544 ;
     RECT  12.233 78.672 13.208 79.032 ;
     RECT  12.121 84.144 13.208 85.128 ;
     RECT  13.208 2.148 13.312 86.412 ;
     RECT  13.312 2.418 13.504 86.142 ;
     RECT  13.504 13.584 13.565 14.232 ;
     RECT  13.504 58.656 13.565 58.968 ;
     RECT  13.504 60.336 13.637 60.36 ;
     RECT  13.504 54.864 13.673 55.848 ;
     RECT  13.504 17.328 13.709 18.792 ;
     RECT  13.504 25.92 13.709 48.456 ;
     RECT  13.673 55.776 13.709 55.848 ;
     RECT  13.381 87.168 13.709 87.192 ;
     RECT  13.504 78.048 13.745 80.568 ;
     RECT  13.504 10.176 14.033 10.2 ;
     RECT  13.745 79.728 14.099 80.568 ;
     RECT  13.709 41.904 14.177 48.456 ;
     RECT  13.709 25.92 14.284 40.92 ;
     RECT  13.709 17.328 14.357 18.216 ;
     RECT  13.504 49.536 14.497 49.608 ;
     RECT  13.504 20.88 14.573 20.904 ;
     RECT  13.745 78.048 14.645 78.072 ;
     RECT  14.497 49.296 14.749 49.608 ;
     RECT  14.099 80.304 14.861 80.568 ;
     RECT  13.504 21.888 14.965 24.936 ;
     RECT  13.504 75.648 15.001 76.488 ;
     RECT  15.001 75.216 15.107 76.488 ;
     RECT  14.749 49.296 15.109 49.8 ;
     RECT  15.107 75.648 15.148 76.488 ;
     RECT  14.965 21.504 15.401 24.936 ;
     RECT  15.401 24.912 15.433 24.936 ;
     RECT  14.284 26.112 15.433 40.92 ;
     RECT  15.433 24.912 15.473 40.92 ;
     RECT  15.181 52.176 15.613 52.2 ;
     RECT  14.357 17.328 15.637 18.168 ;
     RECT  14.177 41.904 15.649 47.976 ;
     RECT  15.109 49.296 15.649 49.896 ;
     RECT  15.613 51.888 15.697 52.2 ;
     RECT  13.709 55.824 15.721 55.848 ;
     RECT  15.721 55.824 15.757 56.088 ;
     RECT  13.504 84.288 15.757 85.128 ;
     RECT  15.637 17.328 15.829 18.744 ;
     RECT  15.829 16.8 15.865 18.744 ;
     RECT  15.757 55.152 15.901 56.088 ;
     RECT  15.829 53.568 15.913 53.592 ;
     RECT  15.401 21.504 15.925 23.88 ;
     RECT  15.577 61.152 15.973 61.176 ;
     RECT  15.721 87.792 16.019 87.816 ;
     RECT  15.925 21.456 16.357 23.88 ;
     RECT  15.865 16.8 16.553 19.704 ;
     RECT  16.297 59.52 16.729 59.544 ;
     RECT  15.973 60.912 16.796 61.176 ;
     RECT  14.861 80.544 16.837 80.568 ;
     RECT  16.553 18.72 16.985 19.704 ;
     RECT  16.357 20.976 16.988 23.88 ;
     RECT  15.473 25.824 17.017 40.92 ;
     RECT  15.649 41.904 17.017 49.896 ;
     RECT  13.504 71.616 17.089 71.64 ;
     RECT  13.565 13.584 17.129 13.608 ;
     RECT  17.089 71.28 17.129 71.64 ;
     RECT  16.837 80.544 17.129 81.24 ;
     RECT  17.129 71.28 17.173 71.304 ;
     RECT  16.988 20.304 17.201 23.88 ;
     RECT  15.757 84.288 17.228 85.224 ;
     RECT  17.129 80.64 17.315 81.24 ;
     RECT  17.228 84.24 17.315 85.224 ;
     RECT  17.201 20.304 17.417 21.48 ;
     RECT  15.901 55.152 17.557 56.376 ;
     RECT  17.557 54.864 17.593 56.376 ;
     RECT  17.509 10.32 17.596 10.344 ;
     RECT  13.504 67.008 17.605 67.704 ;
     RECT  16.729 59.088 17.665 59.544 ;
     RECT  16.796 60.912 17.665 61.272 ;
     RECT  17.665 59.088 17.701 61.272 ;
     RECT  17.017 25.824 17.809 49.896 ;
     RECT  17.593 54.864 17.845 56.568 ;
     RECT  15.865 57.696 17.845 57.72 ;
     RECT  17.201 22.464 17.893 23.88 ;
     RECT  17.809 25.056 17.893 49.896 ;
     RECT  13.504 5.232 17.941 5.256 ;
     RECT  17.941 7.2 17.953 7.224 ;
     RECT  17.417 20.304 17.953 20.328 ;
     RECT  17.941 5.232 17.989 5.736 ;
     RECT  17.953 6.864 17.989 7.224 ;
     RECT  15.697 52.176 18.061 52.2 ;
     RECT  17.893 22.464 18.097 49.896 ;
     RECT  18.061 52.176 18.097 52.824 ;
     RECT  17.845 54.864 18.097 57.72 ;
     RECT  16.985 18.72 18.133 18.744 ;
     RECT  17.417 21.456 18.188 21.48 ;
     RECT  18.097 22.464 18.188 50.76 ;
     RECT  18.097 54.72 18.241 57.72 ;
     RECT  17.701 59.088 18.241 61.704 ;
     RECT  16.837 65.232 18.325 65.256 ;
     RECT  17.605 66.48 18.325 67.704 ;
     RECT  17.953 20.16 18.529 20.328 ;
     RECT  17.989 5.232 18.608 7.224 ;
     RECT  13.504 8.976 18.608 9 ;
     RECT  16.553 16.8 18.608 17.352 ;
     RECT  18.133 18.48 18.608 18.744 ;
     RECT  18.529 20.064 18.608 20.328 ;
     RECT  18.188 21.456 18.608 50.76 ;
     RECT  18.097 52.176 18.608 53.064 ;
     RECT  18.241 54.72 18.608 61.704 ;
     RECT  18.325 65.232 18.608 67.704 ;
     RECT  13.504 73.776 18.608 73.8 ;
     RECT  15.148 75.648 18.608 75.672 ;
     RECT  17.315 80.832 18.608 80.856 ;
     RECT  17.315 84.288 18.608 85.224 ;
     RECT  18.469 86.496 18.608 86.52 ;
     RECT  18.469 88.416 18.659 88.44 ;
     RECT  18.608 2.148 18.712 86.52 ;
     RECT  18.712 2.418 18.857 86.52 ;
     RECT  18.857 2.418 18.904 86.142 ;
     RECT  18.904 25.008 19.427 51.144 ;
     RECT  18.904 20.064 19.433 23.64 ;
     RECT  18.904 73.776 19.763 73.8 ;
     RECT  18.904 52.176 19.811 53.064 ;
     RECT  18.904 54.864 19.933 62.664 ;
     RECT  19.433 20.304 19.957 23.64 ;
     RECT  19.811 52.464 20.017 53.064 ;
     RECT  19.933 54.864 20.041 63.528 ;
     RECT  18.904 65.232 20.053 68.52 ;
     RECT  20.041 54.72 20.149 63.528 ;
     RECT  20.149 54.528 20.257 63.528 ;
     RECT  20.053 65.088 20.293 68.52 ;
     RECT  19.427 25.2 20.473 51.144 ;
     RECT  20.473 25.104 20.485 51.144 ;
     RECT  19.909 71.328 20.485 71.352 ;
     RECT  20.257 54.528 20.797 63.624 ;
     RECT  18.904 75.648 20.821 75.816 ;
     RECT  20.017 52.56 20.869 53.064 ;
     RECT  20.797 54.384 20.869 63.624 ;
     RECT  20.485 25.008 20.965 51.144 ;
     RECT  20.293 65.04 20.965 68.52 ;
     RECT  19.957 20.304 21.013 23.688 ;
     RECT  20.965 24.816 21.013 51.144 ;
     RECT  18.904 80.4 21.061 80.856 ;
     RECT  20.977 87.792 21.251 87.816 ;
     RECT  21.013 20.304 21.301 51.144 ;
     RECT  18.904 16.8 21.349 18.744 ;
     RECT  20.821 75.36 21.349 75.816 ;
     RECT  18.904 84.24 21.349 85.224 ;
     RECT  21.397 14.496 21.445 14.52 ;
     RECT  20.485 70.944 21.541 71.352 ;
     RECT  20.869 52.56 21.589 63.624 ;
     RECT  21.301 20.304 21.661 51.432 ;
     RECT  21.589 52.56 21.661 63.72 ;
     RECT  21.349 83.712 21.661 85.224 ;
     RECT  18.904 7.344 21.877 7.368 ;
     RECT  20.965 65.04 22.069 68.664 ;
     RECT  22.069 64.992 22.165 68.664 ;
     RECT  21.661 83.712 22.211 85.416 ;
     RECT  21.661 20.304 22.237 63.72 ;
     RECT  22.237 20.304 22.536 63.816 ;
     RECT  22.165 64.992 22.536 69.288 ;
     RECT  22.211 84.24 22.997 85.416 ;
     RECT  22.997 84.288 23.564 85.416 ;
     RECT  23.605 88.416 23.891 88.44 ;
     RECT  21.877 7.104 24.008 7.368 ;
     RECT  21.493 9.36 24.008 9.384 ;
     RECT  21.925 11.664 24.008 11.688 ;
     RECT  21.445 13.536 24.008 14.52 ;
     RECT  21.349 16.8 24.008 19.08 ;
     RECT  22.536 20.304 24.008 69.288 ;
     RECT  21.541 70.368 24.008 71.352 ;
     RECT  21.013 72.672 24.008 72.696 ;
     RECT  21.349 75.264 24.008 75.816 ;
     RECT  20.437 78.096 24.008 78.12 ;
     RECT  21.061 79.488 24.008 80.856 ;
     RECT  23.564 84.288 24.008 86.376 ;
     RECT  24.008 2.148 24.112 86.412 ;
     RECT  24.112 2.418 24.304 86.142 ;
     RECT  24.304 84.288 25.549 85.416 ;
     RECT  24.304 16.8 26.237 19.08 ;
     RECT  26.197 87.792 26.483 87.816 ;
     RECT  24.304 7.104 26.669 7.368 ;
     RECT  25.549 84.048 26.957 85.416 ;
     RECT  24.304 13.536 27.461 14.52 ;
     RECT  24.304 20.304 27.641 69.288 ;
     RECT  24.304 9.36 28.433 9.384 ;
     RECT  26.957 84.24 28.652 85.416 ;
     RECT  28.693 88.416 29.075 88.44 ;
     RECT  26.669 7.104 29.408 7.128 ;
     RECT  24.304 11.664 29.408 11.688 ;
     RECT  27.461 13.536 29.408 13.56 ;
     RECT  26.237 16.8 29.408 18.744 ;
     RECT  27.641 20.832 29.408 69.288 ;
     RECT  24.304 70.368 29.408 71.352 ;
     RECT  24.304 72.672 29.408 72.696 ;
     RECT  24.304 75.264 29.408 75.816 ;
     RECT  24.304 78.096 29.408 78.12 ;
     RECT  24.304 79.488 29.408 80.856 ;
     RECT  28.652 84.24 29.408 86.04 ;
     RECT  29.408 2.148 29.512 86.412 ;
     RECT  29.512 2.418 29.704 86.142 ;
     RECT  29.704 84.288 31.273 85.464 ;
     RECT  31.453 86.592 31.537 86.616 ;
     RECT  31.477 88.416 31.715 88.44 ;
     RECT  29.704 7.104 31.853 7.128 ;
     RECT  29.704 72.672 33.365 72.696 ;
     RECT  31.273 84.144 33.973 85.464 ;
     RECT  33.973 84.144 34.189 86.04 ;
     RECT  29.704 11.664 34.808 11.688 ;
     RECT  29.704 13.536 34.808 13.56 ;
     RECT  29.704 16.8 34.808 18.744 ;
     RECT  29.704 20.832 34.808 69.288 ;
     RECT  29.704 70.368 34.808 71.352 ;
     RECT  29.704 75.264 34.808 75.816 ;
     RECT  29.704 78.096 34.808 78.12 ;
     RECT  29.704 79.488 34.808 80.856 ;
     RECT  34.189 84.096 34.808 86.04 ;
     RECT  34.808 2.148 34.912 86.412 ;
     RECT  34.912 2.418 35.104 86.142 ;
     RECT  35.104 20.832 35.363 69.288 ;
     RECT  35.104 83.808 36.065 85.464 ;
     RECT  36.901 87.168 37.253 87.192 ;
     RECT  36.065 84.048 37.82 85.464 ;
     RECT  37.82 84.048 37.907 86.04 ;
     RECT  37.907 84.048 38.053 85.464 ;
     RECT  37.861 87.792 38.225 87.816 ;
     RECT  38.053 83.856 38.869 85.464 ;
     RECT  38.869 83.808 39.829 85.464 ;
     RECT  39.493 88.416 39.875 88.44 ;
     RECT  35.104 13.536 40.208 13.56 ;
     RECT  35.104 16.8 40.208 18.744 ;
     RECT  35.363 20.832 40.208 67.176 ;
     RECT  35.363 68.16 40.208 69.288 ;
     RECT  35.104 70.368 40.208 71.352 ;
     RECT  35.104 75.264 40.208 75.816 ;
     RECT  35.104 78.096 40.208 78.12 ;
     RECT  35.104 79.488 40.208 80.856 ;
     RECT  39.829 83.808 40.208 86.376 ;
     RECT  40.208 2.148 40.312 86.412 ;
     RECT  40.312 2.418 40.504 86.142 ;
     RECT  40.504 83.808 40.745 85.464 ;
     RECT  40.504 20.832 41.605 67.176 ;
     RECT  40.504 68.16 41.605 69.288 ;
     RECT  40.745 83.856 42.044 85.464 ;
     RECT  42.044 83.856 42.131 86.04 ;
     RECT  42.131 83.856 42.38 85.512 ;
     RECT  42.38 83.76 42.467 85.512 ;
     RECT  42.467 83.808 42.689 85.512 ;
     RECT  42.689 83.808 43.193 85.464 ;
     RECT  43.193 83.808 43.841 85.224 ;
     RECT  44.521 86.592 44.605 86.616 ;
     RECT  44.533 88.416 44.771 88.44 ;
     RECT  43.841 83.808 44.828 84.936 ;
     RECT  44.828 83.664 44.869 84.936 ;
     RECT  40.504 13.536 45.608 13.56 ;
     RECT  40.504 16.8 45.608 18.744 ;
     RECT  41.605 20.832 45.608 69.288 ;
     RECT  40.504 70.368 45.608 71.352 ;
     RECT  40.504 75.264 45.608 75.816 ;
     RECT  40.504 78.096 45.608 78.12 ;
     RECT  40.504 79.488 45.608 80.856 ;
     RECT  44.869 83.664 45.608 85.512 ;
     RECT  45.608 2.148 45.712 86.412 ;
     RECT  45.712 2.418 45.904 86.142 ;
     RECT  45.904 16.8 47.041 18.744 ;
     RECT  47.041 15.984 47.125 18.744 ;
     RECT  47.113 87.792 47.363 87.816 ;
     RECT  45.904 83.808 47.909 85.656 ;
     RECT  47.909 83.856 49.724 85.656 ;
     RECT  49.724 83.856 49.811 86.376 ;
     RECT  49.765 88.416 50.003 88.44 ;
     RECT  47.077 7.056 51.008 7.08 ;
     RECT  45.904 13.536 51.008 13.56 ;
     RECT  47.125 16.8 51.008 18.744 ;
     RECT  45.904 20.832 51.008 69.288 ;
     RECT  45.904 70.368 51.008 71.352 ;
     RECT  45.904 75.264 51.008 75.816 ;
     RECT  45.904 78.096 51.008 78.12 ;
     RECT  45.904 79.488 51.008 80.856 ;
     RECT  49.811 83.856 51.008 85.656 ;
     RECT  51.008 2.148 51.112 86.412 ;
     RECT  51.112 2.418 51.304 86.142 ;
     RECT  51.304 20.832 51.437 69.288 ;
     RECT  51.304 83.328 52.369 85.656 ;
     RECT  52.369 83.328 52.621 85.8 ;
     RECT  52.549 88.416 52.691 88.44 ;
     RECT  52.621 83.328 52.705 86.616 ;
     RECT  52.705 83.328 53.525 85.8 ;
     RECT  53.525 83.328 54.908 85.656 ;
     RECT  54.908 83.328 54.995 86.328 ;
     RECT  54.949 88.416 55.187 88.44 ;
     RECT  51.304 7.056 56.408 7.08 ;
     RECT  51.304 16.8 56.408 18.744 ;
     RECT  51.437 20.832 56.408 67.176 ;
     RECT  51.437 68.16 56.408 69.288 ;
     RECT  51.304 70.368 56.408 71.352 ;
     RECT  51.304 75.264 56.408 75.816 ;
     RECT  51.304 78.096 56.408 78.12 ;
     RECT  51.304 79.488 56.408 80.856 ;
     RECT  54.995 83.328 56.408 85.656 ;
     RECT  56.408 2.148 56.512 86.412 ;
     RECT  56.512 2.418 56.704 86.142 ;
     RECT  56.704 83.328 57.052 85.608 ;
     RECT  57.517 87.792 57.827 87.816 ;
     RECT  57.052 83.328 58.385 84.984 ;
     RECT  58.385 83.328 59.353 84.936 ;
     RECT  59.353 83.328 59.605 85.128 ;
     RECT  60.092 86.304 60.179 86.328 ;
     RECT  60.133 88.416 60.419 88.44 ;
     RECT  56.704 7.056 61.808 7.08 ;
     RECT  56.704 16.8 61.808 18.744 ;
     RECT  56.704 20.832 61.808 67.176 ;
     RECT  56.704 68.16 61.808 69.288 ;
     RECT  56.704 70.368 61.808 71.352 ;
     RECT  56.704 75.264 61.808 75.816 ;
     RECT  56.704 78.096 61.808 78.12 ;
     RECT  56.704 79.488 61.808 80.856 ;
     RECT  59.605 83.328 61.808 85.176 ;
     RECT  61.808 2.148 61.912 86.412 ;
     RECT  61.912 2.418 62.104 86.142 ;
     RECT  62.104 83.328 62.741 85.704 ;
     RECT  63.013 87.168 63.605 87.192 ;
     RECT  62.741 83.328 63.893 85.416 ;
     RECT  65.605 88.416 65.747 88.44 ;
     RECT  65.689 86.592 65.773 86.616 ;
     RECT  63.893 83.328 65.941 85.272 ;
     RECT  62.104 7.056 67.208 7.08 ;
     RECT  62.104 16.8 67.208 18.744 ;
     RECT  62.104 20.832 67.208 67.176 ;
     RECT  62.104 68.16 67.208 69.288 ;
     RECT  62.104 70.368 67.208 71.352 ;
     RECT  62.104 75.264 67.208 75.816 ;
     RECT  62.104 78.096 67.208 78.12 ;
     RECT  62.104 79.488 67.208 80.856 ;
     RECT  64.885 82.224 67.208 82.248 ;
     RECT  65.941 83.328 67.208 85.512 ;
     RECT  67.208 2.148 67.312 86.412 ;
     RECT  67.312 2.418 67.504 86.142 ;
     RECT  68.197 87.168 68.537 87.192 ;
     RECT  67.504 70.368 69.757 71.352 ;
     RECT  67.504 20.832 69.788 67.176 ;
     RECT  67.504 68.16 69.788 69.288 ;
     RECT  69.757 70.368 69.971 72.12 ;
     RECT  69.793 74.016 69.971 74.04 ;
     RECT  67.504 82.128 70.693 82.152 ;
     RECT  70.693 82.128 70.733 82.248 ;
     RECT  70.7 72.912 70.741 72.936 ;
     RECT  69.788 20.832 70.765 69.288 ;
     RECT  69.971 70.368 70.765 71.4 ;
     RECT  70.741 72.912 70.787 73.512 ;
     RECT  69.781 87.792 70.883 87.816 ;
     RECT  67.504 75.264 71.053 75.816 ;
     RECT  70.787 73.344 71.485 73.512 ;
     RECT  71.485 73.344 71.809 73.8 ;
     RECT  71.053 74.832 71.809 75.816 ;
     RECT  70.765 20.832 71.953 71.4 ;
     RECT  71.809 73.344 72.493 75.816 ;
     RECT  67.504 7.056 72.608 7.08 ;
     RECT  67.504 16.8 72.608 18.744 ;
     RECT  71.953 20.832 72.608 71.832 ;
     RECT  72.493 72.816 72.608 75.816 ;
     RECT  67.504 78.096 72.608 78.12 ;
     RECT  67.504 79.488 72.608 80.856 ;
     RECT  70.733 82.224 72.608 82.248 ;
     RECT  67.504 83.328 72.608 85.512 ;
     RECT  72.608 2.148 72.712 86.412 ;
     RECT  72.712 2.418 72.904 86.328 ;
     RECT  72.904 83.328 73.235 86.328 ;
     RECT  73.189 88.416 73.475 88.44 ;
     RECT  72.904 20.832 73.715 75.816 ;
     RECT  73.715 20.832 73.757 72.024 ;
     RECT  73.715 73.152 74.437 75.816 ;
     RECT  74.437 73.152 74.657 76.056 ;
     RECT  73.757 20.832 74.869 69.288 ;
     RECT  73.757 70.368 74.869 72.024 ;
     RECT  74.657 73.152 74.869 74.088 ;
     RECT  72.904 82.224 74.941 82.248 ;
     RECT  73.235 83.328 74.941 85.512 ;
     RECT  74.657 75.12 74.945 76.056 ;
     RECT  74.869 20.832 75.265 72.024 ;
     RECT  74.869 73.056 75.265 74.088 ;
     RECT  72.904 78.096 75.493 78.12 ;
     RECT  72.904 79.488 75.493 80.856 ;
     RECT  75.493 78.096 75.701 80.856 ;
     RECT  74.941 82.224 75.805 85.512 ;
     RECT  75.701 78.096 75.841 78.12 ;
     RECT  75.805 82.224 75.841 85.752 ;
     RECT  75.841 82.224 75.925 86.616 ;
     RECT  74.945 75.264 76.021 76.056 ;
     RECT  75.701 79.488 76.028 80.856 ;
     RECT  75.925 82.224 76.028 85.752 ;
     RECT  76.028 79.488 76.115 85.752 ;
     RECT  75.877 88.416 76.115 88.44 ;
     RECT  76.115 79.488 76.205 80.856 ;
     RECT  76.021 75.264 76.273 76.392 ;
     RECT  75.841 77.376 76.273 78.12 ;
     RECT  76.273 75.264 76.633 78.12 ;
     RECT  76.205 80.352 76.745 80.856 ;
     RECT  76.633 75.168 76.993 78.12 ;
     RECT  75.265 20.832 77.317 74.088 ;
     RECT  76.993 75.168 77.317 78.216 ;
     RECT  76.115 82.224 77.425 82.248 ;
     RECT  76.115 83.328 77.425 85.752 ;
     RECT  77.317 20.832 77.893 78.216 ;
     RECT  76.745 80.4 77.929 80.856 ;
     RECT  72.904 7.056 78.008 7.08 ;
     RECT  72.904 16.8 78.008 18.744 ;
     RECT  77.893 20.832 78.008 78.696 ;
     RECT  77.929 80.016 78.008 80.856 ;
     RECT  77.425 82.224 78.008 85.752 ;
     RECT  78.008 2.148 78.112 86.412 ;
     RECT  78.112 2.418 78.304 86.142 ;
     RECT  78.304 20.832 78.419 85.752 ;
     RECT  78.433 87.792 78.707 87.816 ;
     RECT  78.419 20.832 79.772 74.088 ;
     RECT  78.419 75.12 79.772 85.752 ;
     RECT  79.772 20.832 81.253 85.752 ;
     RECT  81.253 20.832 81.317 86.616 ;
     RECT  81.317 73.488 81.389 86.616 ;
     RECT  81.317 20.832 82.453 72.504 ;
     RECT  81.389 73.488 82.453 85.752 ;
     RECT  78.304 7.056 83.408 7.08 ;
     RECT  78.304 16.8 83.408 18.744 ;
     RECT  82.453 20.832 83.408 85.752 ;
     RECT  83.408 2.148 83.512 86.412 ;
     RECT  83.512 2.418 83.704 86.142 ;
     RECT  83.653 87.792 83.939 87.816 ;
     RECT  83.704 20.832 84.877 74.184 ;
     RECT  83.704 75.168 84.877 85.752 ;
     RECT  84.877 20.832 86.245 85.752 ;
     RECT  86.245 20.832 86.531 86.28 ;
     RECT  86.531 20.832 87.509 85.752 ;
     RECT  87.509 20.832 87.539 73.752 ;
     RECT  87.509 74.88 88.153 85.752 ;
     RECT  83.704 7.056 88.808 7.08 ;
     RECT  83.704 16.8 88.808 18.744 ;
     RECT  87.539 20.832 88.808 73.656 ;
     RECT  88.153 74.88 88.808 85.8 ;
     RECT  88.808 2.148 88.912 86.412 ;
     RECT  88.912 2.418 88.945 86.412 ;
     RECT  88.945 2.418 89.104 87.096 ;
     RECT  89.104 20.832 89.171 87.096 ;
     RECT  89.171 20.832 89.237 86.28 ;
     RECT  89.237 20.832 89.921 85.8 ;
     RECT  89.921 20.832 91.285 73.656 ;
     RECT  89.921 74.688 91.285 85.8 ;
     RECT  91.717 87.168 91.801 87.192 ;
     RECT  89.104 7.056 94.208 7.08 ;
     RECT  89.104 16.8 94.208 18.744 ;
     RECT  91.285 20.832 94.208 85.8 ;
     RECT  94.208 2.148 94.312 86.412 ;
     RECT  94.301 88.416 94.385 88.44 ;
     RECT  94.312 2.418 94.504 86.142 ;
     RECT  94.504 20.832 95.605 85.8 ;
     RECT  95.605 20.832 95.641 85.896 ;
     RECT  95.641 20.832 95.789 86.184 ;
     RECT  95.789 20.832 95.933 73.512 ;
     RECT  95.789 74.64 96.437 85.992 ;
     RECT  96.949 88.416 97.157 88.44 ;
     RECT  96.437 74.832 97.409 85.992 ;
     RECT  97.409 74.928 97.445 85.992 ;
     RECT  97.445 74.928 97.733 85.896 ;
     RECT  95.933 68.16 98.201 73.512 ;
     RECT  98.201 71.136 98.449 73.512 ;
     RECT  95.933 20.832 98.773 67.176 ;
     RECT  98.201 68.16 98.773 70.152 ;
     RECT  98.449 71.136 99.313 73.896 ;
     RECT  97.733 74.928 99.313 85.8 ;
     RECT  98.773 20.832 99.529 70.152 ;
     RECT  99.313 71.136 99.529 85.8 ;
     RECT  99.521 87.168 99.605 87.192 ;
     RECT  94.504 7.056 99.608 7.08 ;
     RECT  94.504 16.8 99.608 18.744 ;
     RECT  99.529 20.832 99.608 85.8 ;
     RECT  99.608 2.148 99.712 86.412 ;
     RECT  99.712 2.418 99.904 86.142 ;
     RECT  102.181 87.168 102.485 87.192 ;
     RECT  99.904 20.832 102.611 85.8 ;
     RECT  102.611 68.448 102.773 85.8 ;
     RECT  102.611 20.832 103.673 67.32 ;
     RECT  102.773 68.496 104.497 85.8 ;
     RECT  104.497 68.256 104.773 85.8 ;
     RECT  99.904 7.056 105.008 7.08 ;
     RECT  99.904 16.8 105.008 18.744 ;
     RECT  103.673 20.832 105.008 67.176 ;
     RECT  104.773 68.256 105.008 86.52 ;
     RECT  105.008 2.148 105.112 86.52 ;
     RECT  105.112 2.418 105.304 86.52 ;
     RECT  105.304 74.928 105.473 86.52 ;
     RECT  105.304 68.208 106.229 71.976 ;
     RECT  105.304 73.296 106.477 73.896 ;
     RECT  106.229 69.84 106.549 71.976 ;
     RECT  106.477 73.008 106.549 73.896 ;
     RECT  106.229 68.208 106.553 68.664 ;
     RECT  106.549 69.84 106.553 73.896 ;
     RECT  105.473 74.928 106.661 85.992 ;
     RECT  106.661 77.28 106.805 85.992 ;
     RECT  106.553 70.416 107.557 73.896 ;
     RECT  106.661 74.928 107.557 76.296 ;
     RECT  107.365 87.744 107.597 87.768 ;
     RECT  107.557 70.416 107.737 76.296 ;
     RECT  107.737 70.08 107.749 76.296 ;
     RECT  106.805 77.28 107.749 85.8 ;
     RECT  106.553 68.496 107.756 68.664 ;
     RECT  107.756 68.496 107.843 68.952 ;
     RECT  107.749 70.08 107.843 85.8 ;
     RECT  107.843 70.416 107.921 85.8 ;
     RECT  105.304 20.832 108.025 67.176 ;
     RECT  107.843 68.496 108.025 68.52 ;
     RECT  107.921 70.704 108.029 85.8 ;
     RECT  108.029 70.752 108.137 85.8 ;
     RECT  105.304 16.8 108.965 18.744 ;
     RECT  108.025 20.832 110.077 68.52 ;
     RECT  109.681 69.84 110.077 69.864 ;
     RECT  110.005 87.168 110.225 87.192 ;
     RECT  110.077 20.832 110.257 69.864 ;
     RECT  108.137 71.04 110.257 85.8 ;
     RECT  105.304 7.056 110.408 7.08 ;
     RECT  108.965 16.848 110.408 18.744 ;
     RECT  110.257 20.832 110.408 85.8 ;
     RECT  110.408 2.148 110.512 86.412 ;
     RECT  110.512 2.418 110.704 86.142 ;
     RECT  110.704 70.08 110.945 75.528 ;
     RECT  110.704 16.848 111.773 18.744 ;
     RECT  110.704 20.832 112.633 68.52 ;
     RECT  110.945 70.56 112.633 75.528 ;
     RECT  112.589 87.168 112.673 87.192 ;
     RECT  112.633 70.512 112.813 75.528 ;
     RECT  110.704 76.56 112.813 85.8 ;
     RECT  112.813 70.512 112.849 85.8 ;
     RECT  112.633 20.832 113.105 69 ;
     RECT  112.849 70.176 113.321 85.8 ;
     RECT  113.321 70.272 114.329 85.8 ;
     RECT  110.704 7.056 114.577 7.08 ;
     RECT  114.577 7.056 114.617 7.176 ;
     RECT  114.329 70.56 115.189 85.8 ;
     RECT  115.189 70.56 115.283 86.664 ;
     RECT  115.283 70.56 115.429 86.412 ;
     RECT  114.617 7.152 115.808 7.176 ;
     RECT  111.773 16.848 115.808 18.696 ;
     RECT  113.105 20.832 115.808 68.52 ;
     RECT  115.429 70.032 115.808 86.412 ;
     RECT  115.808 2.148 115.912 86.412 ;
     RECT  115.912 2.418 116.104 86.142 ;
     RECT  116.104 70.56 116.165 85.752 ;
     RECT  116.165 70.8 116.957 85.752 ;
     RECT  116.104 20.832 117.216 68.52 ;
     RECT  117.216 24.528 117.389 63.72 ;
     RECT  116.957 70.8 117.389 72.024 ;
     RECT  116.957 73.296 117.397 85.752 ;
     RECT  117.389 24.624 117.425 63.72 ;
     RECT  117.425 24.624 117.461 60.456 ;
     RECT  117.397 78.096 117.497 85.752 ;
     RECT  117.389 71.424 117.925 72.024 ;
     RECT  117.397 73.296 117.925 76.728 ;
     RECT  117.601 70.416 117.971 70.44 ;
     RECT  117.461 46.128 118.001 60.456 ;
     RECT  117.425 61.488 118.037 63.72 ;
     RECT  117.497 78.096 118.037 84.648 ;
     RECT  118.037 63.024 118.073 63.72 ;
     RECT  117.829 87.168 118.073 87.192 ;
     RECT  118.037 78.096 118.353 78.696 ;
     RECT  117.925 71.424 118.541 76.728 ;
     RECT  118.037 79.776 118.547 84.648 ;
     RECT  118.353 78.144 118.595 78.696 ;
     RECT  117.216 20.832 118.613 23.304 ;
     RECT  118.001 46.128 118.613 54.984 ;
     RECT  117.461 42.768 118.649 45.096 ;
     RECT  118.547 79.776 118.721 80.856 ;
     RECT  118.541 71.568 118.793 76.728 ;
     RECT  116.104 7.152 118.969 7.176 ;
     RECT  118.793 72.96 118.973 76.728 ;
     RECT  118.613 46.128 119.081 54.888 ;
     RECT  117.461 24.672 119.117 41.064 ;
     RECT  118.649 44.016 119.117 45.096 ;
     RECT  119.081 46.128 119.117 54.792 ;
     RECT  118.001 57.456 119.117 59.976 ;
     RECT  118.073 63.312 119.153 63.72 ;
     RECT  118.595 78.144 119.153 78.36 ;
     RECT  118.969 6.672 119.189 7.176 ;
     RECT  118.973 73.296 119.189 76.728 ;
     RECT  119.117 46.128 119.297 54.6 ;
     RECT  119.189 73.296 119.297 75 ;
     RECT  119.117 44.304 119.585 44.616 ;
     RECT  119.297 46.704 119.585 54.6 ;
     RECT  119.153 63.696 119.585 63.72 ;
     RECT  119.189 76.56 119.617 76.728 ;
     RECT  119.117 24.672 119.621 39.336 ;
     RECT  119.585 51.888 119.621 54.6 ;
     RECT  118.793 71.568 119.621 71.976 ;
     RECT  119.585 46.704 119.657 50.856 ;
     RECT  119.621 24.672 119.693 39.144 ;
     RECT  119.657 47.472 119.693 50.856 ;
     RECT  119.621 52.08 119.693 54.6 ;
     RECT  118.001 56.208 119.693 56.232 ;
     RECT  119.117 57.456 119.729 59.688 ;
     RECT  119.617 76.56 119.747 77.16 ;
     RECT  119.153 78.336 119.761 78.36 ;
     RECT  119.693 24.672 119.801 38.088 ;
     RECT  119.761 78.336 119.801 78.504 ;
     RECT  118.649 42.768 119.837 42.888 ;
     RECT  119.693 53.232 119.837 54.6 ;
     RECT  119.801 24.672 119.873 35.688 ;
     RECT  119.837 42.768 119.873 42.792 ;
     RECT  119.693 47.472 119.873 50.664 ;
     RECT  119.729 57.744 119.873 59.688 ;
     RECT  119.873 47.472 119.909 50.472 ;
     RECT  119.873 57.744 119.909 58.056 ;
     RECT  119.801 36.864 119.945 37.8 ;
     RECT  119.837 53.808 119.945 54.6 ;
     RECT  119.693 39.12 119.981 39.144 ;
     RECT  119.909 48.912 119.981 50.472 ;
     RECT  119.909 57.744 119.981 57.768 ;
     RECT  119.873 59.664 119.981 59.688 ;
     RECT  119.981 49.824 120.089 50.472 ;
     RECT  119.801 78.48 120.121 78.504 ;
     RECT  120.089 49.824 120.125 49.896 ;
     RECT  119.297 73.296 120.661 74.136 ;
     RECT  118.721 80.112 120.661 80.856 ;
     RECT  120.121 78.48 120.697 78.6 ;
     RECT  120.661 79.776 120.697 80.856 ;
     RECT  120.469 87.168 120.737 87.192 ;
     RECT  120.697 78.48 120.853 80.856 ;
     RECT  118.547 82.128 120.853 84.648 ;
     RECT  120.709 75.504 121.201 75.528 ;
     RECT  119.189 6.672 121.208 6.696 ;
     RECT  116.104 16.848 121.208 18.696 ;
     RECT  118.613 20.832 121.208 20.856 ;
     RECT  118.613 21.936 121.208 23.304 ;
     RECT  119.873 24.672 121.208 35.448 ;
     RECT  119.945 36.864 121.208 36.888 ;
     RECT  119.117 40.464 121.208 40.872 ;
     RECT  119.585 44.592 121.208 44.616 ;
     RECT  119.909 47.472 121.208 47.496 ;
     RECT  120.125 49.824 121.208 49.848 ;
     RECT  121.021 52.704 121.208 52.728 ;
     RECT  119.945 53.808 121.208 53.832 ;
     RECT  117.216 64.944 121.208 68.52 ;
     RECT  119.621 71.856 121.208 71.976 ;
     RECT  120.661 72.96 121.208 74.136 ;
     RECT  121.201 75.168 121.208 75.528 ;
     RECT  119.747 76.56 121.208 76.584 ;
     RECT  120.853 78.48 121.208 84.648 ;
     RECT  117.497 85.728 121.208 85.752 ;
     RECT  121.208 2.148 121.312 86.412 ;
     RECT  121.312 2.418 121.504 86.142 ;
     RECT  121.504 78.48 121.619 78.504 ;
     RECT  121.504 77.184 121.66 77.208 ;
     RECT  121.504 72.96 121.781 73.608 ;
     RECT  121.504 27.696 122.033 35.448 ;
     RECT  121.504 75.168 122.339 76.2 ;
     RECT  121.504 80.112 122.429 81.192 ;
     RECT  121.504 85.728 122.465 85.752 ;
     RECT  122.429 80.112 122.569 80.856 ;
     RECT  121.504 21.936 122.609 23.304 ;
     RECT  122.033 27.744 122.825 35.448 ;
     RECT  121.781 73.248 122.897 73.608 ;
     RECT  122.825 27.744 123.005 30.168 ;
     RECT  121.504 84.624 123.029 84.744 ;
     RECT  123.029 84.624 123.113 85.512 ;
     RECT  121.504 24.672 123.401 26.664 ;
     RECT  122.569 79.2 123.545 80.856 ;
     RECT  122.609 21.936 123.932 23.208 ;
     RECT  121.504 36.864 123.973 36.888 ;
     RECT  123.932 21.936 124.019 23.304 ;
     RECT  123.005 27.744 124.193 29.928 ;
     RECT  124.019 21.936 124.301 23.208 ;
     RECT  122.825 31.152 124.301 35.448 ;
     RECT  123.113 84.624 124.585 84.744 ;
     RECT  123.401 24.672 124.697 25.992 ;
     RECT  124.193 27.744 125.453 28.584 ;
     RECT  121.504 71.856 125.453 71.976 ;
     RECT  125.453 27.744 125.525 28.152 ;
     RECT  122.339 75.504 125.665 76.2 ;
     RECT  125.621 87.168 125.705 87.192 ;
     RECT  124.585 84.384 125.881 84.744 ;
     RECT  125.453 71.856 126.373 71.88 ;
     RECT  126.373 70.992 126.385 71.88 ;
     RECT  126.385 70.656 126.468 71.88 ;
     RECT  121.504 6.672 126.608 6.696 ;
     RECT  121.504 16.848 126.608 18.696 ;
     RECT  121.504 20.832 126.608 20.856 ;
     RECT  124.301 21.936 126.608 23.112 ;
     RECT  124.697 24.672 126.608 25.608 ;
     RECT  125.525 28.128 126.608 28.152 ;
     RECT  124.193 29.904 126.608 29.928 ;
     RECT  124.301 31.248 126.608 35.448 ;
     RECT  123.973 36.864 126.608 36.936 ;
     RECT  121.504 49.824 126.608 49.848 ;
     RECT  121.504 52.704 126.608 52.728 ;
     RECT  121.504 53.808 126.608 53.832 ;
     RECT  121.504 64.944 126.608 68.52 ;
     RECT  126.468 70.608 126.608 71.88 ;
     RECT  122.897 73.248 126.608 73.272 ;
     RECT  125.665 75.504 126.608 76.392 ;
     RECT  125.893 77.76 126.608 77.784 ;
     RECT  123.545 80.112 126.608 80.856 ;
     RECT  121.504 82.8 126.608 83.016 ;
     RECT  125.881 84.384 126.608 84.936 ;
     RECT  126.608 2.148 126.712 86.412 ;
     RECT  126.712 2.418 126.904 86.142 ;
     RECT  126.904 53.808 127.253 53.832 ;
     RECT  126.904 84.912 127.289 84.984 ;
     RECT  126.904 31.248 127.721 35.448 ;
     RECT  126.904 70.608 127.933 70.632 ;
     RECT  127.933 70.512 127.973 70.632 ;
     RECT  128.252 86.64 128.339 86.664 ;
     RECT  127.289 84.96 128.437 84.984 ;
     RECT  126.904 49.824 128.549 49.848 ;
     RECT  126.904 64.944 128.873 68.52 ;
     RECT  126.904 75.504 129.161 76.392 ;
     RECT  128.873 64.944 129.637 66.504 ;
     RECT  129.637 64.752 129.644 66.504 ;
     RECT  126.904 24.672 129.665 24.984 ;
     RECT  128.873 67.536 129.683 68.52 ;
     RECT  126.904 71.856 129.731 71.88 ;
     RECT  127.721 31.92 129.733 35.448 ;
     RECT  126.904 36.864 129.733 36.936 ;
     RECT  128.437 84.336 129.809 84.984 ;
     RECT  129.644 64.368 129.877 66.504 ;
     RECT  129.665 24.96 130.277 24.984 ;
     RECT  129.809 84.816 130.453 84.984 ;
     RECT  130.381 47.856 130.465 47.88 ;
     RECT  126.904 20.832 130.525 20.856 ;
     RECT  130.525 20.832 130.565 20.952 ;
     RECT  129.161 75.648 130.565 75.96 ;
     RECT  126.904 29.904 130.601 29.928 ;
     RECT  130.741 86.64 130.931 86.664 ;
     RECT  130.453 84.816 131.137 85.416 ;
     RECT  127.973 70.512 131.245 70.536 ;
     RECT  129.685 58.656 131.317 58.68 ;
     RECT  129.877 64.32 131.317 66.504 ;
     RECT  129.683 68.496 131.317 68.52 ;
     RECT  131.317 58.512 131.461 58.68 ;
     RECT  131.281 72.24 131.461 72.264 ;
     RECT  126.904 80.112 131.461 80.856 ;
     RECT  130.565 20.928 131.569 20.952 ;
     RECT  126.904 21.936 131.569 23.112 ;
     RECT  131.569 20.928 131.605 23.112 ;
     RECT  131.461 79.728 131.605 80.856 ;
     RECT  131.317 64.32 131.857 68.52 ;
     RECT  129.733 31.92 131.893 36.936 ;
     RECT  131.852 38.928 131.893 38.952 ;
     RECT  131.137 84.816 131.893 85.512 ;
     RECT  131.077 77.52 131.965 77.544 ;
     RECT  126.904 6.672 132.008 6.696 ;
     RECT  126.904 16.848 132.008 18.696 ;
     RECT  131.605 20.88 132.008 23.112 ;
     RECT  131.533 28.944 132.008 28.968 ;
     RECT  131.893 31.92 132.008 39.336 ;
     RECT  126.904 52.704 132.008 52.728 ;
     RECT  131.461 58.512 132.008 59.016 ;
     RECT  130.405 61.728 132.008 61.752 ;
     RECT  131.857 64.32 132.008 68.952 ;
     RECT  131.245 70.512 132.008 71.112 ;
     RECT  131.461 72.24 132.008 72.456 ;
     RECT  130.565 75.744 132.008 75.96 ;
     RECT  131.965 77.52 132.008 77.592 ;
     RECT  131.605 79.728 132.008 80.952 ;
     RECT  126.904 82.8 132.008 83.016 ;
     RECT  131.893 84.672 132.008 85.512 ;
     RECT  132.008 2.148 132.112 86.412 ;
     RECT  132.112 2.256 132.304 86.142 ;
     RECT  132.304 21.936 132.365 23.16 ;
     RECT  132.304 72.24 132.365 75.96 ;
     RECT  132.304 79.488 132.365 80.856 ;
     RECT  132.304 81.888 132.401 83.112 ;
     RECT  132.304 84.672 132.401 85.512 ;
     RECT  132.304 2.256 132.473 2.28 ;
     RECT  132.365 79.488 132.473 79.8 ;
     RECT  132.365 72.24 132.563 75.912 ;
     RECT  132.563 72.24 132.589 75.768 ;
     RECT  132.304 16.56 132.803 19.416 ;
     RECT  132.589 72.24 132.803 74.328 ;
     RECT  132.304 55.728 132.833 55.752 ;
     RECT  132.304 77.568 132.869 77.592 ;
     RECT  132.304 26.208 132.947 27.624 ;
     RECT  132.304 28.944 132.947 29.784 ;
     RECT  132.304 34.656 132.977 34.728 ;
     RECT  132.803 72.24 133.049 73.512 ;
     RECT  132.304 58.512 133.121 60.456 ;
     RECT  132.304 6.672 133.193 6.84 ;
     RECT  132.304 30.768 133.235 30.792 ;
     RECT  132.304 39.312 133.235 40.008 ;
     RECT  132.304 41.328 133.235 43.032 ;
     RECT  132.304 54.624 133.265 54.696 ;
     RECT  133.235 39.984 133.276 40.008 ;
     RECT  132.304 3.936 133.285 3.96 ;
     RECT  132.365 22.752 133.297 23.16 ;
     RECT  132.304 9.408 133.324 10.152 ;
     RECT  133.285 3.936 133.333 4.536 ;
     RECT  132.803 16.56 133.337 18.792 ;
     RECT  132.947 29.76 133.337 29.784 ;
     RECT  132.304 47.28 133.34 47.304 ;
     RECT  132.304 31.92 133.369 33.576 ;
     RECT  132.977 34.656 133.369 34.68 ;
     RECT  133.285 5.616 133.372 5.64 ;
     RECT  133.333 3.408 133.379 4.536 ;
     RECT  133.265 54.624 133.409 54.648 ;
     RECT  132.304 61.584 133.409 62.952 ;
     RECT  132.473 79.488 133.409 79.752 ;
     RECT  132.304 71.088 133.413 71.112 ;
     RECT  133.297 44.448 133.429 45 ;
     RECT  133.413 70.128 133.429 71.112 ;
     RECT  133.049 72.24 133.429 72.984 ;
     RECT  133.121 58.608 133.441 60.456 ;
     RECT  132.304 51.312 133.445 51.336 ;
     RECT  133.429 44.448 133.475 45.672 ;
     RECT  133.429 70.128 133.475 72.984 ;
     RECT  132.401 81.888 133.477 81.912 ;
     RECT  132.401 82.896 133.477 83.112 ;
     RECT  133.193 6.816 133.481 6.84 ;
     RECT  132.401 84.672 133.513 84.696 ;
     RECT  132.365 80.832 133.549 80.856 ;
     RECT  133.477 81.888 133.549 83.112 ;
     RECT  133.34 47.28 133.573 47.88 ;
     RECT  133.477 57.456 133.621 57.48 ;
     RECT  132.304 49.008 133.625 49.032 ;
     RECT  133.525 87.744 133.661 87.768 ;
     RECT  133.324 9.936 133.697 10.152 ;
     RECT  133.297 22.752 133.697 23.976 ;
     RECT  132.947 26.208 133.697 27.096 ;
     RECT  133.513 84.288 133.724 84.696 ;
     RECT  133.573 46.752 133.733 47.88 ;
     RECT  133.697 22.752 133.837 23.832 ;
     RECT  132.304 64.32 133.837 67.08 ;
     RECT  133.549 80.832 133.837 83.112 ;
     RECT  133.724 84.288 133.837 84.936 ;
     RECT  133.837 64.032 133.907 67.08 ;
     RECT  133.409 61.632 133.909 62.952 ;
     RECT  133.907 64.032 133.909 66.504 ;
     RECT  132.304 68.496 133.913 68.952 ;
     RECT  133.475 45.552 133.949 45.672 ;
     RECT  133.369 31.92 133.981 34.68 ;
     RECT  133.475 44.448 133.985 44.472 ;
     RECT  133.837 80.832 134.057 84.936 ;
     RECT  133.981 31.92 134.089 34.728 ;
     RECT  134.089 31.92 134.129 34.776 ;
     RECT  133.235 41.328 134.232 41.352 ;
     RECT  132.304 36.048 134.273 37.608 ;
     RECT  133.409 79.488 134.3 79.512 ;
     RECT  134.057 81.456 134.305 84.936 ;
     RECT  133.765 86.064 134.305 86.088 ;
     RECT  134.232 41.328 134.309 41.832 ;
     RECT  132.589 75.504 134.341 75.768 ;
     RECT  133.379 4.512 134.377 4.536 ;
     RECT  133.621 57.456 134.377 57.528 ;
     RECT  133.441 58.608 134.377 60.552 ;
     RECT  134.3 79.056 134.377 79.512 ;
     RECT  133.475 70.128 134.381 72.456 ;
     RECT  133.405 12.528 134.413 12.552 ;
     RECT  133.235 43.008 134.417 43.032 ;
     RECT  134.377 79.056 134.461 80.376 ;
     RECT  134.457 11.376 134.485 11.4 ;
     RECT  134.413 12.528 134.485 13.368 ;
     RECT  133.337 16.944 134.485 18.792 ;
     RECT  134.381 70.128 134.489 72.168 ;
     RECT  134.273 36.912 134.521 37.608 ;
     RECT  134.449 38.688 134.521 38.712 ;
     RECT  134.309 41.808 134.521 41.832 ;
     RECT  134.377 55.536 134.521 55.56 ;
     RECT  132.304 20.88 134.525 20.952 ;
     RECT  133.733 46.752 134.525 47.304 ;
     RECT  134.525 47.28 134.531 47.304 ;
     RECT  132.304 52.704 134.531 53.016 ;
     RECT  134.377 4.512 134.533 5.112 ;
     RECT  134.377 15.936 134.533 15.96 ;
     RECT  134.485 16.944 134.533 18.984 ;
     RECT  133.909 61.632 134.561 66.504 ;
     RECT  134.485 11.376 134.569 13.368 ;
     RECT  134.533 15.936 134.579 18.984 ;
     RECT  134.521 36.912 134.579 38.712 ;
     RECT  133.837 22.704 134.597 23.832 ;
     RECT  134.579 38.208 134.605 38.712 ;
     RECT  134.341 75.264 134.629 75.768 ;
     RECT  134.533 4.512 134.705 5.16 ;
     RECT  134.521 41.808 134.705 42.744 ;
     RECT  134.377 57.456 134.705 60.552 ;
     RECT  133.513 77.952 134.737 77.976 ;
     RECT  134.461 79.056 134.771 79.896 ;
     RECT  134.129 34.656 134.78 34.776 ;
     RECT  134.732 35.856 134.78 35.88 ;
     RECT  134.485 29.952 134.819 29.976 ;
     RECT  134.78 34.656 134.819 35.88 ;
     RECT  134.705 41.808 134.819 42.648 ;
     RECT  134.569 12.336 134.849 13.368 ;
     RECT  133.697 9.936 134.867 9.96 ;
     RECT  134.579 16.176 134.867 18.984 ;
     RECT  134.597 23.088 134.867 23.832 ;
     RECT  134.819 34.656 134.867 35.592 ;
     RECT  134.819 42.624 134.921 42.648 ;
     RECT  134.129 31.92 134.993 33.576 ;
     RECT  133.909 49.536 134.993 49.56 ;
     RECT  134.561 61.632 135.029 66.12 ;
     RECT  133.913 68.496 135.068 68.52 ;
     RECT  134.521 55.536 135.089 55.944 ;
     RECT  134.737 77.328 135.097 77.976 ;
     RECT  135.068 68.352 135.109 68.52 ;
     RECT  135.097 69.552 135.109 69.576 ;
     RECT  133.697 27.072 135.137 27.096 ;
     RECT  135.097 77.328 135.137 78.504 ;
     RECT  135.029 61.632 135.155 62.808 ;
     RECT  135.109 68.352 135.155 69.576 ;
     RECT  135.068 74.016 135.155 74.04 ;
     RECT  134.305 81.456 135.169 86.088 ;
     RECT  135.089 54.672 135.173 55.944 ;
     RECT  135.155 68.496 135.181 69.576 ;
     RECT  133.513 8.064 135.281 8.088 ;
     RECT  134.849 13.296 135.313 13.368 ;
     RECT  134.489 70.992 135.349 72.168 ;
     RECT  134.867 16.944 135.389 18.984 ;
     RECT  133.949 45.552 135.389 45.576 ;
     RECT  134.531 52.992 135.389 53.016 ;
     RECT  135.349 70.992 135.443 72.408 ;
     RECT  135.443 70.992 135.484 72.168 ;
     RECT  134.705 57.504 135.493 60.552 ;
     RECT  135.155 61.632 135.493 62.568 ;
     RECT  133.379 3.408 135.497 3.432 ;
     RECT  135.173 55.536 135.497 55.944 ;
     RECT  135.493 31.536 135.529 31.56 ;
     RECT  134.867 34.656 135.541 35.352 ;
     RECT  134.665 2.208 135.601 2.232 ;
     RECT  135.389 18.672 135.605 18.984 ;
     RECT  135.529 30.72 135.613 31.56 ;
     RECT  135.541 33.84 135.628 35.352 ;
     RECT  135.313 13.296 135.637 13.656 ;
     RECT  134.989 40.56 135.637 40.584 ;
     RECT  135.169 81.456 135.637 86.136 ;
     RECT  135.493 57.504 135.641 62.568 ;
     RECT  134.629 75.264 135.677 76.104 ;
     RECT  135.137 78.48 135.677 78.504 ;
     RECT  135.637 13.296 135.683 13.848 ;
     RECT  134.705 5.136 135.713 5.16 ;
     RECT  135.641 60.528 135.713 62.568 ;
     RECT  135.029 63.792 135.713 66.12 ;
     RECT  135.677 75.264 135.713 75.288 ;
     RECT  135.637 39.888 135.721 40.584 ;
     RECT  135.637 81.024 135.788 86.136 ;
     RECT  135.529 27.024 135.816 27.048 ;
     RECT  134.605 38.688 135.82 38.712 ;
     RECT  135.637 11.952 135.821 11.976 ;
     RECT  135.628 34.656 135.821 35.352 ;
     RECT  135.82 38.64 135.821 38.712 ;
     RECT  135.641 57.504 135.821 59.496 ;
     RECT  134.867 23.088 135.829 23.112 ;
     RECT  134.993 32.592 135.857 32.616 ;
     RECT  135.816 26.64 135.923 27.048 ;
     RECT  135.836 28.08 135.923 28.104 ;
     RECT  135.821 38.64 135.965 38.664 ;
     RECT  135.389 16.944 136.001 16.968 ;
     RECT  135.817 46.704 136.001 46.728 ;
     RECT  135.788 80.88 136.021 86.136 ;
     RECT  134.809 21.072 136.028 21.096 ;
     RECT  134.771 79.824 136.028 79.896 ;
     RECT  136.021 80.88 136.028 86.616 ;
     RECT  135.829 22.128 136.031 23.112 ;
     RECT  135.601 2.208 136.037 3.336 ;
     RECT  135.484 71.568 136.037 72.168 ;
     RECT  136.028 20.784 136.069 21.096 ;
     RECT  136.028 79.824 136.069 86.616 ;
     RECT  135.683 13.824 136.073 13.848 ;
     RECT  135.923 26.64 136.073 26.664 ;
     RECT  135.821 34.752 136.073 35.352 ;
     RECT  135.721 40.56 136.073 40.584 ;
     RECT  135.713 60.672 136.073 62.568 ;
     RECT  135.137 77.328 136.073 77.352 ;
     RECT  136.069 19.92 136.109 21.096 ;
     RECT  136.031 22.128 136.109 23.352 ;
     RECT  136.109 19.92 136.115 20.808 ;
     RECT  136.109 22.128 136.115 22.152 ;
     RECT  136.069 79.776 136.115 86.616 ;
     RECT  136.115 80.928 136.163 86.616 ;
     RECT  136.115 79.776 136.165 79.896 ;
     RECT  135.821 57.552 136.181 59.496 ;
     RECT  136.037 2.64 136.217 3.336 ;
     RECT  135.605 18.672 136.253 18.696 ;
     RECT  134.737 51.744 136.253 51.768 ;
     RECT  135.181 68.496 136.253 69.336 ;
     RECT  134.579 36.912 136.325 36.984 ;
     RECT  135.497 55.824 136.325 55.944 ;
     RECT  136.325 36.912 136.397 36.936 ;
     RECT  136.037 72.144 136.897 72.168 ;
     RECT  136.253 68.496 136.969 68.52 ;
     RECT  136.165 79.728 137.084 79.896 ;
     RECT  136.163 80.928 137.084 86.568 ;
     RECT  137.365 2.304 137.408 2.328 ;
     RECT  136.217 3.312 137.408 3.336 ;
     RECT  136.681 12.48 137.408 12.504 ;
     RECT  136.115 19.92 137.408 19.944 ;
     RECT  136.109 23.328 137.408 23.352 ;
     RECT  135.493 24.528 137.408 24.552 ;
     RECT  135.613 31.536 137.408 31.56 ;
     RECT  136.073 35.328 137.408 35.352 ;
     RECT  136.465 36.432 137.408 36.456 ;
     RECT  137.221 38.16 137.408 38.184 ;
     RECT  136.213 42.144 137.408 42.168 ;
     RECT  136.325 55.824 137.408 55.848 ;
     RECT  136.181 57.552 137.408 58.488 ;
     RECT  136.181 59.472 137.408 59.496 ;
     RECT  136.073 60.672 137.408 62.184 ;
     RECT  135.713 63.792 137.408 64.968 ;
     RECT  135.713 66.096 137.408 66.12 ;
     RECT  136.969 68.4 137.408 68.52 ;
     RECT  136.897 72.144 137.408 72.936 ;
     RECT  137.084 79.728 137.408 86.568 ;
     RECT  137.408 2.148 137.704 86.568 ;
     RECT  137.704 81.072 137.729 83.784 ;
     RECT  137.704 62.304 137.798 63.816 ;
     RECT  137.704 79.776 137.801 79.8 ;
     RECT  137.704 85.392 137.869 86.568 ;
     RECT  137.729 81.072 137.981 83.688 ;
     RECT  137.704 2.148 138.013 4.344 ;
     RECT  137.704 6.624 139.021 7.224 ;
     RECT  137.704 8.64 139.021 8.952 ;
     RECT  137.704 26.256 139.021 26.28 ;
     RECT  137.704 34.896 139.021 35.208 ;
     RECT  137.704 76.752 139.021 77.928 ;
     RECT  138.013 1.44 139.057 4.344 ;
     RECT  137.704 5.472 139.057 5.496 ;
     RECT  139.021 6.624 139.057 8.952 ;
     RECT  137.704 10.368 139.057 12.12 ;
     RECT  137.704 13.248 139.057 13.272 ;
     RECT  139.021 14.688 139.057 14.712 ;
     RECT  137.704 16.128 139.057 17.016 ;
     RECT  137.704 18.144 139.057 18.168 ;
     RECT  137.704 20.16 139.057 20.184 ;
     RECT  137.704 23.328 139.057 23.352 ;
     RECT  137.704 24.816 139.057 25.128 ;
     RECT  139.021 26.256 139.057 27.72 ;
     RECT  137.704 30 139.057 30.312 ;
     RECT  137.704 32.016 139.057 33.192 ;
     RECT  139.021 34.896 139.057 35.784 ;
     RECT  137.704 37.488 139.057 37.512 ;
     RECT  137.704 38.64 139.057 39.528 ;
     RECT  137.704 40.944 139.057 44.712 ;
     RECT  137.704 45.84 139.057 45.864 ;
     RECT  137.704 47.856 139.057 52.824 ;
     RECT  137.704 54.816 139.057 55.128 ;
     RECT  137.704 56.544 139.057 59.448 ;
     RECT  137.704 60.576 139.057 60.888 ;
     RECT  137.798 62.304 139.057 63.768 ;
     RECT  137.704 65.76 139.057 66.36 ;
     RECT  137.704 68.64 139.057 68.952 ;
     RECT  137.704 70.08 139.057 72.12 ;
     RECT  137.704 73.536 139.057 74.424 ;
     RECT  137.704 75.552 139.057 75.576 ;
     RECT  139.021 76.752 139.057 78.504 ;
     RECT  137.981 81.072 139.057 81.096 ;
     RECT  137.981 82.224 139.057 82.248 ;
     RECT  137.981 83.664 139.057 83.688 ;
     RECT  137.869 85.392 139.057 87.144 ;
     RECT  139.057 1.44 139.669 87.144 ;
     RECT  139.669 1.44 140.281 87.432 ;
     RECT  140.281 1.152 140.364 87.432 ;
    LAYER M5 ;
     RECT  2.4 2.137 2.52 2.151 ;
     RECT  7.8 2.137 7.92 2.151 ;
     RECT  13.2 2.137 13.32 2.151 ;
     RECT  18.6 2.137 18.72 2.151 ;
     RECT  24 2.137 24.12 2.151 ;
     RECT  29.4 2.137 29.52 2.151 ;
     RECT  34.8 2.137 34.92 2.151 ;
     RECT  40.2 2.137 40.32 2.151 ;
     RECT  45.6 2.137 45.72 2.151 ;
     RECT  51 2.137 51.12 2.151 ;
     RECT  56.4 2.137 56.52 2.151 ;
     RECT  61.8 2.137 61.92 2.151 ;
     RECT  67.2 2.137 67.32 2.151 ;
     RECT  72.6 2.137 72.72 2.151 ;
     RECT  78 2.137 78.12 2.151 ;
     RECT  83.4 2.137 83.52 2.151 ;
     RECT  88.8 2.137 88.92 2.151 ;
     RECT  94.2 2.137 94.32 2.151 ;
     RECT  99.6 2.137 99.72 2.151 ;
     RECT  105 2.137 105.12 2.151 ;
     RECT  110.4 2.137 110.52 2.151 ;
     RECT  115.8 2.137 115.92 2.151 ;
     RECT  121.2 2.137 121.32 2.151 ;
     RECT  126.6 2.137 126.72 2.151 ;
     RECT  132 2.137 132.12 2.151 ;
     RECT  137.4 2.137 137.52 2.151 ;
     RECT  7.8 2.151 8.112 2.245 ;
     RECT  6.864 2.245 8.112 3.011 ;
     RECT  133.344 3.397 133.368 3.971 ;
     RECT  7.632 3.011 8.112 5.029 ;
     RECT  134.544 4.501 134.568 5.077 ;
     RECT  134.4 5.077 134.568 5.171 ;
     RECT  18.6 2.151 18.912 5.221 ;
     RECT  17.952 5.221 18.912 5.747 ;
     RECT  133.296 4.501 133.32 6.851 ;
     RECT  18 5.747 18.912 7.189 ;
     RECT  17.952 7.189 18.912 7.333 ;
     RECT  7.2 5.029 8.112 7.381 ;
     RECT  17.952 7.333 19.272 8.965 ;
     RECT  17.52 8.965 19.272 9.011 ;
     RECT  6.288 7.381 8.112 9.251 ;
     RECT  21.888 7.093 21.912 9.349 ;
     RECT  132 2.151 132.312 9.397 ;
     RECT  4.512 9.061 4.536 9.493 ;
     RECT  3.984 9.493 4.536 9.779 ;
     RECT  134.4 5.171 134.424 9.925 ;
     RECT  134.4 9.925 134.856 9.971 ;
     RECT  132 9.397 133.272 10.163 ;
     RECT  13.2 2.151 13.512 10.165 ;
     RECT  9.312 9.637 9.336 10.307 ;
     RECT  17.52 9.011 17.544 10.355 ;
     RECT  13.104 10.165 13.512 10.835 ;
     RECT  3.984 9.779 4.008 10.883 ;
     RECT  134.832 9.971 134.856 11.365 ;
     RECT  21.504 9.349 21.912 11.653 ;
     RECT  134.496 11.365 134.856 11.941 ;
     RECT  134.496 11.941 135.672 12.563 ;
     RECT  21.504 11.653 21.96 13.525 ;
     RECT  134.832 12.563 135.672 13.859 ;
     RECT  11.712 13.573 11.736 14.243 ;
     RECT  21.456 13.525 21.96 14.485 ;
     RECT  7.2 9.251 8.112 14.629 ;
     RECT  5.088 12.757 5.112 14.675 ;
     RECT  134.832 13.859 134.856 15.925 ;
     RECT  7.2 14.629 8.232 16.019 ;
     RECT  47.088 7.045 47.112 16.019 ;
     RECT  134.544 15.925 134.856 16.595 ;
     RECT  13.2 10.835 13.512 17.317 ;
     RECT  21.408 14.485 21.96 17.365 ;
     RECT  21.408 17.365 22.056 17.413 ;
     RECT  7.2 16.019 8.112 17.797 ;
     RECT  18.6 9.011 19.272 17.893 ;
     RECT  132 10.163 132.312 18.421 ;
     RECT  18.6 17.893 19.752 18.469 ;
     RECT  20.928 17.413 22.056 18.517 ;
     RECT  15.84 16.789 15.864 18.709 ;
     RECT  15.648 18.709 15.864 18.757 ;
     RECT  3.84 17.605 3.864 18.803 ;
     RECT  9.552 18.757 9.576 18.899 ;
     RECT  132 18.421 132.792 19.427 ;
     RECT  15.648 18.757 16.584 19.715 ;
     RECT  6.96 17.797 8.112 19.909 ;
     RECT  20.88 18.517 22.056 20.293 ;
     RECT  136.08 19.909 136.104 20.819 ;
     RECT  18.144 18.469 19.752 20.821 ;
     RECT  20.88 20.293 22.2 20.821 ;
     RECT  132 19.427 132.312 20.869 ;
     RECT  15.648 19.715 15.864 20.965 ;
     RECT  17.04 20.485 17.064 20.965 ;
     RECT  6.96 19.909 9.096 21.011 ;
     RECT  4.368 19.909 4.392 21.155 ;
     RECT  18.144 20.821 22.2 21.205 ;
     RECT  11.952 20.485 11.976 21.251 ;
     RECT  18.144 21.205 22.584 21.347 ;
     RECT  15.648 20.965 17.064 21.493 ;
     RECT  15.024 21.493 17.064 21.539 ;
     RECT  131.616 20.869 132.312 21.683 ;
     RECT  13.2 17.317 13.896 21.877 ;
     RECT  15.024 21.539 15.96 21.877 ;
     RECT  17.04 21.539 17.064 21.923 ;
     RECT  135.84 21.061 135.864 22.117 ;
     RECT  135.84 22.117 136.104 22.163 ;
     RECT  6.96 21.011 8.112 22.165 ;
     RECT  18.144 21.347 22.2 22.453 ;
     RECT  9.552 21.061 9.576 22.597 ;
     RECT  6.912 22.165 8.112 22.741 ;
     RECT  9.504 22.597 9.576 23.029 ;
     RECT  18 22.453 22.2 23.317 ;
     RECT  136.08 22.163 136.104 23.363 ;
     RECT  13.2 21.877 15.96 23.365 ;
     RECT  13.056 23.365 15.96 23.411 ;
     RECT  6.528 22.741 8.112 23.555 ;
     RECT  134.832 16.595 134.856 23.797 ;
     RECT  134.64 23.797 134.856 23.843 ;
     RECT  6.912 23.555 8.112 24.515 ;
     RECT  17.904 23.317 22.2 24.515 ;
     RECT  9.504 23.029 9.672 24.563 ;
     RECT  18 24.515 22.2 24.563 ;
     RECT  9.504 24.563 9.576 24.803 ;
     RECT  13.056 23.411 14.232 24.899 ;
     RECT  9.552 24.803 9.576 25.139 ;
     RECT  13.2 24.899 14.232 26.149 ;
     RECT  132 21.683 132.312 26.197 ;
     RECT  7.68 24.515 8.112 26.243 ;
     RECT  121.2 2.151 121.512 27.733 ;
     RECT  5.04 24.469 5.064 27.877 ;
     RECT  120.24 27.733 121.512 27.923 ;
     RECT  4.128 27.877 5.064 27.971 ;
     RECT  135.888 26.629 135.912 28.115 ;
     RECT  13.2 26.149 14.424 28.403 ;
     RECT  2.4 2.151 2.712 28.453 ;
     RECT  4.128 27.971 4.152 28.453 ;
     RECT  2.4 28.453 4.152 29.075 ;
     RECT  11.28 25.861 11.304 29.077 ;
     RECT  132 26.197 132.936 29.749 ;
     RECT  11.088 29.077 11.304 29.795 ;
     RECT  134.64 23.843 134.664 29.941 ;
     RECT  134.64 29.941 134.808 29.987 ;
     RECT  4.128 29.075 4.152 30.275 ;
     RECT  134.784 29.987 134.808 30.709 ;
     RECT  132 29.749 133.224 30.803 ;
     RECT  18 24.563 22.104 30.853 ;
     RECT  120.144 30.565 120.168 30.853 ;
     RECT  18 30.853 22.392 31.043 ;
     RECT  134.784 30.709 135.576 31.571 ;
     RECT  9.744 31.093 9.768 31.955 ;
     RECT  118.32 21.637 118.344 32.771 ;
     RECT  13.2 28.403 14.232 33.061 ;
     RECT  5.568 31.813 5.592 33.683 ;
     RECT  134.784 31.571 134.808 33.829 ;
     RECT  11.28 29.795 11.304 34.165 ;
     RECT  119.376 30.853 120.168 34.165 ;
     RECT  10.944 34.165 11.304 34.211 ;
     RECT  12.336 33.061 14.232 34.355 ;
     RECT  118.464 34.165 120.168 34.691 ;
     RECT  134.784 33.829 135.576 34.693 ;
     RECT  134.016 34.693 135.576 34.787 ;
     RECT  6.288 34.165 6.312 35.267 ;
     RECT  7.8 26.243 8.112 35.461 ;
     RECT  10.944 34.211 10.968 35.941 ;
     RECT  10.848 35.941 10.968 35.987 ;
     RECT  137.4 2.151 137.712 36.421 ;
     RECT  18 31.043 22.104 36.565 ;
     RECT  7.8 35.461 8.232 36.659 ;
     RECT  18 36.565 22.392 36.947 ;
     RECT  123.984 23.269 124.008 36.947 ;
     RECT  132 30.803 132.312 37.957 ;
     RECT  13.2 34.355 14.232 38.005 ;
     RECT  12.912 38.005 14.232 38.723 ;
     RECT  131.904 37.957 132.312 38.963 ;
     RECT  6.336 35.317 6.36 39.109 ;
     RECT  10.848 35.987 10.872 39.109 ;
     RECT  6.336 39.109 6.504 39.155 ;
     RECT  10.848 39.109 11.544 39.205 ;
     RECT  132 38.963 132.312 39.301 ;
     RECT  134.016 34.787 135.048 39.301 ;
     RECT  10.176 39.205 11.544 39.347 ;
     RECT  132 39.301 135.048 39.877 ;
     RECT  136.512 36.421 137.712 39.877 ;
     RECT  18 36.947 22.104 40.069 ;
     RECT  18 40.069 22.392 40.355 ;
     RECT  132 39.877 137.712 40.595 ;
     RECT  6.48 39.155 6.504 40.979 ;
     RECT  10.848 39.347 11.544 41.413 ;
     RECT  10.08 41.413 11.544 41.651 ;
     RECT  132 40.595 135.048 42.179 ;
     RECT  10.08 41.651 10.104 42.803 ;
     RECT  6.432 41.749 6.456 43.141 ;
     RECT  11.088 41.651 11.544 43.619 ;
     RECT  6.24 43.141 6.456 44.483 ;
     RECT  134.016 42.179 135.048 44.965 ;
     RECT  3.936 44.245 3.96 45.059 ;
     RECT  15.648 23.411 15.96 45.059 ;
     RECT  133.44 44.965 135.048 45.683 ;
     RECT  7.8 36.659 8.112 46.741 ;
     RECT  134.016 45.683 135.048 46.741 ;
     RECT  11.088 43.619 11.112 47.269 ;
     RECT  6.432 44.483 6.456 47.363 ;
     RECT  13.2 38.723 14.232 47.653 ;
     RECT  15.648 45.059 15.864 47.653 ;
     RECT  13.2 47.653 15.864 47.795 ;
     RECT  7.8 46.741 8.712 47.845 ;
     RECT  129.744 35.941 129.768 47.845 ;
     RECT  133.584 46.741 135.048 47.845 ;
     RECT  6.816 47.845 8.712 48.083 ;
     RECT  11.088 47.269 11.88 48.277 ;
     RECT  13.2 47.795 14.232 48.277 ;
     RECT  6.816 48.083 8.472 48.467 ;
     RECT  18 40.355 22.104 48.515 ;
     RECT  18.048 48.515 22.104 48.997 ;
     RECT  133.392 47.845 135.048 49.043 ;
     RECT  18.048 48.997 22.392 49.187 ;
     RECT  119.376 34.691 120.168 49.859 ;
     RECT  6.192 49.909 6.216 50.101 ;
     RECT  7.8 48.467 8.472 50.101 ;
     RECT  18.048 49.187 22.104 50.533 ;
     RECT  6.192 50.101 8.472 50.629 ;
     RECT  18.048 50.533 22.152 50.629 ;
     RECT  5.76 50.629 8.472 50.675 ;
     RECT  5.76 50.675 5.784 51.299 ;
     RECT  6.96 50.675 8.472 51.923 ;
     RECT  15.648 47.795 15.864 51.923 ;
     RECT  134.016 49.043 135.048 52.739 ;
     RECT  18.048 50.629 22.2 52.789 ;
     RECT  117.744 36.853 117.768 52.885 ;
     RECT  18.048 52.789 22.392 52.979 ;
     RECT  7.008 51.923 8.472 53.027 ;
     RECT  3.984 49.957 4.008 53.075 ;
     RECT  7.104 53.027 8.472 53.603 ;
     RECT  15.84 51.923 15.864 53.603 ;
     RECT  119.376 49.859 119.4 53.843 ;
     RECT  132 42.179 132.312 54.613 ;
     RECT  135.024 52.739 135.048 54.661 ;
     RECT  135.024 54.661 135.144 55.571 ;
     RECT  132 54.613 132.792 55.763 ;
     RECT  11.088 48.277 14.232 55.907 ;
     RECT  10.032 48.949 10.056 56.483 ;
     RECT  11.088 55.907 11.448 56.677 ;
     RECT  9.648 56.677 9.672 56.725 ;
     RECT  2.4 29.075 2.712 56.869 ;
     RECT  7.104 53.603 8.112 56.917 ;
     RECT  18.048 52.979 22.2 57.059 ;
     RECT  9.168 56.725 9.672 57.541 ;
     RECT  10.848 56.677 11.448 57.541 ;
     RECT  9.168 57.541 11.448 57.683 ;
     RECT  2.4 56.869 3.096 57.875 ;
     RECT  129.744 47.845 130.44 58.645 ;
     RECT  10.944 57.683 11.448 58.739 ;
     RECT  18.432 57.059 22.2 59.173 ;
     RECT  9.168 57.683 9.912 59.315 ;
     RECT  132 55.763 132.312 59.605 ;
     RECT  134.016 52.739 134.04 59.605 ;
     RECT  132 59.605 134.04 60.467 ;
     RECT  6.912 56.917 8.112 60.805 ;
     RECT  9.168 59.315 9.672 60.805 ;
     RECT  17.616 59.173 22.2 61.237 ;
     RECT  129.696 58.645 130.44 61.763 ;
     RECT  134.016 60.467 134.04 62.053 ;
     RECT  135.024 55.571 135.048 62.053 ;
     RECT  10.944 58.739 10.968 62.581 ;
     RECT  10.8 62.581 10.968 62.629 ;
     RECT  133.488 62.053 134.04 62.677 ;
     RECT  135.024 62.053 135.144 62.677 ;
     RECT  10.8 62.629 11.304 62.723 ;
     RECT  133.488 62.677 135.144 62.771 ;
     RECT  134.016 62.771 135.144 62.819 ;
     RECT  6.912 60.805 9.672 63.299 ;
     RECT  12.48 55.907 14.232 63.299 ;
     RECT  6.912 63.299 8.232 63.875 ;
     RECT  10.944 62.723 11.304 63.875 ;
     RECT  134.016 62.819 135.048 63.875 ;
     RECT  3.936 63.781 3.96 64.021 ;
     RECT  136.512 40.595 137.712 64.451 ;
     RECT  129.696 61.763 129.768 64.741 ;
     RECT  10.944 63.875 11.16 64.885 ;
     RECT  134.016 63.875 134.04 64.885 ;
     RECT  115.8 2.151 116.112 64.933 ;
     RECT  117.36 52.885 117.768 64.933 ;
     RECT  3.936 64.021 4.776 64.979 ;
     RECT  7.392 63.875 8.232 65.027 ;
     RECT  9.648 63.299 9.672 65.027 ;
     RECT  115.8 64.933 117.768 65.123 ;
     RECT  40.2 2.151 40.512 65.221 ;
     RECT  16.848 61.237 22.2 65.267 ;
     RECT  129.648 64.741 129.768 65.603 ;
     RECT  135.024 63.875 135.048 65.603 ;
     RECT  133.92 64.885 134.04 66.085 ;
     RECT  133.872 66.085 134.04 66.179 ;
     RECT  7.392 65.027 8.112 66.227 ;
     RECT  17.616 65.267 22.2 66.515 ;
     RECT  10.944 64.885 11.4 66.613 ;
     RECT  40.2 65.221 40.632 66.755 ;
     RECT  128.544 34.645 128.568 66.755 ;
     RECT  117.36 65.123 117.768 66.803 ;
     RECT  18.432 66.515 22.2 66.851 ;
     RECT  42.768 65.269 42.792 66.899 ;
     RECT  13.2 63.299 14.232 67.043 ;
     RECT  34.8 2.151 35.112 67.045 ;
     RECT  132 60.467 132.312 67.045 ;
     RECT  133.872 66.179 133.896 67.091 ;
     RECT  34.8 67.045 35.352 67.331 ;
     RECT  10.944 66.613 11.736 67.571 ;
     RECT  129.648 65.603 129.72 67.571 ;
     RECT  110.4 2.151 110.712 67.621 ;
     RECT  7.44 66.227 8.112 67.669 ;
     RECT  51 2.151 51.312 67.669 ;
     RECT  94.2 2.151 94.512 67.669 ;
     RECT  10.944 67.571 11.16 67.715 ;
     RECT  4.752 64.979 4.776 67.859 ;
     RECT  102.576 67.285 102.6 67.859 ;
     RECT  69.84 67.381 69.864 68.101 ;
     RECT  81.696 68.005 81.72 68.147 ;
     RECT  85.2 67.909 85.224 68.147 ;
     RECT  86.208 68.053 86.232 68.195 ;
     RECT  88.8 2.151 89.112 68.197 ;
     RECT  93.456 67.669 94.512 68.245 ;
     RECT  88.32 68.197 89.112 68.341 ;
     RECT  79.824 67.765 79.848 68.387 ;
     RECT  105 2.151 105.312 68.389 ;
     RECT  110.016 67.621 110.712 68.435 ;
     RECT  137.232 64.451 137.712 68.435 ;
     RECT  93.456 68.245 95.448 68.915 ;
     RECT  83.4 2.151 83.712 68.917 ;
     RECT  107.184 68.629 107.208 68.917 ;
     RECT  11.04 67.715 11.16 68.963 ;
     RECT  87.408 68.341 89.112 68.963 ;
     RECT  78 2.151 78.312 69.061 ;
     RECT  18.6 66.851 22.2 69.299 ;
     RECT  104.88 68.389 105.312 69.491 ;
     RECT  77.136 69.061 78.312 69.493 ;
     RECT  88.32 68.963 89.112 69.493 ;
     RECT  83.4 68.917 83.976 69.587 ;
     RECT  94.08 68.915 95.448 69.587 ;
     RECT  135.12 68.341 135.144 69.587 ;
     RECT  110.4 68.435 110.712 69.829 ;
     RECT  115.8 65.123 116.112 70.021 ;
     RECT  75.024 68.917 75.048 70.115 ;
     RECT  77.136 69.493 78.744 70.115 ;
     RECT  91.008 68.917 91.032 70.213 ;
     RECT  85.92 69.445 85.944 70.259 ;
     RECT  90.528 70.213 91.032 70.259 ;
     RECT  80.352 69.301 80.376 70.261 ;
     RECT  80.352 70.261 80.712 70.307 ;
     RECT  117.36 66.803 117.384 70.405 ;
     RECT  11.136 68.963 11.16 70.501 ;
     RECT  83.4 69.587 83.712 70.501 ;
     RECT  131.328 67.045 132.312 70.547 ;
     RECT  115.44 70.021 116.112 70.595 ;
     RECT  82.464 70.501 83.712 70.597 ;
     RECT  4.512 70.021 4.536 70.645 ;
     RECT  126.6 2.151 126.912 70.645 ;
     RECT  3.984 70.645 4.536 70.739 ;
     RECT  82.464 70.597 84.312 70.739 ;
     RECT  3.984 70.739 4.008 70.835 ;
     RECT  90.528 70.259 90.648 70.931 ;
     RECT  72.6 2.151 72.912 70.933 ;
     RECT  10.608 70.501 11.16 70.981 ;
     RECT  126.432 70.645 126.912 70.981 ;
     RECT  134.448 70.645 134.472 70.981 ;
     RECT  109.872 69.829 110.712 71.075 ;
     RECT  105 69.491 105.312 71.077 ;
     RECT  17.136 67.285 17.16 71.315 ;
     RECT  80.688 70.307 80.712 71.315 ;
     RECT  69.84 68.101 69.96 71.365 ;
     RECT  107.184 68.917 107.832 71.749 ;
     RECT  85.968 70.597 85.992 71.843 ;
     RECT  129.696 67.571 129.72 71.891 ;
     RECT  88.32 69.493 89.4 71.939 ;
     RECT  10.608 70.981 11.496 71.987 ;
     RECT  90.528 70.931 90.552 72.131 ;
     RECT  94.08 69.587 94.512 72.229 ;
     RECT  95.568 71.221 95.592 72.229 ;
     RECT  132 70.547 132.312 72.229 ;
     RECT  133.44 70.117 133.464 72.229 ;
     RECT  99.6 2.151 99.912 72.325 ;
     RECT  102.432 70.405 102.456 72.371 ;
     RECT  72.6 70.933 73.704 72.419 ;
     RECT  134.448 70.981 135.432 72.419 ;
     RECT  94.08 72.229 95.592 72.421 ;
     RECT  88.32 71.939 89.112 72.563 ;
     RECT  94.032 72.421 95.592 72.563 ;
     RECT  107.184 71.749 108.072 72.565 ;
     RECT  107.184 72.565 108.6 72.611 ;
     RECT  110.4 71.075 110.712 72.805 ;
     RECT  82.464 70.739 83.712 72.947 ;
     RECT  104.304 71.077 105.312 72.947 ;
     RECT  4.656 71.845 4.68 72.995 ;
     RECT  132 72.229 133.464 72.995 ;
     RECT  126.384 70.981 126.912 73.283 ;
     RECT  94.032 72.563 94.512 73.379 ;
     RECT  101.28 67.237 101.304 73.429 ;
     RECT  10.608 71.987 11.448 73.477 ;
     RECT  78 70.115 78.744 73.477 ;
     RECT  79.824 73.381 79.848 73.477 ;
     RECT  88.8 72.563 89.112 73.477 ;
     RECT  108.576 72.611 108.6 73.477 ;
     RECT  69.84 71.365 70.776 73.523 ;
     RECT  91.536 72.565 91.56 73.523 ;
     RECT  10.128 73.477 11.448 73.525 ;
     RECT  95.568 72.563 95.592 73.571 ;
     RECT  117.36 70.405 117.96 73.571 ;
     RECT  99.6 72.325 100.008 73.667 ;
     RECT  87.504 72.949 87.528 73.763 ;
     RECT  18.6 69.299 21.624 73.811 ;
     RECT  76.944 73.621 76.968 73.811 ;
     RECT  99.6 73.667 99.912 73.813 ;
     RECT  84.768 73.189 84.792 74.003 ;
     RECT  72.6 72.419 72.912 74.005 ;
     RECT  104.832 72.947 105.312 74.005 ;
     RECT  134.448 72.419 134.472 74.005 ;
     RECT  69.84 73.523 69.96 74.051 ;
     RECT  7.2 67.669 8.112 74.291 ;
     RECT  132 72.995 132.792 74.339 ;
     RECT  108.576 73.477 108.888 74.485 ;
     RECT  10.128 73.525 12.024 74.579 ;
     RECT  108.576 74.485 108.936 74.629 ;
     RECT  108.432 74.629 108.936 74.675 ;
     RECT  88.8 73.477 89.544 74.723 ;
     RECT  91.488 73.813 91.512 74.723 ;
     RECT  104.448 74.005 105.312 74.723 ;
     RECT  108.432 74.675 108.888 74.771 ;
     RECT  108.72 74.771 108.888 74.819 ;
     RECT  101.28 73.429 102.024 74.867 ;
     RECT  72.6 74.005 73.56 75.155 ;
     RECT  82.08 73.477 82.104 75.155 ;
     RECT  121.2 27.923 121.512 75.157 ;
     RECT  83.4 72.947 83.712 75.205 ;
     RECT  134.448 74.005 135.144 75.253 ;
     RECT  78 73.477 79.848 75.299 ;
     RECT  134.352 75.253 135.144 75.299 ;
     RECT  69.84 74.051 69.864 75.349 ;
     RECT  110.4 72.805 111 75.349 ;
     RECT  99.168 73.813 99.912 75.395 ;
     RECT  108.864 74.819 108.888 75.395 ;
     RECT  110.256 75.349 111 75.395 ;
     RECT  50.832 67.669 51.312 75.491 ;
     RECT  69.84 75.349 70.056 75.493 ;
     RECT  121.2 75.157 122.328 75.493 ;
     RECT  69.792 75.493 70.056 75.539 ;
     RECT  117.36 73.571 117.384 75.589 ;
     RECT  99.6 75.395 99.912 75.781 ;
     RECT  101.28 74.867 101.304 75.781 ;
     RECT  10.128 74.579 11.112 75.875 ;
     RECT  132 74.339 132.552 75.923 ;
     RECT  132 75.923 132.312 75.925 ;
     RECT  120.72 75.493 122.328 76.211 ;
     RECT  88.8 74.723 89.112 76.309 ;
     RECT  13.2 67.043 13.512 76.357 ;
     RECT  126.432 73.283 126.912 76.357 ;
     RECT  10.128 75.875 10.824 76.403 ;
     RECT  78 75.299 79.224 76.453 ;
     RECT  15.072 75.205 15.096 76.499 ;
     RECT  117.36 75.589 117.96 76.499 ;
     RECT  114.048 71.845 114.072 76.501 ;
     RECT  95.76 76.501 95.784 76.643 ;
     RECT  105 74.723 105.312 76.885 ;
     RECT  107.184 72.611 107.208 76.885 ;
     RECT  99.6 75.781 101.304 76.933 ;
     RECT  10.272 76.403 10.824 76.979 ;
     RECT  83.4 75.205 84.408 76.979 ;
     RECT  88.8 76.309 89.544 77.027 ;
     RECT  92.64 75.733 92.664 77.075 ;
     RECT  99.6 76.933 101.4 77.075 ;
     RECT  105 76.885 105.432 77.173 ;
     RECT  120.72 76.211 121.512 77.173 ;
     RECT  94.08 73.379 94.512 77.269 ;
     RECT  104.784 77.173 105.432 77.411 ;
     RECT  100.944 77.075 101.4 77.507 ;
     RECT  12.864 76.357 13.512 77.555 ;
     RECT  78 76.453 79.992 77.555 ;
     RECT  107.184 76.885 107.784 77.555 ;
     RECT  117.36 76.499 117.384 77.555 ;
     RECT  131.088 75.925 132.312 77.555 ;
     RECT  125.904 76.357 126.912 77.795 ;
     RECT  101.28 77.507 101.4 77.843 ;
     RECT  113.424 76.501 114.072 77.939 ;
     RECT  113.424 77.939 113.448 77.987 ;
     RECT  94.08 77.269 94.632 78.037 ;
     RECT  7.248 74.291 8.112 78.083 ;
     RECT  83.4 76.979 83.832 78.083 ;
     RECT  20.448 73.811 21.624 78.131 ;
     RECT  94.08 78.037 94.872 78.131 ;
     RECT  118.272 78.085 118.296 78.133 ;
     RECT  80.736 78.085 80.76 78.227 ;
     RECT  118.272 78.133 118.584 78.371 ;
     RECT  119.712 77.125 119.736 78.371 ;
     RECT  105 77.411 105.432 78.421 ;
     RECT  107.184 77.555 107.448 78.467 ;
     RECT  120.72 77.173 121.608 78.515 ;
     RECT  91.728 77.461 91.752 78.659 ;
     RECT  75.504 75.781 75.528 78.707 ;
     RECT  10.8 76.979 10.824 78.755 ;
     RECT  9.648 77.461 9.672 79.141 ;
     RECT  134.352 75.299 134.376 79.141 ;
     RECT  9.6 79.141 9.672 79.283 ;
     RECT  104.88 78.421 105.432 79.429 ;
     RECT  90.768 79.285 90.792 79.475 ;
     RECT  21.072 78.131 21.624 79.523 ;
     RECT  5.808 78.037 5.832 79.573 ;
     RECT  7.8 78.083 8.112 79.573 ;
     RECT  82.08 78.613 82.104 79.715 ;
     RECT  7.8 79.573 8.376 79.717 ;
     RECT  13.2 77.555 13.512 79.717 ;
     RECT  88.8 77.027 89.112 79.765 ;
     RECT  120.72 78.515 121.512 79.765 ;
     RECT  136.176 79.717 136.2 79.765 ;
     RECT  137.4 68.435 137.712 79.765 ;
     RECT  114.624 79.621 114.648 79.813 ;
     RECT  9.6 79.283 9.624 79.859 ;
     RECT  134.352 79.141 134.76 79.859 ;
     RECT  21.36 79.523 21.624 80.003 ;
     RECT  111.936 79.285 111.96 80.003 ;
     RECT  115.8 70.595 116.112 80.293 ;
     RECT  75.648 79.765 75.672 80.387 ;
     RECT  18.6 73.811 19.32 80.435 ;
     RECT  104.88 79.429 105.816 80.531 ;
     RECT  13.2 79.717 14.088 80.579 ;
     RECT  101.376 77.843 101.4 80.579 ;
     RECT  118.56 78.371 118.584 80.675 ;
     RECT  110.256 75.395 110.712 80.677 ;
     RECT  96.96 80.629 96.984 80.725 ;
     RECT  114.576 79.813 114.648 80.771 ;
     RECT  84.864 80.629 84.888 80.773 ;
     RECT  109.392 80.677 110.712 80.773 ;
     RECT  136.08 79.765 137.712 80.869 ;
     RECT  84.864 80.773 84.984 80.963 ;
     RECT  96.864 80.725 96.984 80.963 ;
     RECT  109.344 80.773 110.712 81.011 ;
     RECT  115.8 80.293 117.096 81.011 ;
     RECT  113.568 80.917 113.592 81.155 ;
     RECT  118.512 80.917 118.536 81.157 ;
     RECT  118.368 81.157 118.536 81.203 ;
     RECT  98.544 78.469 98.568 81.205 ;
     RECT  99.6 77.075 99.912 81.205 ;
     RECT  109.392 81.011 110.712 81.205 ;
     RECT  104.88 80.531 105.312 81.253 ;
     RECT  98.544 81.205 99.912 81.397 ;
     RECT  134.352 79.859 134.424 81.491 ;
     RECT  83.4 78.083 83.712 81.493 ;
     RECT  7.8 79.717 8.52 81.539 ;
     RECT  114.624 80.771 114.648 81.539 ;
     RECT  107.424 78.467 107.448 81.541 ;
     RECT  83.184 81.493 83.712 81.589 ;
     RECT  80.976 80.917 81 81.635 ;
     RECT  98.256 81.397 99.912 81.637 ;
     RECT  82.656 81.589 83.712 81.731 ;
     RECT  5.664 79.573 5.832 82.115 ;
     RECT  106.56 81.541 107.448 82.163 ;
     RECT  109.392 81.205 111.24 82.163 ;
     RECT  120.672 79.765 121.512 82.163 ;
     RECT  98.208 81.637 99.912 82.165 ;
     RECT  92.064 80.053 92.088 82.261 ;
     RECT  86.448 80.101 86.472 82.403 ;
     RECT  83.184 81.731 83.712 82.405 ;
     RECT  91.488 82.261 92.088 82.451 ;
     RECT  103.296 76.501 103.32 82.453 ;
     RECT  104.832 81.253 105.312 82.501 ;
     RECT  103.296 82.453 103.464 82.595 ;
     RECT  134.352 81.491 134.376 82.597 ;
     RECT  135.84 80.869 137.712 82.597 ;
     RECT  88.8 79.765 89.592 82.645 ;
     RECT  118.368 81.203 118.392 82.645 ;
     RECT  134.352 82.597 137.712 82.645 ;
     RECT  92.064 82.451 92.088 82.691 ;
     RECT  97.968 82.165 99.912 82.691 ;
     RECT  110.256 82.163 111.24 82.691 ;
     RECT  133.968 82.645 137.712 82.691 ;
     RECT  82.176 81.733 82.2 82.739 ;
     RECT  135.072 82.691 137.712 82.739 ;
     RECT  118.224 82.645 118.392 82.787 ;
     RECT  115.8 81.011 116.112 82.789 ;
     RECT  118.368 82.787 118.392 82.835 ;
     RECT  115.392 82.789 116.112 82.837 ;
     RECT  104.832 82.501 105.432 82.885 ;
     RECT  106.56 82.163 106.584 82.885 ;
     RECT  100.896 82.837 100.92 82.933 ;
     RECT  100.896 82.933 101.016 82.979 ;
     RECT  108.864 82.165 108.888 82.979 ;
     RECT  98.208 82.691 99.912 83.027 ;
     RECT  104.832 82.885 106.584 83.027 ;
     RECT  111.696 82.789 111.864 83.027 ;
     RECT  100.992 82.979 101.016 83.075 ;
     RECT  98.496 83.027 99.912 83.267 ;
     RECT  88.8 82.645 90.072 83.315 ;
     RECT  111.696 83.027 111.72 83.411 ;
     RECT  135.072 82.739 135.624 83.459 ;
     RECT  113.424 82.789 113.448 83.461 ;
     RECT  83.184 82.405 84.36 83.507 ;
     RECT  2.4 57.875 2.712 83.509 ;
     RECT  106.56 83.027 106.584 83.651 ;
     RECT  45.6 2.151 45.912 83.653 ;
     RECT  98.976 83.267 99.912 83.699 ;
     RECT  112.896 83.461 113.448 83.699 ;
     RECT  21.36 80.003 21.384 83.701 ;
     RECT  21.36 83.701 22.2 83.747 ;
     RECT  88.8 83.315 89.544 83.747 ;
     RECT  61.8 2.151 62.112 83.749 ;
     RECT  135.552 83.459 135.624 83.749 ;
     RECT  83.4 83.507 84.36 83.795 ;
     RECT  121.104 82.163 121.512 83.843 ;
     RECT  104.832 83.027 105.432 83.939 ;
     RECT  96.048 83.413 96.072 83.941 ;
     RECT  94.2 78.131 94.872 83.987 ;
     RECT  133.968 82.691 133.992 84.037 ;
     RECT  96.048 83.941 96.936 84.179 ;
     RECT  67.2 2.151 67.512 84.181 ;
     RECT  135.552 83.749 135.72 84.229 ;
     RECT  136.704 82.739 137.712 84.229 ;
     RECT  2.4 83.509 3.432 84.325 ;
     RECT  22.176 83.747 22.2 84.325 ;
     RECT  60.96 83.749 62.112 84.325 ;
     RECT  104.832 83.939 105.312 84.325 ;
     RECT  113.424 83.699 113.448 84.419 ;
     RECT  88.8 83.747 89.112 84.421 ;
     RECT  110.256 82.691 110.712 84.467 ;
     RECT  5.808 82.115 5.832 84.611 ;
     RECT  22.176 84.325 22.872 84.611 ;
     RECT  118.224 83.749 118.248 84.611 ;
     RECT  11.664 84.277 11.688 84.659 ;
     RECT  99.216 83.699 99.912 84.659 ;
     RECT  78 77.555 79.224 84.661 ;
     RECT  132 77.555 132.312 84.661 ;
     RECT  88.704 84.421 89.112 84.755 ;
     RECT  10.656 82.597 10.68 84.803 ;
     RECT  108.768 83.701 108.792 84.803 ;
     RECT  133.968 84.037 134.52 84.805 ;
     RECT  135.552 84.229 137.712 84.805 ;
     RECT  96.048 84.179 96.072 84.851 ;
     RECT  103.296 82.595 103.32 84.851 ;
     RECT  131.904 84.661 132.312 84.851 ;
     RECT  56.4 2.151 56.712 84.853 ;
     RECT  67.2 84.181 67.704 84.899 ;
     RECT  76.08 81.349 76.104 84.899 ;
     RECT  51 75.491 51.312 84.901 ;
     RECT  133.968 84.805 137.712 84.901 ;
     RECT  81.504 84.277 81.528 84.947 ;
     RECT  22.848 84.611 22.872 84.995 ;
     RECT  99.504 84.659 99.912 84.995 ;
     RECT  115.104 82.837 116.112 84.995 ;
     RECT  91.104 84.853 91.128 85.043 ;
     RECT  104.688 84.325 105.312 85.043 ;
     RECT  60.96 84.325 63 85.091 ;
     RECT  17.28 80.629 17.304 85.139 ;
     RECT  38.064 83.845 38.088 85.139 ;
     RECT  64.896 82.213 64.92 85.139 ;
     RECT  60.96 85.091 62.112 85.187 ;
     RECT  77.76 84.661 79.944 85.187 ;
     RECT  50.736 84.901 51.312 85.235 ;
     RECT  106.608 84.421 106.632 85.283 ;
     RECT  78 85.187 79.944 85.331 ;
     RECT  70.8 84.325 70.824 85.379 ;
     RECT  79.92 85.331 79.944 85.379 ;
     RECT  47.136 84.325 47.16 85.427 ;
     RECT  130.464 84.901 130.488 85.427 ;
     RECT  2.4 84.325 3.912 85.523 ;
     RECT  42.432 83.749 42.456 85.523 ;
     RECT  44.88 83.653 45.912 85.523 ;
     RECT  133.776 84.901 137.712 85.523 ;
     RECT  56.4 84.853 57 85.619 ;
     RECT  3.888 85.523 3.912 85.667 ;
     RECT  5.664 84.901 5.688 85.907 ;
     RECT  133.776 85.523 134.472 86.003 ;
     RECT  29.4 2.151 29.712 86.005 ;
     RECT  34.8 67.331 35.112 86.005 ;
     RECT  133.776 86.003 133.8 86.099 ;
     RECT  135.648 85.523 137.712 86.147 ;
     RECT  72.6 75.155 72.912 86.293 ;
     RECT  24 2.151 24.312 86.341 ;
     RECT  40.2 66.755 40.512 86.341 ;
     RECT  2.4 85.523 2.712 86.409 ;
     RECT  13.2 80.579 13.512 86.409 ;
     RECT  18.6 80.435 18.912 86.409 ;
     RECT  23.616 86.341 24.312 86.409 ;
     RECT  28.704 86.005 29.712 86.409 ;
     RECT  34.272 86.005 35.112 86.409 ;
     RECT  39.84 86.341 40.512 86.409 ;
     RECT  45.6 85.523 45.912 86.409 ;
     RECT  51 85.235 51.312 86.409 ;
     RECT  56.4 85.619 56.712 86.409 ;
     RECT  61.8 85.187 62.112 86.409 ;
     RECT  78 85.331 78.312 86.409 ;
     RECT  83.4 83.795 83.712 86.409 ;
     RECT  94.2 83.987 94.512 86.409 ;
     RECT  99.6 84.995 99.912 86.409 ;
     RECT  105 85.043 105.312 86.409 ;
     RECT  110.4 84.467 110.712 86.409 ;
     RECT  115.8 84.995 116.112 86.409 ;
     RECT  121.2 83.843 121.512 86.409 ;
     RECT  126.6 77.795 126.912 86.409 ;
     RECT  132 84.851 132.312 86.409 ;
     RECT  136.032 86.147 137.712 86.409 ;
     RECT  2.4 86.409 2.52 86.423 ;
     RECT  7.8 81.539 8.112 86.423 ;
     RECT  13.2 86.409 13.416 86.423 ;
     RECT  18.6 86.409 18.72 86.423 ;
     RECT  23.616 86.409 24.12 86.423 ;
     RECT  28.704 86.409 29.52 86.423 ;
     RECT  34.272 86.409 34.92 86.423 ;
     RECT  39.84 86.409 40.32 86.423 ;
     RECT  45.6 86.409 45.72 86.423 ;
     RECT  51 86.409 51.12 86.423 ;
     RECT  56.4 86.409 56.52 86.423 ;
     RECT  61.8 86.409 61.92 86.423 ;
     RECT  67.2 84.899 67.512 86.423 ;
     RECT  72.6 86.293 73.224 86.423 ;
     RECT  78 86.409 78.12 86.423 ;
     RECT  83.4 86.409 83.52 86.423 ;
     RECT  88.8 84.755 89.112 86.423 ;
     RECT  94.2 86.409 94.32 86.423 ;
     RECT  99.6 86.409 99.72 86.423 ;
     RECT  105 86.409 105.12 86.423 ;
     RECT  110.4 86.409 110.52 86.423 ;
     RECT  115.8 86.409 115.92 86.423 ;
     RECT  121.2 86.409 121.32 86.423 ;
     RECT  126.6 86.409 126.72 86.423 ;
     RECT  132 86.409 132.12 86.423 ;
     RECT  136.032 86.409 137.52 86.423 ;
     RECT  136.032 86.423 136.968 86.579 ;
     RECT  136.032 86.579 136.152 86.627 ;
     RECT  37.872 86.005 37.896 87.157 ;
     RECT  36.912 87.157 37.896 87.827 ;
     RECT  69.792 75.539 69.816 87.827 ;
     RECT  8.256 86.581 8.28 88.405 ;
     RECT  18.48 86.485 18.504 88.405 ;
     RECT  23.616 86.423 23.64 88.405 ;
     RECT  28.704 86.423 28.728 88.405 ;
     RECT  31.488 86.581 31.512 88.405 ;
     RECT  39.84 86.423 39.864 88.405 ;
     RECT  44.544 86.581 44.568 88.405 ;
     RECT  49.776 86.341 49.8 88.405 ;
     RECT  52.656 86.581 52.68 88.405 ;
     RECT  54.96 86.293 54.984 88.405 ;
     RECT  60.144 86.293 60.168 88.405 ;
     RECT  65.712 86.581 65.736 88.405 ;
     RECT  73.2 86.423 73.224 88.405 ;
     RECT  75.888 86.581 75.912 88.405 ;
     RECT  8.16 88.405 8.28 88.451 ;
     RECT  18.48 88.405 18.648 88.451 ;
     RECT  23.616 88.405 23.88 88.451 ;
     RECT  28.704 88.405 29.064 88.451 ;
     RECT  31.488 88.405 31.704 88.451 ;
     RECT  39.504 88.405 39.864 88.451 ;
     RECT  44.544 88.405 44.76 88.451 ;
     RECT  49.776 88.405 49.992 88.451 ;
     RECT  52.56 88.405 52.68 88.451 ;
     RECT  54.96 88.405 55.176 88.451 ;
     RECT  60.144 88.405 60.408 88.451 ;
     RECT  65.616 88.405 65.736 88.451 ;
     RECT  73.2 88.405 73.464 88.451 ;
     RECT  75.888 88.405 76.104 88.451 ;
     RECT  2.928 87.781 2.952 88.528 ;
     RECT  5.568 87.157 5.592 88.528 ;
     RECT  8.16 88.451 8.184 88.528 ;
     RECT  10.8 86.629 10.824 88.528 ;
     RECT  13.392 86.423 13.416 88.528 ;
     RECT  15.984 87.781 16.008 88.528 ;
     RECT  18.624 88.451 18.648 88.528 ;
     RECT  21.216 87.781 21.24 88.528 ;
     RECT  23.856 88.451 23.88 88.528 ;
     RECT  26.448 87.781 26.472 88.528 ;
     RECT  29.04 88.451 29.064 88.528 ;
     RECT  31.68 88.451 31.704 88.528 ;
     RECT  34.272 86.423 34.296 88.528 ;
     RECT  36.912 87.827 36.936 88.528 ;
     RECT  39.504 88.451 39.528 88.528 ;
     RECT  42.096 86.005 42.12 88.528 ;
     RECT  44.736 88.451 44.76 88.528 ;
     RECT  47.328 87.781 47.352 88.528 ;
     RECT  49.968 88.451 49.992 88.528 ;
     RECT  52.56 88.451 52.584 88.528 ;
     RECT  55.152 88.451 55.176 88.528 ;
     RECT  57.792 87.781 57.816 88.528 ;
     RECT  60.384 88.451 60.408 88.528 ;
     RECT  63.024 87.157 63.048 88.528 ;
     RECT  65.616 88.451 65.64 88.528 ;
     RECT  68.208 87.157 68.232 88.528 ;
     RECT  70.848 87.781 70.872 88.528 ;
     RECT  73.44 88.451 73.464 88.528 ;
     RECT  76.08 88.451 76.104 88.528 ;
     RECT  78.672 87.781 78.696 88.528 ;
     RECT  81.264 86.581 81.288 88.528 ;
     RECT  83.904 87.781 83.928 88.528 ;
     RECT  86.496 86.245 86.52 88.528 ;
     RECT  89.136 87.061 89.16 88.528 ;
     RECT  91.728 87.157 91.752 88.528 ;
     RECT  94.32 88.405 94.344 88.528 ;
     RECT  96.96 88.405 96.984 88.528 ;
     RECT  99.552 87.157 99.576 88.528 ;
     RECT  102.192 87.157 102.216 88.528 ;
     RECT  104.784 86.485 104.808 88.528 ;
     RECT  107.376 87.733 107.4 88.528 ;
     RECT  110.016 87.157 110.04 88.528 ;
     RECT  112.608 87.157 112.632 88.528 ;
     RECT  115.248 86.629 115.272 88.528 ;
     RECT  117.84 87.157 117.864 88.528 ;
     RECT  120.48 87.157 120.504 88.528 ;
     RECT  123.072 85.477 123.096 88.528 ;
     RECT  125.664 87.157 125.688 88.528 ;
     RECT  128.304 86.629 128.328 88.528 ;
     RECT  130.896 86.629 130.92 88.528 ;
     RECT  133.536 87.733 133.56 88.528 ;
     RECT  136.128 86.627 136.152 88.528 ;
     RECT  138.72 85.429 138.744 88.528 ;
  END
END qkd_static_kv_landing_lane
END LIBRARY
